VERSION 5.8 ;
BUSBITCHARS "[]" ;
DIVIDERCHAR "/" ;
UNITS
    DATABASE MICRONS 1000 ;
END UNITS

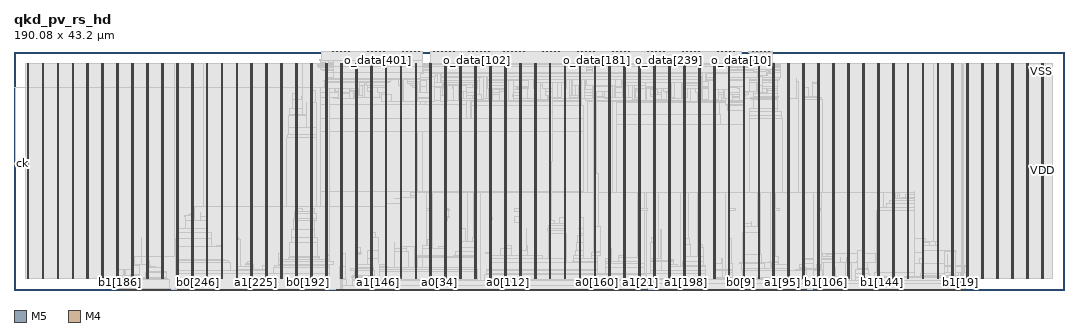
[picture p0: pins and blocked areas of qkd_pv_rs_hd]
MACRO qkd_pv_rs_hd
  FOREIGN qkd_pv_rs_hd 0 0 ;
  CLASS BLOCK ;
  SIZE 190.08 BY 43.2 ;
  PIN a0[0]
    DIRECTION INPUT ;
    USE SIGNAL ;
    PORT
      LAYER M5 ;
        RECT  58.32 0 58.344 0.084 ;
    END
  END a0[0]
  PIN a0[100]
    DIRECTION INPUT ;
    USE SIGNAL ;
    PORT
      LAYER M5 ;
        RECT  87.696 0 87.72 0.084 ;
    END
  END a0[100]
  PIN a0[101]
    DIRECTION INPUT ;
    USE SIGNAL ;
    PORT
      LAYER M5 ;
        RECT  87.84 0 87.864 0.084 ;
    END
  END a0[101]
  PIN a0[102]
    DIRECTION INPUT ;
    USE SIGNAL ;
    PORT
      LAYER M5 ;
        RECT  87.984 0 88.008 0.084 ;
    END
  END a0[102]
  PIN a0[103]
    DIRECTION INPUT ;
    USE SIGNAL ;
    PORT
      LAYER M5 ;
        RECT  88.128 0 88.152 0.084 ;
    END
  END a0[103]
  PIN a0[104]
    DIRECTION INPUT ;
    USE SIGNAL ;
    PORT
      LAYER M5 ;
        RECT  88.272 0 88.296 0.084 ;
    END
  END a0[104]
  PIN a0[105]
    DIRECTION INPUT ;
    USE SIGNAL ;
    PORT
      LAYER M5 ;
        RECT  88.416 0 88.44 0.084 ;
    END
  END a0[105]
  PIN a0[106]
    DIRECTION INPUT ;
    USE SIGNAL ;
    PORT
      LAYER M5 ;
        RECT  88.56 0 88.584 0.084 ;
    END
  END a0[106]
  PIN a0[107]
    DIRECTION INPUT ;
    USE SIGNAL ;
    PORT
      LAYER M5 ;
        RECT  88.704 0 88.728 0.084 ;
    END
  END a0[107]
  PIN a0[108]
    DIRECTION INPUT ;
    USE SIGNAL ;
    PORT
      LAYER M5 ;
        RECT  88.848 0 88.872 0.084 ;
    END
  END a0[108]
  PIN a0[109]
    DIRECTION INPUT ;
    USE SIGNAL ;
    PORT
      LAYER M5 ;
        RECT  88.992 0 89.016 0.084 ;
    END
  END a0[109]
  PIN a0[10]
    DIRECTION INPUT ;
    USE SIGNAL ;
    PORT
      LAYER M5 ;
        RECT  59.76 0 59.784 0.084 ;
    END
  END a0[10]
  PIN a0[110]
    DIRECTION INPUT ;
    USE SIGNAL ;
    PORT
      LAYER M5 ;
        RECT  89.136 0 89.16 0.084 ;
    END
  END a0[110]
  PIN a0[111]
    DIRECTION INPUT ;
    USE SIGNAL ;
    PORT
      LAYER M5 ;
        RECT  89.28 0 89.304 0.084 ;
    END
  END a0[111]
  PIN a0[112]
    DIRECTION INPUT ;
    USE SIGNAL ;
    PORT
      LAYER M5 ;
        RECT  89.424 0 89.448 0.084 ;
    END
  END a0[112]
  PIN a0[113]
    DIRECTION INPUT ;
    USE SIGNAL ;
    PORT
      LAYER M5 ;
        RECT  89.568 0 89.592 0.084 ;
    END
  END a0[113]
  PIN a0[114]
    DIRECTION INPUT ;
    USE SIGNAL ;
    PORT
      LAYER M5 ;
        RECT  89.712 0 89.736 0.084 ;
    END
  END a0[114]
  PIN a0[115]
    DIRECTION INPUT ;
    USE SIGNAL ;
    PORT
      LAYER M5 ;
        RECT  89.856 0 89.88 0.084 ;
    END
  END a0[115]
  PIN a0[116]
    DIRECTION INPUT ;
    USE SIGNAL ;
    PORT
      LAYER M5 ;
        RECT  90 0 90.024 0.084 ;
    END
  END a0[116]
  PIN a0[117]
    DIRECTION INPUT ;
    USE SIGNAL ;
    PORT
      LAYER M5 ;
        RECT  90.144 0 90.168 0.084 ;
    END
  END a0[117]
  PIN a0[118]
    DIRECTION INPUT ;
    USE SIGNAL ;
    PORT
      LAYER M5 ;
        RECT  90.288 0 90.312 0.084 ;
    END
  END a0[118]
  PIN a0[119]
    DIRECTION INPUT ;
    USE SIGNAL ;
    PORT
      LAYER M5 ;
        RECT  90.432 0 90.456 0.084 ;
    END
  END a0[119]
  PIN a0[11]
    DIRECTION INPUT ;
    USE SIGNAL ;
    PORT
      LAYER M5 ;
        RECT  59.904 0 59.928 0.084 ;
    END
  END a0[11]
  PIN a0[120]
    DIRECTION INPUT ;
    USE SIGNAL ;
    PORT
      LAYER M5 ;
        RECT  90.576 0 90.6 0.084 ;
    END
  END a0[120]
  PIN a0[121]
    DIRECTION INPUT ;
    USE SIGNAL ;
    PORT
      LAYER M5 ;
        RECT  90.72 0 90.744 0.084 ;
    END
  END a0[121]
  PIN a0[122]
    DIRECTION INPUT ;
    USE SIGNAL ;
    PORT
      LAYER M5 ;
        RECT  90.864 0 90.888 0.084 ;
    END
  END a0[122]
  PIN a0[123]
    DIRECTION INPUT ;
    USE SIGNAL ;
    PORT
      LAYER M5 ;
        RECT  91.008 0 91.032 0.084 ;
    END
  END a0[123]
  PIN a0[124]
    DIRECTION INPUT ;
    USE SIGNAL ;
    PORT
      LAYER M5 ;
        RECT  91.152 0 91.176 0.084 ;
    END
  END a0[124]
  PIN a0[125]
    DIRECTION INPUT ;
    USE SIGNAL ;
    PORT
      LAYER M5 ;
        RECT  91.296 0 91.32 0.084 ;
    END
  END a0[125]
  PIN a0[126]
    DIRECTION INPUT ;
    USE SIGNAL ;
    PORT
      LAYER M5 ;
        RECT  91.44 0 91.464 0.084 ;
    END
  END a0[126]
  PIN a0[127]
    DIRECTION INPUT ;
    USE SIGNAL ;
    PORT
      LAYER M5 ;
        RECT  91.584 0 91.608 0.084 ;
    END
  END a0[127]
  PIN a0[128]
    DIRECTION INPUT ;
    USE SIGNAL ;
    PORT
      LAYER M5 ;
        RECT  91.728 0 91.752 0.084 ;
    END
  END a0[128]
  PIN a0[129]
    DIRECTION INPUT ;
    USE SIGNAL ;
    PORT
      LAYER M5 ;
        RECT  91.872 0 91.896 0.084 ;
    END
  END a0[129]
  PIN a0[12]
    DIRECTION INPUT ;
    USE SIGNAL ;
    PORT
      LAYER M5 ;
        RECT  60.048 0 60.072 0.084 ;
    END
  END a0[12]
  PIN a0[130]
    DIRECTION INPUT ;
    USE SIGNAL ;
    PORT
      LAYER M5 ;
        RECT  92.016 0 92.04 0.084 ;
    END
  END a0[130]
  PIN a0[131]
    DIRECTION INPUT ;
    USE SIGNAL ;
    PORT
      LAYER M5 ;
        RECT  92.16 0 92.184 0.084 ;
    END
  END a0[131]
  PIN a0[132]
    DIRECTION INPUT ;
    USE SIGNAL ;
    PORT
      LAYER M5 ;
        RECT  92.304 0 92.328 0.084 ;
    END
  END a0[132]
  PIN a0[133]
    DIRECTION INPUT ;
    USE SIGNAL ;
    PORT
      LAYER M5 ;
        RECT  92.448 0 92.472 0.084 ;
    END
  END a0[133]
  PIN a0[134]
    DIRECTION INPUT ;
    USE SIGNAL ;
    PORT
      LAYER M5 ;
        RECT  92.592 0 92.616 0.084 ;
    END
  END a0[134]
  PIN a0[135]
    DIRECTION INPUT ;
    USE SIGNAL ;
    PORT
      LAYER M5 ;
        RECT  92.736 0 92.76 0.084 ;
    END
  END a0[135]
  PIN a0[136]
    DIRECTION INPUT ;
    USE SIGNAL ;
    PORT
      LAYER M5 ;
        RECT  92.88 0 92.904 0.084 ;
    END
  END a0[136]
  PIN a0[137]
    DIRECTION INPUT ;
    USE SIGNAL ;
    PORT
      LAYER M5 ;
        RECT  93.024 0 93.048 0.084 ;
    END
  END a0[137]
  PIN a0[138]
    DIRECTION INPUT ;
    USE SIGNAL ;
    PORT
      LAYER M5 ;
        RECT  93.168 0 93.192 0.084 ;
    END
  END a0[138]
  PIN a0[139]
    DIRECTION INPUT ;
    USE SIGNAL ;
    PORT
      LAYER M5 ;
        RECT  93.312 0 93.336 0.084 ;
    END
  END a0[139]
  PIN a0[13]
    DIRECTION INPUT ;
    USE SIGNAL ;
    PORT
      LAYER M5 ;
        RECT  60.192 0 60.216 0.084 ;
    END
  END a0[13]
  PIN a0[140]
    DIRECTION INPUT ;
    USE SIGNAL ;
    PORT
      LAYER M5 ;
        RECT  93.456 0 93.48 0.084 ;
    END
  END a0[140]
  PIN a0[141]
    DIRECTION INPUT ;
    USE SIGNAL ;
    PORT
      LAYER M5 ;
        RECT  93.6 0 93.624 0.084 ;
    END
  END a0[141]
  PIN a0[142]
    DIRECTION INPUT ;
    USE SIGNAL ;
    PORT
      LAYER M5 ;
        RECT  93.744 0 93.768 0.084 ;
    END
  END a0[142]
  PIN a0[143]
    DIRECTION INPUT ;
    USE SIGNAL ;
    PORT
      LAYER M5 ;
        RECT  93.888 0 93.912 0.084 ;
    END
  END a0[143]
  PIN a0[144]
    DIRECTION INPUT ;
    USE SIGNAL ;
    PORT
      LAYER M5 ;
        RECT  94.032 0 94.056 0.084 ;
    END
  END a0[144]
  PIN a0[145]
    DIRECTION INPUT ;
    USE SIGNAL ;
    PORT
      LAYER M5 ;
        RECT  94.176 0 94.2 0.084 ;
    END
  END a0[145]
  PIN a0[146]
    DIRECTION INPUT ;
    USE SIGNAL ;
    PORT
      LAYER M5 ;
        RECT  94.32 0 94.344 0.084 ;
    END
  END a0[146]
  PIN a0[147]
    DIRECTION INPUT ;
    USE SIGNAL ;
    PORT
      LAYER M5 ;
        RECT  94.464 0 94.488 0.084 ;
    END
  END a0[147]
  PIN a0[148]
    DIRECTION INPUT ;
    USE SIGNAL ;
    PORT
      LAYER M5 ;
        RECT  94.608 0 94.632 0.084 ;
    END
  END a0[148]
  PIN a0[149]
    DIRECTION INPUT ;
    USE SIGNAL ;
    PORT
      LAYER M5 ;
        RECT  94.752 0 94.776 0.084 ;
    END
  END a0[149]
  PIN a0[14]
    DIRECTION INPUT ;
    USE SIGNAL ;
    PORT
      LAYER M5 ;
        RECT  60.336 0 60.36 0.084 ;
    END
  END a0[14]
  PIN a0[150]
    DIRECTION INPUT ;
    USE SIGNAL ;
    PORT
      LAYER M5 ;
        RECT  94.896 0 94.92 0.084 ;
    END
  END a0[150]
  PIN a0[151]
    DIRECTION INPUT ;
    USE SIGNAL ;
    PORT
      LAYER M5 ;
        RECT  95.04 0 95.064 0.084 ;
    END
  END a0[151]
  PIN a0[152]
    DIRECTION INPUT ;
    USE SIGNAL ;
    PORT
      LAYER M5 ;
        RECT  95.184 0 95.208 0.084 ;
    END
  END a0[152]
  PIN a0[153]
    DIRECTION INPUT ;
    USE SIGNAL ;
    PORT
      LAYER M5 ;
        RECT  95.328 0 95.352 0.084 ;
    END
  END a0[153]
  PIN a0[154]
    DIRECTION INPUT ;
    USE SIGNAL ;
    PORT
      LAYER M5 ;
        RECT  95.472 0 95.496 0.084 ;
    END
  END a0[154]
  PIN a0[155]
    DIRECTION INPUT ;
    USE SIGNAL ;
    PORT
      LAYER M5 ;
        RECT  95.616 0 95.64 0.084 ;
    END
  END a0[155]
  PIN a0[156]
    DIRECTION INPUT ;
    USE SIGNAL ;
    PORT
      LAYER M5 ;
        RECT  95.76 0 95.784 0.084 ;
    END
  END a0[156]
  PIN a0[157]
    DIRECTION INPUT ;
    USE SIGNAL ;
    PORT
      LAYER M5 ;
        RECT  95.904 0 95.928 0.084 ;
    END
  END a0[157]
  PIN a0[158]
    DIRECTION INPUT ;
    USE SIGNAL ;
    PORT
      LAYER M5 ;
        RECT  96.048 0 96.072 0.084 ;
    END
  END a0[158]
  PIN a0[159]
    DIRECTION INPUT ;
    USE SIGNAL ;
    PORT
      LAYER M5 ;
        RECT  96.192 0 96.216 0.084 ;
    END
  END a0[159]
  PIN a0[15]
    DIRECTION INPUT ;
    USE SIGNAL ;
    PORT
      LAYER M5 ;
        RECT  60.48 0 60.504 0.084 ;
    END
  END a0[15]
  PIN a0[160]
    DIRECTION INPUT ;
    USE SIGNAL ;
    PORT
      LAYER M5 ;
        RECT  105.552 0 105.576 0.084 ;
    END
  END a0[160]
  PIN a0[161]
    DIRECTION INPUT ;
    USE SIGNAL ;
    PORT
      LAYER M5 ;
        RECT  105.696 0 105.72 0.084 ;
    END
  END a0[161]
  PIN a0[162]
    DIRECTION INPUT ;
    USE SIGNAL ;
    PORT
      LAYER M5 ;
        RECT  105.84 0 105.864 0.084 ;
    END
  END a0[162]
  PIN a0[163]
    DIRECTION INPUT ;
    USE SIGNAL ;
    PORT
      LAYER M5 ;
        RECT  105.984 0 106.008 0.084 ;
    END
  END a0[163]
  PIN a0[164]
    DIRECTION INPUT ;
    USE SIGNAL ;
    PORT
      LAYER M5 ;
        RECT  106.128 0 106.152 0.084 ;
    END
  END a0[164]
  PIN a0[165]
    DIRECTION INPUT ;
    USE SIGNAL ;
    PORT
      LAYER M5 ;
        RECT  106.272 0 106.296 0.084 ;
    END
  END a0[165]
  PIN a0[166]
    DIRECTION INPUT ;
    USE SIGNAL ;
    PORT
      LAYER M5 ;
        RECT  106.416 0 106.44 0.084 ;
    END
  END a0[166]
  PIN a0[167]
    DIRECTION INPUT ;
    USE SIGNAL ;
    PORT
      LAYER M5 ;
        RECT  106.56 0 106.584 0.084 ;
    END
  END a0[167]
  PIN a0[168]
    DIRECTION INPUT ;
    USE SIGNAL ;
    PORT
      LAYER M5 ;
        RECT  106.704 0 106.728 0.084 ;
    END
  END a0[168]
  PIN a0[169]
    DIRECTION INPUT ;
    USE SIGNAL ;
    PORT
      LAYER M5 ;
        RECT  106.848 0 106.872 0.084 ;
    END
  END a0[169]
  PIN a0[16]
    DIRECTION INPUT ;
    USE SIGNAL ;
    PORT
      LAYER M5 ;
        RECT  60.624 0 60.648 0.084 ;
    END
  END a0[16]
  PIN a0[170]
    DIRECTION INPUT ;
    USE SIGNAL ;
    PORT
      LAYER M5 ;
        RECT  106.992 0 107.016 0.084 ;
    END
  END a0[170]
  PIN a0[171]
    DIRECTION INPUT ;
    USE SIGNAL ;
    PORT
      LAYER M5 ;
        RECT  107.136 0 107.16 0.084 ;
    END
  END a0[171]
  PIN a0[172]
    DIRECTION INPUT ;
    USE SIGNAL ;
    PORT
      LAYER M5 ;
        RECT  107.28 0 107.304 0.084 ;
    END
  END a0[172]
  PIN a0[173]
    DIRECTION INPUT ;
    USE SIGNAL ;
    PORT
      LAYER M5 ;
        RECT  107.424 0 107.448 0.084 ;
    END
  END a0[173]
  PIN a0[174]
    DIRECTION INPUT ;
    USE SIGNAL ;
    PORT
      LAYER M5 ;
        RECT  107.568 0 107.592 0.084 ;
    END
  END a0[174]
  PIN a0[175]
    DIRECTION INPUT ;
    USE SIGNAL ;
    PORT
      LAYER M5 ;
        RECT  107.712 0 107.736 0.084 ;
    END
  END a0[175]
  PIN a0[176]
    DIRECTION INPUT ;
    USE SIGNAL ;
    PORT
      LAYER M5 ;
        RECT  107.856 0 107.88 0.084 ;
    END
  END a0[176]
  PIN a0[177]
    DIRECTION INPUT ;
    USE SIGNAL ;
    PORT
      LAYER M5 ;
        RECT  108 0 108.024 0.084 ;
    END
  END a0[177]
  PIN a0[178]
    DIRECTION INPUT ;
    USE SIGNAL ;
    PORT
      LAYER M5 ;
        RECT  108.144 0 108.168 0.084 ;
    END
  END a0[178]
  PIN a0[179]
    DIRECTION INPUT ;
    USE SIGNAL ;
    PORT
      LAYER M5 ;
        RECT  108.288 0 108.312 0.084 ;
    END
  END a0[179]
  PIN a0[17]
    DIRECTION INPUT ;
    USE SIGNAL ;
    PORT
      LAYER M5 ;
        RECT  60.768 0 60.792 0.084 ;
    END
  END a0[17]
  PIN a0[180]
    DIRECTION INPUT ;
    USE SIGNAL ;
    PORT
      LAYER M5 ;
        RECT  108.432 0 108.456 0.084 ;
    END
  END a0[180]
  PIN a0[181]
    DIRECTION INPUT ;
    USE SIGNAL ;
    PORT
      LAYER M5 ;
        RECT  108.576 0 108.6 0.084 ;
    END
  END a0[181]
  PIN a0[182]
    DIRECTION INPUT ;
    USE SIGNAL ;
    PORT
      LAYER M5 ;
        RECT  108.72 0 108.744 0.084 ;
    END
  END a0[182]
  PIN a0[183]
    DIRECTION INPUT ;
    USE SIGNAL ;
    PORT
      LAYER M5 ;
        RECT  108.864 0 108.888 0.084 ;
    END
  END a0[183]
  PIN a0[184]
    DIRECTION INPUT ;
    USE SIGNAL ;
    PORT
      LAYER M5 ;
        RECT  109.008 0 109.032 0.084 ;
    END
  END a0[184]
  PIN a0[185]
    DIRECTION INPUT ;
    USE SIGNAL ;
    PORT
      LAYER M5 ;
        RECT  109.152 0 109.176 0.084 ;
    END
  END a0[185]
  PIN a0[186]
    DIRECTION INPUT ;
    USE SIGNAL ;
    PORT
      LAYER M5 ;
        RECT  109.296 0 109.32 0.084 ;
    END
  END a0[186]
  PIN a0[187]
    DIRECTION INPUT ;
    USE SIGNAL ;
    PORT
      LAYER M5 ;
        RECT  109.44 0 109.464 0.084 ;
    END
  END a0[187]
  PIN a0[188]
    DIRECTION INPUT ;
    USE SIGNAL ;
    PORT
      LAYER M5 ;
        RECT  109.584 0 109.608 0.084 ;
    END
  END a0[188]
  PIN a0[189]
    DIRECTION INPUT ;
    USE SIGNAL ;
    PORT
      LAYER M5 ;
        RECT  109.728 0 109.752 0.084 ;
    END
  END a0[189]
  PIN a0[18]
    DIRECTION INPUT ;
    USE SIGNAL ;
    PORT
      LAYER M5 ;
        RECT  60.912 0 60.936 0.084 ;
    END
  END a0[18]
  PIN a0[190]
    DIRECTION INPUT ;
    USE SIGNAL ;
    PORT
      LAYER M5 ;
        RECT  109.872 0 109.896 0.084 ;
    END
  END a0[190]
  PIN a0[191]
    DIRECTION INPUT ;
    USE SIGNAL ;
    PORT
      LAYER M5 ;
        RECT  110.016 0 110.04 0.084 ;
    END
  END a0[191]
  PIN a0[192]
    DIRECTION INPUT ;
    USE SIGNAL ;
    PORT
      LAYER M5 ;
        RECT  100.944 0 100.968 0.084 ;
    END
  END a0[192]
  PIN a0[193]
    DIRECTION INPUT ;
    USE SIGNAL ;
    PORT
      LAYER M5 ;
        RECT  101.088 0 101.112 0.084 ;
    END
  END a0[193]
  PIN a0[194]
    DIRECTION INPUT ;
    USE SIGNAL ;
    PORT
      LAYER M5 ;
        RECT  101.232 0 101.256 0.084 ;
    END
  END a0[194]
  PIN a0[195]
    DIRECTION INPUT ;
    USE SIGNAL ;
    PORT
      LAYER M5 ;
        RECT  101.376 0 101.4 0.084 ;
    END
  END a0[195]
  PIN a0[196]
    DIRECTION INPUT ;
    USE SIGNAL ;
    PORT
      LAYER M5 ;
        RECT  101.52 0 101.544 0.084 ;
    END
  END a0[196]
  PIN a0[197]
    DIRECTION INPUT ;
    USE SIGNAL ;
    PORT
      LAYER M5 ;
        RECT  101.664 0 101.688 0.084 ;
    END
  END a0[197]
  PIN a0[198]
    DIRECTION INPUT ;
    USE SIGNAL ;
    PORT
      LAYER M5 ;
        RECT  101.808 0 101.832 0.084 ;
    END
  END a0[198]
  PIN a0[199]
    DIRECTION INPUT ;
    USE SIGNAL ;
    PORT
      LAYER M5 ;
        RECT  101.952 0 101.976 0.084 ;
    END
  END a0[199]
  PIN a0[19]
    DIRECTION INPUT ;
    USE SIGNAL ;
    PORT
      LAYER M5 ;
        RECT  61.056 0 61.08 0.084 ;
    END
  END a0[19]
  PIN a0[1]
    DIRECTION INPUT ;
    USE SIGNAL ;
    PORT
      LAYER M5 ;
        RECT  58.464 0 58.488 0.084 ;
    END
  END a0[1]
  PIN a0[200]
    DIRECTION INPUT ;
    USE SIGNAL ;
    PORT
      LAYER M5 ;
        RECT  102.096 0 102.12 0.084 ;
    END
  END a0[200]
  PIN a0[201]
    DIRECTION INPUT ;
    USE SIGNAL ;
    PORT
      LAYER M5 ;
        RECT  102.24 0 102.264 0.084 ;
    END
  END a0[201]
  PIN a0[202]
    DIRECTION INPUT ;
    USE SIGNAL ;
    PORT
      LAYER M5 ;
        RECT  102.384 0 102.408 0.084 ;
    END
  END a0[202]
  PIN a0[203]
    DIRECTION INPUT ;
    USE SIGNAL ;
    PORT
      LAYER M5 ;
        RECT  102.528 0 102.552 0.084 ;
    END
  END a0[203]
  PIN a0[204]
    DIRECTION INPUT ;
    USE SIGNAL ;
    PORT
      LAYER M5 ;
        RECT  102.672 0 102.696 0.084 ;
    END
  END a0[204]
  PIN a0[205]
    DIRECTION INPUT ;
    USE SIGNAL ;
    PORT
      LAYER M5 ;
        RECT  102.816 0 102.84 0.084 ;
    END
  END a0[205]
  PIN a0[206]
    DIRECTION INPUT ;
    USE SIGNAL ;
    PORT
      LAYER M5 ;
        RECT  102.96 0 102.984 0.084 ;
    END
  END a0[206]
  PIN a0[207]
    DIRECTION INPUT ;
    USE SIGNAL ;
    PORT
      LAYER M5 ;
        RECT  103.104 0 103.128 0.084 ;
    END
  END a0[207]
  PIN a0[208]
    DIRECTION INPUT ;
    USE SIGNAL ;
    PORT
      LAYER M5 ;
        RECT  103.248 0 103.272 0.084 ;
    END
  END a0[208]
  PIN a0[209]
    DIRECTION INPUT ;
    USE SIGNAL ;
    PORT
      LAYER M5 ;
        RECT  103.392 0 103.416 0.084 ;
    END
  END a0[209]
  PIN a0[20]
    DIRECTION INPUT ;
    USE SIGNAL ;
    PORT
      LAYER M5 ;
        RECT  61.2 0 61.224 0.084 ;
    END
  END a0[20]
  PIN a0[210]
    DIRECTION INPUT ;
    USE SIGNAL ;
    PORT
      LAYER M5 ;
        RECT  103.536 0 103.56 0.084 ;
    END
  END a0[210]
  PIN a0[211]
    DIRECTION INPUT ;
    USE SIGNAL ;
    PORT
      LAYER M5 ;
        RECT  103.68 0 103.704 0.084 ;
    END
  END a0[211]
  PIN a0[212]
    DIRECTION INPUT ;
    USE SIGNAL ;
    PORT
      LAYER M5 ;
        RECT  103.824 0 103.848 0.084 ;
    END
  END a0[212]
  PIN a0[213]
    DIRECTION INPUT ;
    USE SIGNAL ;
    PORT
      LAYER M5 ;
        RECT  103.968 0 103.992 0.084 ;
    END
  END a0[213]
  PIN a0[214]
    DIRECTION INPUT ;
    USE SIGNAL ;
    PORT
      LAYER M5 ;
        RECT  104.112 0 104.136 0.084 ;
    END
  END a0[214]
  PIN a0[215]
    DIRECTION INPUT ;
    USE SIGNAL ;
    PORT
      LAYER M5 ;
        RECT  104.256 0 104.28 0.084 ;
    END
  END a0[215]
  PIN a0[216]
    DIRECTION INPUT ;
    USE SIGNAL ;
    PORT
      LAYER M5 ;
        RECT  104.4 0 104.424 0.084 ;
    END
  END a0[216]
  PIN a0[217]
    DIRECTION INPUT ;
    USE SIGNAL ;
    PORT
      LAYER M5 ;
        RECT  104.544 0 104.568 0.084 ;
    END
  END a0[217]
  PIN a0[218]
    DIRECTION INPUT ;
    USE SIGNAL ;
    PORT
      LAYER M5 ;
        RECT  104.688 0 104.712 0.084 ;
    END
  END a0[218]
  PIN a0[219]
    DIRECTION INPUT ;
    USE SIGNAL ;
    PORT
      LAYER M5 ;
        RECT  104.832 0 104.856 0.084 ;
    END
  END a0[219]
  PIN a0[21]
    DIRECTION INPUT ;
    USE SIGNAL ;
    PORT
      LAYER M5 ;
        RECT  61.344 0 61.368 0.084 ;
    END
  END a0[21]
  PIN a0[220]
    DIRECTION INPUT ;
    USE SIGNAL ;
    PORT
      LAYER M5 ;
        RECT  104.976 0 105 0.084 ;
    END
  END a0[220]
  PIN a0[221]
    DIRECTION INPUT ;
    USE SIGNAL ;
    PORT
      LAYER M5 ;
        RECT  105.12 0 105.144 0.084 ;
    END
  END a0[221]
  PIN a0[222]
    DIRECTION INPUT ;
    USE SIGNAL ;
    PORT
      LAYER M5 ;
        RECT  105.264 0 105.288 0.084 ;
    END
  END a0[222]
  PIN a0[223]
    DIRECTION INPUT ;
    USE SIGNAL ;
    PORT
      LAYER M5 ;
        RECT  105.408 0 105.432 0.084 ;
    END
  END a0[223]
  PIN a0[224]
    DIRECTION INPUT ;
    USE SIGNAL ;
    PORT
      LAYER M5 ;
        RECT  96.336 0 96.36 0.084 ;
    END
  END a0[224]
  PIN a0[225]
    DIRECTION INPUT ;
    USE SIGNAL ;
    PORT
      LAYER M5 ;
        RECT  96.48 0 96.504 0.084 ;
    END
  END a0[225]
  PIN a0[226]
    DIRECTION INPUT ;
    USE SIGNAL ;
    PORT
      LAYER M5 ;
        RECT  96.624 0 96.648 0.084 ;
    END
  END a0[226]
  PIN a0[227]
    DIRECTION INPUT ;
    USE SIGNAL ;
    PORT
      LAYER M5 ;
        RECT  96.768 0 96.792 0.084 ;
    END
  END a0[227]
  PIN a0[228]
    DIRECTION INPUT ;
    USE SIGNAL ;
    PORT
      LAYER M5 ;
        RECT  96.912 0 96.936 0.084 ;
    END
  END a0[228]
  PIN a0[229]
    DIRECTION INPUT ;
    USE SIGNAL ;
    PORT
      LAYER M5 ;
        RECT  97.056 0 97.08 0.084 ;
    END
  END a0[229]
  PIN a0[22]
    DIRECTION INPUT ;
    USE SIGNAL ;
    PORT
      LAYER M5 ;
        RECT  61.488 0 61.512 0.084 ;
    END
  END a0[22]
  PIN a0[230]
    DIRECTION INPUT ;
    USE SIGNAL ;
    PORT
      LAYER M5 ;
        RECT  97.2 0 97.224 0.084 ;
    END
  END a0[230]
  PIN a0[231]
    DIRECTION INPUT ;
    USE SIGNAL ;
    PORT
      LAYER M5 ;
        RECT  97.344 0 97.368 0.084 ;
    END
  END a0[231]
  PIN a0[232]
    DIRECTION INPUT ;
    USE SIGNAL ;
    PORT
      LAYER M5 ;
        RECT  97.488 0 97.512 0.084 ;
    END
  END a0[232]
  PIN a0[233]
    DIRECTION INPUT ;
    USE SIGNAL ;
    PORT
      LAYER M5 ;
        RECT  97.632 0 97.656 0.084 ;
    END
  END a0[233]
  PIN a0[234]
    DIRECTION INPUT ;
    USE SIGNAL ;
    PORT
      LAYER M5 ;
        RECT  97.776 0 97.8 0.084 ;
    END
  END a0[234]
  PIN a0[235]
    DIRECTION INPUT ;
    USE SIGNAL ;
    PORT
      LAYER M5 ;
        RECT  97.92 0 97.944 0.084 ;
    END
  END a0[235]
  PIN a0[236]
    DIRECTION INPUT ;
    USE SIGNAL ;
    PORT
      LAYER M5 ;
        RECT  98.064 0 98.088 0.084 ;
    END
  END a0[236]
  PIN a0[237]
    DIRECTION INPUT ;
    USE SIGNAL ;
    PORT
      LAYER M5 ;
        RECT  98.208 0 98.232 0.084 ;
    END
  END a0[237]
  PIN a0[238]
    DIRECTION INPUT ;
    USE SIGNAL ;
    PORT
      LAYER M5 ;
        RECT  98.352 0 98.376 0.084 ;
    END
  END a0[238]
  PIN a0[239]
    DIRECTION INPUT ;
    USE SIGNAL ;
    PORT
      LAYER M5 ;
        RECT  98.496 0 98.52 0.084 ;
    END
  END a0[239]
  PIN a0[23]
    DIRECTION INPUT ;
    USE SIGNAL ;
    PORT
      LAYER M5 ;
        RECT  61.632 0 61.656 0.084 ;
    END
  END a0[23]
  PIN a0[240]
    DIRECTION INPUT ;
    USE SIGNAL ;
    PORT
      LAYER M5 ;
        RECT  98.64 0 98.664 0.084 ;
    END
  END a0[240]
  PIN a0[241]
    DIRECTION INPUT ;
    USE SIGNAL ;
    PORT
      LAYER M5 ;
        RECT  98.784 0 98.808 0.084 ;
    END
  END a0[241]
  PIN a0[242]
    DIRECTION INPUT ;
    USE SIGNAL ;
    PORT
      LAYER M5 ;
        RECT  98.928 0 98.952 0.084 ;
    END
  END a0[242]
  PIN a0[243]
    DIRECTION INPUT ;
    USE SIGNAL ;
    PORT
      LAYER M5 ;
        RECT  99.072 0 99.096 0.084 ;
    END
  END a0[243]
  PIN a0[244]
    DIRECTION INPUT ;
    USE SIGNAL ;
    PORT
      LAYER M5 ;
        RECT  99.216 0 99.24 0.084 ;
    END
  END a0[244]
  PIN a0[245]
    DIRECTION INPUT ;
    USE SIGNAL ;
    PORT
      LAYER M5 ;
        RECT  99.36 0 99.384 0.084 ;
    END
  END a0[245]
  PIN a0[246]
    DIRECTION INPUT ;
    USE SIGNAL ;
    PORT
      LAYER M5 ;
        RECT  99.504 0 99.528 0.084 ;
    END
  END a0[246]
  PIN a0[247]
    DIRECTION INPUT ;
    USE SIGNAL ;
    PORT
      LAYER M5 ;
        RECT  99.648 0 99.672 0.084 ;
    END
  END a0[247]
  PIN a0[248]
    DIRECTION INPUT ;
    USE SIGNAL ;
    PORT
      LAYER M5 ;
        RECT  99.792 0 99.816 0.084 ;
    END
  END a0[248]
  PIN a0[249]
    DIRECTION INPUT ;
    USE SIGNAL ;
    PORT
      LAYER M5 ;
        RECT  99.936 0 99.96 0.084 ;
    END
  END a0[249]
  PIN a0[24]
    DIRECTION INPUT ;
    USE SIGNAL ;
    PORT
      LAYER M5 ;
        RECT  61.776 0 61.8 0.084 ;
    END
  END a0[24]
  PIN a0[250]
    DIRECTION INPUT ;
    USE SIGNAL ;
    PORT
      LAYER M5 ;
        RECT  100.08 0 100.104 0.084 ;
    END
  END a0[250]
  PIN a0[251]
    DIRECTION INPUT ;
    USE SIGNAL ;
    PORT
      LAYER M5 ;
        RECT  100.224 0 100.248 0.084 ;
    END
  END a0[251]
  PIN a0[252]
    DIRECTION INPUT ;
    USE SIGNAL ;
    PORT
      LAYER M5 ;
        RECT  100.368 0 100.392 0.084 ;
    END
  END a0[252]
  PIN a0[253]
    DIRECTION INPUT ;
    USE SIGNAL ;
    PORT
      LAYER M5 ;
        RECT  100.512 0 100.536 0.084 ;
    END
  END a0[253]
  PIN a0[254]
    DIRECTION INPUT ;
    USE SIGNAL ;
    PORT
      LAYER M5 ;
        RECT  100.656 0 100.68 0.084 ;
    END
  END a0[254]
  PIN a0[255]
    DIRECTION INPUT ;
    USE SIGNAL ;
    PORT
      LAYER M5 ;
        RECT  100.8 0 100.824 0.084 ;
    END
  END a0[255]
  PIN a0[256]
    DIRECTION INPUT ;
    USE SIGNAL ;
    PORT
      LAYER M5 ;
        RECT  110.16 0 110.184 0.084 ;
    END
  END a0[256]
  PIN a0[257]
    DIRECTION INPUT ;
    USE SIGNAL ;
    PORT
      LAYER M5 ;
        RECT  110.304 0 110.328 0.084 ;
    END
  END a0[257]
  PIN a0[25]
    DIRECTION INPUT ;
    USE SIGNAL ;
    PORT
      LAYER M5 ;
        RECT  61.92 0 61.944 0.084 ;
    END
  END a0[25]
  PIN a0[26]
    DIRECTION INPUT ;
    USE SIGNAL ;
    PORT
      LAYER M5 ;
        RECT  62.064 0 62.088 0.084 ;
    END
  END a0[26]
  PIN a0[27]
    DIRECTION INPUT ;
    USE SIGNAL ;
    PORT
      LAYER M5 ;
        RECT  62.208 0 62.232 0.084 ;
    END
  END a0[27]
  PIN a0[28]
    DIRECTION INPUT ;
    USE SIGNAL ;
    PORT
      LAYER M5 ;
        RECT  62.352 0 62.376 0.084 ;
    END
  END a0[28]
  PIN a0[29]
    DIRECTION INPUT ;
    USE SIGNAL ;
    PORT
      LAYER M5 ;
        RECT  62.496 0 62.52 0.084 ;
    END
  END a0[29]
  PIN a0[2]
    DIRECTION INPUT ;
    USE SIGNAL ;
    PORT
      LAYER M5 ;
        RECT  58.608 0 58.632 0.084 ;
    END
  END a0[2]
  PIN a0[30]
    DIRECTION INPUT ;
    USE SIGNAL ;
    PORT
      LAYER M5 ;
        RECT  62.64 0 62.664 0.084 ;
    END
  END a0[30]
  PIN a0[31]
    DIRECTION INPUT ;
    USE SIGNAL ;
    PORT
      LAYER M5 ;
        RECT  62.784 0 62.808 0.084 ;
    END
  END a0[31]
  PIN a0[32]
    DIRECTION INPUT ;
    USE SIGNAL ;
    PORT
      LAYER M5 ;
        RECT  76.752 0 76.776 0.084 ;
    END
  END a0[32]
  PIN a0[33]
    DIRECTION INPUT ;
    USE SIGNAL ;
    PORT
      LAYER M5 ;
        RECT  76.896 0 76.92 0.084 ;
    END
  END a0[33]
  PIN a0[34]
    DIRECTION INPUT ;
    USE SIGNAL ;
    PORT
      LAYER M5 ;
        RECT  77.04 0 77.064 0.084 ;
    END
  END a0[34]
  PIN a0[35]
    DIRECTION INPUT ;
    USE SIGNAL ;
    PORT
      LAYER M5 ;
        RECT  77.184 0 77.208 0.084 ;
    END
  END a0[35]
  PIN a0[36]
    DIRECTION INPUT ;
    USE SIGNAL ;
    PORT
      LAYER M5 ;
        RECT  77.328 0 77.352 0.084 ;
    END
  END a0[36]
  PIN a0[37]
    DIRECTION INPUT ;
    USE SIGNAL ;
    PORT
      LAYER M5 ;
        RECT  77.472 0 77.496 0.084 ;
    END
  END a0[37]
  PIN a0[38]
    DIRECTION INPUT ;
    USE SIGNAL ;
    PORT
      LAYER M5 ;
        RECT  77.616 0 77.64 0.084 ;
    END
  END a0[38]
  PIN a0[39]
    DIRECTION INPUT ;
    USE SIGNAL ;
    PORT
      LAYER M5 ;
        RECT  77.76 0 77.784 0.084 ;
    END
  END a0[39]
  PIN a0[3]
    DIRECTION INPUT ;
    USE SIGNAL ;
    PORT
      LAYER M5 ;
        RECT  58.752 0 58.776 0.084 ;
    END
  END a0[3]
  PIN a0[40]
    DIRECTION INPUT ;
    USE SIGNAL ;
    PORT
      LAYER M5 ;
        RECT  77.904 0 77.928 0.084 ;
    END
  END a0[40]
  PIN a0[41]
    DIRECTION INPUT ;
    USE SIGNAL ;
    PORT
      LAYER M5 ;
        RECT  78.048 0 78.072 0.084 ;
    END
  END a0[41]
  PIN a0[42]
    DIRECTION INPUT ;
    USE SIGNAL ;
    PORT
      LAYER M5 ;
        RECT  78.192 0 78.216 0.084 ;
    END
  END a0[42]
  PIN a0[43]
    DIRECTION INPUT ;
    USE SIGNAL ;
    PORT
      LAYER M5 ;
        RECT  78.336 0 78.36 0.084 ;
    END
  END a0[43]
  PIN a0[44]
    DIRECTION INPUT ;
    USE SIGNAL ;
    PORT
      LAYER M5 ;
        RECT  78.48 0 78.504 0.084 ;
    END
  END a0[44]
  PIN a0[45]
    DIRECTION INPUT ;
    USE SIGNAL ;
    PORT
      LAYER M5 ;
        RECT  78.624 0 78.648 0.084 ;
    END
  END a0[45]
  PIN a0[46]
    DIRECTION INPUT ;
    USE SIGNAL ;
    PORT
      LAYER M5 ;
        RECT  78.768 0 78.792 0.084 ;
    END
  END a0[46]
  PIN a0[47]
    DIRECTION INPUT ;
    USE SIGNAL ;
    PORT
      LAYER M5 ;
        RECT  78.912 0 78.936 0.084 ;
    END
  END a0[47]
  PIN a0[48]
    DIRECTION INPUT ;
    USE SIGNAL ;
    PORT
      LAYER M5 ;
        RECT  79.056 0 79.08 0.084 ;
    END
  END a0[48]
  PIN a0[49]
    DIRECTION INPUT ;
    USE SIGNAL ;
    PORT
      LAYER M5 ;
        RECT  79.2 0 79.224 0.084 ;
    END
  END a0[49]
  PIN a0[4]
    DIRECTION INPUT ;
    USE SIGNAL ;
    PORT
      LAYER M5 ;
        RECT  58.896 0 58.92 0.084 ;
    END
  END a0[4]
  PIN a0[50]
    DIRECTION INPUT ;
    USE SIGNAL ;
    PORT
      LAYER M5 ;
        RECT  79.344 0 79.368 0.084 ;
    END
  END a0[50]
  PIN a0[51]
    DIRECTION INPUT ;
    USE SIGNAL ;
    PORT
      LAYER M5 ;
        RECT  79.488 0 79.512 0.084 ;
    END
  END a0[51]
  PIN a0[52]
    DIRECTION INPUT ;
    USE SIGNAL ;
    PORT
      LAYER M5 ;
        RECT  79.632 0 79.656 0.084 ;
    END
  END a0[52]
  PIN a0[53]
    DIRECTION INPUT ;
    USE SIGNAL ;
    PORT
      LAYER M5 ;
        RECT  79.776 0 79.8 0.084 ;
    END
  END a0[53]
  PIN a0[54]
    DIRECTION INPUT ;
    USE SIGNAL ;
    PORT
      LAYER M5 ;
        RECT  79.92 0 79.944 0.084 ;
    END
  END a0[54]
  PIN a0[55]
    DIRECTION INPUT ;
    USE SIGNAL ;
    PORT
      LAYER M5 ;
        RECT  80.064 0 80.088 0.084 ;
    END
  END a0[55]
  PIN a0[56]
    DIRECTION INPUT ;
    USE SIGNAL ;
    PORT
      LAYER M5 ;
        RECT  80.208 0 80.232 0.084 ;
    END
  END a0[56]
  PIN a0[57]
    DIRECTION INPUT ;
    USE SIGNAL ;
    PORT
      LAYER M5 ;
        RECT  80.352 0 80.376 0.084 ;
    END
  END a0[57]
  PIN a0[58]
    DIRECTION INPUT ;
    USE SIGNAL ;
    PORT
      LAYER M5 ;
        RECT  80.496 0 80.52 0.084 ;
    END
  END a0[58]
  PIN a0[59]
    DIRECTION INPUT ;
    USE SIGNAL ;
    PORT
      LAYER M5 ;
        RECT  80.64 0 80.664 0.084 ;
    END
  END a0[59]
  PIN a0[5]
    DIRECTION INPUT ;
    USE SIGNAL ;
    PORT
      LAYER M5 ;
        RECT  59.04 0 59.064 0.084 ;
    END
  END a0[5]
  PIN a0[60]
    DIRECTION INPUT ;
    USE SIGNAL ;
    PORT
      LAYER M5 ;
        RECT  80.784 0 80.808 0.084 ;
    END
  END a0[60]
  PIN a0[61]
    DIRECTION INPUT ;
    USE SIGNAL ;
    PORT
      LAYER M5 ;
        RECT  80.928 0 80.952 0.084 ;
    END
  END a0[61]
  PIN a0[62]
    DIRECTION INPUT ;
    USE SIGNAL ;
    PORT
      LAYER M5 ;
        RECT  81.072 0 81.096 0.084 ;
    END
  END a0[62]
  PIN a0[63]
    DIRECTION INPUT ;
    USE SIGNAL ;
    PORT
      LAYER M5 ;
        RECT  81.216 0 81.24 0.084 ;
    END
  END a0[63]
  PIN a0[64]
    DIRECTION INPUT ;
    USE SIGNAL ;
    PORT
      LAYER M5 ;
        RECT  72.144 0 72.168 0.084 ;
    END
  END a0[64]
  PIN a0[65]
    DIRECTION INPUT ;
    USE SIGNAL ;
    PORT
      LAYER M5 ;
        RECT  72.288 0 72.312 0.084 ;
    END
  END a0[65]
  PIN a0[66]
    DIRECTION INPUT ;
    USE SIGNAL ;
    PORT
      LAYER M5 ;
        RECT  72.432 0 72.456 0.084 ;
    END
  END a0[66]
  PIN a0[67]
    DIRECTION INPUT ;
    USE SIGNAL ;
    PORT
      LAYER M5 ;
        RECT  72.576 0 72.6 0.084 ;
    END
  END a0[67]
  PIN a0[68]
    DIRECTION INPUT ;
    USE SIGNAL ;
    PORT
      LAYER M5 ;
        RECT  72.72 0 72.744 0.084 ;
    END
  END a0[68]
  PIN a0[69]
    DIRECTION INPUT ;
    USE SIGNAL ;
    PORT
      LAYER M5 ;
        RECT  72.864 0 72.888 0.084 ;
    END
  END a0[69]
  PIN a0[6]
    DIRECTION INPUT ;
    USE SIGNAL ;
    PORT
      LAYER M5 ;
        RECT  59.184 0 59.208 0.084 ;
    END
  END a0[6]
  PIN a0[70]
    DIRECTION INPUT ;
    USE SIGNAL ;
    PORT
      LAYER M5 ;
        RECT  73.008 0 73.032 0.084 ;
    END
  END a0[70]
  PIN a0[71]
    DIRECTION INPUT ;
    USE SIGNAL ;
    PORT
      LAYER M5 ;
        RECT  73.152 0 73.176 0.084 ;
    END
  END a0[71]
  PIN a0[72]
    DIRECTION INPUT ;
    USE SIGNAL ;
    PORT
      LAYER M5 ;
        RECT  73.296 0 73.32 0.084 ;
    END
  END a0[72]
  PIN a0[73]
    DIRECTION INPUT ;
    USE SIGNAL ;
    PORT
      LAYER M5 ;
        RECT  73.44 0 73.464 0.084 ;
    END
  END a0[73]
  PIN a0[74]
    DIRECTION INPUT ;
    USE SIGNAL ;
    PORT
      LAYER M5 ;
        RECT  73.584 0 73.608 0.084 ;
    END
  END a0[74]
  PIN a0[75]
    DIRECTION INPUT ;
    USE SIGNAL ;
    PORT
      LAYER M5 ;
        RECT  73.728 0 73.752 0.084 ;
    END
  END a0[75]
  PIN a0[76]
    DIRECTION INPUT ;
    USE SIGNAL ;
    PORT
      LAYER M5 ;
        RECT  73.872 0 73.896 0.084 ;
    END
  END a0[76]
  PIN a0[77]
    DIRECTION INPUT ;
    USE SIGNAL ;
    PORT
      LAYER M5 ;
        RECT  74.016 0 74.04 0.084 ;
    END
  END a0[77]
  PIN a0[78]
    DIRECTION INPUT ;
    USE SIGNAL ;
    PORT
      LAYER M5 ;
        RECT  74.16 0 74.184 0.084 ;
    END
  END a0[78]
  PIN a0[79]
    DIRECTION INPUT ;
    USE SIGNAL ;
    PORT
      LAYER M5 ;
        RECT  74.304 0 74.328 0.084 ;
    END
  END a0[79]
  PIN a0[7]
    DIRECTION INPUT ;
    USE SIGNAL ;
    PORT
      LAYER M5 ;
        RECT  59.328 0 59.352 0.084 ;
    END
  END a0[7]
  PIN a0[80]
    DIRECTION INPUT ;
    USE SIGNAL ;
    PORT
      LAYER M5 ;
        RECT  74.448 0 74.472 0.084 ;
    END
  END a0[80]
  PIN a0[81]
    DIRECTION INPUT ;
    USE SIGNAL ;
    PORT
      LAYER M5 ;
        RECT  74.592 0 74.616 0.084 ;
    END
  END a0[81]
  PIN a0[82]
    DIRECTION INPUT ;
    USE SIGNAL ;
    PORT
      LAYER M5 ;
        RECT  74.736 0 74.76 0.084 ;
    END
  END a0[82]
  PIN a0[83]
    DIRECTION INPUT ;
    USE SIGNAL ;
    PORT
      LAYER M5 ;
        RECT  74.88 0 74.904 0.084 ;
    END
  END a0[83]
  PIN a0[84]
    DIRECTION INPUT ;
    USE SIGNAL ;
    PORT
      LAYER M5 ;
        RECT  75.024 0 75.048 0.084 ;
    END
  END a0[84]
  PIN a0[85]
    DIRECTION INPUT ;
    USE SIGNAL ;
    PORT
      LAYER M5 ;
        RECT  75.168 0 75.192 0.084 ;
    END
  END a0[85]
  PIN a0[86]
    DIRECTION INPUT ;
    USE SIGNAL ;
    PORT
      LAYER M5 ;
        RECT  75.312 0 75.336 0.084 ;
    END
  END a0[86]
  PIN a0[87]
    DIRECTION INPUT ;
    USE SIGNAL ;
    PORT
      LAYER M5 ;
        RECT  75.456 0 75.48 0.084 ;
    END
  END a0[87]
  PIN a0[88]
    DIRECTION INPUT ;
    USE SIGNAL ;
    PORT
      LAYER M5 ;
        RECT  75.6 0 75.624 0.084 ;
    END
  END a0[88]
  PIN a0[89]
    DIRECTION INPUT ;
    USE SIGNAL ;
    PORT
      LAYER M5 ;
        RECT  75.744 0 75.768 0.084 ;
    END
  END a0[89]
  PIN a0[8]
    DIRECTION INPUT ;
    USE SIGNAL ;
    PORT
      LAYER M5 ;
        RECT  59.472 0 59.496 0.084 ;
    END
  END a0[8]
  PIN a0[90]
    DIRECTION INPUT ;
    USE SIGNAL ;
    PORT
      LAYER M5 ;
        RECT  75.888 0 75.912 0.084 ;
    END
  END a0[90]
  PIN a0[91]
    DIRECTION INPUT ;
    USE SIGNAL ;
    PORT
      LAYER M5 ;
        RECT  76.032 0 76.056 0.084 ;
    END
  END a0[91]
  PIN a0[92]
    DIRECTION INPUT ;
    USE SIGNAL ;
    PORT
      LAYER M5 ;
        RECT  76.176 0 76.2 0.084 ;
    END
  END a0[92]
  PIN a0[93]
    DIRECTION INPUT ;
    USE SIGNAL ;
    PORT
      LAYER M5 ;
        RECT  76.32 0 76.344 0.084 ;
    END
  END a0[93]
  PIN a0[94]
    DIRECTION INPUT ;
    USE SIGNAL ;
    PORT
      LAYER M5 ;
        RECT  76.464 0 76.488 0.084 ;
    END
  END a0[94]
  PIN a0[95]
    DIRECTION INPUT ;
    USE SIGNAL ;
    PORT
      LAYER M5 ;
        RECT  76.608 0 76.632 0.084 ;
    END
  END a0[95]
  PIN a0[96]
    DIRECTION INPUT ;
    USE SIGNAL ;
    PORT
      LAYER M5 ;
        RECT  87.12 0 87.144 0.084 ;
    END
  END a0[96]
  PIN a0[97]
    DIRECTION INPUT ;
    USE SIGNAL ;
    PORT
      LAYER M5 ;
        RECT  87.264 0 87.288 0.084 ;
    END
  END a0[97]
  PIN a0[98]
    DIRECTION INPUT ;
    USE SIGNAL ;
    PORT
      LAYER M5 ;
        RECT  87.408 0 87.432 0.084 ;
    END
  END a0[98]
  PIN a0[99]
    DIRECTION INPUT ;
    USE SIGNAL ;
    PORT
      LAYER M5 ;
        RECT  87.552 0 87.576 0.084 ;
    END
  END a0[99]
  PIN a0[9]
    DIRECTION INPUT ;
    USE SIGNAL ;
    PORT
      LAYER M5 ;
        RECT  59.616 0 59.64 0.084 ;
    END
  END a0[9]
  PIN a1[0]
    DIRECTION INPUT ;
    USE SIGNAL ;
    PORT
      LAYER M5 ;
        RECT  110.448 0 110.472 0.084 ;
    END
  END a1[0]
  PIN a1[100]
    DIRECTION INPUT ;
    USE SIGNAL ;
    PORT
      LAYER M5 ;
        RECT  139.824 0 139.848 0.084 ;
    END
  END a1[100]
  PIN a1[101]
    DIRECTION INPUT ;
    USE SIGNAL ;
    PORT
      LAYER M5 ;
        RECT  139.968 0 139.992 0.084 ;
    END
  END a1[101]
  PIN a1[102]
    DIRECTION INPUT ;
    USE SIGNAL ;
    PORT
      LAYER M5 ;
        RECT  140.112 0 140.136 0.084 ;
    END
  END a1[102]
  PIN a1[103]
    DIRECTION INPUT ;
    USE SIGNAL ;
    PORT
      LAYER M5 ;
        RECT  140.256 0 140.28 0.084 ;
    END
  END a1[103]
  PIN a1[104]
    DIRECTION INPUT ;
    USE SIGNAL ;
    PORT
      LAYER M5 ;
        RECT  140.4 0 140.424 0.084 ;
    END
  END a1[104]
  PIN a1[105]
    DIRECTION INPUT ;
    USE SIGNAL ;
    PORT
      LAYER M5 ;
        RECT  140.544 0 140.568 0.084 ;
    END
  END a1[105]
  PIN a1[106]
    DIRECTION INPUT ;
    USE SIGNAL ;
    PORT
      LAYER M5 ;
        RECT  140.688 0 140.712 0.084 ;
    END
  END a1[106]
  PIN a1[107]
    DIRECTION INPUT ;
    USE SIGNAL ;
    PORT
      LAYER M5 ;
        RECT  140.832 0 140.856 0.084 ;
    END
  END a1[107]
  PIN a1[108]
    DIRECTION INPUT ;
    USE SIGNAL ;
    PORT
      LAYER M5 ;
        RECT  140.976 0 141 0.084 ;
    END
  END a1[108]
  PIN a1[109]
    DIRECTION INPUT ;
    USE SIGNAL ;
    PORT
      LAYER M5 ;
        RECT  141.12 0 141.144 0.084 ;
    END
  END a1[109]
  PIN a1[10]
    DIRECTION INPUT ;
    USE SIGNAL ;
    PORT
      LAYER M5 ;
        RECT  111.888 0 111.912 0.084 ;
    END
  END a1[10]
  PIN a1[110]
    DIRECTION INPUT ;
    USE SIGNAL ;
    PORT
      LAYER M5 ;
        RECT  141.264 0 141.288 0.084 ;
    END
  END a1[110]
  PIN a1[111]
    DIRECTION INPUT ;
    USE SIGNAL ;
    PORT
      LAYER M5 ;
        RECT  141.408 0 141.432 0.084 ;
    END
  END a1[111]
  PIN a1[112]
    DIRECTION INPUT ;
    USE SIGNAL ;
    PORT
      LAYER M5 ;
        RECT  141.552 0 141.576 0.084 ;
    END
  END a1[112]
  PIN a1[113]
    DIRECTION INPUT ;
    USE SIGNAL ;
    PORT
      LAYER M5 ;
        RECT  141.696 0 141.72 0.084 ;
    END
  END a1[113]
  PIN a1[114]
    DIRECTION INPUT ;
    USE SIGNAL ;
    PORT
      LAYER M5 ;
        RECT  141.84 0 141.864 0.084 ;
    END
  END a1[114]
  PIN a1[115]
    DIRECTION INPUT ;
    USE SIGNAL ;
    PORT
      LAYER M5 ;
        RECT  141.984 0 142.008 0.084 ;
    END
  END a1[115]
  PIN a1[116]
    DIRECTION INPUT ;
    USE SIGNAL ;
    PORT
      LAYER M5 ;
        RECT  142.128 0 142.152 0.084 ;
    END
  END a1[116]
  PIN a1[117]
    DIRECTION INPUT ;
    USE SIGNAL ;
    PORT
      LAYER M5 ;
        RECT  142.272 0 142.296 0.084 ;
    END
  END a1[117]
  PIN a1[118]
    DIRECTION INPUT ;
    USE SIGNAL ;
    PORT
      LAYER M5 ;
        RECT  142.416 0 142.44 0.084 ;
    END
  END a1[118]
  PIN a1[119]
    DIRECTION INPUT ;
    USE SIGNAL ;
    PORT
      LAYER M5 ;
        RECT  142.56 0 142.584 0.084 ;
    END
  END a1[119]
  PIN a1[11]
    DIRECTION INPUT ;
    USE SIGNAL ;
    PORT
      LAYER M5 ;
        RECT  112.032 0 112.056 0.084 ;
    END
  END a1[11]
  PIN a1[120]
    DIRECTION INPUT ;
    USE SIGNAL ;
    PORT
      LAYER M5 ;
        RECT  142.704 0 142.728 0.084 ;
    END
  END a1[120]
  PIN a1[121]
    DIRECTION INPUT ;
    USE SIGNAL ;
    PORT
      LAYER M5 ;
        RECT  142.848 0 142.872 0.084 ;
    END
  END a1[121]
  PIN a1[122]
    DIRECTION INPUT ;
    USE SIGNAL ;
    PORT
      LAYER M5 ;
        RECT  142.992 0 143.016 0.084 ;
    END
  END a1[122]
  PIN a1[123]
    DIRECTION INPUT ;
    USE SIGNAL ;
    PORT
      LAYER M5 ;
        RECT  143.136 0 143.16 0.084 ;
    END
  END a1[123]
  PIN a1[124]
    DIRECTION INPUT ;
    USE SIGNAL ;
    PORT
      LAYER M5 ;
        RECT  143.28 0 143.304 0.084 ;
    END
  END a1[124]
  PIN a1[125]
    DIRECTION INPUT ;
    USE SIGNAL ;
    PORT
      LAYER M5 ;
        RECT  143.424 0 143.448 0.084 ;
    END
  END a1[125]
  PIN a1[126]
    DIRECTION INPUT ;
    USE SIGNAL ;
    PORT
      LAYER M5 ;
        RECT  62.928 0 62.952 0.084 ;
    END
  END a1[126]
  PIN a1[127]
    DIRECTION INPUT ;
    USE SIGNAL ;
    PORT
      LAYER M5 ;
        RECT  63.072 0 63.096 0.084 ;
    END
  END a1[127]
  PIN a1[128]
    DIRECTION INPUT ;
    USE SIGNAL ;
    PORT
      LAYER M5 ;
        RECT  63.216 0 63.24 0.084 ;
    END
  END a1[128]
  PIN a1[129]
    DIRECTION INPUT ;
    USE SIGNAL ;
    PORT
      LAYER M5 ;
        RECT  63.36 0 63.384 0.084 ;
    END
  END a1[129]
  PIN a1[12]
    DIRECTION INPUT ;
    USE SIGNAL ;
    PORT
      LAYER M5 ;
        RECT  112.176 0 112.2 0.084 ;
    END
  END a1[12]
  PIN a1[130]
    DIRECTION INPUT ;
    USE SIGNAL ;
    PORT
      LAYER M5 ;
        RECT  63.504 0 63.528 0.084 ;
    END
  END a1[130]
  PIN a1[131]
    DIRECTION INPUT ;
    USE SIGNAL ;
    PORT
      LAYER M5 ;
        RECT  63.648 0 63.672 0.084 ;
    END
  END a1[131]
  PIN a1[132]
    DIRECTION INPUT ;
    USE SIGNAL ;
    PORT
      LAYER M5 ;
        RECT  63.792 0 63.816 0.084 ;
    END
  END a1[132]
  PIN a1[133]
    DIRECTION INPUT ;
    USE SIGNAL ;
    PORT
      LAYER M5 ;
        RECT  63.936 0 63.96 0.084 ;
    END
  END a1[133]
  PIN a1[134]
    DIRECTION INPUT ;
    USE SIGNAL ;
    PORT
      LAYER M5 ;
        RECT  64.08 0 64.104 0.084 ;
    END
  END a1[134]
  PIN a1[135]
    DIRECTION INPUT ;
    USE SIGNAL ;
    PORT
      LAYER M5 ;
        RECT  64.224 0 64.248 0.084 ;
    END
  END a1[135]
  PIN a1[136]
    DIRECTION INPUT ;
    USE SIGNAL ;
    PORT
      LAYER M5 ;
        RECT  64.368 0 64.392 0.084 ;
    END
  END a1[136]
  PIN a1[137]
    DIRECTION INPUT ;
    USE SIGNAL ;
    PORT
      LAYER M5 ;
        RECT  64.512 0 64.536 0.084 ;
    END
  END a1[137]
  PIN a1[138]
    DIRECTION INPUT ;
    USE SIGNAL ;
    PORT
      LAYER M5 ;
        RECT  64.656 0 64.68 0.084 ;
    END
  END a1[138]
  PIN a1[139]
    DIRECTION INPUT ;
    USE SIGNAL ;
    PORT
      LAYER M5 ;
        RECT  64.8 0 64.824 0.084 ;
    END
  END a1[139]
  PIN a1[13]
    DIRECTION INPUT ;
    USE SIGNAL ;
    PORT
      LAYER M5 ;
        RECT  112.32 0 112.344 0.084 ;
    END
  END a1[13]
  PIN a1[140]
    DIRECTION INPUT ;
    USE SIGNAL ;
    PORT
      LAYER M5 ;
        RECT  64.944 0 64.968 0.084 ;
    END
  END a1[140]
  PIN a1[141]
    DIRECTION INPUT ;
    USE SIGNAL ;
    PORT
      LAYER M5 ;
        RECT  65.088 0 65.112 0.084 ;
    END
  END a1[141]
  PIN a1[142]
    DIRECTION INPUT ;
    USE SIGNAL ;
    PORT
      LAYER M5 ;
        RECT  65.232 0 65.256 0.084 ;
    END
  END a1[142]
  PIN a1[143]
    DIRECTION INPUT ;
    USE SIGNAL ;
    PORT
      LAYER M5 ;
        RECT  65.376 0 65.4 0.084 ;
    END
  END a1[143]
  PIN a1[144]
    DIRECTION INPUT ;
    USE SIGNAL ;
    PORT
      LAYER M5 ;
        RECT  65.52 0 65.544 0.084 ;
    END
  END a1[144]
  PIN a1[145]
    DIRECTION INPUT ;
    USE SIGNAL ;
    PORT
      LAYER M5 ;
        RECT  65.664 0 65.688 0.084 ;
    END
  END a1[145]
  PIN a1[146]
    DIRECTION INPUT ;
    USE SIGNAL ;
    PORT
      LAYER M5 ;
        RECT  65.808 0 65.832 0.084 ;
    END
  END a1[146]
  PIN a1[147]
    DIRECTION INPUT ;
    USE SIGNAL ;
    PORT
      LAYER M5 ;
        RECT  65.952 0 65.976 0.084 ;
    END
  END a1[147]
  PIN a1[148]
    DIRECTION INPUT ;
    USE SIGNAL ;
    PORT
      LAYER M5 ;
        RECT  66.096 0 66.12 0.084 ;
    END
  END a1[148]
  PIN a1[149]
    DIRECTION INPUT ;
    USE SIGNAL ;
    PORT
      LAYER M5 ;
        RECT  66.24 0 66.264 0.084 ;
    END
  END a1[149]
  PIN a1[14]
    DIRECTION INPUT ;
    USE SIGNAL ;
    PORT
      LAYER M5 ;
        RECT  112.464 0 112.488 0.084 ;
    END
  END a1[14]
  PIN a1[150]
    DIRECTION INPUT ;
    USE SIGNAL ;
    PORT
      LAYER M5 ;
        RECT  66.384 0 66.408 0.084 ;
    END
  END a1[150]
  PIN a1[151]
    DIRECTION INPUT ;
    USE SIGNAL ;
    PORT
      LAYER M5 ;
        RECT  66.528 0 66.552 0.084 ;
    END
  END a1[151]
  PIN a1[152]
    DIRECTION INPUT ;
    USE SIGNAL ;
    PORT
      LAYER M5 ;
        RECT  66.672 0 66.696 0.084 ;
    END
  END a1[152]
  PIN a1[153]
    DIRECTION INPUT ;
    USE SIGNAL ;
    PORT
      LAYER M5 ;
        RECT  66.816 0 66.84 0.084 ;
    END
  END a1[153]
  PIN a1[154]
    DIRECTION INPUT ;
    USE SIGNAL ;
    PORT
      LAYER M5 ;
        RECT  66.96 0 66.984 0.084 ;
    END
  END a1[154]
  PIN a1[155]
    DIRECTION INPUT ;
    USE SIGNAL ;
    PORT
      LAYER M5 ;
        RECT  67.104 0 67.128 0.084 ;
    END
  END a1[155]
  PIN a1[156]
    DIRECTION INPUT ;
    USE SIGNAL ;
    PORT
      LAYER M5 ;
        RECT  67.248 0 67.272 0.084 ;
    END
  END a1[156]
  PIN a1[157]
    DIRECTION INPUT ;
    USE SIGNAL ;
    PORT
      LAYER M5 ;
        RECT  67.392 0 67.416 0.084 ;
    END
  END a1[157]
  PIN a1[158]
    DIRECTION INPUT ;
    USE SIGNAL ;
    PORT
      LAYER M5 ;
        RECT  67.536 0 67.56 0.084 ;
    END
  END a1[158]
  PIN a1[159]
    DIRECTION INPUT ;
    USE SIGNAL ;
    PORT
      LAYER M5 ;
        RECT  67.68 0 67.704 0.084 ;
    END
  END a1[159]
  PIN a1[15]
    DIRECTION INPUT ;
    USE SIGNAL ;
    PORT
      LAYER M5 ;
        RECT  112.608 0 112.632 0.084 ;
    END
  END a1[15]
  PIN a1[160]
    DIRECTION INPUT ;
    USE SIGNAL ;
    PORT
      LAYER M5 ;
        RECT  67.824 0 67.848 0.084 ;
    END
  END a1[160]
  PIN a1[161]
    DIRECTION INPUT ;
    USE SIGNAL ;
    PORT
      LAYER M5 ;
        RECT  67.968 0 67.992 0.084 ;
    END
  END a1[161]
  PIN a1[162]
    DIRECTION INPUT ;
    USE SIGNAL ;
    PORT
      LAYER M5 ;
        RECT  68.112 0 68.136 0.084 ;
    END
  END a1[162]
  PIN a1[163]
    DIRECTION INPUT ;
    USE SIGNAL ;
    PORT
      LAYER M5 ;
        RECT  68.256 0 68.28 0.084 ;
    END
  END a1[163]
  PIN a1[164]
    DIRECTION INPUT ;
    USE SIGNAL ;
    PORT
      LAYER M5 ;
        RECT  68.4 0 68.424 0.084 ;
    END
  END a1[164]
  PIN a1[165]
    DIRECTION INPUT ;
    USE SIGNAL ;
    PORT
      LAYER M5 ;
        RECT  68.544 0 68.568 0.084 ;
    END
  END a1[165]
  PIN a1[166]
    DIRECTION INPUT ;
    USE SIGNAL ;
    PORT
      LAYER M5 ;
        RECT  68.688 0 68.712 0.084 ;
    END
  END a1[166]
  PIN a1[167]
    DIRECTION INPUT ;
    USE SIGNAL ;
    PORT
      LAYER M5 ;
        RECT  68.832 0 68.856 0.084 ;
    END
  END a1[167]
  PIN a1[168]
    DIRECTION INPUT ;
    USE SIGNAL ;
    PORT
      LAYER M5 ;
        RECT  68.976 0 69 0.084 ;
    END
  END a1[168]
  PIN a1[169]
    DIRECTION INPUT ;
    USE SIGNAL ;
    PORT
      LAYER M5 ;
        RECT  69.12 0 69.144 0.084 ;
    END
  END a1[169]
  PIN a1[16]
    DIRECTION INPUT ;
    USE SIGNAL ;
    PORT
      LAYER M5 ;
        RECT  112.752 0 112.776 0.084 ;
    END
  END a1[16]
  PIN a1[170]
    DIRECTION INPUT ;
    USE SIGNAL ;
    PORT
      LAYER M5 ;
        RECT  69.264 0 69.288 0.084 ;
    END
  END a1[170]
  PIN a1[171]
    DIRECTION INPUT ;
    USE SIGNAL ;
    PORT
      LAYER M5 ;
        RECT  69.408 0 69.432 0.084 ;
    END
  END a1[171]
  PIN a1[172]
    DIRECTION INPUT ;
    USE SIGNAL ;
    PORT
      LAYER M5 ;
        RECT  69.552 0 69.576 0.084 ;
    END
  END a1[172]
  PIN a1[173]
    DIRECTION INPUT ;
    USE SIGNAL ;
    PORT
      LAYER M5 ;
        RECT  69.696 0 69.72 0.084 ;
    END
  END a1[173]
  PIN a1[174]
    DIRECTION INPUT ;
    USE SIGNAL ;
    PORT
      LAYER M5 ;
        RECT  69.84 0 69.864 0.084 ;
    END
  END a1[174]
  PIN a1[175]
    DIRECTION INPUT ;
    USE SIGNAL ;
    PORT
      LAYER M5 ;
        RECT  69.984 0 70.008 0.084 ;
    END
  END a1[175]
  PIN a1[176]
    DIRECTION INPUT ;
    USE SIGNAL ;
    PORT
      LAYER M5 ;
        RECT  70.128 0 70.152 0.084 ;
    END
  END a1[176]
  PIN a1[177]
    DIRECTION INPUT ;
    USE SIGNAL ;
    PORT
      LAYER M5 ;
        RECT  70.272 0 70.296 0.084 ;
    END
  END a1[177]
  PIN a1[178]
    DIRECTION INPUT ;
    USE SIGNAL ;
    PORT
      LAYER M5 ;
        RECT  70.416 0 70.44 0.084 ;
    END
  END a1[178]
  PIN a1[179]
    DIRECTION INPUT ;
    USE SIGNAL ;
    PORT
      LAYER M5 ;
        RECT  70.56 0 70.584 0.084 ;
    END
  END a1[179]
  PIN a1[17]
    DIRECTION INPUT ;
    USE SIGNAL ;
    PORT
      LAYER M5 ;
        RECT  112.896 0 112.92 0.084 ;
    END
  END a1[17]
  PIN a1[180]
    DIRECTION INPUT ;
    USE SIGNAL ;
    PORT
      LAYER M5 ;
        RECT  70.704 0 70.728 0.084 ;
    END
  END a1[180]
  PIN a1[181]
    DIRECTION INPUT ;
    USE SIGNAL ;
    PORT
      LAYER M5 ;
        RECT  70.848 0 70.872 0.084 ;
    END
  END a1[181]
  PIN a1[182]
    DIRECTION INPUT ;
    USE SIGNAL ;
    PORT
      LAYER M5 ;
        RECT  70.992 0 71.016 0.084 ;
    END
  END a1[182]
  PIN a1[183]
    DIRECTION INPUT ;
    USE SIGNAL ;
    PORT
      LAYER M5 ;
        RECT  71.136 0 71.16 0.084 ;
    END
  END a1[183]
  PIN a1[184]
    DIRECTION INPUT ;
    USE SIGNAL ;
    PORT
      LAYER M5 ;
        RECT  71.28 0 71.304 0.084 ;
    END
  END a1[184]
  PIN a1[185]
    DIRECTION INPUT ;
    USE SIGNAL ;
    PORT
      LAYER M5 ;
        RECT  71.424 0 71.448 0.084 ;
    END
  END a1[185]
  PIN a1[186]
    DIRECTION INPUT ;
    USE SIGNAL ;
    PORT
      LAYER M5 ;
        RECT  71.568 0 71.592 0.084 ;
    END
  END a1[186]
  PIN a1[187]
    DIRECTION INPUT ;
    USE SIGNAL ;
    PORT
      LAYER M5 ;
        RECT  71.712 0 71.736 0.084 ;
    END
  END a1[187]
  PIN a1[188]
    DIRECTION INPUT ;
    USE SIGNAL ;
    PORT
      LAYER M5 ;
        RECT  71.856 0 71.88 0.084 ;
    END
  END a1[188]
  PIN a1[189]
    DIRECTION INPUT ;
    USE SIGNAL ;
    PORT
      LAYER M5 ;
        RECT  72 0 72.024 0.084 ;
    END
  END a1[189]
  PIN a1[18]
    DIRECTION INPUT ;
    USE SIGNAL ;
    PORT
      LAYER M5 ;
        RECT  113.04 0 113.064 0.084 ;
    END
  END a1[18]
  PIN a1[190]
    DIRECTION INPUT ;
    USE SIGNAL ;
    PORT
      LAYER M5 ;
        RECT  120.528 0 120.552 0.084 ;
    END
  END a1[190]
  PIN a1[191]
    DIRECTION INPUT ;
    USE SIGNAL ;
    PORT
      LAYER M5 ;
        RECT  120.672 0 120.696 0.084 ;
    END
  END a1[191]
  PIN a1[192]
    DIRECTION INPUT ;
    USE SIGNAL ;
    PORT
      LAYER M5 ;
        RECT  120.816 0 120.84 0.084 ;
    END
  END a1[192]
  PIN a1[193]
    DIRECTION INPUT ;
    USE SIGNAL ;
    PORT
      LAYER M5 ;
        RECT  120.96 0 120.984 0.084 ;
    END
  END a1[193]
  PIN a1[194]
    DIRECTION INPUT ;
    USE SIGNAL ;
    PORT
      LAYER M5 ;
        RECT  121.104 0 121.128 0.084 ;
    END
  END a1[194]
  PIN a1[195]
    DIRECTION INPUT ;
    USE SIGNAL ;
    PORT
      LAYER M5 ;
        RECT  121.248 0 121.272 0.084 ;
    END
  END a1[195]
  PIN a1[196]
    DIRECTION INPUT ;
    USE SIGNAL ;
    PORT
      LAYER M5 ;
        RECT  121.392 0 121.416 0.084 ;
    END
  END a1[196]
  PIN a1[197]
    DIRECTION INPUT ;
    USE SIGNAL ;
    PORT
      LAYER M5 ;
        RECT  121.536 0 121.56 0.084 ;
    END
  END a1[197]
  PIN a1[198]
    DIRECTION INPUT ;
    USE SIGNAL ;
    PORT
      LAYER M5 ;
        RECT  121.68 0 121.704 0.084 ;
    END
  END a1[198]
  PIN a1[199]
    DIRECTION INPUT ;
    USE SIGNAL ;
    PORT
      LAYER M5 ;
        RECT  121.824 0 121.848 0.084 ;
    END
  END a1[199]
  PIN a1[19]
    DIRECTION INPUT ;
    USE SIGNAL ;
    PORT
      LAYER M5 ;
        RECT  113.184 0 113.208 0.084 ;
    END
  END a1[19]
  PIN a1[1]
    DIRECTION INPUT ;
    USE SIGNAL ;
    PORT
      LAYER M5 ;
        RECT  110.592 0 110.616 0.084 ;
    END
  END a1[1]
  PIN a1[200]
    DIRECTION INPUT ;
    USE SIGNAL ;
    PORT
      LAYER M5 ;
        RECT  121.968 0 121.992 0.084 ;
    END
  END a1[200]
  PIN a1[201]
    DIRECTION INPUT ;
    USE SIGNAL ;
    PORT
      LAYER M5 ;
        RECT  122.112 0 122.136 0.084 ;
    END
  END a1[201]
  PIN a1[202]
    DIRECTION INPUT ;
    USE SIGNAL ;
    PORT
      LAYER M5 ;
        RECT  122.256 0 122.28 0.084 ;
    END
  END a1[202]
  PIN a1[203]
    DIRECTION INPUT ;
    USE SIGNAL ;
    PORT
      LAYER M5 ;
        RECT  122.4 0 122.424 0.084 ;
    END
  END a1[203]
  PIN a1[204]
    DIRECTION INPUT ;
    USE SIGNAL ;
    PORT
      LAYER M5 ;
        RECT  122.544 0 122.568 0.084 ;
    END
  END a1[204]
  PIN a1[205]
    DIRECTION INPUT ;
    USE SIGNAL ;
    PORT
      LAYER M5 ;
        RECT  122.688 0 122.712 0.084 ;
    END
  END a1[205]
  PIN a1[206]
    DIRECTION INPUT ;
    USE SIGNAL ;
    PORT
      LAYER M5 ;
        RECT  122.832 0 122.856 0.084 ;
    END
  END a1[206]
  PIN a1[207]
    DIRECTION INPUT ;
    USE SIGNAL ;
    PORT
      LAYER M5 ;
        RECT  122.976 0 123 0.084 ;
    END
  END a1[207]
  PIN a1[208]
    DIRECTION INPUT ;
    USE SIGNAL ;
    PORT
      LAYER M5 ;
        RECT  123.12 0 123.144 0.084 ;
    END
  END a1[208]
  PIN a1[209]
    DIRECTION INPUT ;
    USE SIGNAL ;
    PORT
      LAYER M5 ;
        RECT  123.264 0 123.288 0.084 ;
    END
  END a1[209]
  PIN a1[20]
    DIRECTION INPUT ;
    USE SIGNAL ;
    PORT
      LAYER M5 ;
        RECT  113.328 0 113.352 0.084 ;
    END
  END a1[20]
  PIN a1[210]
    DIRECTION INPUT ;
    USE SIGNAL ;
    PORT
      LAYER M5 ;
        RECT  123.408 0 123.432 0.084 ;
    END
  END a1[210]
  PIN a1[211]
    DIRECTION INPUT ;
    USE SIGNAL ;
    PORT
      LAYER M5 ;
        RECT  123.552 0 123.576 0.084 ;
    END
  END a1[211]
  PIN a1[212]
    DIRECTION INPUT ;
    USE SIGNAL ;
    PORT
      LAYER M5 ;
        RECT  123.696 0 123.72 0.084 ;
    END
  END a1[212]
  PIN a1[213]
    DIRECTION INPUT ;
    USE SIGNAL ;
    PORT
      LAYER M5 ;
        RECT  123.84 0 123.864 0.084 ;
    END
  END a1[213]
  PIN a1[214]
    DIRECTION INPUT ;
    USE SIGNAL ;
    PORT
      LAYER M5 ;
        RECT  123.984 0 124.008 0.084 ;
    END
  END a1[214]
  PIN a1[215]
    DIRECTION INPUT ;
    USE SIGNAL ;
    PORT
      LAYER M5 ;
        RECT  124.128 0 124.152 0.084 ;
    END
  END a1[215]
  PIN a1[216]
    DIRECTION INPUT ;
    USE SIGNAL ;
    PORT
      LAYER M5 ;
        RECT  124.272 0 124.296 0.084 ;
    END
  END a1[216]
  PIN a1[217]
    DIRECTION INPUT ;
    USE SIGNAL ;
    PORT
      LAYER M5 ;
        RECT  124.416 0 124.44 0.084 ;
    END
  END a1[217]
  PIN a1[218]
    DIRECTION INPUT ;
    USE SIGNAL ;
    PORT
      LAYER M5 ;
        RECT  124.56 0 124.584 0.084 ;
    END
  END a1[218]
  PIN a1[219]
    DIRECTION INPUT ;
    USE SIGNAL ;
    PORT
      LAYER M5 ;
        RECT  124.704 0 124.728 0.084 ;
    END
  END a1[219]
  PIN a1[21]
    DIRECTION INPUT ;
    USE SIGNAL ;
    PORT
      LAYER M5 ;
        RECT  113.472 0 113.496 0.084 ;
    END
  END a1[21]
  PIN a1[220]
    DIRECTION INPUT ;
    USE SIGNAL ;
    PORT
      LAYER M5 ;
        RECT  124.848 0 124.872 0.084 ;
    END
  END a1[220]
  PIN a1[221]
    DIRECTION INPUT ;
    USE SIGNAL ;
    PORT
      LAYER M5 ;
        RECT  124.992 0 125.016 0.084 ;
    END
  END a1[221]
  PIN a1[222]
    DIRECTION INPUT ;
    USE SIGNAL ;
    PORT
      LAYER M5 ;
        RECT  43.344 0 43.368 0.084 ;
    END
  END a1[222]
  PIN a1[223]
    DIRECTION INPUT ;
    USE SIGNAL ;
    PORT
      LAYER M5 ;
        RECT  43.488 0 43.512 0.084 ;
    END
  END a1[223]
  PIN a1[224]
    DIRECTION INPUT ;
    USE SIGNAL ;
    PORT
      LAYER M5 ;
        RECT  43.632 0 43.656 0.084 ;
    END
  END a1[224]
  PIN a1[225]
    DIRECTION INPUT ;
    USE SIGNAL ;
    PORT
      LAYER M5 ;
        RECT  43.776 0 43.8 0.084 ;
    END
  END a1[225]
  PIN a1[226]
    DIRECTION INPUT ;
    USE SIGNAL ;
    PORT
      LAYER M5 ;
        RECT  43.92 0 43.944 0.084 ;
    END
  END a1[226]
  PIN a1[227]
    DIRECTION INPUT ;
    USE SIGNAL ;
    PORT
      LAYER M5 ;
        RECT  44.064 0 44.088 0.084 ;
    END
  END a1[227]
  PIN a1[228]
    DIRECTION INPUT ;
    USE SIGNAL ;
    PORT
      LAYER M5 ;
        RECT  44.208 0 44.232 0.084 ;
    END
  END a1[228]
  PIN a1[229]
    DIRECTION INPUT ;
    USE SIGNAL ;
    PORT
      LAYER M5 ;
        RECT  44.352 0 44.376 0.084 ;
    END
  END a1[229]
  PIN a1[22]
    DIRECTION INPUT ;
    USE SIGNAL ;
    PORT
      LAYER M5 ;
        RECT  113.616 0 113.64 0.084 ;
    END
  END a1[22]
  PIN a1[230]
    DIRECTION INPUT ;
    USE SIGNAL ;
    PORT
      LAYER M5 ;
        RECT  44.496 0 44.52 0.084 ;
    END
  END a1[230]
  PIN a1[231]
    DIRECTION INPUT ;
    USE SIGNAL ;
    PORT
      LAYER M5 ;
        RECT  44.64 0 44.664 0.084 ;
    END
  END a1[231]
  PIN a1[232]
    DIRECTION INPUT ;
    USE SIGNAL ;
    PORT
      LAYER M5 ;
        RECT  44.784 0 44.808 0.084 ;
    END
  END a1[232]
  PIN a1[233]
    DIRECTION INPUT ;
    USE SIGNAL ;
    PORT
      LAYER M5 ;
        RECT  44.928 0 44.952 0.084 ;
    END
  END a1[233]
  PIN a1[234]
    DIRECTION INPUT ;
    USE SIGNAL ;
    PORT
      LAYER M5 ;
        RECT  45.072 0 45.096 0.084 ;
    END
  END a1[234]
  PIN a1[235]
    DIRECTION INPUT ;
    USE SIGNAL ;
    PORT
      LAYER M5 ;
        RECT  45.216 0 45.24 0.084 ;
    END
  END a1[235]
  PIN a1[236]
    DIRECTION INPUT ;
    USE SIGNAL ;
    PORT
      LAYER M5 ;
        RECT  45.36 0 45.384 0.084 ;
    END
  END a1[236]
  PIN a1[237]
    DIRECTION INPUT ;
    USE SIGNAL ;
    PORT
      LAYER M5 ;
        RECT  45.504 0 45.528 0.084 ;
    END
  END a1[237]
  PIN a1[238]
    DIRECTION INPUT ;
    USE SIGNAL ;
    PORT
      LAYER M5 ;
        RECT  45.648 0 45.672 0.084 ;
    END
  END a1[238]
  PIN a1[239]
    DIRECTION INPUT ;
    USE SIGNAL ;
    PORT
      LAYER M5 ;
        RECT  45.792 0 45.816 0.084 ;
    END
  END a1[239]
  PIN a1[23]
    DIRECTION INPUT ;
    USE SIGNAL ;
    PORT
      LAYER M5 ;
        RECT  113.76 0 113.784 0.084 ;
    END
  END a1[23]
  PIN a1[240]
    DIRECTION INPUT ;
    USE SIGNAL ;
    PORT
      LAYER M5 ;
        RECT  45.936 0 45.96 0.084 ;
    END
  END a1[240]
  PIN a1[241]
    DIRECTION INPUT ;
    USE SIGNAL ;
    PORT
      LAYER M5 ;
        RECT  46.08 0 46.104 0.084 ;
    END
  END a1[241]
  PIN a1[242]
    DIRECTION INPUT ;
    USE SIGNAL ;
    PORT
      LAYER M5 ;
        RECT  46.224 0 46.248 0.084 ;
    END
  END a1[242]
  PIN a1[243]
    DIRECTION INPUT ;
    USE SIGNAL ;
    PORT
      LAYER M5 ;
        RECT  46.368 0 46.392 0.084 ;
    END
  END a1[243]
  PIN a1[244]
    DIRECTION INPUT ;
    USE SIGNAL ;
    PORT
      LAYER M5 ;
        RECT  46.512 0 46.536 0.084 ;
    END
  END a1[244]
  PIN a1[245]
    DIRECTION INPUT ;
    USE SIGNAL ;
    PORT
      LAYER M5 ;
        RECT  46.656 0 46.68 0.084 ;
    END
  END a1[245]
  PIN a1[246]
    DIRECTION INPUT ;
    USE SIGNAL ;
    PORT
      LAYER M5 ;
        RECT  46.8 0 46.824 0.084 ;
    END
  END a1[246]
  PIN a1[247]
    DIRECTION INPUT ;
    USE SIGNAL ;
    PORT
      LAYER M5 ;
        RECT  46.944 0 46.968 0.084 ;
    END
  END a1[247]
  PIN a1[248]
    DIRECTION INPUT ;
    USE SIGNAL ;
    PORT
      LAYER M5 ;
        RECT  47.088 0 47.112 0.084 ;
    END
  END a1[248]
  PIN a1[249]
    DIRECTION INPUT ;
    USE SIGNAL ;
    PORT
      LAYER M5 ;
        RECT  47.232 0 47.256 0.084 ;
    END
  END a1[249]
  PIN a1[24]
    DIRECTION INPUT ;
    USE SIGNAL ;
    PORT
      LAYER M5 ;
        RECT  113.904 0 113.928 0.084 ;
    END
  END a1[24]
  PIN a1[250]
    DIRECTION INPUT ;
    USE SIGNAL ;
    PORT
      LAYER M5 ;
        RECT  47.376 0 47.4 0.084 ;
    END
  END a1[250]
  PIN a1[251]
    DIRECTION INPUT ;
    USE SIGNAL ;
    PORT
      LAYER M5 ;
        RECT  47.52 0 47.544 0.084 ;
    END
  END a1[251]
  PIN a1[252]
    DIRECTION INPUT ;
    USE SIGNAL ;
    PORT
      LAYER M5 ;
        RECT  47.664 0 47.688 0.084 ;
    END
  END a1[252]
  PIN a1[253]
    DIRECTION INPUT ;
    USE SIGNAL ;
    PORT
      LAYER M5 ;
        RECT  47.808 0 47.832 0.084 ;
    END
  END a1[253]
  PIN a1[254]
    DIRECTION INPUT ;
    USE SIGNAL ;
    PORT
      LAYER M5 ;
        RECT  129.744 0 129.768 0.084 ;
    END
  END a1[254]
  PIN a1[255]
    DIRECTION INPUT ;
    USE SIGNAL ;
    PORT
      LAYER M5 ;
        RECT  129.888 0 129.912 0.084 ;
    END
  END a1[255]
  PIN a1[256]
    DIRECTION INPUT ;
    USE SIGNAL ;
    PORT
      LAYER M5 ;
        RECT  130.032 0 130.056 0.084 ;
    END
  END a1[256]
  PIN a1[257]
    DIRECTION INPUT ;
    USE SIGNAL ;
    PORT
      LAYER M5 ;
        RECT  130.176 0 130.2 0.084 ;
    END
  END a1[257]
  PIN a1[25]
    DIRECTION INPUT ;
    USE SIGNAL ;
    PORT
      LAYER M5 ;
        RECT  114.048 0 114.072 0.084 ;
    END
  END a1[25]
  PIN a1[26]
    DIRECTION INPUT ;
    USE SIGNAL ;
    PORT
      LAYER M5 ;
        RECT  114.192 0 114.216 0.084 ;
    END
  END a1[26]
  PIN a1[27]
    DIRECTION INPUT ;
    USE SIGNAL ;
    PORT
      LAYER M5 ;
        RECT  114.336 0 114.36 0.084 ;
    END
  END a1[27]
  PIN a1[28]
    DIRECTION INPUT ;
    USE SIGNAL ;
    PORT
      LAYER M5 ;
        RECT  114.48 0 114.504 0.084 ;
    END
  END a1[28]
  PIN a1[29]
    DIRECTION INPUT ;
    USE SIGNAL ;
    PORT
      LAYER M5 ;
        RECT  114.624 0 114.648 0.084 ;
    END
  END a1[29]
  PIN a1[2]
    DIRECTION INPUT ;
    USE SIGNAL ;
    PORT
      LAYER M5 ;
        RECT  110.736 0 110.76 0.084 ;
    END
  END a1[2]
  PIN a1[30]
    DIRECTION INPUT ;
    USE SIGNAL ;
    PORT
      LAYER M5 ;
        RECT  81.36 0 81.384 0.084 ;
    END
  END a1[30]
  PIN a1[31]
    DIRECTION INPUT ;
    USE SIGNAL ;
    PORT
      LAYER M5 ;
        RECT  81.504 0 81.528 0.084 ;
    END
  END a1[31]
  PIN a1[32]
    DIRECTION INPUT ;
    USE SIGNAL ;
    PORT
      LAYER M5 ;
        RECT  81.648 0 81.672 0.084 ;
    END
  END a1[32]
  PIN a1[33]
    DIRECTION INPUT ;
    USE SIGNAL ;
    PORT
      LAYER M5 ;
        RECT  81.792 0 81.816 0.084 ;
    END
  END a1[33]
  PIN a1[34]
    DIRECTION INPUT ;
    USE SIGNAL ;
    PORT
      LAYER M5 ;
        RECT  81.936 0 81.96 0.084 ;
    END
  END a1[34]
  PIN a1[35]
    DIRECTION INPUT ;
    USE SIGNAL ;
    PORT
      LAYER M5 ;
        RECT  82.08 0 82.104 0.084 ;
    END
  END a1[35]
  PIN a1[36]
    DIRECTION INPUT ;
    USE SIGNAL ;
    PORT
      LAYER M5 ;
        RECT  82.224 0 82.248 0.084 ;
    END
  END a1[36]
  PIN a1[37]
    DIRECTION INPUT ;
    USE SIGNAL ;
    PORT
      LAYER M5 ;
        RECT  82.368 0 82.392 0.084 ;
    END
  END a1[37]
  PIN a1[38]
    DIRECTION INPUT ;
    USE SIGNAL ;
    PORT
      LAYER M5 ;
        RECT  82.512 0 82.536 0.084 ;
    END
  END a1[38]
  PIN a1[39]
    DIRECTION INPUT ;
    USE SIGNAL ;
    PORT
      LAYER M5 ;
        RECT  82.656 0 82.68 0.084 ;
    END
  END a1[39]
  PIN a1[3]
    DIRECTION INPUT ;
    USE SIGNAL ;
    PORT
      LAYER M5 ;
        RECT  110.88 0 110.904 0.084 ;
    END
  END a1[3]
  PIN a1[40]
    DIRECTION INPUT ;
    USE SIGNAL ;
    PORT
      LAYER M5 ;
        RECT  82.8 0 82.824 0.084 ;
    END
  END a1[40]
  PIN a1[41]
    DIRECTION INPUT ;
    USE SIGNAL ;
    PORT
      LAYER M5 ;
        RECT  82.944 0 82.968 0.084 ;
    END
  END a1[41]
  PIN a1[42]
    DIRECTION INPUT ;
    USE SIGNAL ;
    PORT
      LAYER M5 ;
        RECT  83.088 0 83.112 0.084 ;
    END
  END a1[42]
  PIN a1[43]
    DIRECTION INPUT ;
    USE SIGNAL ;
    PORT
      LAYER M5 ;
        RECT  83.232 0 83.256 0.084 ;
    END
  END a1[43]
  PIN a1[44]
    DIRECTION INPUT ;
    USE SIGNAL ;
    PORT
      LAYER M5 ;
        RECT  83.376 0 83.4 0.084 ;
    END
  END a1[44]
  PIN a1[45]
    DIRECTION INPUT ;
    USE SIGNAL ;
    PORT
      LAYER M5 ;
        RECT  83.52 0 83.544 0.084 ;
    END
  END a1[45]
  PIN a1[46]
    DIRECTION INPUT ;
    USE SIGNAL ;
    PORT
      LAYER M5 ;
        RECT  83.664 0 83.688 0.084 ;
    END
  END a1[46]
  PIN a1[47]
    DIRECTION INPUT ;
    USE SIGNAL ;
    PORT
      LAYER M5 ;
        RECT  83.808 0 83.832 0.084 ;
    END
  END a1[47]
  PIN a1[48]
    DIRECTION INPUT ;
    USE SIGNAL ;
    PORT
      LAYER M5 ;
        RECT  83.952 0 83.976 0.084 ;
    END
  END a1[48]
  PIN a1[49]
    DIRECTION INPUT ;
    USE SIGNAL ;
    PORT
      LAYER M5 ;
        RECT  84.096 0 84.12 0.084 ;
    END
  END a1[49]
  PIN a1[4]
    DIRECTION INPUT ;
    USE SIGNAL ;
    PORT
      LAYER M5 ;
        RECT  111.024 0 111.048 0.084 ;
    END
  END a1[4]
  PIN a1[50]
    DIRECTION INPUT ;
    USE SIGNAL ;
    PORT
      LAYER M5 ;
        RECT  84.24 0 84.264 0.084 ;
    END
  END a1[50]
  PIN a1[51]
    DIRECTION INPUT ;
    USE SIGNAL ;
    PORT
      LAYER M5 ;
        RECT  84.384 0 84.408 0.084 ;
    END
  END a1[51]
  PIN a1[52]
    DIRECTION INPUT ;
    USE SIGNAL ;
    PORT
      LAYER M5 ;
        RECT  84.528 0 84.552 0.084 ;
    END
  END a1[52]
  PIN a1[53]
    DIRECTION INPUT ;
    USE SIGNAL ;
    PORT
      LAYER M5 ;
        RECT  84.672 0 84.696 0.084 ;
    END
  END a1[53]
  PIN a1[54]
    DIRECTION INPUT ;
    USE SIGNAL ;
    PORT
      LAYER M5 ;
        RECT  84.816 0 84.84 0.084 ;
    END
  END a1[54]
  PIN a1[55]
    DIRECTION INPUT ;
    USE SIGNAL ;
    PORT
      LAYER M5 ;
        RECT  84.96 0 84.984 0.084 ;
    END
  END a1[55]
  PIN a1[56]
    DIRECTION INPUT ;
    USE SIGNAL ;
    PORT
      LAYER M5 ;
        RECT  85.104 0 85.128 0.084 ;
    END
  END a1[56]
  PIN a1[57]
    DIRECTION INPUT ;
    USE SIGNAL ;
    PORT
      LAYER M5 ;
        RECT  85.248 0 85.272 0.084 ;
    END
  END a1[57]
  PIN a1[58]
    DIRECTION INPUT ;
    USE SIGNAL ;
    PORT
      LAYER M5 ;
        RECT  85.392 0 85.416 0.084 ;
    END
  END a1[58]
  PIN a1[59]
    DIRECTION INPUT ;
    USE SIGNAL ;
    PORT
      LAYER M5 ;
        RECT  85.536 0 85.56 0.084 ;
    END
  END a1[59]
  PIN a1[5]
    DIRECTION INPUT ;
    USE SIGNAL ;
    PORT
      LAYER M5 ;
        RECT  111.168 0 111.192 0.084 ;
    END
  END a1[5]
  PIN a1[60]
    DIRECTION INPUT ;
    USE SIGNAL ;
    PORT
      LAYER M5 ;
        RECT  85.68 0 85.704 0.084 ;
    END
  END a1[60]
  PIN a1[61]
    DIRECTION INPUT ;
    USE SIGNAL ;
    PORT
      LAYER M5 ;
        RECT  85.824 0 85.848 0.084 ;
    END
  END a1[61]
  PIN a1[62]
    DIRECTION INPUT ;
    USE SIGNAL ;
    PORT
      LAYER M5 ;
        RECT  125.136 0 125.16 0.084 ;
    END
  END a1[62]
  PIN a1[63]
    DIRECTION INPUT ;
    USE SIGNAL ;
    PORT
      LAYER M5 ;
        RECT  125.28 0 125.304 0.084 ;
    END
  END a1[63]
  PIN a1[64]
    DIRECTION INPUT ;
    USE SIGNAL ;
    PORT
      LAYER M5 ;
        RECT  125.424 0 125.448 0.084 ;
    END
  END a1[64]
  PIN a1[65]
    DIRECTION INPUT ;
    USE SIGNAL ;
    PORT
      LAYER M5 ;
        RECT  125.568 0 125.592 0.084 ;
    END
  END a1[65]
  PIN a1[66]
    DIRECTION INPUT ;
    USE SIGNAL ;
    PORT
      LAYER M5 ;
        RECT  125.712 0 125.736 0.084 ;
    END
  END a1[66]
  PIN a1[67]
    DIRECTION INPUT ;
    USE SIGNAL ;
    PORT
      LAYER M5 ;
        RECT  125.856 0 125.88 0.084 ;
    END
  END a1[67]
  PIN a1[68]
    DIRECTION INPUT ;
    USE SIGNAL ;
    PORT
      LAYER M5 ;
        RECT  126 0 126.024 0.084 ;
    END
  END a1[68]
  PIN a1[69]
    DIRECTION INPUT ;
    USE SIGNAL ;
    PORT
      LAYER M5 ;
        RECT  126.144 0 126.168 0.084 ;
    END
  END a1[69]
  PIN a1[6]
    DIRECTION INPUT ;
    USE SIGNAL ;
    PORT
      LAYER M5 ;
        RECT  111.312 0 111.336 0.084 ;
    END
  END a1[6]
  PIN a1[70]
    DIRECTION INPUT ;
    USE SIGNAL ;
    PORT
      LAYER M5 ;
        RECT  126.288 0 126.312 0.084 ;
    END
  END a1[70]
  PIN a1[71]
    DIRECTION INPUT ;
    USE SIGNAL ;
    PORT
      LAYER M5 ;
        RECT  126.432 0 126.456 0.084 ;
    END
  END a1[71]
  PIN a1[72]
    DIRECTION INPUT ;
    USE SIGNAL ;
    PORT
      LAYER M5 ;
        RECT  126.576 0 126.6 0.084 ;
    END
  END a1[72]
  PIN a1[73]
    DIRECTION INPUT ;
    USE SIGNAL ;
    PORT
      LAYER M5 ;
        RECT  126.72 0 126.744 0.084 ;
    END
  END a1[73]
  PIN a1[74]
    DIRECTION INPUT ;
    USE SIGNAL ;
    PORT
      LAYER M5 ;
        RECT  126.864 0 126.888 0.084 ;
    END
  END a1[74]
  PIN a1[75]
    DIRECTION INPUT ;
    USE SIGNAL ;
    PORT
      LAYER M5 ;
        RECT  127.008 0 127.032 0.084 ;
    END
  END a1[75]
  PIN a1[76]
    DIRECTION INPUT ;
    USE SIGNAL ;
    PORT
      LAYER M5 ;
        RECT  127.152 0 127.176 0.084 ;
    END
  END a1[76]
  PIN a1[77]
    DIRECTION INPUT ;
    USE SIGNAL ;
    PORT
      LAYER M5 ;
        RECT  127.296 0 127.32 0.084 ;
    END
  END a1[77]
  PIN a1[78]
    DIRECTION INPUT ;
    USE SIGNAL ;
    PORT
      LAYER M5 ;
        RECT  127.44 0 127.464 0.084 ;
    END
  END a1[78]
  PIN a1[79]
    DIRECTION INPUT ;
    USE SIGNAL ;
    PORT
      LAYER M5 ;
        RECT  127.584 0 127.608 0.084 ;
    END
  END a1[79]
  PIN a1[7]
    DIRECTION INPUT ;
    USE SIGNAL ;
    PORT
      LAYER M5 ;
        RECT  111.456 0 111.48 0.084 ;
    END
  END a1[7]
  PIN a1[80]
    DIRECTION INPUT ;
    USE SIGNAL ;
    PORT
      LAYER M5 ;
        RECT  127.728 0 127.752 0.084 ;
    END
  END a1[80]
  PIN a1[81]
    DIRECTION INPUT ;
    USE SIGNAL ;
    PORT
      LAYER M5 ;
        RECT  127.872 0 127.896 0.084 ;
    END
  END a1[81]
  PIN a1[82]
    DIRECTION INPUT ;
    USE SIGNAL ;
    PORT
      LAYER M5 ;
        RECT  128.016 0 128.04 0.084 ;
    END
  END a1[82]
  PIN a1[83]
    DIRECTION INPUT ;
    USE SIGNAL ;
    PORT
      LAYER M5 ;
        RECT  128.16 0 128.184 0.084 ;
    END
  END a1[83]
  PIN a1[84]
    DIRECTION INPUT ;
    USE SIGNAL ;
    PORT
      LAYER M5 ;
        RECT  128.304 0 128.328 0.084 ;
    END
  END a1[84]
  PIN a1[85]
    DIRECTION INPUT ;
    USE SIGNAL ;
    PORT
      LAYER M5 ;
        RECT  128.448 0 128.472 0.084 ;
    END
  END a1[85]
  PIN a1[86]
    DIRECTION INPUT ;
    USE SIGNAL ;
    PORT
      LAYER M5 ;
        RECT  128.592 0 128.616 0.084 ;
    END
  END a1[86]
  PIN a1[87]
    DIRECTION INPUT ;
    USE SIGNAL ;
    PORT
      LAYER M5 ;
        RECT  128.736 0 128.76 0.084 ;
    END
  END a1[87]
  PIN a1[88]
    DIRECTION INPUT ;
    USE SIGNAL ;
    PORT
      LAYER M5 ;
        RECT  128.88 0 128.904 0.084 ;
    END
  END a1[88]
  PIN a1[89]
    DIRECTION INPUT ;
    USE SIGNAL ;
    PORT
      LAYER M5 ;
        RECT  129.024 0 129.048 0.084 ;
    END
  END a1[89]
  PIN a1[8]
    DIRECTION INPUT ;
    USE SIGNAL ;
    PORT
      LAYER M5 ;
        RECT  111.6 0 111.624 0.084 ;
    END
  END a1[8]
  PIN a1[90]
    DIRECTION INPUT ;
    USE SIGNAL ;
    PORT
      LAYER M5 ;
        RECT  129.168 0 129.192 0.084 ;
    END
  END a1[90]
  PIN a1[91]
    DIRECTION INPUT ;
    USE SIGNAL ;
    PORT
      LAYER M5 ;
        RECT  129.312 0 129.336 0.084 ;
    END
  END a1[91]
  PIN a1[92]
    DIRECTION INPUT ;
    USE SIGNAL ;
    PORT
      LAYER M5 ;
        RECT  129.456 0 129.48 0.084 ;
    END
  END a1[92]
  PIN a1[93]
    DIRECTION INPUT ;
    USE SIGNAL ;
    PORT
      LAYER M5 ;
        RECT  129.6 0 129.624 0.084 ;
    END
  END a1[93]
  PIN a1[94]
    DIRECTION INPUT ;
    USE SIGNAL ;
    PORT
      LAYER M5 ;
        RECT  138.96 0 138.984 0.084 ;
    END
  END a1[94]
  PIN a1[95]
    DIRECTION INPUT ;
    USE SIGNAL ;
    PORT
      LAYER M5 ;
        RECT  139.104 0 139.128 0.084 ;
    END
  END a1[95]
  PIN a1[96]
    DIRECTION INPUT ;
    USE SIGNAL ;
    PORT
      LAYER M5 ;
        RECT  139.248 0 139.272 0.084 ;
    END
  END a1[96]
  PIN a1[97]
    DIRECTION INPUT ;
    USE SIGNAL ;
    PORT
      LAYER M5 ;
        RECT  139.392 0 139.416 0.084 ;
    END
  END a1[97]
  PIN a1[98]
    DIRECTION INPUT ;
    USE SIGNAL ;
    PORT
      LAYER M5 ;
        RECT  139.536 0 139.56 0.084 ;
    END
  END a1[98]
  PIN a1[99]
    DIRECTION INPUT ;
    USE SIGNAL ;
    PORT
      LAYER M5 ;
        RECT  139.68 0 139.704 0.084 ;
    END
  END a1[99]
  PIN a1[9]
    DIRECTION INPUT ;
    USE SIGNAL ;
    PORT
      LAYER M5 ;
        RECT  111.744 0 111.768 0.084 ;
    END
  END a1[9]
  PIN b0[0]
    DIRECTION INPUT ;
    USE SIGNAL ;
    PORT
      LAYER M5 ;
        RECT  130.32 0 130.344 0.084 ;
    END
  END b0[0]
  PIN b0[100]
    DIRECTION INPUT ;
    USE SIGNAL ;
    PORT
      LAYER M5 ;
        RECT  117.072 0 117.096 0.084 ;
    END
  END b0[100]
  PIN b0[101]
    DIRECTION INPUT ;
    USE SIGNAL ;
    PORT
      LAYER M5 ;
        RECT  117.216 0 117.24 0.084 ;
    END
  END b0[101]
  PIN b0[102]
    DIRECTION INPUT ;
    USE SIGNAL ;
    PORT
      LAYER M5 ;
        RECT  117.36 0 117.384 0.084 ;
    END
  END b0[102]
  PIN b0[103]
    DIRECTION INPUT ;
    USE SIGNAL ;
    PORT
      LAYER M5 ;
        RECT  117.504 0 117.528 0.084 ;
    END
  END b0[103]
  PIN b0[104]
    DIRECTION INPUT ;
    USE SIGNAL ;
    PORT
      LAYER M5 ;
        RECT  117.648 0 117.672 0.084 ;
    END
  END b0[104]
  PIN b0[105]
    DIRECTION INPUT ;
    USE SIGNAL ;
    PORT
      LAYER M5 ;
        RECT  117.792 0 117.816 0.084 ;
    END
  END b0[105]
  PIN b0[106]
    DIRECTION INPUT ;
    USE SIGNAL ;
    PORT
      LAYER M5 ;
        RECT  117.936 0 117.96 0.084 ;
    END
  END b0[106]
  PIN b0[107]
    DIRECTION INPUT ;
    USE SIGNAL ;
    PORT
      LAYER M5 ;
        RECT  118.08 0 118.104 0.084 ;
    END
  END b0[107]
  PIN b0[108]
    DIRECTION INPUT ;
    USE SIGNAL ;
    PORT
      LAYER M5 ;
        RECT  118.224 0 118.248 0.084 ;
    END
  END b0[108]
  PIN b0[109]
    DIRECTION INPUT ;
    USE SIGNAL ;
    PORT
      LAYER M5 ;
        RECT  118.368 0 118.392 0.084 ;
    END
  END b0[109]
  PIN b0[10]
    DIRECTION INPUT ;
    USE SIGNAL ;
    PORT
      LAYER M5 ;
        RECT  131.76 0 131.784 0.084 ;
    END
  END b0[10]
  PIN b0[110]
    DIRECTION INPUT ;
    USE SIGNAL ;
    PORT
      LAYER M5 ;
        RECT  118.512 0 118.536 0.084 ;
    END
  END b0[110]
  PIN b0[111]
    DIRECTION INPUT ;
    USE SIGNAL ;
    PORT
      LAYER M5 ;
        RECT  118.656 0 118.68 0.084 ;
    END
  END b0[111]
  PIN b0[112]
    DIRECTION INPUT ;
    USE SIGNAL ;
    PORT
      LAYER M5 ;
        RECT  118.8 0 118.824 0.084 ;
    END
  END b0[112]
  PIN b0[113]
    DIRECTION INPUT ;
    USE SIGNAL ;
    PORT
      LAYER M5 ;
        RECT  118.944 0 118.968 0.084 ;
    END
  END b0[113]
  PIN b0[114]
    DIRECTION INPUT ;
    USE SIGNAL ;
    PORT
      LAYER M5 ;
        RECT  119.088 0 119.112 0.084 ;
    END
  END b0[114]
  PIN b0[115]
    DIRECTION INPUT ;
    USE SIGNAL ;
    PORT
      LAYER M5 ;
        RECT  119.232 0 119.256 0.084 ;
    END
  END b0[115]
  PIN b0[116]
    DIRECTION INPUT ;
    USE SIGNAL ;
    PORT
      LAYER M5 ;
        RECT  119.376 0 119.4 0.084 ;
    END
  END b0[116]
  PIN b0[117]
    DIRECTION INPUT ;
    USE SIGNAL ;
    PORT
      LAYER M5 ;
        RECT  119.52 0 119.544 0.084 ;
    END
  END b0[117]
  PIN b0[118]
    DIRECTION INPUT ;
    USE SIGNAL ;
    PORT
      LAYER M5 ;
        RECT  119.664 0 119.688 0.084 ;
    END
  END b0[118]
  PIN b0[119]
    DIRECTION INPUT ;
    USE SIGNAL ;
    PORT
      LAYER M5 ;
        RECT  119.808 0 119.832 0.084 ;
    END
  END b0[119]
  PIN b0[11]
    DIRECTION INPUT ;
    USE SIGNAL ;
    PORT
      LAYER M5 ;
        RECT  131.904 0 131.928 0.084 ;
    END
  END b0[11]
  PIN b0[120]
    DIRECTION INPUT ;
    USE SIGNAL ;
    PORT
      LAYER M5 ;
        RECT  119.952 0 119.976 0.084 ;
    END
  END b0[120]
  PIN b0[121]
    DIRECTION INPUT ;
    USE SIGNAL ;
    PORT
      LAYER M5 ;
        RECT  120.096 0 120.12 0.084 ;
    END
  END b0[121]
  PIN b0[122]
    DIRECTION INPUT ;
    USE SIGNAL ;
    PORT
      LAYER M5 ;
        RECT  120.24 0 120.264 0.084 ;
    END
  END b0[122]
  PIN b0[123]
    DIRECTION INPUT ;
    USE SIGNAL ;
    PORT
      LAYER M5 ;
        RECT  120.384 0 120.408 0.084 ;
    END
  END b0[123]
  PIN b0[124]
    DIRECTION INPUT ;
    USE SIGNAL ;
    PORT
      LAYER M5 ;
        RECT  134.352 0 134.376 0.084 ;
    END
  END b0[124]
  PIN b0[125]
    DIRECTION INPUT ;
    USE SIGNAL ;
    PORT
      LAYER M5 ;
        RECT  134.496 0 134.52 0.084 ;
    END
  END b0[125]
  PIN b0[126]
    DIRECTION INPUT ;
    USE SIGNAL ;
    PORT
      LAYER M5 ;
        RECT  134.64 0 134.664 0.084 ;
    END
  END b0[126]
  PIN b0[127]
    DIRECTION INPUT ;
    USE SIGNAL ;
    PORT
      LAYER M5 ;
        RECT  134.784 0 134.808 0.084 ;
    END
  END b0[127]
  PIN b0[128]
    DIRECTION INPUT ;
    USE SIGNAL ;
    PORT
      LAYER M5 ;
        RECT  134.928 0 134.952 0.084 ;
    END
  END b0[128]
  PIN b0[129]
    DIRECTION INPUT ;
    USE SIGNAL ;
    PORT
      LAYER M5 ;
        RECT  135.072 0 135.096 0.084 ;
    END
  END b0[129]
  PIN b0[12]
    DIRECTION INPUT ;
    USE SIGNAL ;
    PORT
      LAYER M5 ;
        RECT  132.048 0 132.072 0.084 ;
    END
  END b0[12]
  PIN b0[130]
    DIRECTION INPUT ;
    USE SIGNAL ;
    PORT
      LAYER M5 ;
        RECT  135.216 0 135.24 0.084 ;
    END
  END b0[130]
  PIN b0[131]
    DIRECTION INPUT ;
    USE SIGNAL ;
    PORT
      LAYER M5 ;
        RECT  135.36 0 135.384 0.084 ;
    END
  END b0[131]
  PIN b0[132]
    DIRECTION INPUT ;
    USE SIGNAL ;
    PORT
      LAYER M5 ;
        RECT  135.504 0 135.528 0.084 ;
    END
  END b0[132]
  PIN b0[133]
    DIRECTION INPUT ;
    USE SIGNAL ;
    PORT
      LAYER M5 ;
        RECT  135.648 0 135.672 0.084 ;
    END
  END b0[133]
  PIN b0[134]
    DIRECTION INPUT ;
    USE SIGNAL ;
    PORT
      LAYER M5 ;
        RECT  135.792 0 135.816 0.084 ;
    END
  END b0[134]
  PIN b0[135]
    DIRECTION INPUT ;
    USE SIGNAL ;
    PORT
      LAYER M5 ;
        RECT  135.936 0 135.96 0.084 ;
    END
  END b0[135]
  PIN b0[136]
    DIRECTION INPUT ;
    USE SIGNAL ;
    PORT
      LAYER M5 ;
        RECT  136.08 0 136.104 0.084 ;
    END
  END b0[136]
  PIN b0[137]
    DIRECTION INPUT ;
    USE SIGNAL ;
    PORT
      LAYER M5 ;
        RECT  136.224 0 136.248 0.084 ;
    END
  END b0[137]
  PIN b0[138]
    DIRECTION INPUT ;
    USE SIGNAL ;
    PORT
      LAYER M5 ;
        RECT  136.368 0 136.392 0.084 ;
    END
  END b0[138]
  PIN b0[139]
    DIRECTION INPUT ;
    USE SIGNAL ;
    PORT
      LAYER M5 ;
        RECT  136.512 0 136.536 0.084 ;
    END
  END b0[139]
  PIN b0[13]
    DIRECTION INPUT ;
    USE SIGNAL ;
    PORT
      LAYER M5 ;
        RECT  132.192 0 132.216 0.084 ;
    END
  END b0[13]
  PIN b0[140]
    DIRECTION INPUT ;
    USE SIGNAL ;
    PORT
      LAYER M5 ;
        RECT  136.656 0 136.68 0.084 ;
    END
  END b0[140]
  PIN b0[141]
    DIRECTION INPUT ;
    USE SIGNAL ;
    PORT
      LAYER M5 ;
        RECT  136.8 0 136.824 0.084 ;
    END
  END b0[141]
  PIN b0[142]
    DIRECTION INPUT ;
    USE SIGNAL ;
    PORT
      LAYER M5 ;
        RECT  136.944 0 136.968 0.084 ;
    END
  END b0[142]
  PIN b0[143]
    DIRECTION INPUT ;
    USE SIGNAL ;
    PORT
      LAYER M5 ;
        RECT  137.088 0 137.112 0.084 ;
    END
  END b0[143]
  PIN b0[144]
    DIRECTION INPUT ;
    USE SIGNAL ;
    PORT
      LAYER M5 ;
        RECT  137.232 0 137.256 0.084 ;
    END
  END b0[144]
  PIN b0[145]
    DIRECTION INPUT ;
    USE SIGNAL ;
    PORT
      LAYER M5 ;
        RECT  137.376 0 137.4 0.084 ;
    END
  END b0[145]
  PIN b0[146]
    DIRECTION INPUT ;
    USE SIGNAL ;
    PORT
      LAYER M5 ;
        RECT  137.52 0 137.544 0.084 ;
    END
  END b0[146]
  PIN b0[147]
    DIRECTION INPUT ;
    USE SIGNAL ;
    PORT
      LAYER M5 ;
        RECT  137.664 0 137.688 0.084 ;
    END
  END b0[147]
  PIN b0[148]
    DIRECTION INPUT ;
    USE SIGNAL ;
    PORT
      LAYER M5 ;
        RECT  137.808 0 137.832 0.084 ;
    END
  END b0[148]
  PIN b0[149]
    DIRECTION INPUT ;
    USE SIGNAL ;
    PORT
      LAYER M5 ;
        RECT  137.952 0 137.976 0.084 ;
    END
  END b0[149]
  PIN b0[14]
    DIRECTION INPUT ;
    USE SIGNAL ;
    PORT
      LAYER M5 ;
        RECT  132.336 0 132.36 0.084 ;
    END
  END b0[14]
  PIN b0[150]
    DIRECTION INPUT ;
    USE SIGNAL ;
    PORT
      LAYER M5 ;
        RECT  138.096 0 138.12 0.084 ;
    END
  END b0[150]
  PIN b0[151]
    DIRECTION INPUT ;
    USE SIGNAL ;
    PORT
      LAYER M5 ;
        RECT  138.24 0 138.264 0.084 ;
    END
  END b0[151]
  PIN b0[152]
    DIRECTION INPUT ;
    USE SIGNAL ;
    PORT
      LAYER M5 ;
        RECT  138.384 0 138.408 0.084 ;
    END
  END b0[152]
  PIN b0[153]
    DIRECTION INPUT ;
    USE SIGNAL ;
    PORT
      LAYER M5 ;
        RECT  138.528 0 138.552 0.084 ;
    END
  END b0[153]
  PIN b0[154]
    DIRECTION INPUT ;
    USE SIGNAL ;
    PORT
      LAYER M5 ;
        RECT  138.672 0 138.696 0.084 ;
    END
  END b0[154]
  PIN b0[155]
    DIRECTION INPUT ;
    USE SIGNAL ;
    PORT
      LAYER M5 ;
        RECT  138.816 0 138.84 0.084 ;
    END
  END b0[155]
  PIN b0[156]
    DIRECTION INPUT ;
    USE SIGNAL ;
    PORT
      LAYER M5 ;
        RECT  47.952 0 47.976 0.084 ;
    END
  END b0[156]
  PIN b0[157]
    DIRECTION INPUT ;
    USE SIGNAL ;
    PORT
      LAYER M5 ;
        RECT  48.096 0 48.12 0.084 ;
    END
  END b0[157]
  PIN b0[158]
    DIRECTION INPUT ;
    USE SIGNAL ;
    PORT
      LAYER M5 ;
        RECT  48.24 0 48.264 0.084 ;
    END
  END b0[158]
  PIN b0[159]
    DIRECTION INPUT ;
    USE SIGNAL ;
    PORT
      LAYER M5 ;
        RECT  48.384 0 48.408 0.084 ;
    END
  END b0[159]
  PIN b0[15]
    DIRECTION INPUT ;
    USE SIGNAL ;
    PORT
      LAYER M5 ;
        RECT  132.48 0 132.504 0.084 ;
    END
  END b0[15]
  PIN b0[160]
    DIRECTION INPUT ;
    USE SIGNAL ;
    PORT
      LAYER M5 ;
        RECT  48.528 0 48.552 0.084 ;
    END
  END b0[160]
  PIN b0[161]
    DIRECTION INPUT ;
    USE SIGNAL ;
    PORT
      LAYER M5 ;
        RECT  48.672 0 48.696 0.084 ;
    END
  END b0[161]
  PIN b0[162]
    DIRECTION INPUT ;
    USE SIGNAL ;
    PORT
      LAYER M5 ;
        RECT  48.816 0 48.84 0.084 ;
    END
  END b0[162]
  PIN b0[163]
    DIRECTION INPUT ;
    USE SIGNAL ;
    PORT
      LAYER M5 ;
        RECT  48.96 0 48.984 0.084 ;
    END
  END b0[163]
  PIN b0[164]
    DIRECTION INPUT ;
    USE SIGNAL ;
    PORT
      LAYER M5 ;
        RECT  49.104 0 49.128 0.084 ;
    END
  END b0[164]
  PIN b0[165]
    DIRECTION INPUT ;
    USE SIGNAL ;
    PORT
      LAYER M5 ;
        RECT  49.248 0 49.272 0.084 ;
    END
  END b0[165]
  PIN b0[166]
    DIRECTION INPUT ;
    USE SIGNAL ;
    PORT
      LAYER M5 ;
        RECT  49.392 0 49.416 0.084 ;
    END
  END b0[166]
  PIN b0[167]
    DIRECTION INPUT ;
    USE SIGNAL ;
    PORT
      LAYER M5 ;
        RECT  49.536 0 49.56 0.084 ;
    END
  END b0[167]
  PIN b0[168]
    DIRECTION INPUT ;
    USE SIGNAL ;
    PORT
      LAYER M5 ;
        RECT  49.68 0 49.704 0.084 ;
    END
  END b0[168]
  PIN b0[169]
    DIRECTION INPUT ;
    USE SIGNAL ;
    PORT
      LAYER M5 ;
        RECT  49.824 0 49.848 0.084 ;
    END
  END b0[169]
  PIN b0[16]
    DIRECTION INPUT ;
    USE SIGNAL ;
    PORT
      LAYER M5 ;
        RECT  132.624 0 132.648 0.084 ;
    END
  END b0[16]
  PIN b0[170]
    DIRECTION INPUT ;
    USE SIGNAL ;
    PORT
      LAYER M5 ;
        RECT  49.968 0 49.992 0.084 ;
    END
  END b0[170]
  PIN b0[171]
    DIRECTION INPUT ;
    USE SIGNAL ;
    PORT
      LAYER M5 ;
        RECT  50.112 0 50.136 0.084 ;
    END
  END b0[171]
  PIN b0[172]
    DIRECTION INPUT ;
    USE SIGNAL ;
    PORT
      LAYER M5 ;
        RECT  50.256 0 50.28 0.084 ;
    END
  END b0[172]
  PIN b0[173]
    DIRECTION INPUT ;
    USE SIGNAL ;
    PORT
      LAYER M5 ;
        RECT  50.4 0 50.424 0.084 ;
    END
  END b0[173]
  PIN b0[174]
    DIRECTION INPUT ;
    USE SIGNAL ;
    PORT
      LAYER M5 ;
        RECT  50.544 0 50.568 0.084 ;
    END
  END b0[174]
  PIN b0[175]
    DIRECTION INPUT ;
    USE SIGNAL ;
    PORT
      LAYER M5 ;
        RECT  50.688 0 50.712 0.084 ;
    END
  END b0[175]
  PIN b0[176]
    DIRECTION INPUT ;
    USE SIGNAL ;
    PORT
      LAYER M5 ;
        RECT  50.832 0 50.856 0.084 ;
    END
  END b0[176]
  PIN b0[177]
    DIRECTION INPUT ;
    USE SIGNAL ;
    PORT
      LAYER M5 ;
        RECT  50.976 0 51 0.084 ;
    END
  END b0[177]
  PIN b0[178]
    DIRECTION INPUT ;
    USE SIGNAL ;
    PORT
      LAYER M5 ;
        RECT  51.12 0 51.144 0.084 ;
    END
  END b0[178]
  PIN b0[179]
    DIRECTION INPUT ;
    USE SIGNAL ;
    PORT
      LAYER M5 ;
        RECT  51.264 0 51.288 0.084 ;
    END
  END b0[179]
  PIN b0[17]
    DIRECTION INPUT ;
    USE SIGNAL ;
    PORT
      LAYER M5 ;
        RECT  132.768 0 132.792 0.084 ;
    END
  END b0[17]
  PIN b0[180]
    DIRECTION INPUT ;
    USE SIGNAL ;
    PORT
      LAYER M5 ;
        RECT  51.408 0 51.432 0.084 ;
    END
  END b0[180]
  PIN b0[181]
    DIRECTION INPUT ;
    USE SIGNAL ;
    PORT
      LAYER M5 ;
        RECT  51.552 0 51.576 0.084 ;
    END
  END b0[181]
  PIN b0[182]
    DIRECTION INPUT ;
    USE SIGNAL ;
    PORT
      LAYER M5 ;
        RECT  51.696 0 51.72 0.084 ;
    END
  END b0[182]
  PIN b0[183]
    DIRECTION INPUT ;
    USE SIGNAL ;
    PORT
      LAYER M5 ;
        RECT  51.84 0 51.864 0.084 ;
    END
  END b0[183]
  PIN b0[184]
    DIRECTION INPUT ;
    USE SIGNAL ;
    PORT
      LAYER M5 ;
        RECT  51.984 0 52.008 0.084 ;
    END
  END b0[184]
  PIN b0[185]
    DIRECTION INPUT ;
    USE SIGNAL ;
    PORT
      LAYER M5 ;
        RECT  52.128 0 52.152 0.084 ;
    END
  END b0[185]
  PIN b0[186]
    DIRECTION INPUT ;
    USE SIGNAL ;
    PORT
      LAYER M5 ;
        RECT  52.272 0 52.296 0.084 ;
    END
  END b0[186]
  PIN b0[187]
    DIRECTION INPUT ;
    USE SIGNAL ;
    PORT
      LAYER M5 ;
        RECT  52.416 0 52.44 0.084 ;
    END
  END b0[187]
  PIN b0[188]
    DIRECTION INPUT ;
    USE SIGNAL ;
    PORT
      LAYER M5 ;
        RECT  52.56 0 52.584 0.084 ;
    END
  END b0[188]
  PIN b0[189]
    DIRECTION INPUT ;
    USE SIGNAL ;
    PORT
      LAYER M5 ;
        RECT  52.704 0 52.728 0.084 ;
    END
  END b0[189]
  PIN b0[18]
    DIRECTION INPUT ;
    USE SIGNAL ;
    PORT
      LAYER M5 ;
        RECT  132.912 0 132.936 0.084 ;
    END
  END b0[18]
  PIN b0[190]
    DIRECTION INPUT ;
    USE SIGNAL ;
    PORT
      LAYER M5 ;
        RECT  52.848 0 52.872 0.084 ;
    END
  END b0[190]
  PIN b0[191]
    DIRECTION INPUT ;
    USE SIGNAL ;
    PORT
      LAYER M5 ;
        RECT  52.992 0 53.016 0.084 ;
    END
  END b0[191]
  PIN b0[192]
    DIRECTION INPUT ;
    USE SIGNAL ;
    PORT
      LAYER M5 ;
        RECT  53.136 0 53.16 0.084 ;
    END
  END b0[192]
  PIN b0[193]
    DIRECTION INPUT ;
    USE SIGNAL ;
    PORT
      LAYER M5 ;
        RECT  53.28 0 53.304 0.084 ;
    END
  END b0[193]
  PIN b0[194]
    DIRECTION INPUT ;
    USE SIGNAL ;
    PORT
      LAYER M5 ;
        RECT  53.424 0 53.448 0.084 ;
    END
  END b0[194]
  PIN b0[195]
    DIRECTION INPUT ;
    USE SIGNAL ;
    PORT
      LAYER M5 ;
        RECT  53.568 0 53.592 0.084 ;
    END
  END b0[195]
  PIN b0[196]
    DIRECTION INPUT ;
    USE SIGNAL ;
    PORT
      LAYER M5 ;
        RECT  53.712 0 53.736 0.084 ;
    END
  END b0[196]
  PIN b0[197]
    DIRECTION INPUT ;
    USE SIGNAL ;
    PORT
      LAYER M5 ;
        RECT  53.856 0 53.88 0.084 ;
    END
  END b0[197]
  PIN b0[198]
    DIRECTION INPUT ;
    USE SIGNAL ;
    PORT
      LAYER M5 ;
        RECT  54 0 54.024 0.084 ;
    END
  END b0[198]
  PIN b0[199]
    DIRECTION INPUT ;
    USE SIGNAL ;
    PORT
      LAYER M5 ;
        RECT  54.144 0 54.168 0.084 ;
    END
  END b0[199]
  PIN b0[19]
    DIRECTION INPUT ;
    USE SIGNAL ;
    PORT
      LAYER M5 ;
        RECT  133.056 0 133.08 0.084 ;
    END
  END b0[19]
  PIN b0[1]
    DIRECTION INPUT ;
    USE SIGNAL ;
    PORT
      LAYER M5 ;
        RECT  130.464 0 130.488 0.084 ;
    END
  END b0[1]
  PIN b0[200]
    DIRECTION INPUT ;
    USE SIGNAL ;
    PORT
      LAYER M5 ;
        RECT  54.288 0 54.312 0.084 ;
    END
  END b0[200]
  PIN b0[201]
    DIRECTION INPUT ;
    USE SIGNAL ;
    PORT
      LAYER M5 ;
        RECT  54.432 0 54.456 0.084 ;
    END
  END b0[201]
  PIN b0[202]
    DIRECTION INPUT ;
    USE SIGNAL ;
    PORT
      LAYER M5 ;
        RECT  54.576 0 54.6 0.084 ;
    END
  END b0[202]
  PIN b0[203]
    DIRECTION INPUT ;
    USE SIGNAL ;
    PORT
      LAYER M5 ;
        RECT  54.72 0 54.744 0.084 ;
    END
  END b0[203]
  PIN b0[204]
    DIRECTION INPUT ;
    USE SIGNAL ;
    PORT
      LAYER M5 ;
        RECT  54.864 0 54.888 0.084 ;
    END
  END b0[204]
  PIN b0[205]
    DIRECTION INPUT ;
    USE SIGNAL ;
    PORT
      LAYER M5 ;
        RECT  55.008 0 55.032 0.084 ;
    END
  END b0[205]
  PIN b0[206]
    DIRECTION INPUT ;
    USE SIGNAL ;
    PORT
      LAYER M5 ;
        RECT  55.152 0 55.176 0.084 ;
    END
  END b0[206]
  PIN b0[207]
    DIRECTION INPUT ;
    USE SIGNAL ;
    PORT
      LAYER M5 ;
        RECT  55.296 0 55.32 0.084 ;
    END
  END b0[207]
  PIN b0[208]
    DIRECTION INPUT ;
    USE SIGNAL ;
    PORT
      LAYER M5 ;
        RECT  55.44 0 55.464 0.084 ;
    END
  END b0[208]
  PIN b0[209]
    DIRECTION INPUT ;
    USE SIGNAL ;
    PORT
      LAYER M5 ;
        RECT  55.584 0 55.608 0.084 ;
    END
  END b0[209]
  PIN b0[20]
    DIRECTION INPUT ;
    USE SIGNAL ;
    PORT
      LAYER M5 ;
        RECT  133.2 0 133.224 0.084 ;
    END
  END b0[20]
  PIN b0[210]
    DIRECTION INPUT ;
    USE SIGNAL ;
    PORT
      LAYER M5 ;
        RECT  55.728 0 55.752 0.084 ;
    END
  END b0[210]
  PIN b0[211]
    DIRECTION INPUT ;
    USE SIGNAL ;
    PORT
      LAYER M5 ;
        RECT  55.872 0 55.896 0.084 ;
    END
  END b0[211]
  PIN b0[212]
    DIRECTION INPUT ;
    USE SIGNAL ;
    PORT
      LAYER M5 ;
        RECT  56.016 0 56.04 0.084 ;
    END
  END b0[212]
  PIN b0[213]
    DIRECTION INPUT ;
    USE SIGNAL ;
    PORT
      LAYER M5 ;
        RECT  56.16 0 56.184 0.084 ;
    END
  END b0[213]
  PIN b0[214]
    DIRECTION INPUT ;
    USE SIGNAL ;
    PORT
      LAYER M5 ;
        RECT  56.304 0 56.328 0.084 ;
    END
  END b0[214]
  PIN b0[215]
    DIRECTION INPUT ;
    USE SIGNAL ;
    PORT
      LAYER M5 ;
        RECT  56.448 0 56.472 0.084 ;
    END
  END b0[215]
  PIN b0[216]
    DIRECTION INPUT ;
    USE SIGNAL ;
    PORT
      LAYER M5 ;
        RECT  56.592 0 56.616 0.084 ;
    END
  END b0[216]
  PIN b0[217]
    DIRECTION INPUT ;
    USE SIGNAL ;
    PORT
      LAYER M5 ;
        RECT  56.736 0 56.76 0.084 ;
    END
  END b0[217]
  PIN b0[218]
    DIRECTION INPUT ;
    USE SIGNAL ;
    PORT
      LAYER M5 ;
        RECT  56.88 0 56.904 0.084 ;
    END
  END b0[218]
  PIN b0[219]
    DIRECTION INPUT ;
    USE SIGNAL ;
    PORT
      LAYER M5 ;
        RECT  57.024 0 57.048 0.084 ;
    END
  END b0[219]
  PIN b0[21]
    DIRECTION INPUT ;
    USE SIGNAL ;
    PORT
      LAYER M5 ;
        RECT  133.344 0 133.368 0.084 ;
    END
  END b0[21]
  PIN b0[220]
    DIRECTION INPUT ;
    USE SIGNAL ;
    PORT
      LAYER M5 ;
        RECT  29.52 0 29.544 0.084 ;
    END
  END b0[220]
  PIN b0[221]
    DIRECTION INPUT ;
    USE SIGNAL ;
    PORT
      LAYER M5 ;
        RECT  29.664 0 29.688 0.084 ;
    END
  END b0[221]
  PIN b0[222]
    DIRECTION INPUT ;
    USE SIGNAL ;
    PORT
      LAYER M5 ;
        RECT  29.808 0 29.832 0.084 ;
    END
  END b0[222]
  PIN b0[223]
    DIRECTION INPUT ;
    USE SIGNAL ;
    PORT
      LAYER M5 ;
        RECT  29.952 0 29.976 0.084 ;
    END
  END b0[223]
  PIN b0[224]
    DIRECTION INPUT ;
    USE SIGNAL ;
    PORT
      LAYER M5 ;
        RECT  30.096 0 30.12 0.084 ;
    END
  END b0[224]
  PIN b0[225]
    DIRECTION INPUT ;
    USE SIGNAL ;
    PORT
      LAYER M5 ;
        RECT  30.24 0 30.264 0.084 ;
    END
  END b0[225]
  PIN b0[226]
    DIRECTION INPUT ;
    USE SIGNAL ;
    PORT
      LAYER M5 ;
        RECT  30.384 0 30.408 0.084 ;
    END
  END b0[226]
  PIN b0[227]
    DIRECTION INPUT ;
    USE SIGNAL ;
    PORT
      LAYER M5 ;
        RECT  30.528 0 30.552 0.084 ;
    END
  END b0[227]
  PIN b0[228]
    DIRECTION INPUT ;
    USE SIGNAL ;
    PORT
      LAYER M5 ;
        RECT  30.672 0 30.696 0.084 ;
    END
  END b0[228]
  PIN b0[229]
    DIRECTION INPUT ;
    USE SIGNAL ;
    PORT
      LAYER M5 ;
        RECT  30.816 0 30.84 0.084 ;
    END
  END b0[229]
  PIN b0[22]
    DIRECTION INPUT ;
    USE SIGNAL ;
    PORT
      LAYER M5 ;
        RECT  133.488 0 133.512 0.084 ;
    END
  END b0[22]
  PIN b0[230]
    DIRECTION INPUT ;
    USE SIGNAL ;
    PORT
      LAYER M5 ;
        RECT  30.96 0 30.984 0.084 ;
    END
  END b0[230]
  PIN b0[231]
    DIRECTION INPUT ;
    USE SIGNAL ;
    PORT
      LAYER M5 ;
        RECT  31.104 0 31.128 0.084 ;
    END
  END b0[231]
  PIN b0[232]
    DIRECTION INPUT ;
    USE SIGNAL ;
    PORT
      LAYER M5 ;
        RECT  31.248 0 31.272 0.084 ;
    END
  END b0[232]
  PIN b0[233]
    DIRECTION INPUT ;
    USE SIGNAL ;
    PORT
      LAYER M5 ;
        RECT  31.392 0 31.416 0.084 ;
    END
  END b0[233]
  PIN b0[234]
    DIRECTION INPUT ;
    USE SIGNAL ;
    PORT
      LAYER M5 ;
        RECT  31.536 0 31.56 0.084 ;
    END
  END b0[234]
  PIN b0[235]
    DIRECTION INPUT ;
    USE SIGNAL ;
    PORT
      LAYER M5 ;
        RECT  31.68 0 31.704 0.084 ;
    END
  END b0[235]
  PIN b0[236]
    DIRECTION INPUT ;
    USE SIGNAL ;
    PORT
      LAYER M5 ;
        RECT  31.824 0 31.848 0.084 ;
    END
  END b0[236]
  PIN b0[237]
    DIRECTION INPUT ;
    USE SIGNAL ;
    PORT
      LAYER M5 ;
        RECT  31.968 0 31.992 0.084 ;
    END
  END b0[237]
  PIN b0[238]
    DIRECTION INPUT ;
    USE SIGNAL ;
    PORT
      LAYER M5 ;
        RECT  32.112 0 32.136 0.084 ;
    END
  END b0[238]
  PIN b0[239]
    DIRECTION INPUT ;
    USE SIGNAL ;
    PORT
      LAYER M5 ;
        RECT  32.256 0 32.28 0.084 ;
    END
  END b0[239]
  PIN b0[23]
    DIRECTION INPUT ;
    USE SIGNAL ;
    PORT
      LAYER M5 ;
        RECT  133.632 0 133.656 0.084 ;
    END
  END b0[23]
  PIN b0[240]
    DIRECTION INPUT ;
    USE SIGNAL ;
    PORT
      LAYER M5 ;
        RECT  32.4 0 32.424 0.084 ;
    END
  END b0[240]
  PIN b0[241]
    DIRECTION INPUT ;
    USE SIGNAL ;
    PORT
      LAYER M5 ;
        RECT  32.544 0 32.568 0.084 ;
    END
  END b0[241]
  PIN b0[242]
    DIRECTION INPUT ;
    USE SIGNAL ;
    PORT
      LAYER M5 ;
        RECT  32.688 0 32.712 0.084 ;
    END
  END b0[242]
  PIN b0[243]
    DIRECTION INPUT ;
    USE SIGNAL ;
    PORT
      LAYER M5 ;
        RECT  32.832 0 32.856 0.084 ;
    END
  END b0[243]
  PIN b0[244]
    DIRECTION INPUT ;
    USE SIGNAL ;
    PORT
      LAYER M5 ;
        RECT  32.976 0 33 0.084 ;
    END
  END b0[244]
  PIN b0[245]
    DIRECTION INPUT ;
    USE SIGNAL ;
    PORT
      LAYER M5 ;
        RECT  33.12 0 33.144 0.084 ;
    END
  END b0[245]
  PIN b0[246]
    DIRECTION INPUT ;
    USE SIGNAL ;
    PORT
      LAYER M5 ;
        RECT  33.264 0 33.288 0.084 ;
    END
  END b0[246]
  PIN b0[247]
    DIRECTION INPUT ;
    USE SIGNAL ;
    PORT
      LAYER M5 ;
        RECT  33.408 0 33.432 0.084 ;
    END
  END b0[247]
  PIN b0[248]
    DIRECTION INPUT ;
    USE SIGNAL ;
    PORT
      LAYER M5 ;
        RECT  33.552 0 33.576 0.084 ;
    END
  END b0[248]
  PIN b0[249]
    DIRECTION INPUT ;
    USE SIGNAL ;
    PORT
      LAYER M5 ;
        RECT  33.696 0 33.72 0.084 ;
    END
  END b0[249]
  PIN b0[24]
    DIRECTION INPUT ;
    USE SIGNAL ;
    PORT
      LAYER M5 ;
        RECT  133.776 0 133.8 0.084 ;
    END
  END b0[24]
  PIN b0[250]
    DIRECTION INPUT ;
    USE SIGNAL ;
    PORT
      LAYER M5 ;
        RECT  33.84 0 33.864 0.084 ;
    END
  END b0[250]
  PIN b0[251]
    DIRECTION INPUT ;
    USE SIGNAL ;
    PORT
      LAYER M5 ;
        RECT  33.984 0 34.008 0.084 ;
    END
  END b0[251]
  PIN b0[252]
    DIRECTION INPUT ;
    USE SIGNAL ;
    PORT
      LAYER M5 ;
        RECT  167.76 0 167.784 0.084 ;
    END
  END b0[252]
  PIN b0[253]
    DIRECTION INPUT ;
    USE SIGNAL ;
    PORT
      LAYER M5 ;
        RECT  167.904 0 167.928 0.084 ;
    END
  END b0[253]
  PIN b0[254]
    DIRECTION INPUT ;
    USE SIGNAL ;
    PORT
      LAYER M5 ;
        RECT  168.048 0 168.072 0.084 ;
    END
  END b0[254]
  PIN b0[255]
    DIRECTION INPUT ;
    USE SIGNAL ;
    PORT
      LAYER M5 ;
        RECT  168.192 0 168.216 0.084 ;
    END
  END b0[255]
  PIN b0[256]
    DIRECTION INPUT ;
    USE SIGNAL ;
    PORT
      LAYER M5 ;
        RECT  168.336 0 168.36 0.084 ;
    END
  END b0[256]
  PIN b0[257]
    DIRECTION INPUT ;
    USE SIGNAL ;
    PORT
      LAYER M5 ;
        RECT  168.48 0 168.504 0.084 ;
    END
  END b0[257]
  PIN b0[25]
    DIRECTION INPUT ;
    USE SIGNAL ;
    PORT
      LAYER M5 ;
        RECT  133.92 0 133.944 0.084 ;
    END
  END b0[25]
  PIN b0[26]
    DIRECTION INPUT ;
    USE SIGNAL ;
    PORT
      LAYER M5 ;
        RECT  134.064 0 134.088 0.084 ;
    END
  END b0[26]
  PIN b0[27]
    DIRECTION INPUT ;
    USE SIGNAL ;
    PORT
      LAYER M5 ;
        RECT  134.208 0 134.232 0.084 ;
    END
  END b0[27]
  PIN b0[28]
    DIRECTION INPUT ;
    USE SIGNAL ;
    PORT
      LAYER M5 ;
        RECT  34.128 0 34.152 0.084 ;
    END
  END b0[28]
  PIN b0[29]
    DIRECTION INPUT ;
    USE SIGNAL ;
    PORT
      LAYER M5 ;
        RECT  34.272 0 34.296 0.084 ;
    END
  END b0[29]
  PIN b0[2]
    DIRECTION INPUT ;
    USE SIGNAL ;
    PORT
      LAYER M5 ;
        RECT  130.608 0 130.632 0.084 ;
    END
  END b0[2]
  PIN b0[30]
    DIRECTION INPUT ;
    USE SIGNAL ;
    PORT
      LAYER M5 ;
        RECT  34.416 0 34.44 0.084 ;
    END
  END b0[30]
  PIN b0[31]
    DIRECTION INPUT ;
    USE SIGNAL ;
    PORT
      LAYER M5 ;
        RECT  34.56 0 34.584 0.084 ;
    END
  END b0[31]
  PIN b0[32]
    DIRECTION INPUT ;
    USE SIGNAL ;
    PORT
      LAYER M5 ;
        RECT  34.704 0 34.728 0.084 ;
    END
  END b0[32]
  PIN b0[33]
    DIRECTION INPUT ;
    USE SIGNAL ;
    PORT
      LAYER M5 ;
        RECT  34.848 0 34.872 0.084 ;
    END
  END b0[33]
  PIN b0[34]
    DIRECTION INPUT ;
    USE SIGNAL ;
    PORT
      LAYER M5 ;
        RECT  34.992 0 35.016 0.084 ;
    END
  END b0[34]
  PIN b0[35]
    DIRECTION INPUT ;
    USE SIGNAL ;
    PORT
      LAYER M5 ;
        RECT  35.136 0 35.16 0.084 ;
    END
  END b0[35]
  PIN b0[36]
    DIRECTION INPUT ;
    USE SIGNAL ;
    PORT
      LAYER M5 ;
        RECT  35.28 0 35.304 0.084 ;
    END
  END b0[36]
  PIN b0[37]
    DIRECTION INPUT ;
    USE SIGNAL ;
    PORT
      LAYER M5 ;
        RECT  35.424 0 35.448 0.084 ;
    END
  END b0[37]
  PIN b0[38]
    DIRECTION INPUT ;
    USE SIGNAL ;
    PORT
      LAYER M5 ;
        RECT  35.568 0 35.592 0.084 ;
    END
  END b0[38]
  PIN b0[39]
    DIRECTION INPUT ;
    USE SIGNAL ;
    PORT
      LAYER M5 ;
        RECT  35.712 0 35.736 0.084 ;
    END
  END b0[39]
  PIN b0[3]
    DIRECTION INPUT ;
    USE SIGNAL ;
    PORT
      LAYER M5 ;
        RECT  130.752 0 130.776 0.084 ;
    END
  END b0[3]
  PIN b0[40]
    DIRECTION INPUT ;
    USE SIGNAL ;
    PORT
      LAYER M5 ;
        RECT  35.856 0 35.88 0.084 ;
    END
  END b0[40]
  PIN b0[41]
    DIRECTION INPUT ;
    USE SIGNAL ;
    PORT
      LAYER M5 ;
        RECT  36 0 36.024 0.084 ;
    END
  END b0[41]
  PIN b0[42]
    DIRECTION INPUT ;
    USE SIGNAL ;
    PORT
      LAYER M5 ;
        RECT  36.144 0 36.168 0.084 ;
    END
  END b0[42]
  PIN b0[43]
    DIRECTION INPUT ;
    USE SIGNAL ;
    PORT
      LAYER M5 ;
        RECT  36.288 0 36.312 0.084 ;
    END
  END b0[43]
  PIN b0[44]
    DIRECTION INPUT ;
    USE SIGNAL ;
    PORT
      LAYER M5 ;
        RECT  36.432 0 36.456 0.084 ;
    END
  END b0[44]
  PIN b0[45]
    DIRECTION INPUT ;
    USE SIGNAL ;
    PORT
      LAYER M5 ;
        RECT  36.576 0 36.6 0.084 ;
    END
  END b0[45]
  PIN b0[46]
    DIRECTION INPUT ;
    USE SIGNAL ;
    PORT
      LAYER M5 ;
        RECT  36.72 0 36.744 0.084 ;
    END
  END b0[46]
  PIN b0[47]
    DIRECTION INPUT ;
    USE SIGNAL ;
    PORT
      LAYER M5 ;
        RECT  36.864 0 36.888 0.084 ;
    END
  END b0[47]
  PIN b0[48]
    DIRECTION INPUT ;
    USE SIGNAL ;
    PORT
      LAYER M5 ;
        RECT  37.008 0 37.032 0.084 ;
    END
  END b0[48]
  PIN b0[49]
    DIRECTION INPUT ;
    USE SIGNAL ;
    PORT
      LAYER M5 ;
        RECT  37.152 0 37.176 0.084 ;
    END
  END b0[49]
  PIN b0[4]
    DIRECTION INPUT ;
    USE SIGNAL ;
    PORT
      LAYER M5 ;
        RECT  130.896 0 130.92 0.084 ;
    END
  END b0[4]
  PIN b0[50]
    DIRECTION INPUT ;
    USE SIGNAL ;
    PORT
      LAYER M5 ;
        RECT  37.296 0 37.32 0.084 ;
    END
  END b0[50]
  PIN b0[51]
    DIRECTION INPUT ;
    USE SIGNAL ;
    PORT
      LAYER M5 ;
        RECT  37.44 0 37.464 0.084 ;
    END
  END b0[51]
  PIN b0[52]
    DIRECTION INPUT ;
    USE SIGNAL ;
    PORT
      LAYER M5 ;
        RECT  37.584 0 37.608 0.084 ;
    END
  END b0[52]
  PIN b0[53]
    DIRECTION INPUT ;
    USE SIGNAL ;
    PORT
      LAYER M5 ;
        RECT  37.728 0 37.752 0.084 ;
    END
  END b0[53]
  PIN b0[54]
    DIRECTION INPUT ;
    USE SIGNAL ;
    PORT
      LAYER M5 ;
        RECT  37.872 0 37.896 0.084 ;
    END
  END b0[54]
  PIN b0[55]
    DIRECTION INPUT ;
    USE SIGNAL ;
    PORT
      LAYER M5 ;
        RECT  38.016 0 38.04 0.084 ;
    END
  END b0[55]
  PIN b0[56]
    DIRECTION INPUT ;
    USE SIGNAL ;
    PORT
      LAYER M5 ;
        RECT  38.16 0 38.184 0.084 ;
    END
  END b0[56]
  PIN b0[57]
    DIRECTION INPUT ;
    USE SIGNAL ;
    PORT
      LAYER M5 ;
        RECT  38.304 0 38.328 0.084 ;
    END
  END b0[57]
  PIN b0[58]
    DIRECTION INPUT ;
    USE SIGNAL ;
    PORT
      LAYER M5 ;
        RECT  38.448 0 38.472 0.084 ;
    END
  END b0[58]
  PIN b0[59]
    DIRECTION INPUT ;
    USE SIGNAL ;
    PORT
      LAYER M5 ;
        RECT  38.592 0 38.616 0.084 ;
    END
  END b0[59]
  PIN b0[5]
    DIRECTION INPUT ;
    USE SIGNAL ;
    PORT
      LAYER M5 ;
        RECT  131.04 0 131.064 0.084 ;
    END
  END b0[5]
  PIN b0[60]
    DIRECTION INPUT ;
    USE SIGNAL ;
    PORT
      LAYER M5 ;
        RECT  38.736 0 38.76 0.084 ;
    END
  END b0[60]
  PIN b0[61]
    DIRECTION INPUT ;
    USE SIGNAL ;
    PORT
      LAYER M5 ;
        RECT  38.88 0 38.904 0.084 ;
    END
  END b0[61]
  PIN b0[62]
    DIRECTION INPUT ;
    USE SIGNAL ;
    PORT
      LAYER M5 ;
        RECT  39.024 0 39.048 0.084 ;
    END
  END b0[62]
  PIN b0[63]
    DIRECTION INPUT ;
    USE SIGNAL ;
    PORT
      LAYER M5 ;
        RECT  39.168 0 39.192 0.084 ;
    END
  END b0[63]
  PIN b0[64]
    DIRECTION INPUT ;
    USE SIGNAL ;
    PORT
      LAYER M5 ;
        RECT  39.312 0 39.336 0.084 ;
    END
  END b0[64]
  PIN b0[65]
    DIRECTION INPUT ;
    USE SIGNAL ;
    PORT
      LAYER M5 ;
        RECT  39.456 0 39.48 0.084 ;
    END
  END b0[65]
  PIN b0[66]
    DIRECTION INPUT ;
    USE SIGNAL ;
    PORT
      LAYER M5 ;
        RECT  39.6 0 39.624 0.084 ;
    END
  END b0[66]
  PIN b0[67]
    DIRECTION INPUT ;
    USE SIGNAL ;
    PORT
      LAYER M5 ;
        RECT  39.744 0 39.768 0.084 ;
    END
  END b0[67]
  PIN b0[68]
    DIRECTION INPUT ;
    USE SIGNAL ;
    PORT
      LAYER M5 ;
        RECT  39.888 0 39.912 0.084 ;
    END
  END b0[68]
  PIN b0[69]
    DIRECTION INPUT ;
    USE SIGNAL ;
    PORT
      LAYER M5 ;
        RECT  40.032 0 40.056 0.084 ;
    END
  END b0[69]
  PIN b0[6]
    DIRECTION INPUT ;
    USE SIGNAL ;
    PORT
      LAYER M5 ;
        RECT  131.184 0 131.208 0.084 ;
    END
  END b0[6]
  PIN b0[70]
    DIRECTION INPUT ;
    USE SIGNAL ;
    PORT
      LAYER M5 ;
        RECT  40.176 0 40.2 0.084 ;
    END
  END b0[70]
  PIN b0[71]
    DIRECTION INPUT ;
    USE SIGNAL ;
    PORT
      LAYER M5 ;
        RECT  40.32 0 40.344 0.084 ;
    END
  END b0[71]
  PIN b0[72]
    DIRECTION INPUT ;
    USE SIGNAL ;
    PORT
      LAYER M5 ;
        RECT  40.464 0 40.488 0.084 ;
    END
  END b0[72]
  PIN b0[73]
    DIRECTION INPUT ;
    USE SIGNAL ;
    PORT
      LAYER M5 ;
        RECT  40.608 0 40.632 0.084 ;
    END
  END b0[73]
  PIN b0[74]
    DIRECTION INPUT ;
    USE SIGNAL ;
    PORT
      LAYER M5 ;
        RECT  40.752 0 40.776 0.084 ;
    END
  END b0[74]
  PIN b0[75]
    DIRECTION INPUT ;
    USE SIGNAL ;
    PORT
      LAYER M5 ;
        RECT  40.896 0 40.92 0.084 ;
    END
  END b0[75]
  PIN b0[76]
    DIRECTION INPUT ;
    USE SIGNAL ;
    PORT
      LAYER M5 ;
        RECT  41.04 0 41.064 0.084 ;
    END
  END b0[76]
  PIN b0[77]
    DIRECTION INPUT ;
    USE SIGNAL ;
    PORT
      LAYER M5 ;
        RECT  41.184 0 41.208 0.084 ;
    END
  END b0[77]
  PIN b0[78]
    DIRECTION INPUT ;
    USE SIGNAL ;
    PORT
      LAYER M5 ;
        RECT  41.328 0 41.352 0.084 ;
    END
  END b0[78]
  PIN b0[79]
    DIRECTION INPUT ;
    USE SIGNAL ;
    PORT
      LAYER M5 ;
        RECT  41.472 0 41.496 0.084 ;
    END
  END b0[79]
  PIN b0[7]
    DIRECTION INPUT ;
    USE SIGNAL ;
    PORT
      LAYER M5 ;
        RECT  131.328 0 131.352 0.084 ;
    END
  END b0[7]
  PIN b0[80]
    DIRECTION INPUT ;
    USE SIGNAL ;
    PORT
      LAYER M5 ;
        RECT  41.616 0 41.64 0.084 ;
    END
  END b0[80]
  PIN b0[81]
    DIRECTION INPUT ;
    USE SIGNAL ;
    PORT
      LAYER M5 ;
        RECT  41.76 0 41.784 0.084 ;
    END
  END b0[81]
  PIN b0[82]
    DIRECTION INPUT ;
    USE SIGNAL ;
    PORT
      LAYER M5 ;
        RECT  41.904 0 41.928 0.084 ;
    END
  END b0[82]
  PIN b0[83]
    DIRECTION INPUT ;
    USE SIGNAL ;
    PORT
      LAYER M5 ;
        RECT  42.048 0 42.072 0.084 ;
    END
  END b0[83]
  PIN b0[84]
    DIRECTION INPUT ;
    USE SIGNAL ;
    PORT
      LAYER M5 ;
        RECT  42.192 0 42.216 0.084 ;
    END
  END b0[84]
  PIN b0[85]
    DIRECTION INPUT ;
    USE SIGNAL ;
    PORT
      LAYER M5 ;
        RECT  42.336 0 42.36 0.084 ;
    END
  END b0[85]
  PIN b0[86]
    DIRECTION INPUT ;
    USE SIGNAL ;
    PORT
      LAYER M5 ;
        RECT  42.48 0 42.504 0.084 ;
    END
  END b0[86]
  PIN b0[87]
    DIRECTION INPUT ;
    USE SIGNAL ;
    PORT
      LAYER M5 ;
        RECT  42.624 0 42.648 0.084 ;
    END
  END b0[87]
  PIN b0[88]
    DIRECTION INPUT ;
    USE SIGNAL ;
    PORT
      LAYER M5 ;
        RECT  42.768 0 42.792 0.084 ;
    END
  END b0[88]
  PIN b0[89]
    DIRECTION INPUT ;
    USE SIGNAL ;
    PORT
      LAYER M5 ;
        RECT  42.912 0 42.936 0.084 ;
    END
  END b0[89]
  PIN b0[8]
    DIRECTION INPUT ;
    USE SIGNAL ;
    PORT
      LAYER M5 ;
        RECT  131.472 0 131.496 0.084 ;
    END
  END b0[8]
  PIN b0[90]
    DIRECTION INPUT ;
    USE SIGNAL ;
    PORT
      LAYER M5 ;
        RECT  43.056 0 43.08 0.084 ;
    END
  END b0[90]
  PIN b0[91]
    DIRECTION INPUT ;
    USE SIGNAL ;
    PORT
      LAYER M5 ;
        RECT  43.2 0 43.224 0.084 ;
    END
  END b0[91]
  PIN b0[92]
    DIRECTION INPUT ;
    USE SIGNAL ;
    PORT
      LAYER M5 ;
        RECT  115.92 0 115.944 0.084 ;
    END
  END b0[92]
  PIN b0[93]
    DIRECTION INPUT ;
    USE SIGNAL ;
    PORT
      LAYER M5 ;
        RECT  116.064 0 116.088 0.084 ;
    END
  END b0[93]
  PIN b0[94]
    DIRECTION INPUT ;
    USE SIGNAL ;
    PORT
      LAYER M5 ;
        RECT  116.208 0 116.232 0.084 ;
    END
  END b0[94]
  PIN b0[95]
    DIRECTION INPUT ;
    USE SIGNAL ;
    PORT
      LAYER M5 ;
        RECT  116.352 0 116.376 0.084 ;
    END
  END b0[95]
  PIN b0[96]
    DIRECTION INPUT ;
    USE SIGNAL ;
    PORT
      LAYER M5 ;
        RECT  116.496 0 116.52 0.084 ;
    END
  END b0[96]
  PIN b0[97]
    DIRECTION INPUT ;
    USE SIGNAL ;
    PORT
      LAYER M5 ;
        RECT  116.64 0 116.664 0.084 ;
    END
  END b0[97]
  PIN b0[98]
    DIRECTION INPUT ;
    USE SIGNAL ;
    PORT
      LAYER M5 ;
        RECT  116.784 0 116.808 0.084 ;
    END
  END b0[98]
  PIN b0[99]
    DIRECTION INPUT ;
    USE SIGNAL ;
    PORT
      LAYER M5 ;
        RECT  116.928 0 116.952 0.084 ;
    END
  END b0[99]
  PIN b0[9]
    DIRECTION INPUT ;
    USE SIGNAL ;
    PORT
      LAYER M5 ;
        RECT  131.616 0 131.64 0.084 ;
    END
  END b0[9]
  PIN b1[0]
    DIRECTION INPUT ;
    USE SIGNAL ;
    PORT
      LAYER M5 ;
        RECT  168.624 0 168.648 0.084 ;
    END
  END b1[0]
  PIN b1[100]
    DIRECTION INPUT ;
    USE SIGNAL ;
    PORT
      LAYER M5 ;
        RECT  146.16 0 146.184 0.084 ;
    END
  END b1[100]
  PIN b1[101]
    DIRECTION INPUT ;
    USE SIGNAL ;
    PORT
      LAYER M5 ;
        RECT  146.304 0 146.328 0.084 ;
    END
  END b1[101]
  PIN b1[102]
    DIRECTION INPUT ;
    USE SIGNAL ;
    PORT
      LAYER M5 ;
        RECT  146.448 0 146.472 0.084 ;
    END
  END b1[102]
  PIN b1[103]
    DIRECTION INPUT ;
    USE SIGNAL ;
    PORT
      LAYER M5 ;
        RECT  146.592 0 146.616 0.084 ;
    END
  END b1[103]
  PIN b1[104]
    DIRECTION INPUT ;
    USE SIGNAL ;
    PORT
      LAYER M5 ;
        RECT  146.736 0 146.76 0.084 ;
    END
  END b1[104]
  PIN b1[105]
    DIRECTION INPUT ;
    USE SIGNAL ;
    PORT
      LAYER M5 ;
        RECT  146.88 0 146.904 0.084 ;
    END
  END b1[105]
  PIN b1[106]
    DIRECTION INPUT ;
    USE SIGNAL ;
    PORT
      LAYER M5 ;
        RECT  147.024 0 147.048 0.084 ;
    END
  END b1[106]
  PIN b1[107]
    DIRECTION INPUT ;
    USE SIGNAL ;
    PORT
      LAYER M5 ;
        RECT  147.168 0 147.192 0.084 ;
    END
  END b1[107]
  PIN b1[108]
    DIRECTION INPUT ;
    USE SIGNAL ;
    PORT
      LAYER M5 ;
        RECT  147.312 0 147.336 0.084 ;
    END
  END b1[108]
  PIN b1[109]
    DIRECTION INPUT ;
    USE SIGNAL ;
    PORT
      LAYER M5 ;
        RECT  147.456 0 147.48 0.084 ;
    END
  END b1[109]
  PIN b1[10]
    DIRECTION INPUT ;
    USE SIGNAL ;
    PORT
      LAYER M5 ;
        RECT  170.064 0 170.088 0.084 ;
    END
  END b1[10]
  PIN b1[110]
    DIRECTION INPUT ;
    USE SIGNAL ;
    PORT
      LAYER M5 ;
        RECT  147.6 0 147.624 0.084 ;
    END
  END b1[110]
  PIN b1[111]
    DIRECTION INPUT ;
    USE SIGNAL ;
    PORT
      LAYER M5 ;
        RECT  147.744 0 147.768 0.084 ;
    END
  END b1[111]
  PIN b1[112]
    DIRECTION INPUT ;
    USE SIGNAL ;
    PORT
      LAYER M5 ;
        RECT  147.888 0 147.912 0.084 ;
    END
  END b1[112]
  PIN b1[113]
    DIRECTION INPUT ;
    USE SIGNAL ;
    PORT
      LAYER M5 ;
        RECT  148.032 0 148.056 0.084 ;
    END
  END b1[113]
  PIN b1[114]
    DIRECTION INPUT ;
    USE SIGNAL ;
    PORT
      LAYER M5 ;
        RECT  148.176 0 148.2 0.084 ;
    END
  END b1[114]
  PIN b1[115]
    DIRECTION INPUT ;
    USE SIGNAL ;
    PORT
      LAYER M5 ;
        RECT  148.32 0 148.344 0.084 ;
    END
  END b1[115]
  PIN b1[116]
    DIRECTION INPUT ;
    USE SIGNAL ;
    PORT
      LAYER M5 ;
        RECT  148.464 0 148.488 0.084 ;
    END
  END b1[116]
  PIN b1[117]
    DIRECTION INPUT ;
    USE SIGNAL ;
    PORT
      LAYER M5 ;
        RECT  148.608 0 148.632 0.084 ;
    END
  END b1[117]
  PIN b1[118]
    DIRECTION INPUT ;
    USE SIGNAL ;
    PORT
      LAYER M5 ;
        RECT  148.752 0 148.776 0.084 ;
    END
  END b1[118]
  PIN b1[119]
    DIRECTION INPUT ;
    USE SIGNAL ;
    PORT
      LAYER M5 ;
        RECT  148.896 0 148.92 0.084 ;
    END
  END b1[119]
  PIN b1[11]
    DIRECTION INPUT ;
    USE SIGNAL ;
    PORT
      LAYER M5 ;
        RECT  170.208 0 170.232 0.084 ;
    END
  END b1[11]
  PIN b1[120]
    DIRECTION INPUT ;
    USE SIGNAL ;
    PORT
      LAYER M5 ;
        RECT  149.04 0 149.064 0.084 ;
    END
  END b1[120]
  PIN b1[121]
    DIRECTION INPUT ;
    USE SIGNAL ;
    PORT
      LAYER M5 ;
        RECT  149.184 0 149.208 0.084 ;
    END
  END b1[121]
  PIN b1[122]
    DIRECTION INPUT ;
    USE SIGNAL ;
    PORT
      LAYER M5 ;
        RECT  153.936 0 153.96 0.084 ;
    END
  END b1[122]
  PIN b1[123]
    DIRECTION INPUT ;
    USE SIGNAL ;
    PORT
      LAYER M5 ;
        RECT  154.08 0 154.104 0.084 ;
    END
  END b1[123]
  PIN b1[124]
    DIRECTION INPUT ;
    USE SIGNAL ;
    PORT
      LAYER M5 ;
        RECT  154.224 0 154.248 0.084 ;
    END
  END b1[124]
  PIN b1[125]
    DIRECTION INPUT ;
    USE SIGNAL ;
    PORT
      LAYER M5 ;
        RECT  154.368 0 154.392 0.084 ;
    END
  END b1[125]
  PIN b1[126]
    DIRECTION INPUT ;
    USE SIGNAL ;
    PORT
      LAYER M5 ;
        RECT  154.512 0 154.536 0.084 ;
    END
  END b1[126]
  PIN b1[127]
    DIRECTION INPUT ;
    USE SIGNAL ;
    PORT
      LAYER M5 ;
        RECT  154.656 0 154.68 0.084 ;
    END
  END b1[127]
  PIN b1[128]
    DIRECTION INPUT ;
    USE SIGNAL ;
    PORT
      LAYER M5 ;
        RECT  154.8 0 154.824 0.084 ;
    END
  END b1[128]
  PIN b1[129]
    DIRECTION INPUT ;
    USE SIGNAL ;
    PORT
      LAYER M5 ;
        RECT  154.944 0 154.968 0.084 ;
    END
  END b1[129]
  PIN b1[12]
    DIRECTION INPUT ;
    USE SIGNAL ;
    PORT
      LAYER M5 ;
        RECT  170.352 0 170.376 0.084 ;
    END
  END b1[12]
  PIN b1[130]
    DIRECTION INPUT ;
    USE SIGNAL ;
    PORT
      LAYER M5 ;
        RECT  155.088 0 155.112 0.084 ;
    END
  END b1[130]
  PIN b1[131]
    DIRECTION INPUT ;
    USE SIGNAL ;
    PORT
      LAYER M5 ;
        RECT  155.232 0 155.256 0.084 ;
    END
  END b1[131]
  PIN b1[132]
    DIRECTION INPUT ;
    USE SIGNAL ;
    PORT
      LAYER M5 ;
        RECT  155.376 0 155.4 0.084 ;
    END
  END b1[132]
  PIN b1[133]
    DIRECTION INPUT ;
    USE SIGNAL ;
    PORT
      LAYER M5 ;
        RECT  155.52 0 155.544 0.084 ;
    END
  END b1[133]
  PIN b1[134]
    DIRECTION INPUT ;
    USE SIGNAL ;
    PORT
      LAYER M5 ;
        RECT  155.664 0 155.688 0.084 ;
    END
  END b1[134]
  PIN b1[135]
    DIRECTION INPUT ;
    USE SIGNAL ;
    PORT
      LAYER M5 ;
        RECT  155.808 0 155.832 0.084 ;
    END
  END b1[135]
  PIN b1[136]
    DIRECTION INPUT ;
    USE SIGNAL ;
    PORT
      LAYER M5 ;
        RECT  155.952 0 155.976 0.084 ;
    END
  END b1[136]
  PIN b1[137]
    DIRECTION INPUT ;
    USE SIGNAL ;
    PORT
      LAYER M5 ;
        RECT  156.096 0 156.12 0.084 ;
    END
  END b1[137]
  PIN b1[138]
    DIRECTION INPUT ;
    USE SIGNAL ;
    PORT
      LAYER M5 ;
        RECT  156.24 0 156.264 0.084 ;
    END
  END b1[138]
  PIN b1[139]
    DIRECTION INPUT ;
    USE SIGNAL ;
    PORT
      LAYER M5 ;
        RECT  156.384 0 156.408 0.084 ;
    END
  END b1[139]
  PIN b1[13]
    DIRECTION INPUT ;
    USE SIGNAL ;
    PORT
      LAYER M5 ;
        RECT  170.496 0 170.52 0.084 ;
    END
  END b1[13]
  PIN b1[140]
    DIRECTION INPUT ;
    USE SIGNAL ;
    PORT
      LAYER M5 ;
        RECT  156.528 0 156.552 0.084 ;
    END
  END b1[140]
  PIN b1[141]
    DIRECTION INPUT ;
    USE SIGNAL ;
    PORT
      LAYER M5 ;
        RECT  156.672 0 156.696 0.084 ;
    END
  END b1[141]
  PIN b1[142]
    DIRECTION INPUT ;
    USE SIGNAL ;
    PORT
      LAYER M5 ;
        RECT  156.816 0 156.84 0.084 ;
    END
  END b1[142]
  PIN b1[143]
    DIRECTION INPUT ;
    USE SIGNAL ;
    PORT
      LAYER M5 ;
        RECT  156.96 0 156.984 0.084 ;
    END
  END b1[143]
  PIN b1[144]
    DIRECTION INPUT ;
    USE SIGNAL ;
    PORT
      LAYER M5 ;
        RECT  157.104 0 157.128 0.084 ;
    END
  END b1[144]
  PIN b1[145]
    DIRECTION INPUT ;
    USE SIGNAL ;
    PORT
      LAYER M5 ;
        RECT  157.248 0 157.272 0.084 ;
    END
  END b1[145]
  PIN b1[146]
    DIRECTION INPUT ;
    USE SIGNAL ;
    PORT
      LAYER M5 ;
        RECT  157.392 0 157.416 0.084 ;
    END
  END b1[146]
  PIN b1[147]
    DIRECTION INPUT ;
    USE SIGNAL ;
    PORT
      LAYER M5 ;
        RECT  157.536 0 157.56 0.084 ;
    END
  END b1[147]
  PIN b1[148]
    DIRECTION INPUT ;
    USE SIGNAL ;
    PORT
      LAYER M5 ;
        RECT  157.68 0 157.704 0.084 ;
    END
  END b1[148]
  PIN b1[149]
    DIRECTION INPUT ;
    USE SIGNAL ;
    PORT
      LAYER M5 ;
        RECT  157.824 0 157.848 0.084 ;
    END
  END b1[149]
  PIN b1[14]
    DIRECTION INPUT ;
    USE SIGNAL ;
    PORT
      LAYER M5 ;
        RECT  170.64 0 170.664 0.084 ;
    END
  END b1[14]
  PIN b1[150]
    DIRECTION INPUT ;
    USE SIGNAL ;
    PORT
      LAYER M5 ;
        RECT  157.968 0 157.992 0.084 ;
    END
  END b1[150]
  PIN b1[151]
    DIRECTION INPUT ;
    USE SIGNAL ;
    PORT
      LAYER M5 ;
        RECT  158.112 0 158.136 0.084 ;
    END
  END b1[151]
  PIN b1[152]
    DIRECTION INPUT ;
    USE SIGNAL ;
    PORT
      LAYER M5 ;
        RECT  158.256 0 158.28 0.084 ;
    END
  END b1[152]
  PIN b1[153]
    DIRECTION INPUT ;
    USE SIGNAL ;
    PORT
      LAYER M5 ;
        RECT  158.4 0 158.424 0.084 ;
    END
  END b1[153]
  PIN b1[154]
    DIRECTION INPUT ;
    USE SIGNAL ;
    PORT
      LAYER M5 ;
        RECT  158.544 0 158.568 0.084 ;
    END
  END b1[154]
  PIN b1[155]
    DIRECTION INPUT ;
    USE SIGNAL ;
    PORT
      LAYER M5 ;
        RECT  158.688 0 158.712 0.084 ;
    END
  END b1[155]
  PIN b1[156]
    DIRECTION INPUT ;
    USE SIGNAL ;
    PORT
      LAYER M5 ;
        RECT  158.832 0 158.856 0.084 ;
    END
  END b1[156]
  PIN b1[157]
    DIRECTION INPUT ;
    USE SIGNAL ;
    PORT
      LAYER M5 ;
        RECT  158.976 0 159 0.084 ;
    END
  END b1[157]
  PIN b1[158]
    DIRECTION INPUT ;
    USE SIGNAL ;
    PORT
      LAYER M5 ;
        RECT  159.12 0 159.144 0.084 ;
    END
  END b1[158]
  PIN b1[159]
    DIRECTION INPUT ;
    USE SIGNAL ;
    PORT
      LAYER M5 ;
        RECT  159.264 0 159.288 0.084 ;
    END
  END b1[159]
  PIN b1[15]
    DIRECTION INPUT ;
    USE SIGNAL ;
    PORT
      LAYER M5 ;
        RECT  170.784 0 170.808 0.084 ;
    END
  END b1[15]
  PIN b1[160]
    DIRECTION INPUT ;
    USE SIGNAL ;
    PORT
      LAYER M5 ;
        RECT  159.408 0 159.432 0.084 ;
    END
  END b1[160]
  PIN b1[161]
    DIRECTION INPUT ;
    USE SIGNAL ;
    PORT
      LAYER M5 ;
        RECT  159.552 0 159.576 0.084 ;
    END
  END b1[161]
  PIN b1[162]
    DIRECTION INPUT ;
    USE SIGNAL ;
    PORT
      LAYER M5 ;
        RECT  159.696 0 159.72 0.084 ;
    END
  END b1[162]
  PIN b1[163]
    DIRECTION INPUT ;
    USE SIGNAL ;
    PORT
      LAYER M5 ;
        RECT  159.84 0 159.864 0.084 ;
    END
  END b1[163]
  PIN b1[164]
    DIRECTION INPUT ;
    USE SIGNAL ;
    PORT
      LAYER M5 ;
        RECT  159.984 0 160.008 0.084 ;
    END
  END b1[164]
  PIN b1[165]
    DIRECTION INPUT ;
    USE SIGNAL ;
    PORT
      LAYER M5 ;
        RECT  160.128 0 160.152 0.084 ;
    END
  END b1[165]
  PIN b1[166]
    DIRECTION INPUT ;
    USE SIGNAL ;
    PORT
      LAYER M5 ;
        RECT  160.272 0 160.296 0.084 ;
    END
  END b1[166]
  PIN b1[167]
    DIRECTION INPUT ;
    USE SIGNAL ;
    PORT
      LAYER M5 ;
        RECT  160.416 0 160.44 0.084 ;
    END
  END b1[167]
  PIN b1[168]
    DIRECTION INPUT ;
    USE SIGNAL ;
    PORT
      LAYER M5 ;
        RECT  160.56 0 160.584 0.084 ;
    END
  END b1[168]
  PIN b1[169]
    DIRECTION INPUT ;
    USE SIGNAL ;
    PORT
      LAYER M5 ;
        RECT  160.704 0 160.728 0.084 ;
    END
  END b1[169]
  PIN b1[16]
    DIRECTION INPUT ;
    USE SIGNAL ;
    PORT
      LAYER M5 ;
        RECT  170.928 0 170.952 0.084 ;
    END
  END b1[16]
  PIN b1[170]
    DIRECTION INPUT ;
    USE SIGNAL ;
    PORT
      LAYER M5 ;
        RECT  160.848 0 160.872 0.084 ;
    END
  END b1[170]
  PIN b1[171]
    DIRECTION INPUT ;
    USE SIGNAL ;
    PORT
      LAYER M5 ;
        RECT  160.992 0 161.016 0.084 ;
    END
  END b1[171]
  PIN b1[172]
    DIRECTION INPUT ;
    USE SIGNAL ;
    PORT
      LAYER M5 ;
        RECT  161.136 0 161.16 0.084 ;
    END
  END b1[172]
  PIN b1[173]
    DIRECTION INPUT ;
    USE SIGNAL ;
    PORT
      LAYER M5 ;
        RECT  161.28 0 161.304 0.084 ;
    END
  END b1[173]
  PIN b1[174]
    DIRECTION INPUT ;
    USE SIGNAL ;
    PORT
      LAYER M5 ;
        RECT  161.424 0 161.448 0.084 ;
    END
  END b1[174]
  PIN b1[175]
    DIRECTION INPUT ;
    USE SIGNAL ;
    PORT
      LAYER M5 ;
        RECT  161.568 0 161.592 0.084 ;
    END
  END b1[175]
  PIN b1[176]
    DIRECTION INPUT ;
    USE SIGNAL ;
    PORT
      LAYER M5 ;
        RECT  161.712 0 161.736 0.084 ;
    END
  END b1[176]
  PIN b1[177]
    DIRECTION INPUT ;
    USE SIGNAL ;
    PORT
      LAYER M5 ;
        RECT  161.856 0 161.88 0.084 ;
    END
  END b1[177]
  PIN b1[178]
    DIRECTION INPUT ;
    USE SIGNAL ;
    PORT
      LAYER M5 ;
        RECT  162 0 162.024 0.084 ;
    END
  END b1[178]
  PIN b1[179]
    DIRECTION INPUT ;
    USE SIGNAL ;
    PORT
      LAYER M5 ;
        RECT  162.144 0 162.168 0.084 ;
    END
  END b1[179]
  PIN b1[17]
    DIRECTION INPUT ;
    USE SIGNAL ;
    PORT
      LAYER M5 ;
        RECT  171.072 0 171.096 0.084 ;
    END
  END b1[17]
  PIN b1[180]
    DIRECTION INPUT ;
    USE SIGNAL ;
    PORT
      LAYER M5 ;
        RECT  162.288 0 162.312 0.084 ;
    END
  END b1[180]
  PIN b1[181]
    DIRECTION INPUT ;
    USE SIGNAL ;
    PORT
      LAYER M5 ;
        RECT  162.432 0 162.456 0.084 ;
    END
  END b1[181]
  PIN b1[182]
    DIRECTION INPUT ;
    USE SIGNAL ;
    PORT
      LAYER M5 ;
        RECT  162.576 0 162.6 0.084 ;
    END
  END b1[182]
  PIN b1[183]
    DIRECTION INPUT ;
    USE SIGNAL ;
    PORT
      LAYER M5 ;
        RECT  162.72 0 162.744 0.084 ;
    END
  END b1[183]
  PIN b1[184]
    DIRECTION INPUT ;
    USE SIGNAL ;
    PORT
      LAYER M5 ;
        RECT  162.864 0 162.888 0.084 ;
    END
  END b1[184]
  PIN b1[185]
    DIRECTION INPUT ;
    USE SIGNAL ;
    PORT
      LAYER M5 ;
        RECT  163.008 0 163.032 0.084 ;
    END
  END b1[185]
  PIN b1[186]
    DIRECTION INPUT ;
    USE SIGNAL ;
    PORT
      LAYER M5 ;
        RECT  19.152 0 19.176 0.084 ;
    END
  END b1[186]
  PIN b1[187]
    DIRECTION INPUT ;
    USE SIGNAL ;
    PORT
      LAYER M5 ;
        RECT  19.296 0 19.32 0.084 ;
    END
  END b1[187]
  PIN b1[188]
    DIRECTION INPUT ;
    USE SIGNAL ;
    PORT
      LAYER M5 ;
        RECT  19.44 0 19.464 0.084 ;
    END
  END b1[188]
  PIN b1[189]
    DIRECTION INPUT ;
    USE SIGNAL ;
    PORT
      LAYER M5 ;
        RECT  19.584 0 19.608 0.084 ;
    END
  END b1[189]
  PIN b1[18]
    DIRECTION INPUT ;
    USE SIGNAL ;
    PORT
      LAYER M5 ;
        RECT  171.216 0 171.24 0.084 ;
    END
  END b1[18]
  PIN b1[190]
    DIRECTION INPUT ;
    USE SIGNAL ;
    PORT
      LAYER M5 ;
        RECT  19.728 0 19.752 0.084 ;
    END
  END b1[190]
  PIN b1[191]
    DIRECTION INPUT ;
    USE SIGNAL ;
    PORT
      LAYER M5 ;
        RECT  19.872 0 19.896 0.084 ;
    END
  END b1[191]
  PIN b1[192]
    DIRECTION INPUT ;
    USE SIGNAL ;
    PORT
      LAYER M5 ;
        RECT  20.016 0 20.04 0.084 ;
    END
  END b1[192]
  PIN b1[193]
    DIRECTION INPUT ;
    USE SIGNAL ;
    PORT
      LAYER M5 ;
        RECT  20.16 0 20.184 0.084 ;
    END
  END b1[193]
  PIN b1[194]
    DIRECTION INPUT ;
    USE SIGNAL ;
    PORT
      LAYER M5 ;
        RECT  20.304 0 20.328 0.084 ;
    END
  END b1[194]
  PIN b1[195]
    DIRECTION INPUT ;
    USE SIGNAL ;
    PORT
      LAYER M5 ;
        RECT  20.448 0 20.472 0.084 ;
    END
  END b1[195]
  PIN b1[196]
    DIRECTION INPUT ;
    USE SIGNAL ;
    PORT
      LAYER M5 ;
        RECT  20.592 0 20.616 0.084 ;
    END
  END b1[196]
  PIN b1[197]
    DIRECTION INPUT ;
    USE SIGNAL ;
    PORT
      LAYER M5 ;
        RECT  20.736 0 20.76 0.084 ;
    END
  END b1[197]
  PIN b1[198]
    DIRECTION INPUT ;
    USE SIGNAL ;
    PORT
      LAYER M5 ;
        RECT  20.88 0 20.904 0.084 ;
    END
  END b1[198]
  PIN b1[199]
    DIRECTION INPUT ;
    USE SIGNAL ;
    PORT
      LAYER M5 ;
        RECT  21.024 0 21.048 0.084 ;
    END
  END b1[199]
  PIN b1[19]
    DIRECTION INPUT ;
    USE SIGNAL ;
    PORT
      LAYER M5 ;
        RECT  171.36 0 171.384 0.084 ;
    END
  END b1[19]
  PIN b1[1]
    DIRECTION INPUT ;
    USE SIGNAL ;
    PORT
      LAYER M5 ;
        RECT  168.768 0 168.792 0.084 ;
    END
  END b1[1]
  PIN b1[200]
    DIRECTION INPUT ;
    USE SIGNAL ;
    PORT
      LAYER M5 ;
        RECT  21.168 0 21.192 0.084 ;
    END
  END b1[200]
  PIN b1[201]
    DIRECTION INPUT ;
    USE SIGNAL ;
    PORT
      LAYER M5 ;
        RECT  21.312 0 21.336 0.084 ;
    END
  END b1[201]
  PIN b1[202]
    DIRECTION INPUT ;
    USE SIGNAL ;
    PORT
      LAYER M5 ;
        RECT  21.456 0 21.48 0.084 ;
    END
  END b1[202]
  PIN b1[203]
    DIRECTION INPUT ;
    USE SIGNAL ;
    PORT
      LAYER M5 ;
        RECT  21.6 0 21.624 0.084 ;
    END
  END b1[203]
  PIN b1[204]
    DIRECTION INPUT ;
    USE SIGNAL ;
    PORT
      LAYER M5 ;
        RECT  21.744 0 21.768 0.084 ;
    END
  END b1[204]
  PIN b1[205]
    DIRECTION INPUT ;
    USE SIGNAL ;
    PORT
      LAYER M5 ;
        RECT  21.888 0 21.912 0.084 ;
    END
  END b1[205]
  PIN b1[206]
    DIRECTION INPUT ;
    USE SIGNAL ;
    PORT
      LAYER M5 ;
        RECT  22.032 0 22.056 0.084 ;
    END
  END b1[206]
  PIN b1[207]
    DIRECTION INPUT ;
    USE SIGNAL ;
    PORT
      LAYER M5 ;
        RECT  22.176 0 22.2 0.084 ;
    END
  END b1[207]
  PIN b1[208]
    DIRECTION INPUT ;
    USE SIGNAL ;
    PORT
      LAYER M5 ;
        RECT  22.32 0 22.344 0.084 ;
    END
  END b1[208]
  PIN b1[209]
    DIRECTION INPUT ;
    USE SIGNAL ;
    PORT
      LAYER M5 ;
        RECT  22.464 0 22.488 0.084 ;
    END
  END b1[209]
  PIN b1[20]
    DIRECTION INPUT ;
    USE SIGNAL ;
    PORT
      LAYER M5 ;
        RECT  171.504 0 171.528 0.084 ;
    END
  END b1[20]
  PIN b1[210]
    DIRECTION INPUT ;
    USE SIGNAL ;
    PORT
      LAYER M5 ;
        RECT  22.608 0 22.632 0.084 ;
    END
  END b1[210]
  PIN b1[211]
    DIRECTION INPUT ;
    USE SIGNAL ;
    PORT
      LAYER M5 ;
        RECT  22.752 0 22.776 0.084 ;
    END
  END b1[211]
  PIN b1[212]
    DIRECTION INPUT ;
    USE SIGNAL ;
    PORT
      LAYER M5 ;
        RECT  22.896 0 22.92 0.084 ;
    END
  END b1[212]
  PIN b1[213]
    DIRECTION INPUT ;
    USE SIGNAL ;
    PORT
      LAYER M5 ;
        RECT  23.04 0 23.064 0.084 ;
    END
  END b1[213]
  PIN b1[214]
    DIRECTION INPUT ;
    USE SIGNAL ;
    PORT
      LAYER M5 ;
        RECT  23.184 0 23.208 0.084 ;
    END
  END b1[214]
  PIN b1[215]
    DIRECTION INPUT ;
    USE SIGNAL ;
    PORT
      LAYER M5 ;
        RECT  23.328 0 23.352 0.084 ;
    END
  END b1[215]
  PIN b1[216]
    DIRECTION INPUT ;
    USE SIGNAL ;
    PORT
      LAYER M5 ;
        RECT  23.472 0 23.496 0.084 ;
    END
  END b1[216]
  PIN b1[217]
    DIRECTION INPUT ;
    USE SIGNAL ;
    PORT
      LAYER M5 ;
        RECT  23.616 0 23.64 0.084 ;
    END
  END b1[217]
  PIN b1[218]
    DIRECTION INPUT ;
    USE SIGNAL ;
    PORT
      LAYER M5 ;
        RECT  23.76 0 23.784 0.084 ;
    END
  END b1[218]
  PIN b1[219]
    DIRECTION INPUT ;
    USE SIGNAL ;
    PORT
      LAYER M5 ;
        RECT  23.904 0 23.928 0.084 ;
    END
  END b1[219]
  PIN b1[21]
    DIRECTION INPUT ;
    USE SIGNAL ;
    PORT
      LAYER M5 ;
        RECT  171.648 0 171.672 0.084 ;
    END
  END b1[21]
  PIN b1[220]
    DIRECTION INPUT ;
    USE SIGNAL ;
    PORT
      LAYER M5 ;
        RECT  24.048 0 24.072 0.084 ;
    END
  END b1[220]
  PIN b1[221]
    DIRECTION INPUT ;
    USE SIGNAL ;
    PORT
      LAYER M5 ;
        RECT  24.192 0 24.216 0.084 ;
    END
  END b1[221]
  PIN b1[222]
    DIRECTION INPUT ;
    USE SIGNAL ;
    PORT
      LAYER M5 ;
        RECT  24.336 0 24.36 0.084 ;
    END
  END b1[222]
  PIN b1[223]
    DIRECTION INPUT ;
    USE SIGNAL ;
    PORT
      LAYER M5 ;
        RECT  24.48 0 24.504 0.084 ;
    END
  END b1[223]
  PIN b1[224]
    DIRECTION INPUT ;
    USE SIGNAL ;
    PORT
      LAYER M5 ;
        RECT  24.624 0 24.648 0.084 ;
    END
  END b1[224]
  PIN b1[225]
    DIRECTION INPUT ;
    USE SIGNAL ;
    PORT
      LAYER M5 ;
        RECT  24.768 0 24.792 0.084 ;
    END
  END b1[225]
  PIN b1[226]
    DIRECTION INPUT ;
    USE SIGNAL ;
    PORT
      LAYER M5 ;
        RECT  24.912 0 24.936 0.084 ;
    END
  END b1[226]
  PIN b1[227]
    DIRECTION INPUT ;
    USE SIGNAL ;
    PORT
      LAYER M5 ;
        RECT  25.056 0 25.08 0.084 ;
    END
  END b1[227]
  PIN b1[228]
    DIRECTION INPUT ;
    USE SIGNAL ;
    PORT
      LAYER M5 ;
        RECT  25.2 0 25.224 0.084 ;
    END
  END b1[228]
  PIN b1[229]
    DIRECTION INPUT ;
    USE SIGNAL ;
    PORT
      LAYER M5 ;
        RECT  25.344 0 25.368 0.084 ;
    END
  END b1[229]
  PIN b1[22]
    DIRECTION INPUT ;
    USE SIGNAL ;
    PORT
      LAYER M5 ;
        RECT  171.792 0 171.816 0.084 ;
    END
  END b1[22]
  PIN b1[230]
    DIRECTION INPUT ;
    USE SIGNAL ;
    PORT
      LAYER M5 ;
        RECT  25.488 0 25.512 0.084 ;
    END
  END b1[230]
  PIN b1[231]
    DIRECTION INPUT ;
    USE SIGNAL ;
    PORT
      LAYER M5 ;
        RECT  25.632 0 25.656 0.084 ;
    END
  END b1[231]
  PIN b1[232]
    DIRECTION INPUT ;
    USE SIGNAL ;
    PORT
      LAYER M5 ;
        RECT  25.776 0 25.8 0.084 ;
    END
  END b1[232]
  PIN b1[233]
    DIRECTION INPUT ;
    USE SIGNAL ;
    PORT
      LAYER M5 ;
        RECT  25.92 0 25.944 0.084 ;
    END
  END b1[233]
  PIN b1[234]
    DIRECTION INPUT ;
    USE SIGNAL ;
    PORT
      LAYER M5 ;
        RECT  26.064 0 26.088 0.084 ;
    END
  END b1[234]
  PIN b1[235]
    DIRECTION INPUT ;
    USE SIGNAL ;
    PORT
      LAYER M5 ;
        RECT  26.208 0 26.232 0.084 ;
    END
  END b1[235]
  PIN b1[236]
    DIRECTION INPUT ;
    USE SIGNAL ;
    PORT
      LAYER M5 ;
        RECT  26.352 0 26.376 0.084 ;
    END
  END b1[236]
  PIN b1[237]
    DIRECTION INPUT ;
    USE SIGNAL ;
    PORT
      LAYER M5 ;
        RECT  26.496 0 26.52 0.084 ;
    END
  END b1[237]
  PIN b1[238]
    DIRECTION INPUT ;
    USE SIGNAL ;
    PORT
      LAYER M5 ;
        RECT  26.64 0 26.664 0.084 ;
    END
  END b1[238]
  PIN b1[239]
    DIRECTION INPUT ;
    USE SIGNAL ;
    PORT
      LAYER M5 ;
        RECT  26.784 0 26.808 0.084 ;
    END
  END b1[239]
  PIN b1[23]
    DIRECTION INPUT ;
    USE SIGNAL ;
    PORT
      LAYER M5 ;
        RECT  171.936 0 171.96 0.084 ;
    END
  END b1[23]
  PIN b1[240]
    DIRECTION INPUT ;
    USE SIGNAL ;
    PORT
      LAYER M5 ;
        RECT  26.928 0 26.952 0.084 ;
    END
  END b1[240]
  PIN b1[241]
    DIRECTION INPUT ;
    USE SIGNAL ;
    PORT
      LAYER M5 ;
        RECT  27.072 0 27.096 0.084 ;
    END
  END b1[241]
  PIN b1[242]
    DIRECTION INPUT ;
    USE SIGNAL ;
    PORT
      LAYER M5 ;
        RECT  27.216 0 27.24 0.084 ;
    END
  END b1[242]
  PIN b1[243]
    DIRECTION INPUT ;
    USE SIGNAL ;
    PORT
      LAYER M5 ;
        RECT  27.36 0 27.384 0.084 ;
    END
  END b1[243]
  PIN b1[244]
    DIRECTION INPUT ;
    USE SIGNAL ;
    PORT
      LAYER M5 ;
        RECT  27.504 0 27.528 0.084 ;
    END
  END b1[244]
  PIN b1[245]
    DIRECTION INPUT ;
    USE SIGNAL ;
    PORT
      LAYER M5 ;
        RECT  27.648 0 27.672 0.084 ;
    END
  END b1[245]
  PIN b1[246]
    DIRECTION INPUT ;
    USE SIGNAL ;
    PORT
      LAYER M5 ;
        RECT  27.792 0 27.816 0.084 ;
    END
  END b1[246]
  PIN b1[247]
    DIRECTION INPUT ;
    USE SIGNAL ;
    PORT
      LAYER M5 ;
        RECT  27.936 0 27.96 0.084 ;
    END
  END b1[247]
  PIN b1[248]
    DIRECTION INPUT ;
    USE SIGNAL ;
    PORT
      LAYER M5 ;
        RECT  28.08 0 28.104 0.084 ;
    END
  END b1[248]
  PIN b1[249]
    DIRECTION INPUT ;
    USE SIGNAL ;
    PORT
      LAYER M5 ;
        RECT  28.224 0 28.248 0.084 ;
    END
  END b1[249]
  PIN b1[24]
    DIRECTION INPUT ;
    USE SIGNAL ;
    PORT
      LAYER M5 ;
        RECT  172.08 0 172.104 0.084 ;
    END
  END b1[24]
  PIN b1[250]
    DIRECTION INPUT ;
    USE SIGNAL ;
    PORT
      LAYER M5 ;
        RECT  85.968 0 85.992 0.084 ;
    END
  END b1[250]
  PIN b1[251]
    DIRECTION INPUT ;
    USE SIGNAL ;
    PORT
      LAYER M5 ;
        RECT  86.112 0 86.136 0.084 ;
    END
  END b1[251]
  PIN b1[252]
    DIRECTION INPUT ;
    USE SIGNAL ;
    PORT
      LAYER M5 ;
        RECT  86.256 0 86.28 0.084 ;
    END
  END b1[252]
  PIN b1[253]
    DIRECTION INPUT ;
    USE SIGNAL ;
    PORT
      LAYER M5 ;
        RECT  86.4 0 86.424 0.084 ;
    END
  END b1[253]
  PIN b1[254]
    DIRECTION INPUT ;
    USE SIGNAL ;
    PORT
      LAYER M5 ;
        RECT  86.544 0 86.568 0.084 ;
    END
  END b1[254]
  PIN b1[255]
    DIRECTION INPUT ;
    USE SIGNAL ;
    PORT
      LAYER M5 ;
        RECT  86.688 0 86.712 0.084 ;
    END
  END b1[255]
  PIN b1[256]
    DIRECTION INPUT ;
    USE SIGNAL ;
    PORT
      LAYER M5 ;
        RECT  86.832 0 86.856 0.084 ;
    END
  END b1[256]
  PIN b1[257]
    DIRECTION INPUT ;
    USE SIGNAL ;
    PORT
      LAYER M5 ;
        RECT  86.976 0 87 0.084 ;
    END
  END b1[257]
  PIN b1[25]
    DIRECTION INPUT ;
    USE SIGNAL ;
    PORT
      LAYER M5 ;
        RECT  172.224 0 172.248 0.084 ;
    END
  END b1[25]
  PIN b1[26]
    DIRECTION INPUT ;
    USE SIGNAL ;
    PORT
      LAYER M5 ;
        RECT  163.152 0 163.176 0.084 ;
    END
  END b1[26]
  PIN b1[27]
    DIRECTION INPUT ;
    USE SIGNAL ;
    PORT
      LAYER M5 ;
        RECT  163.296 0 163.32 0.084 ;
    END
  END b1[27]
  PIN b1[28]
    DIRECTION INPUT ;
    USE SIGNAL ;
    PORT
      LAYER M5 ;
        RECT  163.44 0 163.464 0.084 ;
    END
  END b1[28]
  PIN b1[29]
    DIRECTION INPUT ;
    USE SIGNAL ;
    PORT
      LAYER M5 ;
        RECT  163.584 0 163.608 0.084 ;
    END
  END b1[29]
  PIN b1[2]
    DIRECTION INPUT ;
    USE SIGNAL ;
    PORT
      LAYER M5 ;
        RECT  168.912 0 168.936 0.084 ;
    END
  END b1[2]
  PIN b1[30]
    DIRECTION INPUT ;
    USE SIGNAL ;
    PORT
      LAYER M5 ;
        RECT  163.728 0 163.752 0.084 ;
    END
  END b1[30]
  PIN b1[31]
    DIRECTION INPUT ;
    USE SIGNAL ;
    PORT
      LAYER M5 ;
        RECT  163.872 0 163.896 0.084 ;
    END
  END b1[31]
  PIN b1[32]
    DIRECTION INPUT ;
    USE SIGNAL ;
    PORT
      LAYER M5 ;
        RECT  164.016 0 164.04 0.084 ;
    END
  END b1[32]
  PIN b1[33]
    DIRECTION INPUT ;
    USE SIGNAL ;
    PORT
      LAYER M5 ;
        RECT  164.16 0 164.184 0.084 ;
    END
  END b1[33]
  PIN b1[34]
    DIRECTION INPUT ;
    USE SIGNAL ;
    PORT
      LAYER M5 ;
        RECT  164.304 0 164.328 0.084 ;
    END
  END b1[34]
  PIN b1[35]
    DIRECTION INPUT ;
    USE SIGNAL ;
    PORT
      LAYER M5 ;
        RECT  164.448 0 164.472 0.084 ;
    END
  END b1[35]
  PIN b1[36]
    DIRECTION INPUT ;
    USE SIGNAL ;
    PORT
      LAYER M5 ;
        RECT  164.592 0 164.616 0.084 ;
    END
  END b1[36]
  PIN b1[37]
    DIRECTION INPUT ;
    USE SIGNAL ;
    PORT
      LAYER M5 ;
        RECT  164.736 0 164.76 0.084 ;
    END
  END b1[37]
  PIN b1[38]
    DIRECTION INPUT ;
    USE SIGNAL ;
    PORT
      LAYER M5 ;
        RECT  164.88 0 164.904 0.084 ;
    END
  END b1[38]
  PIN b1[39]
    DIRECTION INPUT ;
    USE SIGNAL ;
    PORT
      LAYER M5 ;
        RECT  165.024 0 165.048 0.084 ;
    END
  END b1[39]
  PIN b1[3]
    DIRECTION INPUT ;
    USE SIGNAL ;
    PORT
      LAYER M5 ;
        RECT  169.056 0 169.08 0.084 ;
    END
  END b1[3]
  PIN b1[40]
    DIRECTION INPUT ;
    USE SIGNAL ;
    PORT
      LAYER M5 ;
        RECT  165.168 0 165.192 0.084 ;
    END
  END b1[40]
  PIN b1[41]
    DIRECTION INPUT ;
    USE SIGNAL ;
    PORT
      LAYER M5 ;
        RECT  165.312 0 165.336 0.084 ;
    END
  END b1[41]
  PIN b1[42]
    DIRECTION INPUT ;
    USE SIGNAL ;
    PORT
      LAYER M5 ;
        RECT  165.456 0 165.48 0.084 ;
    END
  END b1[42]
  PIN b1[43]
    DIRECTION INPUT ;
    USE SIGNAL ;
    PORT
      LAYER M5 ;
        RECT  165.6 0 165.624 0.084 ;
    END
  END b1[43]
  PIN b1[44]
    DIRECTION INPUT ;
    USE SIGNAL ;
    PORT
      LAYER M5 ;
        RECT  165.744 0 165.768 0.084 ;
    END
  END b1[44]
  PIN b1[45]
    DIRECTION INPUT ;
    USE SIGNAL ;
    PORT
      LAYER M5 ;
        RECT  165.888 0 165.912 0.084 ;
    END
  END b1[45]
  PIN b1[46]
    DIRECTION INPUT ;
    USE SIGNAL ;
    PORT
      LAYER M5 ;
        RECT  166.032 0 166.056 0.084 ;
    END
  END b1[46]
  PIN b1[47]
    DIRECTION INPUT ;
    USE SIGNAL ;
    PORT
      LAYER M5 ;
        RECT  166.176 0 166.2 0.084 ;
    END
  END b1[47]
  PIN b1[48]
    DIRECTION INPUT ;
    USE SIGNAL ;
    PORT
      LAYER M5 ;
        RECT  166.32 0 166.344 0.084 ;
    END
  END b1[48]
  PIN b1[49]
    DIRECTION INPUT ;
    USE SIGNAL ;
    PORT
      LAYER M5 ;
        RECT  166.464 0 166.488 0.084 ;
    END
  END b1[49]
  PIN b1[4]
    DIRECTION INPUT ;
    USE SIGNAL ;
    PORT
      LAYER M5 ;
        RECT  169.2 0 169.224 0.084 ;
    END
  END b1[4]
  PIN b1[50]
    DIRECTION INPUT ;
    USE SIGNAL ;
    PORT
      LAYER M5 ;
        RECT  166.608 0 166.632 0.084 ;
    END
  END b1[50]
  PIN b1[51]
    DIRECTION INPUT ;
    USE SIGNAL ;
    PORT
      LAYER M5 ;
        RECT  166.752 0 166.776 0.084 ;
    END
  END b1[51]
  PIN b1[52]
    DIRECTION INPUT ;
    USE SIGNAL ;
    PORT
      LAYER M5 ;
        RECT  166.896 0 166.92 0.084 ;
    END
  END b1[52]
  PIN b1[53]
    DIRECTION INPUT ;
    USE SIGNAL ;
    PORT
      LAYER M5 ;
        RECT  167.04 0 167.064 0.084 ;
    END
  END b1[53]
  PIN b1[54]
    DIRECTION INPUT ;
    USE SIGNAL ;
    PORT
      LAYER M5 ;
        RECT  167.184 0 167.208 0.084 ;
    END
  END b1[54]
  PIN b1[55]
    DIRECTION INPUT ;
    USE SIGNAL ;
    PORT
      LAYER M5 ;
        RECT  167.328 0 167.352 0.084 ;
    END
  END b1[55]
  PIN b1[56]
    DIRECTION INPUT ;
    USE SIGNAL ;
    PORT
      LAYER M5 ;
        RECT  167.472 0 167.496 0.084 ;
    END
  END b1[56]
  PIN b1[57]
    DIRECTION INPUT ;
    USE SIGNAL ;
    PORT
      LAYER M5 ;
        RECT  167.616 0 167.64 0.084 ;
    END
  END b1[57]
  PIN b1[58]
    DIRECTION INPUT ;
    USE SIGNAL ;
    PORT
      LAYER M5 ;
        RECT  149.328 0 149.352 0.084 ;
    END
  END b1[58]
  PIN b1[59]
    DIRECTION INPUT ;
    USE SIGNAL ;
    PORT
      LAYER M5 ;
        RECT  149.472 0 149.496 0.084 ;
    END
  END b1[59]
  PIN b1[5]
    DIRECTION INPUT ;
    USE SIGNAL ;
    PORT
      LAYER M5 ;
        RECT  169.344 0 169.368 0.084 ;
    END
  END b1[5]
  PIN b1[60]
    DIRECTION INPUT ;
    USE SIGNAL ;
    PORT
      LAYER M5 ;
        RECT  149.616 0 149.64 0.084 ;
    END
  END b1[60]
  PIN b1[61]
    DIRECTION INPUT ;
    USE SIGNAL ;
    PORT
      LAYER M5 ;
        RECT  149.76 0 149.784 0.084 ;
    END
  END b1[61]
  PIN b1[62]
    DIRECTION INPUT ;
    USE SIGNAL ;
    PORT
      LAYER M5 ;
        RECT  149.904 0 149.928 0.084 ;
    END
  END b1[62]
  PIN b1[63]
    DIRECTION INPUT ;
    USE SIGNAL ;
    PORT
      LAYER M5 ;
        RECT  150.048 0 150.072 0.084 ;
    END
  END b1[63]
  PIN b1[64]
    DIRECTION INPUT ;
    USE SIGNAL ;
    PORT
      LAYER M5 ;
        RECT  150.192 0 150.216 0.084 ;
    END
  END b1[64]
  PIN b1[65]
    DIRECTION INPUT ;
    USE SIGNAL ;
    PORT
      LAYER M5 ;
        RECT  150.336 0 150.36 0.084 ;
    END
  END b1[65]
  PIN b1[66]
    DIRECTION INPUT ;
    USE SIGNAL ;
    PORT
      LAYER M5 ;
        RECT  150.48 0 150.504 0.084 ;
    END
  END b1[66]
  PIN b1[67]
    DIRECTION INPUT ;
    USE SIGNAL ;
    PORT
      LAYER M5 ;
        RECT  150.624 0 150.648 0.084 ;
    END
  END b1[67]
  PIN b1[68]
    DIRECTION INPUT ;
    USE SIGNAL ;
    PORT
      LAYER M5 ;
        RECT  150.768 0 150.792 0.084 ;
    END
  END b1[68]
  PIN b1[69]
    DIRECTION INPUT ;
    USE SIGNAL ;
    PORT
      LAYER M5 ;
        RECT  150.912 0 150.936 0.084 ;
    END
  END b1[69]
  PIN b1[6]
    DIRECTION INPUT ;
    USE SIGNAL ;
    PORT
      LAYER M5 ;
        RECT  169.488 0 169.512 0.084 ;
    END
  END b1[6]
  PIN b1[70]
    DIRECTION INPUT ;
    USE SIGNAL ;
    PORT
      LAYER M5 ;
        RECT  151.056 0 151.08 0.084 ;
    END
  END b1[70]
  PIN b1[71]
    DIRECTION INPUT ;
    USE SIGNAL ;
    PORT
      LAYER M5 ;
        RECT  151.2 0 151.224 0.084 ;
    END
  END b1[71]
  PIN b1[72]
    DIRECTION INPUT ;
    USE SIGNAL ;
    PORT
      LAYER M5 ;
        RECT  151.344 0 151.368 0.084 ;
    END
  END b1[72]
  PIN b1[73]
    DIRECTION INPUT ;
    USE SIGNAL ;
    PORT
      LAYER M5 ;
        RECT  151.488 0 151.512 0.084 ;
    END
  END b1[73]
  PIN b1[74]
    DIRECTION INPUT ;
    USE SIGNAL ;
    PORT
      LAYER M5 ;
        RECT  151.632 0 151.656 0.084 ;
    END
  END b1[74]
  PIN b1[75]
    DIRECTION INPUT ;
    USE SIGNAL ;
    PORT
      LAYER M5 ;
        RECT  151.776 0 151.8 0.084 ;
    END
  END b1[75]
  PIN b1[76]
    DIRECTION INPUT ;
    USE SIGNAL ;
    PORT
      LAYER M5 ;
        RECT  151.92 0 151.944 0.084 ;
    END
  END b1[76]
  PIN b1[77]
    DIRECTION INPUT ;
    USE SIGNAL ;
    PORT
      LAYER M5 ;
        RECT  152.064 0 152.088 0.084 ;
    END
  END b1[77]
  PIN b1[78]
    DIRECTION INPUT ;
    USE SIGNAL ;
    PORT
      LAYER M5 ;
        RECT  152.208 0 152.232 0.084 ;
    END
  END b1[78]
  PIN b1[79]
    DIRECTION INPUT ;
    USE SIGNAL ;
    PORT
      LAYER M5 ;
        RECT  152.352 0 152.376 0.084 ;
    END
  END b1[79]
  PIN b1[7]
    DIRECTION INPUT ;
    USE SIGNAL ;
    PORT
      LAYER M5 ;
        RECT  169.632 0 169.656 0.084 ;
    END
  END b1[7]
  PIN b1[80]
    DIRECTION INPUT ;
    USE SIGNAL ;
    PORT
      LAYER M5 ;
        RECT  152.496 0 152.52 0.084 ;
    END
  END b1[80]
  PIN b1[81]
    DIRECTION INPUT ;
    USE SIGNAL ;
    PORT
      LAYER M5 ;
        RECT  152.64 0 152.664 0.084 ;
    END
  END b1[81]
  PIN b1[82]
    DIRECTION INPUT ;
    USE SIGNAL ;
    PORT
      LAYER M5 ;
        RECT  152.784 0 152.808 0.084 ;
    END
  END b1[82]
  PIN b1[83]
    DIRECTION INPUT ;
    USE SIGNAL ;
    PORT
      LAYER M5 ;
        RECT  152.928 0 152.952 0.084 ;
    END
  END b1[83]
  PIN b1[84]
    DIRECTION INPUT ;
    USE SIGNAL ;
    PORT
      LAYER M5 ;
        RECT  153.072 0 153.096 0.084 ;
    END
  END b1[84]
  PIN b1[85]
    DIRECTION INPUT ;
    USE SIGNAL ;
    PORT
      LAYER M5 ;
        RECT  153.216 0 153.24 0.084 ;
    END
  END b1[85]
  PIN b1[86]
    DIRECTION INPUT ;
    USE SIGNAL ;
    PORT
      LAYER M5 ;
        RECT  153.36 0 153.384 0.084 ;
    END
  END b1[86]
  PIN b1[87]
    DIRECTION INPUT ;
    USE SIGNAL ;
    PORT
      LAYER M5 ;
        RECT  153.504 0 153.528 0.084 ;
    END
  END b1[87]
  PIN b1[88]
    DIRECTION INPUT ;
    USE SIGNAL ;
    PORT
      LAYER M5 ;
        RECT  153.648 0 153.672 0.084 ;
    END
  END b1[88]
  PIN b1[89]
    DIRECTION INPUT ;
    USE SIGNAL ;
    PORT
      LAYER M5 ;
        RECT  153.792 0 153.816 0.084 ;
    END
  END b1[89]
  PIN b1[8]
    DIRECTION INPUT ;
    USE SIGNAL ;
    PORT
      LAYER M5 ;
        RECT  169.776 0 169.8 0.084 ;
    END
  END b1[8]
  PIN b1[90]
    DIRECTION INPUT ;
    USE SIGNAL ;
    PORT
      LAYER M5 ;
        RECT  144.72 0 144.744 0.084 ;
    END
  END b1[90]
  PIN b1[91]
    DIRECTION INPUT ;
    USE SIGNAL ;
    PORT
      LAYER M5 ;
        RECT  144.864 0 144.888 0.084 ;
    END
  END b1[91]
  PIN b1[92]
    DIRECTION INPUT ;
    USE SIGNAL ;
    PORT
      LAYER M5 ;
        RECT  145.008 0 145.032 0.084 ;
    END
  END b1[92]
  PIN b1[93]
    DIRECTION INPUT ;
    USE SIGNAL ;
    PORT
      LAYER M5 ;
        RECT  145.152 0 145.176 0.084 ;
    END
  END b1[93]
  PIN b1[94]
    DIRECTION INPUT ;
    USE SIGNAL ;
    PORT
      LAYER M5 ;
        RECT  145.296 0 145.32 0.084 ;
    END
  END b1[94]
  PIN b1[95]
    DIRECTION INPUT ;
    USE SIGNAL ;
    PORT
      LAYER M5 ;
        RECT  145.44 0 145.464 0.084 ;
    END
  END b1[95]
  PIN b1[96]
    DIRECTION INPUT ;
    USE SIGNAL ;
    PORT
      LAYER M5 ;
        RECT  145.584 0 145.608 0.084 ;
    END
  END b1[96]
  PIN b1[97]
    DIRECTION INPUT ;
    USE SIGNAL ;
    PORT
      LAYER M5 ;
        RECT  145.728 0 145.752 0.084 ;
    END
  END b1[97]
  PIN b1[98]
    DIRECTION INPUT ;
    USE SIGNAL ;
    PORT
      LAYER M5 ;
        RECT  145.872 0 145.896 0.084 ;
    END
  END b1[98]
  PIN b1[99]
    DIRECTION INPUT ;
    USE SIGNAL ;
    PORT
      LAYER M5 ;
        RECT  146.016 0 146.04 0.084 ;
    END
  END b1[99]
  PIN b1[9]
    DIRECTION INPUT ;
    USE SIGNAL ;
    PORT
      LAYER M5 ;
        RECT  169.92 0 169.944 0.084 ;
    END
  END b1[9]
  PIN ck
    DIRECTION INPUT ;
    USE SIGNAL ;
    PORT
      LAYER M4 ;
        RECT  0 22.896 0.084 22.92 ;
    END
  END ck
  PIN ep[0]
    DIRECTION INPUT ;
    USE SIGNAL ;
    PORT
      LAYER M5 ;
        RECT  127.152 43.116 127.176 43.2 ;
    END
  END ep[0]
  PIN ep[10]
    DIRECTION INPUT ;
    USE SIGNAL ;
    PORT
      LAYER M5 ;
        RECT  128.592 43.116 128.616 43.2 ;
    END
  END ep[10]
  PIN ep[11]
    DIRECTION INPUT ;
    USE SIGNAL ;
    PORT
      LAYER M5 ;
        RECT  128.736 43.116 128.76 43.2 ;
    END
  END ep[11]
  PIN ep[12]
    DIRECTION INPUT ;
    USE SIGNAL ;
    PORT
      LAYER M5 ;
        RECT  128.88 43.116 128.904 43.2 ;
    END
  END ep[12]
  PIN ep[13]
    DIRECTION INPUT ;
    USE SIGNAL ;
    PORT
      LAYER M5 ;
        RECT  129.024 43.116 129.048 43.2 ;
    END
  END ep[13]
  PIN ep[14]
    DIRECTION INPUT ;
    USE SIGNAL ;
    PORT
      LAYER M5 ;
        RECT  129.168 43.116 129.192 43.2 ;
    END
  END ep[14]
  PIN ep[15]
    DIRECTION INPUT ;
    USE SIGNAL ;
    PORT
      LAYER M5 ;
        RECT  129.312 43.116 129.336 43.2 ;
    END
  END ep[15]
  PIN ep[1]
    DIRECTION INPUT ;
    USE SIGNAL ;
    PORT
      LAYER M5 ;
        RECT  127.296 43.116 127.32 43.2 ;
    END
  END ep[1]
  PIN ep[2]
    DIRECTION INPUT ;
    USE SIGNAL ;
    PORT
      LAYER M5 ;
        RECT  127.44 43.116 127.464 43.2 ;
    END
  END ep[2]
  PIN ep[3]
    DIRECTION INPUT ;
    USE SIGNAL ;
    PORT
      LAYER M5 ;
        RECT  127.584 43.116 127.608 43.2 ;
    END
  END ep[3]
  PIN ep[4]
    DIRECTION INPUT ;
    USE SIGNAL ;
    PORT
      LAYER M5 ;
        RECT  127.728 43.116 127.752 43.2 ;
    END
  END ep[4]
  PIN ep[5]
    DIRECTION INPUT ;
    USE SIGNAL ;
    PORT
      LAYER M5 ;
        RECT  127.872 43.116 127.896 43.2 ;
    END
  END ep[5]
  PIN ep[6]
    DIRECTION INPUT ;
    USE SIGNAL ;
    PORT
      LAYER M5 ;
        RECT  128.016 43.116 128.04 43.2 ;
    END
  END ep[6]
  PIN ep[7]
    DIRECTION INPUT ;
    USE SIGNAL ;
    PORT
      LAYER M5 ;
        RECT  128.16 43.116 128.184 43.2 ;
    END
  END ep[7]
  PIN ep[8]
    DIRECTION INPUT ;
    USE SIGNAL ;
    PORT
      LAYER M5 ;
        RECT  128.304 43.116 128.328 43.2 ;
    END
  END ep[8]
  PIN ep[9]
    DIRECTION INPUT ;
    USE SIGNAL ;
    PORT
      LAYER M5 ;
        RECT  128.448 43.116 128.472 43.2 ;
    END
  END ep[9]
  PIN o_beat[0]
    DIRECTION OUTPUT ;
    USE SIGNAL ;
    PORT
      LAYER M5 ;
        RECT  129.456 43.116 129.48 43.2 ;
    END
  END o_beat[0]
  PIN o_beat[1]
    DIRECTION OUTPUT ;
    USE SIGNAL ;
    PORT
      LAYER M5 ;
        RECT  129.6 43.116 129.624 43.2 ;
    END
  END o_beat[1]
  PIN o_beat[2]
    DIRECTION OUTPUT ;
    USE SIGNAL ;
    PORT
      LAYER M5 ;
        RECT  129.744 43.116 129.768 43.2 ;
    END
  END o_beat[2]
  PIN o_beat[3]
    DIRECTION OUTPUT ;
    USE SIGNAL ;
    PORT
      LAYER M5 ;
        RECT  129.888 43.116 129.912 43.2 ;
    END
  END o_beat[3]
  PIN o_beat[4]
    DIRECTION OUTPUT ;
    USE SIGNAL ;
    PORT
      LAYER M5 ;
        RECT  130.032 43.116 130.056 43.2 ;
    END
  END o_beat[4]
  PIN o_data[0]
    DIRECTION OUTPUT ;
    USE SIGNAL ;
    PORT
      LAYER M5 ;
        RECT  130.176 43.116 130.2 43.2 ;
    END
  END o_data[0]
  PIN o_data[100]
    DIRECTION OUTPUT ;
    USE SIGNAL ;
    PORT
      LAYER M5 ;
        RECT  83.52 43.116 83.544 43.2 ;
    END
  END o_data[100]
  PIN o_data[101]
    DIRECTION OUTPUT ;
    USE SIGNAL ;
    PORT
      LAYER M5 ;
        RECT  83.664 43.116 83.688 43.2 ;
    END
  END o_data[101]
  PIN o_data[102]
    DIRECTION OUTPUT ;
    USE SIGNAL ;
    PORT
      LAYER M5 ;
        RECT  83.808 43.116 83.832 43.2 ;
    END
  END o_data[102]
  PIN o_data[103]
    DIRECTION OUTPUT ;
    USE SIGNAL ;
    PORT
      LAYER M5 ;
        RECT  83.952 43.116 83.976 43.2 ;
    END
  END o_data[103]
  PIN o_data[104]
    DIRECTION OUTPUT ;
    USE SIGNAL ;
    PORT
      LAYER M5 ;
        RECT  84.096 43.116 84.12 43.2 ;
    END
  END o_data[104]
  PIN o_data[105]
    DIRECTION OUTPUT ;
    USE SIGNAL ;
    PORT
      LAYER M5 ;
        RECT  84.24 43.116 84.264 43.2 ;
    END
  END o_data[105]
  PIN o_data[106]
    DIRECTION OUTPUT ;
    USE SIGNAL ;
    PORT
      LAYER M5 ;
        RECT  84.384 43.116 84.408 43.2 ;
    END
  END o_data[106]
  PIN o_data[107]
    DIRECTION OUTPUT ;
    USE SIGNAL ;
    PORT
      LAYER M5 ;
        RECT  89.136 43.116 89.16 43.2 ;
    END
  END o_data[107]
  PIN o_data[108]
    DIRECTION OUTPUT ;
    USE SIGNAL ;
    PORT
      LAYER M5 ;
        RECT  89.28 43.116 89.304 43.2 ;
    END
  END o_data[108]
  PIN o_data[109]
    DIRECTION OUTPUT ;
    USE SIGNAL ;
    PORT
      LAYER M5 ;
        RECT  89.424 43.116 89.448 43.2 ;
    END
  END o_data[109]
  PIN o_data[10]
    DIRECTION OUTPUT ;
    USE SIGNAL ;
    PORT
      LAYER M5 ;
        RECT  131.616 43.116 131.64 43.2 ;
    END
  END o_data[10]
  PIN o_data[110]
    DIRECTION OUTPUT ;
    USE SIGNAL ;
    PORT
      LAYER M5 ;
        RECT  89.568 43.116 89.592 43.2 ;
    END
  END o_data[110]
  PIN o_data[111]
    DIRECTION OUTPUT ;
    USE SIGNAL ;
    PORT
      LAYER M5 ;
        RECT  89.712 43.116 89.736 43.2 ;
    END
  END o_data[111]
  PIN o_data[112]
    DIRECTION OUTPUT ;
    USE SIGNAL ;
    PORT
      LAYER M5 ;
        RECT  89.856 43.116 89.88 43.2 ;
    END
  END o_data[112]
  PIN o_data[113]
    DIRECTION OUTPUT ;
    USE SIGNAL ;
    PORT
      LAYER M5 ;
        RECT  90 43.116 90.024 43.2 ;
    END
  END o_data[113]
  PIN o_data[114]
    DIRECTION OUTPUT ;
    USE SIGNAL ;
    PORT
      LAYER M5 ;
        RECT  90.144 43.116 90.168 43.2 ;
    END
  END o_data[114]
  PIN o_data[115]
    DIRECTION OUTPUT ;
    USE SIGNAL ;
    PORT
      LAYER M5 ;
        RECT  90.288 43.116 90.312 43.2 ;
    END
  END o_data[115]
  PIN o_data[116]
    DIRECTION OUTPUT ;
    USE SIGNAL ;
    PORT
      LAYER M5 ;
        RECT  90.432 43.116 90.456 43.2 ;
    END
  END o_data[116]
  PIN o_data[117]
    DIRECTION OUTPUT ;
    USE SIGNAL ;
    PORT
      LAYER M5 ;
        RECT  90.576 43.116 90.6 43.2 ;
    END
  END o_data[117]
  PIN o_data[118]
    DIRECTION OUTPUT ;
    USE SIGNAL ;
    PORT
      LAYER M5 ;
        RECT  90.72 43.116 90.744 43.2 ;
    END
  END o_data[118]
  PIN o_data[119]
    DIRECTION OUTPUT ;
    USE SIGNAL ;
    PORT
      LAYER M5 ;
        RECT  90.864 43.116 90.888 43.2 ;
    END
  END o_data[119]
  PIN o_data[11]
    DIRECTION OUTPUT ;
    USE SIGNAL ;
    PORT
      LAYER M5 ;
        RECT  84.528 43.116 84.552 43.2 ;
    END
  END o_data[11]
  PIN o_data[120]
    DIRECTION OUTPUT ;
    USE SIGNAL ;
    PORT
      LAYER M5 ;
        RECT  91.008 43.116 91.032 43.2 ;
    END
  END o_data[120]
  PIN o_data[121]
    DIRECTION OUTPUT ;
    USE SIGNAL ;
    PORT
      LAYER M5 ;
        RECT  91.152 43.116 91.176 43.2 ;
    END
  END o_data[121]
  PIN o_data[122]
    DIRECTION OUTPUT ;
    USE SIGNAL ;
    PORT
      LAYER M5 ;
        RECT  91.296 43.116 91.32 43.2 ;
    END
  END o_data[122]
  PIN o_data[123]
    DIRECTION OUTPUT ;
    USE SIGNAL ;
    PORT
      LAYER M5 ;
        RECT  91.44 43.116 91.464 43.2 ;
    END
  END o_data[123]
  PIN o_data[124]
    DIRECTION OUTPUT ;
    USE SIGNAL ;
    PORT
      LAYER M5 ;
        RECT  91.584 43.116 91.608 43.2 ;
    END
  END o_data[124]
  PIN o_data[125]
    DIRECTION OUTPUT ;
    USE SIGNAL ;
    PORT
      LAYER M5 ;
        RECT  91.728 43.116 91.752 43.2 ;
    END
  END o_data[125]
  PIN o_data[126]
    DIRECTION OUTPUT ;
    USE SIGNAL ;
    PORT
      LAYER M5 ;
        RECT  91.872 43.116 91.896 43.2 ;
    END
  END o_data[126]
  PIN o_data[127]
    DIRECTION OUTPUT ;
    USE SIGNAL ;
    PORT
      LAYER M5 ;
        RECT  92.016 43.116 92.04 43.2 ;
    END
  END o_data[127]
  PIN o_data[128]
    DIRECTION OUTPUT ;
    USE SIGNAL ;
    PORT
      LAYER M5 ;
        RECT  92.16 43.116 92.184 43.2 ;
    END
  END o_data[128]
  PIN o_data[129]
    DIRECTION OUTPUT ;
    USE SIGNAL ;
    PORT
      LAYER M5 ;
        RECT  92.304 43.116 92.328 43.2 ;
    END
  END o_data[129]
  PIN o_data[12]
    DIRECTION OUTPUT ;
    USE SIGNAL ;
    PORT
      LAYER M5 ;
        RECT  84.672 43.116 84.696 43.2 ;
    END
  END o_data[12]
  PIN o_data[130]
    DIRECTION OUTPUT ;
    USE SIGNAL ;
    PORT
      LAYER M5 ;
        RECT  92.448 43.116 92.472 43.2 ;
    END
  END o_data[130]
  PIN o_data[131]
    DIRECTION OUTPUT ;
    USE SIGNAL ;
    PORT
      LAYER M5 ;
        RECT  92.592 43.116 92.616 43.2 ;
    END
  END o_data[131]
  PIN o_data[132]
    DIRECTION OUTPUT ;
    USE SIGNAL ;
    PORT
      LAYER M5 ;
        RECT  92.736 43.116 92.76 43.2 ;
    END
  END o_data[132]
  PIN o_data[133]
    DIRECTION OUTPUT ;
    USE SIGNAL ;
    PORT
      LAYER M5 ;
        RECT  92.88 43.116 92.904 43.2 ;
    END
  END o_data[133]
  PIN o_data[134]
    DIRECTION OUTPUT ;
    USE SIGNAL ;
    PORT
      LAYER M5 ;
        RECT  93.024 43.116 93.048 43.2 ;
    END
  END o_data[134]
  PIN o_data[135]
    DIRECTION OUTPUT ;
    USE SIGNAL ;
    PORT
      LAYER M5 ;
        RECT  93.168 43.116 93.192 43.2 ;
    END
  END o_data[135]
  PIN o_data[136]
    DIRECTION OUTPUT ;
    USE SIGNAL ;
    PORT
      LAYER M5 ;
        RECT  93.312 43.116 93.336 43.2 ;
    END
  END o_data[136]
  PIN o_data[137]
    DIRECTION OUTPUT ;
    USE SIGNAL ;
    PORT
      LAYER M5 ;
        RECT  93.456 43.116 93.48 43.2 ;
    END
  END o_data[137]
  PIN o_data[138]
    DIRECTION OUTPUT ;
    USE SIGNAL ;
    PORT
      LAYER M5 ;
        RECT  93.6 43.116 93.624 43.2 ;
    END
  END o_data[138]
  PIN o_data[139]
    DIRECTION OUTPUT ;
    USE SIGNAL ;
    PORT
      LAYER M5 ;
        RECT  93.744 43.116 93.768 43.2 ;
    END
  END o_data[139]
  PIN o_data[13]
    DIRECTION OUTPUT ;
    USE SIGNAL ;
    PORT
      LAYER M5 ;
        RECT  84.816 43.116 84.84 43.2 ;
    END
  END o_data[13]
  PIN o_data[140]
    DIRECTION OUTPUT ;
    USE SIGNAL ;
    PORT
      LAYER M5 ;
        RECT  93.888 43.116 93.912 43.2 ;
    END
  END o_data[140]
  PIN o_data[141]
    DIRECTION OUTPUT ;
    USE SIGNAL ;
    PORT
      LAYER M5 ;
        RECT  94.032 43.116 94.056 43.2 ;
    END
  END o_data[141]
  PIN o_data[142]
    DIRECTION OUTPUT ;
    USE SIGNAL ;
    PORT
      LAYER M5 ;
        RECT  94.176 43.116 94.2 43.2 ;
    END
  END o_data[142]
  PIN o_data[143]
    DIRECTION OUTPUT ;
    USE SIGNAL ;
    PORT
      LAYER M5 ;
        RECT  94.32 43.116 94.344 43.2 ;
    END
  END o_data[143]
  PIN o_data[144]
    DIRECTION OUTPUT ;
    USE SIGNAL ;
    PORT
      LAYER M5 ;
        RECT  94.464 43.116 94.488 43.2 ;
    END
  END o_data[144]
  PIN o_data[145]
    DIRECTION OUTPUT ;
    USE SIGNAL ;
    PORT
      LAYER M5 ;
        RECT  94.608 43.116 94.632 43.2 ;
    END
  END o_data[145]
  PIN o_data[146]
    DIRECTION OUTPUT ;
    USE SIGNAL ;
    PORT
      LAYER M5 ;
        RECT  94.752 43.116 94.776 43.2 ;
    END
  END o_data[146]
  PIN o_data[147]
    DIRECTION OUTPUT ;
    USE SIGNAL ;
    PORT
      LAYER M5 ;
        RECT  94.896 43.116 94.92 43.2 ;
    END
  END o_data[147]
  PIN o_data[148]
    DIRECTION OUTPUT ;
    USE SIGNAL ;
    PORT
      LAYER M5 ;
        RECT  95.04 43.116 95.064 43.2 ;
    END
  END o_data[148]
  PIN o_data[149]
    DIRECTION OUTPUT ;
    USE SIGNAL ;
    PORT
      LAYER M5 ;
        RECT  95.184 43.116 95.208 43.2 ;
    END
  END o_data[149]
  PIN o_data[14]
    DIRECTION OUTPUT ;
    USE SIGNAL ;
    PORT
      LAYER M5 ;
        RECT  84.96 43.116 84.984 43.2 ;
    END
  END o_data[14]
  PIN o_data[150]
    DIRECTION OUTPUT ;
    USE SIGNAL ;
    PORT
      LAYER M5 ;
        RECT  95.328 43.116 95.352 43.2 ;
    END
  END o_data[150]
  PIN o_data[151]
    DIRECTION OUTPUT ;
    USE SIGNAL ;
    PORT
      LAYER M5 ;
        RECT  95.472 43.116 95.496 43.2 ;
    END
  END o_data[151]
  PIN o_data[152]
    DIRECTION OUTPUT ;
    USE SIGNAL ;
    PORT
      LAYER M5 ;
        RECT  95.616 43.116 95.64 43.2 ;
    END
  END o_data[152]
  PIN o_data[153]
    DIRECTION OUTPUT ;
    USE SIGNAL ;
    PORT
      LAYER M5 ;
        RECT  95.76 43.116 95.784 43.2 ;
    END
  END o_data[153]
  PIN o_data[154]
    DIRECTION OUTPUT ;
    USE SIGNAL ;
    PORT
      LAYER M5 ;
        RECT  95.904 43.116 95.928 43.2 ;
    END
  END o_data[154]
  PIN o_data[155]
    DIRECTION OUTPUT ;
    USE SIGNAL ;
    PORT
      LAYER M5 ;
        RECT  96.048 43.116 96.072 43.2 ;
    END
  END o_data[155]
  PIN o_data[156]
    DIRECTION OUTPUT ;
    USE SIGNAL ;
    PORT
      LAYER M5 ;
        RECT  96.192 43.116 96.216 43.2 ;
    END
  END o_data[156]
  PIN o_data[157]
    DIRECTION OUTPUT ;
    USE SIGNAL ;
    PORT
      LAYER M5 ;
        RECT  96.336 43.116 96.36 43.2 ;
    END
  END o_data[157]
  PIN o_data[158]
    DIRECTION OUTPUT ;
    USE SIGNAL ;
    PORT
      LAYER M5 ;
        RECT  96.48 43.116 96.504 43.2 ;
    END
  END o_data[158]
  PIN o_data[159]
    DIRECTION OUTPUT ;
    USE SIGNAL ;
    PORT
      LAYER M5 ;
        RECT  96.624 43.116 96.648 43.2 ;
    END
  END o_data[159]
  PIN o_data[15]
    DIRECTION OUTPUT ;
    USE SIGNAL ;
    PORT
      LAYER M5 ;
        RECT  85.104 43.116 85.128 43.2 ;
    END
  END o_data[15]
  PIN o_data[160]
    DIRECTION OUTPUT ;
    USE SIGNAL ;
    PORT
      LAYER M5 ;
        RECT  96.768 43.116 96.792 43.2 ;
    END
  END o_data[160]
  PIN o_data[161]
    DIRECTION OUTPUT ;
    USE SIGNAL ;
    PORT
      LAYER M5 ;
        RECT  96.912 43.116 96.936 43.2 ;
    END
  END o_data[161]
  PIN o_data[162]
    DIRECTION OUTPUT ;
    USE SIGNAL ;
    PORT
      LAYER M5 ;
        RECT  97.056 43.116 97.08 43.2 ;
    END
  END o_data[162]
  PIN o_data[163]
    DIRECTION OUTPUT ;
    USE SIGNAL ;
    PORT
      LAYER M5 ;
        RECT  97.2 43.116 97.224 43.2 ;
    END
  END o_data[163]
  PIN o_data[164]
    DIRECTION OUTPUT ;
    USE SIGNAL ;
    PORT
      LAYER M5 ;
        RECT  97.344 43.116 97.368 43.2 ;
    END
  END o_data[164]
  PIN o_data[165]
    DIRECTION OUTPUT ;
    USE SIGNAL ;
    PORT
      LAYER M5 ;
        RECT  97.488 43.116 97.512 43.2 ;
    END
  END o_data[165]
  PIN o_data[166]
    DIRECTION OUTPUT ;
    USE SIGNAL ;
    PORT
      LAYER M5 ;
        RECT  97.632 43.116 97.656 43.2 ;
    END
  END o_data[166]
  PIN o_data[167]
    DIRECTION OUTPUT ;
    USE SIGNAL ;
    PORT
      LAYER M5 ;
        RECT  97.776 43.116 97.8 43.2 ;
    END
  END o_data[167]
  PIN o_data[168]
    DIRECTION OUTPUT ;
    USE SIGNAL ;
    PORT
      LAYER M5 ;
        RECT  97.92 43.116 97.944 43.2 ;
    END
  END o_data[168]
  PIN o_data[169]
    DIRECTION OUTPUT ;
    USE SIGNAL ;
    PORT
      LAYER M5 ;
        RECT  98.064 43.116 98.088 43.2 ;
    END
  END o_data[169]
  PIN o_data[16]
    DIRECTION OUTPUT ;
    USE SIGNAL ;
    PORT
      LAYER M5 ;
        RECT  85.248 43.116 85.272 43.2 ;
    END
  END o_data[16]
  PIN o_data[170]
    DIRECTION OUTPUT ;
    USE SIGNAL ;
    PORT
      LAYER M5 ;
        RECT  98.208 43.116 98.232 43.2 ;
    END
  END o_data[170]
  PIN o_data[171]
    DIRECTION OUTPUT ;
    USE SIGNAL ;
    PORT
      LAYER M5 ;
        RECT  104.112 43.116 104.136 43.2 ;
    END
  END o_data[171]
  PIN o_data[172]
    DIRECTION OUTPUT ;
    USE SIGNAL ;
    PORT
      LAYER M5 ;
        RECT  104.256 43.116 104.28 43.2 ;
    END
  END o_data[172]
  PIN o_data[173]
    DIRECTION OUTPUT ;
    USE SIGNAL ;
    PORT
      LAYER M5 ;
        RECT  104.4 43.116 104.424 43.2 ;
    END
  END o_data[173]
  PIN o_data[174]
    DIRECTION OUTPUT ;
    USE SIGNAL ;
    PORT
      LAYER M5 ;
        RECT  104.544 43.116 104.568 43.2 ;
    END
  END o_data[174]
  PIN o_data[175]
    DIRECTION OUTPUT ;
    USE SIGNAL ;
    PORT
      LAYER M5 ;
        RECT  104.688 43.116 104.712 43.2 ;
    END
  END o_data[175]
  PIN o_data[176]
    DIRECTION OUTPUT ;
    USE SIGNAL ;
    PORT
      LAYER M5 ;
        RECT  104.832 43.116 104.856 43.2 ;
    END
  END o_data[176]
  PIN o_data[177]
    DIRECTION OUTPUT ;
    USE SIGNAL ;
    PORT
      LAYER M5 ;
        RECT  104.976 43.116 105 43.2 ;
    END
  END o_data[177]
  PIN o_data[178]
    DIRECTION OUTPUT ;
    USE SIGNAL ;
    PORT
      LAYER M5 ;
        RECT  105.12 43.116 105.144 43.2 ;
    END
  END o_data[178]
  PIN o_data[179]
    DIRECTION OUTPUT ;
    USE SIGNAL ;
    PORT
      LAYER M5 ;
        RECT  105.264 43.116 105.288 43.2 ;
    END
  END o_data[179]
  PIN o_data[17]
    DIRECTION OUTPUT ;
    USE SIGNAL ;
    PORT
      LAYER M5 ;
        RECT  85.392 43.116 85.416 43.2 ;
    END
  END o_data[17]
  PIN o_data[180]
    DIRECTION OUTPUT ;
    USE SIGNAL ;
    PORT
      LAYER M5 ;
        RECT  105.408 43.116 105.432 43.2 ;
    END
  END o_data[180]
  PIN o_data[181]
    DIRECTION OUTPUT ;
    USE SIGNAL ;
    PORT
      LAYER M5 ;
        RECT  105.552 43.116 105.576 43.2 ;
    END
  END o_data[181]
  PIN o_data[182]
    DIRECTION OUTPUT ;
    USE SIGNAL ;
    PORT
      LAYER M5 ;
        RECT  105.696 43.116 105.72 43.2 ;
    END
  END o_data[182]
  PIN o_data[183]
    DIRECTION OUTPUT ;
    USE SIGNAL ;
    PORT
      LAYER M5 ;
        RECT  105.84 43.116 105.864 43.2 ;
    END
  END o_data[183]
  PIN o_data[184]
    DIRECTION OUTPUT ;
    USE SIGNAL ;
    PORT
      LAYER M5 ;
        RECT  105.984 43.116 106.008 43.2 ;
    END
  END o_data[184]
  PIN o_data[185]
    DIRECTION OUTPUT ;
    USE SIGNAL ;
    PORT
      LAYER M5 ;
        RECT  106.128 43.116 106.152 43.2 ;
    END
  END o_data[185]
  PIN o_data[186]
    DIRECTION OUTPUT ;
    USE SIGNAL ;
    PORT
      LAYER M5 ;
        RECT  106.272 43.116 106.296 43.2 ;
    END
  END o_data[186]
  PIN o_data[187]
    DIRECTION OUTPUT ;
    USE SIGNAL ;
    PORT
      LAYER M5 ;
        RECT  106.416 43.116 106.44 43.2 ;
    END
  END o_data[187]
  PIN o_data[188]
    DIRECTION OUTPUT ;
    USE SIGNAL ;
    PORT
      LAYER M5 ;
        RECT  106.56 43.116 106.584 43.2 ;
    END
  END o_data[188]
  PIN o_data[189]
    DIRECTION OUTPUT ;
    USE SIGNAL ;
    PORT
      LAYER M5 ;
        RECT  106.704 43.116 106.728 43.2 ;
    END
  END o_data[189]
  PIN o_data[18]
    DIRECTION OUTPUT ;
    USE SIGNAL ;
    PORT
      LAYER M5 ;
        RECT  85.536 43.116 85.56 43.2 ;
    END
  END o_data[18]
  PIN o_data[190]
    DIRECTION OUTPUT ;
    USE SIGNAL ;
    PORT
      LAYER M5 ;
        RECT  106.848 43.116 106.872 43.2 ;
    END
  END o_data[190]
  PIN o_data[191]
    DIRECTION OUTPUT ;
    USE SIGNAL ;
    PORT
      LAYER M5 ;
        RECT  106.992 43.116 107.016 43.2 ;
    END
  END o_data[191]
  PIN o_data[192]
    DIRECTION OUTPUT ;
    USE SIGNAL ;
    PORT
      LAYER M5 ;
        RECT  107.136 43.116 107.16 43.2 ;
    END
  END o_data[192]
  PIN o_data[193]
    DIRECTION OUTPUT ;
    USE SIGNAL ;
    PORT
      LAYER M5 ;
        RECT  107.28 43.116 107.304 43.2 ;
    END
  END o_data[193]
  PIN o_data[194]
    DIRECTION OUTPUT ;
    USE SIGNAL ;
    PORT
      LAYER M5 ;
        RECT  107.424 43.116 107.448 43.2 ;
    END
  END o_data[194]
  PIN o_data[195]
    DIRECTION OUTPUT ;
    USE SIGNAL ;
    PORT
      LAYER M5 ;
        RECT  107.568 43.116 107.592 43.2 ;
    END
  END o_data[195]
  PIN o_data[196]
    DIRECTION OUTPUT ;
    USE SIGNAL ;
    PORT
      LAYER M5 ;
        RECT  107.712 43.116 107.736 43.2 ;
    END
  END o_data[196]
  PIN o_data[197]
    DIRECTION OUTPUT ;
    USE SIGNAL ;
    PORT
      LAYER M5 ;
        RECT  107.856 43.116 107.88 43.2 ;
    END
  END o_data[197]
  PIN o_data[198]
    DIRECTION OUTPUT ;
    USE SIGNAL ;
    PORT
      LAYER M5 ;
        RECT  108 43.116 108.024 43.2 ;
    END
  END o_data[198]
  PIN o_data[199]
    DIRECTION OUTPUT ;
    USE SIGNAL ;
    PORT
      LAYER M5 ;
        RECT  108.144 43.116 108.168 43.2 ;
    END
  END o_data[199]
  PIN o_data[19]
    DIRECTION OUTPUT ;
    USE SIGNAL ;
    PORT
      LAYER M5 ;
        RECT  85.68 43.116 85.704 43.2 ;
    END
  END o_data[19]
  PIN o_data[1]
    DIRECTION OUTPUT ;
    USE SIGNAL ;
    PORT
      LAYER M5 ;
        RECT  130.32 43.116 130.344 43.2 ;
    END
  END o_data[1]
  PIN o_data[200]
    DIRECTION OUTPUT ;
    USE SIGNAL ;
    PORT
      LAYER M5 ;
        RECT  108.288 43.116 108.312 43.2 ;
    END
  END o_data[200]
  PIN o_data[201]
    DIRECTION OUTPUT ;
    USE SIGNAL ;
    PORT
      LAYER M5 ;
        RECT  108.432 43.116 108.456 43.2 ;
    END
  END o_data[201]
  PIN o_data[202]
    DIRECTION OUTPUT ;
    USE SIGNAL ;
    PORT
      LAYER M5 ;
        RECT  108.576 43.116 108.6 43.2 ;
    END
  END o_data[202]
  PIN o_data[203]
    DIRECTION OUTPUT ;
    USE SIGNAL ;
    PORT
      LAYER M5 ;
        RECT  98.352 43.116 98.376 43.2 ;
    END
  END o_data[203]
  PIN o_data[204]
    DIRECTION OUTPUT ;
    USE SIGNAL ;
    PORT
      LAYER M5 ;
        RECT  98.496 43.116 98.52 43.2 ;
    END
  END o_data[204]
  PIN o_data[205]
    DIRECTION OUTPUT ;
    USE SIGNAL ;
    PORT
      LAYER M5 ;
        RECT  98.64 43.116 98.664 43.2 ;
    END
  END o_data[205]
  PIN o_data[206]
    DIRECTION OUTPUT ;
    USE SIGNAL ;
    PORT
      LAYER M5 ;
        RECT  98.784 43.116 98.808 43.2 ;
    END
  END o_data[206]
  PIN o_data[207]
    DIRECTION OUTPUT ;
    USE SIGNAL ;
    PORT
      LAYER M5 ;
        RECT  98.928 43.116 98.952 43.2 ;
    END
  END o_data[207]
  PIN o_data[208]
    DIRECTION OUTPUT ;
    USE SIGNAL ;
    PORT
      LAYER M5 ;
        RECT  99.072 43.116 99.096 43.2 ;
    END
  END o_data[208]
  PIN o_data[209]
    DIRECTION OUTPUT ;
    USE SIGNAL ;
    PORT
      LAYER M5 ;
        RECT  99.216 43.116 99.24 43.2 ;
    END
  END o_data[209]
  PIN o_data[20]
    DIRECTION OUTPUT ;
    USE SIGNAL ;
    PORT
      LAYER M5 ;
        RECT  85.824 43.116 85.848 43.2 ;
    END
  END o_data[20]
  PIN o_data[210]
    DIRECTION OUTPUT ;
    USE SIGNAL ;
    PORT
      LAYER M5 ;
        RECT  99.36 43.116 99.384 43.2 ;
    END
  END o_data[210]
  PIN o_data[211]
    DIRECTION OUTPUT ;
    USE SIGNAL ;
    PORT
      LAYER M5 ;
        RECT  99.504 43.116 99.528 43.2 ;
    END
  END o_data[211]
  PIN o_data[212]
    DIRECTION OUTPUT ;
    USE SIGNAL ;
    PORT
      LAYER M5 ;
        RECT  99.648 43.116 99.672 43.2 ;
    END
  END o_data[212]
  PIN o_data[213]
    DIRECTION OUTPUT ;
    USE SIGNAL ;
    PORT
      LAYER M5 ;
        RECT  99.792 43.116 99.816 43.2 ;
    END
  END o_data[213]
  PIN o_data[214]
    DIRECTION OUTPUT ;
    USE SIGNAL ;
    PORT
      LAYER M5 ;
        RECT  99.936 43.116 99.96 43.2 ;
    END
  END o_data[214]
  PIN o_data[215]
    DIRECTION OUTPUT ;
    USE SIGNAL ;
    PORT
      LAYER M5 ;
        RECT  100.08 43.116 100.104 43.2 ;
    END
  END o_data[215]
  PIN o_data[216]
    DIRECTION OUTPUT ;
    USE SIGNAL ;
    PORT
      LAYER M5 ;
        RECT  100.224 43.116 100.248 43.2 ;
    END
  END o_data[216]
  PIN o_data[217]
    DIRECTION OUTPUT ;
    USE SIGNAL ;
    PORT
      LAYER M5 ;
        RECT  100.368 43.116 100.392 43.2 ;
    END
  END o_data[217]
  PIN o_data[218]
    DIRECTION OUTPUT ;
    USE SIGNAL ;
    PORT
      LAYER M5 ;
        RECT  100.512 43.116 100.536 43.2 ;
    END
  END o_data[218]
  PIN o_data[219]
    DIRECTION OUTPUT ;
    USE SIGNAL ;
    PORT
      LAYER M5 ;
        RECT  100.656 43.116 100.68 43.2 ;
    END
  END o_data[219]
  PIN o_data[21]
    DIRECTION OUTPUT ;
    USE SIGNAL ;
    PORT
      LAYER M5 ;
        RECT  85.968 43.116 85.992 43.2 ;
    END
  END o_data[21]
  PIN o_data[220]
    DIRECTION OUTPUT ;
    USE SIGNAL ;
    PORT
      LAYER M5 ;
        RECT  100.8 43.116 100.824 43.2 ;
    END
  END o_data[220]
  PIN o_data[221]
    DIRECTION OUTPUT ;
    USE SIGNAL ;
    PORT
      LAYER M5 ;
        RECT  100.944 43.116 100.968 43.2 ;
    END
  END o_data[221]
  PIN o_data[222]
    DIRECTION OUTPUT ;
    USE SIGNAL ;
    PORT
      LAYER M5 ;
        RECT  101.088 43.116 101.112 43.2 ;
    END
  END o_data[222]
  PIN o_data[223]
    DIRECTION OUTPUT ;
    USE SIGNAL ;
    PORT
      LAYER M5 ;
        RECT  101.232 43.116 101.256 43.2 ;
    END
  END o_data[223]
  PIN o_data[224]
    DIRECTION OUTPUT ;
    USE SIGNAL ;
    PORT
      LAYER M5 ;
        RECT  101.376 43.116 101.4 43.2 ;
    END
  END o_data[224]
  PIN o_data[225]
    DIRECTION OUTPUT ;
    USE SIGNAL ;
    PORT
      LAYER M5 ;
        RECT  101.52 43.116 101.544 43.2 ;
    END
  END o_data[225]
  PIN o_data[226]
    DIRECTION OUTPUT ;
    USE SIGNAL ;
    PORT
      LAYER M5 ;
        RECT  101.664 43.116 101.688 43.2 ;
    END
  END o_data[226]
  PIN o_data[227]
    DIRECTION OUTPUT ;
    USE SIGNAL ;
    PORT
      LAYER M5 ;
        RECT  101.808 43.116 101.832 43.2 ;
    END
  END o_data[227]
  PIN o_data[228]
    DIRECTION OUTPUT ;
    USE SIGNAL ;
    PORT
      LAYER M5 ;
        RECT  101.952 43.116 101.976 43.2 ;
    END
  END o_data[228]
  PIN o_data[229]
    DIRECTION OUTPUT ;
    USE SIGNAL ;
    PORT
      LAYER M5 ;
        RECT  102.096 43.116 102.12 43.2 ;
    END
  END o_data[229]
  PIN o_data[22]
    DIRECTION OUTPUT ;
    USE SIGNAL ;
    PORT
      LAYER M5 ;
        RECT  86.112 43.116 86.136 43.2 ;
    END
  END o_data[22]
  PIN o_data[230]
    DIRECTION OUTPUT ;
    USE SIGNAL ;
    PORT
      LAYER M5 ;
        RECT  102.24 43.116 102.264 43.2 ;
    END
  END o_data[230]
  PIN o_data[231]
    DIRECTION OUTPUT ;
    USE SIGNAL ;
    PORT
      LAYER M5 ;
        RECT  102.384 43.116 102.408 43.2 ;
    END
  END o_data[231]
  PIN o_data[232]
    DIRECTION OUTPUT ;
    USE SIGNAL ;
    PORT
      LAYER M5 ;
        RECT  102.528 43.116 102.552 43.2 ;
    END
  END o_data[232]
  PIN o_data[233]
    DIRECTION OUTPUT ;
    USE SIGNAL ;
    PORT
      LAYER M5 ;
        RECT  102.672 43.116 102.696 43.2 ;
    END
  END o_data[233]
  PIN o_data[234]
    DIRECTION OUTPUT ;
    USE SIGNAL ;
    PORT
      LAYER M5 ;
        RECT  102.816 43.116 102.84 43.2 ;
    END
  END o_data[234]
  PIN o_data[235]
    DIRECTION OUTPUT ;
    USE SIGNAL ;
    PORT
      LAYER M5 ;
        RECT  117.936 43.116 117.96 43.2 ;
    END
  END o_data[235]
  PIN o_data[236]
    DIRECTION OUTPUT ;
    USE SIGNAL ;
    PORT
      LAYER M5 ;
        RECT  118.08 43.116 118.104 43.2 ;
    END
  END o_data[236]
  PIN o_data[237]
    DIRECTION OUTPUT ;
    USE SIGNAL ;
    PORT
      LAYER M5 ;
        RECT  118.224 43.116 118.248 43.2 ;
    END
  END o_data[237]
  PIN o_data[238]
    DIRECTION OUTPUT ;
    USE SIGNAL ;
    PORT
      LAYER M5 ;
        RECT  118.368 43.116 118.392 43.2 ;
    END
  END o_data[238]
  PIN o_data[239]
    DIRECTION OUTPUT ;
    USE SIGNAL ;
    PORT
      LAYER M5 ;
        RECT  118.512 43.116 118.536 43.2 ;
    END
  END o_data[239]
  PIN o_data[23]
    DIRECTION OUTPUT ;
    USE SIGNAL ;
    PORT
      LAYER M5 ;
        RECT  86.256 43.116 86.28 43.2 ;
    END
  END o_data[23]
  PIN o_data[240]
    DIRECTION OUTPUT ;
    USE SIGNAL ;
    PORT
      LAYER M5 ;
        RECT  118.656 43.116 118.68 43.2 ;
    END
  END o_data[240]
  PIN o_data[241]
    DIRECTION OUTPUT ;
    USE SIGNAL ;
    PORT
      LAYER M5 ;
        RECT  118.8 43.116 118.824 43.2 ;
    END
  END o_data[241]
  PIN o_data[242]
    DIRECTION OUTPUT ;
    USE SIGNAL ;
    PORT
      LAYER M5 ;
        RECT  118.944 43.116 118.968 43.2 ;
    END
  END o_data[242]
  PIN o_data[243]
    DIRECTION OUTPUT ;
    USE SIGNAL ;
    PORT
      LAYER M5 ;
        RECT  119.088 43.116 119.112 43.2 ;
    END
  END o_data[243]
  PIN o_data[244]
    DIRECTION OUTPUT ;
    USE SIGNAL ;
    PORT
      LAYER M5 ;
        RECT  119.232 43.116 119.256 43.2 ;
    END
  END o_data[244]
  PIN o_data[245]
    DIRECTION OUTPUT ;
    USE SIGNAL ;
    PORT
      LAYER M5 ;
        RECT  119.376 43.116 119.4 43.2 ;
    END
  END o_data[245]
  PIN o_data[246]
    DIRECTION OUTPUT ;
    USE SIGNAL ;
    PORT
      LAYER M5 ;
        RECT  119.52 43.116 119.544 43.2 ;
    END
  END o_data[246]
  PIN o_data[247]
    DIRECTION OUTPUT ;
    USE SIGNAL ;
    PORT
      LAYER M5 ;
        RECT  119.664 43.116 119.688 43.2 ;
    END
  END o_data[247]
  PIN o_data[248]
    DIRECTION OUTPUT ;
    USE SIGNAL ;
    PORT
      LAYER M5 ;
        RECT  119.808 43.116 119.832 43.2 ;
    END
  END o_data[248]
  PIN o_data[249]
    DIRECTION OUTPUT ;
    USE SIGNAL ;
    PORT
      LAYER M5 ;
        RECT  119.952 43.116 119.976 43.2 ;
    END
  END o_data[249]
  PIN o_data[24]
    DIRECTION OUTPUT ;
    USE SIGNAL ;
    PORT
      LAYER M5 ;
        RECT  86.4 43.116 86.424 43.2 ;
    END
  END o_data[24]
  PIN o_data[250]
    DIRECTION OUTPUT ;
    USE SIGNAL ;
    PORT
      LAYER M5 ;
        RECT  120.096 43.116 120.12 43.2 ;
    END
  END o_data[250]
  PIN o_data[251]
    DIRECTION OUTPUT ;
    USE SIGNAL ;
    PORT
      LAYER M5 ;
        RECT  120.24 43.116 120.264 43.2 ;
    END
  END o_data[251]
  PIN o_data[252]
    DIRECTION OUTPUT ;
    USE SIGNAL ;
    PORT
      LAYER M5 ;
        RECT  120.384 43.116 120.408 43.2 ;
    END
  END o_data[252]
  PIN o_data[253]
    DIRECTION OUTPUT ;
    USE SIGNAL ;
    PORT
      LAYER M5 ;
        RECT  120.528 43.116 120.552 43.2 ;
    END
  END o_data[253]
  PIN o_data[254]
    DIRECTION OUTPUT ;
    USE SIGNAL ;
    PORT
      LAYER M5 ;
        RECT  120.672 43.116 120.696 43.2 ;
    END
  END o_data[254]
  PIN o_data[255]
    DIRECTION OUTPUT ;
    USE SIGNAL ;
    PORT
      LAYER M5 ;
        RECT  120.816 43.116 120.84 43.2 ;
    END
  END o_data[255]
  PIN o_data[256]
    DIRECTION OUTPUT ;
    USE SIGNAL ;
    PORT
      LAYER M5 ;
        RECT  120.96 43.116 120.984 43.2 ;
    END
  END o_data[256]
  PIN o_data[257]
    DIRECTION OUTPUT ;
    USE SIGNAL ;
    PORT
      LAYER M5 ;
        RECT  121.104 43.116 121.128 43.2 ;
    END
  END o_data[257]
  PIN o_data[258]
    DIRECTION OUTPUT ;
    USE SIGNAL ;
    PORT
      LAYER M5 ;
        RECT  121.248 43.116 121.272 43.2 ;
    END
  END o_data[258]
  PIN o_data[259]
    DIRECTION OUTPUT ;
    USE SIGNAL ;
    PORT
      LAYER M5 ;
        RECT  121.392 43.116 121.416 43.2 ;
    END
  END o_data[259]
  PIN o_data[25]
    DIRECTION OUTPUT ;
    USE SIGNAL ;
    PORT
      LAYER M5 ;
        RECT  86.544 43.116 86.568 43.2 ;
    END
  END o_data[25]
  PIN o_data[260]
    DIRECTION OUTPUT ;
    USE SIGNAL ;
    PORT
      LAYER M5 ;
        RECT  121.536 43.116 121.56 43.2 ;
    END
  END o_data[260]
  PIN o_data[261]
    DIRECTION OUTPUT ;
    USE SIGNAL ;
    PORT
      LAYER M5 ;
        RECT  121.68 43.116 121.704 43.2 ;
    END
  END o_data[261]
  PIN o_data[262]
    DIRECTION OUTPUT ;
    USE SIGNAL ;
    PORT
      LAYER M5 ;
        RECT  121.824 43.116 121.848 43.2 ;
    END
  END o_data[262]
  PIN o_data[263]
    DIRECTION OUTPUT ;
    USE SIGNAL ;
    PORT
      LAYER M5 ;
        RECT  121.968 43.116 121.992 43.2 ;
    END
  END o_data[263]
  PIN o_data[264]
    DIRECTION OUTPUT ;
    USE SIGNAL ;
    PORT
      LAYER M5 ;
        RECT  122.112 43.116 122.136 43.2 ;
    END
  END o_data[264]
  PIN o_data[265]
    DIRECTION OUTPUT ;
    USE SIGNAL ;
    PORT
      LAYER M5 ;
        RECT  122.256 43.116 122.28 43.2 ;
    END
  END o_data[265]
  PIN o_data[266]
    DIRECTION OUTPUT ;
    USE SIGNAL ;
    PORT
      LAYER M5 ;
        RECT  122.4 43.116 122.424 43.2 ;
    END
  END o_data[266]
  PIN o_data[267]
    DIRECTION OUTPUT ;
    USE SIGNAL ;
    PORT
      LAYER M5 ;
        RECT  122.544 43.116 122.568 43.2 ;
    END
  END o_data[267]
  PIN o_data[268]
    DIRECTION OUTPUT ;
    USE SIGNAL ;
    PORT
      LAYER M5 ;
        RECT  122.688 43.116 122.712 43.2 ;
    END
  END o_data[268]
  PIN o_data[269]
    DIRECTION OUTPUT ;
    USE SIGNAL ;
    PORT
      LAYER M5 ;
        RECT  122.832 43.116 122.856 43.2 ;
    END
  END o_data[269]
  PIN o_data[26]
    DIRECTION OUTPUT ;
    USE SIGNAL ;
    PORT
      LAYER M5 ;
        RECT  86.688 43.116 86.712 43.2 ;
    END
  END o_data[26]
  PIN o_data[270]
    DIRECTION OUTPUT ;
    USE SIGNAL ;
    PORT
      LAYER M5 ;
        RECT  122.976 43.116 123 43.2 ;
    END
  END o_data[270]
  PIN o_data[271]
    DIRECTION OUTPUT ;
    USE SIGNAL ;
    PORT
      LAYER M5 ;
        RECT  123.12 43.116 123.144 43.2 ;
    END
  END o_data[271]
  PIN o_data[272]
    DIRECTION OUTPUT ;
    USE SIGNAL ;
    PORT
      LAYER M5 ;
        RECT  123.264 43.116 123.288 43.2 ;
    END
  END o_data[272]
  PIN o_data[273]
    DIRECTION OUTPUT ;
    USE SIGNAL ;
    PORT
      LAYER M5 ;
        RECT  123.408 43.116 123.432 43.2 ;
    END
  END o_data[273]
  PIN o_data[274]
    DIRECTION OUTPUT ;
    USE SIGNAL ;
    PORT
      LAYER M5 ;
        RECT  123.552 43.116 123.576 43.2 ;
    END
  END o_data[274]
  PIN o_data[275]
    DIRECTION OUTPUT ;
    USE SIGNAL ;
    PORT
      LAYER M5 ;
        RECT  123.696 43.116 123.72 43.2 ;
    END
  END o_data[275]
  PIN o_data[276]
    DIRECTION OUTPUT ;
    USE SIGNAL ;
    PORT
      LAYER M5 ;
        RECT  123.84 43.116 123.864 43.2 ;
    END
  END o_data[276]
  PIN o_data[277]
    DIRECTION OUTPUT ;
    USE SIGNAL ;
    PORT
      LAYER M5 ;
        RECT  123.984 43.116 124.008 43.2 ;
    END
  END o_data[277]
  PIN o_data[278]
    DIRECTION OUTPUT ;
    USE SIGNAL ;
    PORT
      LAYER M5 ;
        RECT  124.128 43.116 124.152 43.2 ;
    END
  END o_data[278]
  PIN o_data[279]
    DIRECTION OUTPUT ;
    USE SIGNAL ;
    PORT
      LAYER M5 ;
        RECT  124.272 43.116 124.296 43.2 ;
    END
  END o_data[279]
  PIN o_data[27]
    DIRECTION OUTPUT ;
    USE SIGNAL ;
    PORT
      LAYER M5 ;
        RECT  86.832 43.116 86.856 43.2 ;
    END
  END o_data[27]
  PIN o_data[280]
    DIRECTION OUTPUT ;
    USE SIGNAL ;
    PORT
      LAYER M5 ;
        RECT  124.416 43.116 124.44 43.2 ;
    END
  END o_data[280]
  PIN o_data[281]
    DIRECTION OUTPUT ;
    USE SIGNAL ;
    PORT
      LAYER M5 ;
        RECT  124.56 43.116 124.584 43.2 ;
    END
  END o_data[281]
  PIN o_data[282]
    DIRECTION OUTPUT ;
    USE SIGNAL ;
    PORT
      LAYER M5 ;
        RECT  124.704 43.116 124.728 43.2 ;
    END
  END o_data[282]
  PIN o_data[283]
    DIRECTION OUTPUT ;
    USE SIGNAL ;
    PORT
      LAYER M5 ;
        RECT  124.848 43.116 124.872 43.2 ;
    END
  END o_data[283]
  PIN o_data[284]
    DIRECTION OUTPUT ;
    USE SIGNAL ;
    PORT
      LAYER M5 ;
        RECT  124.992 43.116 125.016 43.2 ;
    END
  END o_data[284]
  PIN o_data[285]
    DIRECTION OUTPUT ;
    USE SIGNAL ;
    PORT
      LAYER M5 ;
        RECT  125.136 43.116 125.16 43.2 ;
    END
  END o_data[285]
  PIN o_data[286]
    DIRECTION OUTPUT ;
    USE SIGNAL ;
    PORT
      LAYER M5 ;
        RECT  125.28 43.116 125.304 43.2 ;
    END
  END o_data[286]
  PIN o_data[287]
    DIRECTION OUTPUT ;
    USE SIGNAL ;
    PORT
      LAYER M5 ;
        RECT  125.424 43.116 125.448 43.2 ;
    END
  END o_data[287]
  PIN o_data[288]
    DIRECTION OUTPUT ;
    USE SIGNAL ;
    PORT
      LAYER M5 ;
        RECT  125.568 43.116 125.592 43.2 ;
    END
  END o_data[288]
  PIN o_data[289]
    DIRECTION OUTPUT ;
    USE SIGNAL ;
    PORT
      LAYER M5 ;
        RECT  125.712 43.116 125.736 43.2 ;
    END
  END o_data[289]
  PIN o_data[28]
    DIRECTION OUTPUT ;
    USE SIGNAL ;
    PORT
      LAYER M5 ;
        RECT  86.976 43.116 87 43.2 ;
    END
  END o_data[28]
  PIN o_data[290]
    DIRECTION OUTPUT ;
    USE SIGNAL ;
    PORT
      LAYER M5 ;
        RECT  125.856 43.116 125.88 43.2 ;
    END
  END o_data[290]
  PIN o_data[291]
    DIRECTION OUTPUT ;
    USE SIGNAL ;
    PORT
      LAYER M5 ;
        RECT  126 43.116 126.024 43.2 ;
    END
  END o_data[291]
  PIN o_data[292]
    DIRECTION OUTPUT ;
    USE SIGNAL ;
    PORT
      LAYER M5 ;
        RECT  126.144 43.116 126.168 43.2 ;
    END
  END o_data[292]
  PIN o_data[293]
    DIRECTION OUTPUT ;
    USE SIGNAL ;
    PORT
      LAYER M5 ;
        RECT  126.288 43.116 126.312 43.2 ;
    END
  END o_data[293]
  PIN o_data[294]
    DIRECTION OUTPUT ;
    USE SIGNAL ;
    PORT
      LAYER M5 ;
        RECT  126.432 43.116 126.456 43.2 ;
    END
  END o_data[294]
  PIN o_data[295]
    DIRECTION OUTPUT ;
    USE SIGNAL ;
    PORT
      LAYER M5 ;
        RECT  126.576 43.116 126.6 43.2 ;
    END
  END o_data[295]
  PIN o_data[296]
    DIRECTION OUTPUT ;
    USE SIGNAL ;
    PORT
      LAYER M5 ;
        RECT  126.72 43.116 126.744 43.2 ;
    END
  END o_data[296]
  PIN o_data[297]
    DIRECTION OUTPUT ;
    USE SIGNAL ;
    PORT
      LAYER M5 ;
        RECT  126.864 43.116 126.888 43.2 ;
    END
  END o_data[297]
  PIN o_data[298]
    DIRECTION OUTPUT ;
    USE SIGNAL ;
    PORT
      LAYER M5 ;
        RECT  127.008 43.116 127.032 43.2 ;
    END
  END o_data[298]
  PIN o_data[299]
    DIRECTION OUTPUT ;
    USE SIGNAL ;
    PORT
      LAYER M5 ;
        RECT  113.328 43.116 113.352 43.2 ;
    END
  END o_data[299]
  PIN o_data[29]
    DIRECTION OUTPUT ;
    USE SIGNAL ;
    PORT
      LAYER M5 ;
        RECT  87.12 43.116 87.144 43.2 ;
    END
  END o_data[29]
  PIN o_data[2]
    DIRECTION OUTPUT ;
    USE SIGNAL ;
    PORT
      LAYER M5 ;
        RECT  130.464 43.116 130.488 43.2 ;
    END
  END o_data[2]
  PIN o_data[300]
    DIRECTION OUTPUT ;
    USE SIGNAL ;
    PORT
      LAYER M5 ;
        RECT  113.472 43.116 113.496 43.2 ;
    END
  END o_data[300]
  PIN o_data[301]
    DIRECTION OUTPUT ;
    USE SIGNAL ;
    PORT
      LAYER M5 ;
        RECT  113.616 43.116 113.64 43.2 ;
    END
  END o_data[301]
  PIN o_data[302]
    DIRECTION OUTPUT ;
    USE SIGNAL ;
    PORT
      LAYER M5 ;
        RECT  113.76 43.116 113.784 43.2 ;
    END
  END o_data[302]
  PIN o_data[303]
    DIRECTION OUTPUT ;
    USE SIGNAL ;
    PORT
      LAYER M5 ;
        RECT  113.904 43.116 113.928 43.2 ;
    END
  END o_data[303]
  PIN o_data[304]
    DIRECTION OUTPUT ;
    USE SIGNAL ;
    PORT
      LAYER M5 ;
        RECT  114.048 43.116 114.072 43.2 ;
    END
  END o_data[304]
  PIN o_data[305]
    DIRECTION OUTPUT ;
    USE SIGNAL ;
    PORT
      LAYER M5 ;
        RECT  114.192 43.116 114.216 43.2 ;
    END
  END o_data[305]
  PIN o_data[306]
    DIRECTION OUTPUT ;
    USE SIGNAL ;
    PORT
      LAYER M5 ;
        RECT  114.336 43.116 114.36 43.2 ;
    END
  END o_data[306]
  PIN o_data[307]
    DIRECTION OUTPUT ;
    USE SIGNAL ;
    PORT
      LAYER M5 ;
        RECT  114.48 43.116 114.504 43.2 ;
    END
  END o_data[307]
  PIN o_data[308]
    DIRECTION OUTPUT ;
    USE SIGNAL ;
    PORT
      LAYER M5 ;
        RECT  114.624 43.116 114.648 43.2 ;
    END
  END o_data[308]
  PIN o_data[309]
    DIRECTION OUTPUT ;
    USE SIGNAL ;
    PORT
      LAYER M5 ;
        RECT  114.768 43.116 114.792 43.2 ;
    END
  END o_data[309]
  PIN o_data[30]
    DIRECTION OUTPUT ;
    USE SIGNAL ;
    PORT
      LAYER M5 ;
        RECT  87.264 43.116 87.288 43.2 ;
    END
  END o_data[30]
  PIN o_data[310]
    DIRECTION OUTPUT ;
    USE SIGNAL ;
    PORT
      LAYER M5 ;
        RECT  114.912 43.116 114.936 43.2 ;
    END
  END o_data[310]
  PIN o_data[311]
    DIRECTION OUTPUT ;
    USE SIGNAL ;
    PORT
      LAYER M5 ;
        RECT  115.056 43.116 115.08 43.2 ;
    END
  END o_data[311]
  PIN o_data[312]
    DIRECTION OUTPUT ;
    USE SIGNAL ;
    PORT
      LAYER M5 ;
        RECT  115.2 43.116 115.224 43.2 ;
    END
  END o_data[312]
  PIN o_data[313]
    DIRECTION OUTPUT ;
    USE SIGNAL ;
    PORT
      LAYER M5 ;
        RECT  115.344 43.116 115.368 43.2 ;
    END
  END o_data[313]
  PIN o_data[314]
    DIRECTION OUTPUT ;
    USE SIGNAL ;
    PORT
      LAYER M5 ;
        RECT  115.488 43.116 115.512 43.2 ;
    END
  END o_data[314]
  PIN o_data[315]
    DIRECTION OUTPUT ;
    USE SIGNAL ;
    PORT
      LAYER M5 ;
        RECT  115.632 43.116 115.656 43.2 ;
    END
  END o_data[315]
  PIN o_data[316]
    DIRECTION OUTPUT ;
    USE SIGNAL ;
    PORT
      LAYER M5 ;
        RECT  115.776 43.116 115.8 43.2 ;
    END
  END o_data[316]
  PIN o_data[317]
    DIRECTION OUTPUT ;
    USE SIGNAL ;
    PORT
      LAYER M5 ;
        RECT  115.92 43.116 115.944 43.2 ;
    END
  END o_data[317]
  PIN o_data[318]
    DIRECTION OUTPUT ;
    USE SIGNAL ;
    PORT
      LAYER M5 ;
        RECT  116.064 43.116 116.088 43.2 ;
    END
  END o_data[318]
  PIN o_data[319]
    DIRECTION OUTPUT ;
    USE SIGNAL ;
    PORT
      LAYER M5 ;
        RECT  116.208 43.116 116.232 43.2 ;
    END
  END o_data[319]
  PIN o_data[31]
    DIRECTION OUTPUT ;
    USE SIGNAL ;
    PORT
      LAYER M5 ;
        RECT  87.408 43.116 87.432 43.2 ;
    END
  END o_data[31]
  PIN o_data[320]
    DIRECTION OUTPUT ;
    USE SIGNAL ;
    PORT
      LAYER M5 ;
        RECT  116.352 43.116 116.376 43.2 ;
    END
  END o_data[320]
  PIN o_data[321]
    DIRECTION OUTPUT ;
    USE SIGNAL ;
    PORT
      LAYER M5 ;
        RECT  116.496 43.116 116.52 43.2 ;
    END
  END o_data[321]
  PIN o_data[322]
    DIRECTION OUTPUT ;
    USE SIGNAL ;
    PORT
      LAYER M5 ;
        RECT  116.64 43.116 116.664 43.2 ;
    END
  END o_data[322]
  PIN o_data[323]
    DIRECTION OUTPUT ;
    USE SIGNAL ;
    PORT
      LAYER M5 ;
        RECT  116.784 43.116 116.808 43.2 ;
    END
  END o_data[323]
  PIN o_data[324]
    DIRECTION OUTPUT ;
    USE SIGNAL ;
    PORT
      LAYER M5 ;
        RECT  116.928 43.116 116.952 43.2 ;
    END
  END o_data[324]
  PIN o_data[325]
    DIRECTION OUTPUT ;
    USE SIGNAL ;
    PORT
      LAYER M5 ;
        RECT  117.072 43.116 117.096 43.2 ;
    END
  END o_data[325]
  PIN o_data[326]
    DIRECTION OUTPUT ;
    USE SIGNAL ;
    PORT
      LAYER M5 ;
        RECT  117.216 43.116 117.24 43.2 ;
    END
  END o_data[326]
  PIN o_data[327]
    DIRECTION OUTPUT ;
    USE SIGNAL ;
    PORT
      LAYER M5 ;
        RECT  117.36 43.116 117.384 43.2 ;
    END
  END o_data[327]
  PIN o_data[328]
    DIRECTION OUTPUT ;
    USE SIGNAL ;
    PORT
      LAYER M5 ;
        RECT  117.504 43.116 117.528 43.2 ;
    END
  END o_data[328]
  PIN o_data[329]
    DIRECTION OUTPUT ;
    USE SIGNAL ;
    PORT
      LAYER M5 ;
        RECT  117.648 43.116 117.672 43.2 ;
    END
  END o_data[329]
  PIN o_data[32]
    DIRECTION OUTPUT ;
    USE SIGNAL ;
    PORT
      LAYER M5 ;
        RECT  87.552 43.116 87.576 43.2 ;
    END
  END o_data[32]
  PIN o_data[330]
    DIRECTION OUTPUT ;
    USE SIGNAL ;
    PORT
      LAYER M5 ;
        RECT  117.792 43.116 117.816 43.2 ;
    END
  END o_data[330]
  PIN o_data[331]
    DIRECTION OUTPUT ;
    USE SIGNAL ;
    PORT
      LAYER M5 ;
        RECT  108.72 43.116 108.744 43.2 ;
    END
  END o_data[331]
  PIN o_data[332]
    DIRECTION OUTPUT ;
    USE SIGNAL ;
    PORT
      LAYER M5 ;
        RECT  108.864 43.116 108.888 43.2 ;
    END
  END o_data[332]
  PIN o_data[333]
    DIRECTION OUTPUT ;
    USE SIGNAL ;
    PORT
      LAYER M5 ;
        RECT  109.008 43.116 109.032 43.2 ;
    END
  END o_data[333]
  PIN o_data[334]
    DIRECTION OUTPUT ;
    USE SIGNAL ;
    PORT
      LAYER M5 ;
        RECT  109.152 43.116 109.176 43.2 ;
    END
  END o_data[334]
  PIN o_data[335]
    DIRECTION OUTPUT ;
    USE SIGNAL ;
    PORT
      LAYER M5 ;
        RECT  109.296 43.116 109.32 43.2 ;
    END
  END o_data[335]
  PIN o_data[336]
    DIRECTION OUTPUT ;
    USE SIGNAL ;
    PORT
      LAYER M5 ;
        RECT  109.44 43.116 109.464 43.2 ;
    END
  END o_data[336]
  PIN o_data[337]
    DIRECTION OUTPUT ;
    USE SIGNAL ;
    PORT
      LAYER M5 ;
        RECT  109.584 43.116 109.608 43.2 ;
    END
  END o_data[337]
  PIN o_data[338]
    DIRECTION OUTPUT ;
    USE SIGNAL ;
    PORT
      LAYER M5 ;
        RECT  109.728 43.116 109.752 43.2 ;
    END
  END o_data[338]
  PIN o_data[339]
    DIRECTION OUTPUT ;
    USE SIGNAL ;
    PORT
      LAYER M5 ;
        RECT  109.872 43.116 109.896 43.2 ;
    END
  END o_data[339]
  PIN o_data[33]
    DIRECTION OUTPUT ;
    USE SIGNAL ;
    PORT
      LAYER M5 ;
        RECT  87.696 43.116 87.72 43.2 ;
    END
  END o_data[33]
  PIN o_data[340]
    DIRECTION OUTPUT ;
    USE SIGNAL ;
    PORT
      LAYER M5 ;
        RECT  110.016 43.116 110.04 43.2 ;
    END
  END o_data[340]
  PIN o_data[341]
    DIRECTION OUTPUT ;
    USE SIGNAL ;
    PORT
      LAYER M5 ;
        RECT  110.16 43.116 110.184 43.2 ;
    END
  END o_data[341]
  PIN o_data[342]
    DIRECTION OUTPUT ;
    USE SIGNAL ;
    PORT
      LAYER M5 ;
        RECT  110.304 43.116 110.328 43.2 ;
    END
  END o_data[342]
  PIN o_data[343]
    DIRECTION OUTPUT ;
    USE SIGNAL ;
    PORT
      LAYER M5 ;
        RECT  110.448 43.116 110.472 43.2 ;
    END
  END o_data[343]
  PIN o_data[344]
    DIRECTION OUTPUT ;
    USE SIGNAL ;
    PORT
      LAYER M5 ;
        RECT  110.592 43.116 110.616 43.2 ;
    END
  END o_data[344]
  PIN o_data[345]
    DIRECTION OUTPUT ;
    USE SIGNAL ;
    PORT
      LAYER M5 ;
        RECT  110.736 43.116 110.76 43.2 ;
    END
  END o_data[345]
  PIN o_data[346]
    DIRECTION OUTPUT ;
    USE SIGNAL ;
    PORT
      LAYER M5 ;
        RECT  110.88 43.116 110.904 43.2 ;
    END
  END o_data[346]
  PIN o_data[347]
    DIRECTION OUTPUT ;
    USE SIGNAL ;
    PORT
      LAYER M5 ;
        RECT  111.024 43.116 111.048 43.2 ;
    END
  END o_data[347]
  PIN o_data[348]
    DIRECTION OUTPUT ;
    USE SIGNAL ;
    PORT
      LAYER M5 ;
        RECT  111.168 43.116 111.192 43.2 ;
    END
  END o_data[348]
  PIN o_data[349]
    DIRECTION OUTPUT ;
    USE SIGNAL ;
    PORT
      LAYER M5 ;
        RECT  111.312 43.116 111.336 43.2 ;
    END
  END o_data[349]
  PIN o_data[34]
    DIRECTION OUTPUT ;
    USE SIGNAL ;
    PORT
      LAYER M5 ;
        RECT  87.84 43.116 87.864 43.2 ;
    END
  END o_data[34]
  PIN o_data[350]
    DIRECTION OUTPUT ;
    USE SIGNAL ;
    PORT
      LAYER M5 ;
        RECT  111.456 43.116 111.48 43.2 ;
    END
  END o_data[350]
  PIN o_data[351]
    DIRECTION OUTPUT ;
    USE SIGNAL ;
    PORT
      LAYER M5 ;
        RECT  111.6 43.116 111.624 43.2 ;
    END
  END o_data[351]
  PIN o_data[352]
    DIRECTION OUTPUT ;
    USE SIGNAL ;
    PORT
      LAYER M5 ;
        RECT  111.744 43.116 111.768 43.2 ;
    END
  END o_data[352]
  PIN o_data[353]
    DIRECTION OUTPUT ;
    USE SIGNAL ;
    PORT
      LAYER M5 ;
        RECT  111.888 43.116 111.912 43.2 ;
    END
  END o_data[353]
  PIN o_data[354]
    DIRECTION OUTPUT ;
    USE SIGNAL ;
    PORT
      LAYER M5 ;
        RECT  112.032 43.116 112.056 43.2 ;
    END
  END o_data[354]
  PIN o_data[355]
    DIRECTION OUTPUT ;
    USE SIGNAL ;
    PORT
      LAYER M5 ;
        RECT  112.176 43.116 112.2 43.2 ;
    END
  END o_data[355]
  PIN o_data[356]
    DIRECTION OUTPUT ;
    USE SIGNAL ;
    PORT
      LAYER M5 ;
        RECT  112.32 43.116 112.344 43.2 ;
    END
  END o_data[356]
  PIN o_data[357]
    DIRECTION OUTPUT ;
    USE SIGNAL ;
    PORT
      LAYER M5 ;
        RECT  112.464 43.116 112.488 43.2 ;
    END
  END o_data[357]
  PIN o_data[358]
    DIRECTION OUTPUT ;
    USE SIGNAL ;
    PORT
      LAYER M5 ;
        RECT  112.608 43.116 112.632 43.2 ;
    END
  END o_data[358]
  PIN o_data[359]
    DIRECTION OUTPUT ;
    USE SIGNAL ;
    PORT
      LAYER M5 ;
        RECT  112.752 43.116 112.776 43.2 ;
    END
  END o_data[359]
  PIN o_data[35]
    DIRECTION OUTPUT ;
    USE SIGNAL ;
    PORT
      LAYER M5 ;
        RECT  87.984 43.116 88.008 43.2 ;
    END
  END o_data[35]
  PIN o_data[360]
    DIRECTION OUTPUT ;
    USE SIGNAL ;
    PORT
      LAYER M5 ;
        RECT  112.896 43.116 112.92 43.2 ;
    END
  END o_data[360]
  PIN o_data[361]
    DIRECTION OUTPUT ;
    USE SIGNAL ;
    PORT
      LAYER M5 ;
        RECT  113.04 43.116 113.064 43.2 ;
    END
  END o_data[361]
  PIN o_data[362]
    DIRECTION OUTPUT ;
    USE SIGNAL ;
    PORT
      LAYER M5 ;
        RECT  113.184 43.116 113.208 43.2 ;
    END
  END o_data[362]
  PIN o_data[363]
    DIRECTION OUTPUT ;
    USE SIGNAL ;
    PORT
      LAYER M5 ;
        RECT  132.912 43.116 132.936 43.2 ;
    END
  END o_data[363]
  PIN o_data[364]
    DIRECTION OUTPUT ;
    USE SIGNAL ;
    PORT
      LAYER M5 ;
        RECT  133.056 43.116 133.08 43.2 ;
    END
  END o_data[364]
  PIN o_data[365]
    DIRECTION OUTPUT ;
    USE SIGNAL ;
    PORT
      LAYER M5 ;
        RECT  133.2 43.116 133.224 43.2 ;
    END
  END o_data[365]
  PIN o_data[366]
    DIRECTION OUTPUT ;
    USE SIGNAL ;
    PORT
      LAYER M5 ;
        RECT  133.344 43.116 133.368 43.2 ;
    END
  END o_data[366]
  PIN o_data[367]
    DIRECTION OUTPUT ;
    USE SIGNAL ;
    PORT
      LAYER M5 ;
        RECT  133.488 43.116 133.512 43.2 ;
    END
  END o_data[367]
  PIN o_data[368]
    DIRECTION OUTPUT ;
    USE SIGNAL ;
    PORT
      LAYER M5 ;
        RECT  133.632 43.116 133.656 43.2 ;
    END
  END o_data[368]
  PIN o_data[369]
    DIRECTION OUTPUT ;
    USE SIGNAL ;
    PORT
      LAYER M5 ;
        RECT  133.776 43.116 133.8 43.2 ;
    END
  END o_data[369]
  PIN o_data[36]
    DIRECTION OUTPUT ;
    USE SIGNAL ;
    PORT
      LAYER M5 ;
        RECT  88.128 43.116 88.152 43.2 ;
    END
  END o_data[36]
  PIN o_data[370]
    DIRECTION OUTPUT ;
    USE SIGNAL ;
    PORT
      LAYER M5 ;
        RECT  133.92 43.116 133.944 43.2 ;
    END
  END o_data[370]
  PIN o_data[371]
    DIRECTION OUTPUT ;
    USE SIGNAL ;
    PORT
      LAYER M5 ;
        RECT  134.064 43.116 134.088 43.2 ;
    END
  END o_data[371]
  PIN o_data[372]
    DIRECTION OUTPUT ;
    USE SIGNAL ;
    PORT
      LAYER M5 ;
        RECT  134.208 43.116 134.232 43.2 ;
    END
  END o_data[372]
  PIN o_data[373]
    DIRECTION OUTPUT ;
    USE SIGNAL ;
    PORT
      LAYER M5 ;
        RECT  134.352 43.116 134.376 43.2 ;
    END
  END o_data[373]
  PIN o_data[374]
    DIRECTION OUTPUT ;
    USE SIGNAL ;
    PORT
      LAYER M5 ;
        RECT  134.496 43.116 134.52 43.2 ;
    END
  END o_data[374]
  PIN o_data[375]
    DIRECTION OUTPUT ;
    USE SIGNAL ;
    PORT
      LAYER M5 ;
        RECT  134.64 43.116 134.664 43.2 ;
    END
  END o_data[375]
  PIN o_data[376]
    DIRECTION OUTPUT ;
    USE SIGNAL ;
    PORT
      LAYER M5 ;
        RECT  134.784 43.116 134.808 43.2 ;
    END
  END o_data[376]
  PIN o_data[377]
    DIRECTION OUTPUT ;
    USE SIGNAL ;
    PORT
      LAYER M5 ;
        RECT  134.928 43.116 134.952 43.2 ;
    END
  END o_data[377]
  PIN o_data[378]
    DIRECTION OUTPUT ;
    USE SIGNAL ;
    PORT
      LAYER M5 ;
        RECT  135.072 43.116 135.096 43.2 ;
    END
  END o_data[378]
  PIN o_data[379]
    DIRECTION OUTPUT ;
    USE SIGNAL ;
    PORT
      LAYER M5 ;
        RECT  135.216 43.116 135.24 43.2 ;
    END
  END o_data[379]
  PIN o_data[37]
    DIRECTION OUTPUT ;
    USE SIGNAL ;
    PORT
      LAYER M5 ;
        RECT  88.272 43.116 88.296 43.2 ;
    END
  END o_data[37]
  PIN o_data[380]
    DIRECTION OUTPUT ;
    USE SIGNAL ;
    PORT
      LAYER M5 ;
        RECT  135.36 43.116 135.384 43.2 ;
    END
  END o_data[380]
  PIN o_data[381]
    DIRECTION OUTPUT ;
    USE SIGNAL ;
    PORT
      LAYER M5 ;
        RECT  135.504 43.116 135.528 43.2 ;
    END
  END o_data[381]
  PIN o_data[382]
    DIRECTION OUTPUT ;
    USE SIGNAL ;
    PORT
      LAYER M5 ;
        RECT  135.648 43.116 135.672 43.2 ;
    END
  END o_data[382]
  PIN o_data[383]
    DIRECTION OUTPUT ;
    USE SIGNAL ;
    PORT
      LAYER M5 ;
        RECT  135.792 43.116 135.816 43.2 ;
    END
  END o_data[383]
  PIN o_data[384]
    DIRECTION OUTPUT ;
    USE SIGNAL ;
    PORT
      LAYER M5 ;
        RECT  135.936 43.116 135.96 43.2 ;
    END
  END o_data[384]
  PIN o_data[385]
    DIRECTION OUTPUT ;
    USE SIGNAL ;
    PORT
      LAYER M5 ;
        RECT  136.08 43.116 136.104 43.2 ;
    END
  END o_data[385]
  PIN o_data[386]
    DIRECTION OUTPUT ;
    USE SIGNAL ;
    PORT
      LAYER M5 ;
        RECT  136.224 43.116 136.248 43.2 ;
    END
  END o_data[386]
  PIN o_data[387]
    DIRECTION OUTPUT ;
    USE SIGNAL ;
    PORT
      LAYER M5 ;
        RECT  136.368 43.116 136.392 43.2 ;
    END
  END o_data[387]
  PIN o_data[388]
    DIRECTION OUTPUT ;
    USE SIGNAL ;
    PORT
      LAYER M5 ;
        RECT  136.512 43.116 136.536 43.2 ;
    END
  END o_data[388]
  PIN o_data[389]
    DIRECTION OUTPUT ;
    USE SIGNAL ;
    PORT
      LAYER M5 ;
        RECT  136.656 43.116 136.68 43.2 ;
    END
  END o_data[389]
  PIN o_data[38]
    DIRECTION OUTPUT ;
    USE SIGNAL ;
    PORT
      LAYER M5 ;
        RECT  88.416 43.116 88.44 43.2 ;
    END
  END o_data[38]
  PIN o_data[390]
    DIRECTION OUTPUT ;
    USE SIGNAL ;
    PORT
      LAYER M5 ;
        RECT  136.8 43.116 136.824 43.2 ;
    END
  END o_data[390]
  PIN o_data[391]
    DIRECTION OUTPUT ;
    USE SIGNAL ;
    PORT
      LAYER M5 ;
        RECT  136.944 43.116 136.968 43.2 ;
    END
  END o_data[391]
  PIN o_data[392]
    DIRECTION OUTPUT ;
    USE SIGNAL ;
    PORT
      LAYER M5 ;
        RECT  137.088 43.116 137.112 43.2 ;
    END
  END o_data[392]
  PIN o_data[393]
    DIRECTION OUTPUT ;
    USE SIGNAL ;
    PORT
      LAYER M5 ;
        RECT  137.232 43.116 137.256 43.2 ;
    END
  END o_data[393]
  PIN o_data[394]
    DIRECTION OUTPUT ;
    USE SIGNAL ;
    PORT
      LAYER M5 ;
        RECT  137.376 43.116 137.4 43.2 ;
    END
  END o_data[394]
  PIN o_data[395]
    DIRECTION OUTPUT ;
    USE SIGNAL ;
    PORT
      LAYER M5 ;
        RECT  64.944 43.116 64.968 43.2 ;
    END
  END o_data[395]
  PIN o_data[396]
    DIRECTION OUTPUT ;
    USE SIGNAL ;
    PORT
      LAYER M5 ;
        RECT  65.088 43.116 65.112 43.2 ;
    END
  END o_data[396]
  PIN o_data[397]
    DIRECTION OUTPUT ;
    USE SIGNAL ;
    PORT
      LAYER M5 ;
        RECT  65.232 43.116 65.256 43.2 ;
    END
  END o_data[397]
  PIN o_data[398]
    DIRECTION OUTPUT ;
    USE SIGNAL ;
    PORT
      LAYER M5 ;
        RECT  65.376 43.116 65.4 43.2 ;
    END
  END o_data[398]
  PIN o_data[399]
    DIRECTION OUTPUT ;
    USE SIGNAL ;
    PORT
      LAYER M5 ;
        RECT  65.52 43.116 65.544 43.2 ;
    END
  END o_data[399]
  PIN o_data[39]
    DIRECTION OUTPUT ;
    USE SIGNAL ;
    PORT
      LAYER M5 ;
        RECT  88.56 43.116 88.584 43.2 ;
    END
  END o_data[39]
  PIN o_data[3]
    DIRECTION OUTPUT ;
    USE SIGNAL ;
    PORT
      LAYER M5 ;
        RECT  130.608 43.116 130.632 43.2 ;
    END
  END o_data[3]
  PIN o_data[400]
    DIRECTION OUTPUT ;
    USE SIGNAL ;
    PORT
      LAYER M5 ;
        RECT  65.664 43.116 65.688 43.2 ;
    END
  END o_data[400]
  PIN o_data[401]
    DIRECTION OUTPUT ;
    USE SIGNAL ;
    PORT
      LAYER M5 ;
        RECT  65.808 43.116 65.832 43.2 ;
    END
  END o_data[401]
  PIN o_data[402]
    DIRECTION OUTPUT ;
    USE SIGNAL ;
    PORT
      LAYER M5 ;
        RECT  65.952 43.116 65.976 43.2 ;
    END
  END o_data[402]
  PIN o_data[403]
    DIRECTION OUTPUT ;
    USE SIGNAL ;
    PORT
      LAYER M5 ;
        RECT  66.096 43.116 66.12 43.2 ;
    END
  END o_data[403]
  PIN o_data[404]
    DIRECTION OUTPUT ;
    USE SIGNAL ;
    PORT
      LAYER M5 ;
        RECT  66.24 43.116 66.264 43.2 ;
    END
  END o_data[404]
  PIN o_data[405]
    DIRECTION OUTPUT ;
    USE SIGNAL ;
    PORT
      LAYER M5 ;
        RECT  66.384 43.116 66.408 43.2 ;
    END
  END o_data[405]
  PIN o_data[406]
    DIRECTION OUTPUT ;
    USE SIGNAL ;
    PORT
      LAYER M5 ;
        RECT  66.528 43.116 66.552 43.2 ;
    END
  END o_data[406]
  PIN o_data[407]
    DIRECTION OUTPUT ;
    USE SIGNAL ;
    PORT
      LAYER M5 ;
        RECT  66.672 43.116 66.696 43.2 ;
    END
  END o_data[407]
  PIN o_data[408]
    DIRECTION OUTPUT ;
    USE SIGNAL ;
    PORT
      LAYER M5 ;
        RECT  66.816 43.116 66.84 43.2 ;
    END
  END o_data[408]
  PIN o_data[409]
    DIRECTION OUTPUT ;
    USE SIGNAL ;
    PORT
      LAYER M5 ;
        RECT  66.96 43.116 66.984 43.2 ;
    END
  END o_data[409]
  PIN o_data[40]
    DIRECTION OUTPUT ;
    USE SIGNAL ;
    PORT
      LAYER M5 ;
        RECT  88.704 43.116 88.728 43.2 ;
    END
  END o_data[40]
  PIN o_data[410]
    DIRECTION OUTPUT ;
    USE SIGNAL ;
    PORT
      LAYER M5 ;
        RECT  67.104 43.116 67.128 43.2 ;
    END
  END o_data[410]
  PIN o_data[411]
    DIRECTION OUTPUT ;
    USE SIGNAL ;
    PORT
      LAYER M5 ;
        RECT  67.248 43.116 67.272 43.2 ;
    END
  END o_data[411]
  PIN o_data[412]
    DIRECTION OUTPUT ;
    USE SIGNAL ;
    PORT
      LAYER M5 ;
        RECT  67.392 43.116 67.416 43.2 ;
    END
  END o_data[412]
  PIN o_data[413]
    DIRECTION OUTPUT ;
    USE SIGNAL ;
    PORT
      LAYER M5 ;
        RECT  67.536 43.116 67.56 43.2 ;
    END
  END o_data[413]
  PIN o_data[414]
    DIRECTION OUTPUT ;
    USE SIGNAL ;
    PORT
      LAYER M5 ;
        RECT  67.68 43.116 67.704 43.2 ;
    END
  END o_data[414]
  PIN o_data[415]
    DIRECTION OUTPUT ;
    USE SIGNAL ;
    PORT
      LAYER M5 ;
        RECT  67.824 43.116 67.848 43.2 ;
    END
  END o_data[415]
  PIN o_data[416]
    DIRECTION OUTPUT ;
    USE SIGNAL ;
    PORT
      LAYER M5 ;
        RECT  67.968 43.116 67.992 43.2 ;
    END
  END o_data[416]
  PIN o_data[417]
    DIRECTION OUTPUT ;
    USE SIGNAL ;
    PORT
      LAYER M5 ;
        RECT  68.112 43.116 68.136 43.2 ;
    END
  END o_data[417]
  PIN o_data[418]
    DIRECTION OUTPUT ;
    USE SIGNAL ;
    PORT
      LAYER M5 ;
        RECT  68.256 43.116 68.28 43.2 ;
    END
  END o_data[418]
  PIN o_data[419]
    DIRECTION OUTPUT ;
    USE SIGNAL ;
    PORT
      LAYER M5 ;
        RECT  68.4 43.116 68.424 43.2 ;
    END
  END o_data[419]
  PIN o_data[41]
    DIRECTION OUTPUT ;
    USE SIGNAL ;
    PORT
      LAYER M5 ;
        RECT  88.848 43.116 88.872 43.2 ;
    END
  END o_data[41]
  PIN o_data[420]
    DIRECTION OUTPUT ;
    USE SIGNAL ;
    PORT
      LAYER M5 ;
        RECT  68.544 43.116 68.568 43.2 ;
    END
  END o_data[420]
  PIN o_data[421]
    DIRECTION OUTPUT ;
    USE SIGNAL ;
    PORT
      LAYER M5 ;
        RECT  68.688 43.116 68.712 43.2 ;
    END
  END o_data[421]
  PIN o_data[422]
    DIRECTION OUTPUT ;
    USE SIGNAL ;
    PORT
      LAYER M5 ;
        RECT  68.832 43.116 68.856 43.2 ;
    END
  END o_data[422]
  PIN o_data[423]
    DIRECTION OUTPUT ;
    USE SIGNAL ;
    PORT
      LAYER M5 ;
        RECT  68.976 43.116 69 43.2 ;
    END
  END o_data[423]
  PIN o_data[424]
    DIRECTION OUTPUT ;
    USE SIGNAL ;
    PORT
      LAYER M5 ;
        RECT  69.12 43.116 69.144 43.2 ;
    END
  END o_data[424]
  PIN o_data[425]
    DIRECTION OUTPUT ;
    USE SIGNAL ;
    PORT
      LAYER M5 ;
        RECT  69.264 43.116 69.288 43.2 ;
    END
  END o_data[425]
  PIN o_data[426]
    DIRECTION OUTPUT ;
    USE SIGNAL ;
    PORT
      LAYER M5 ;
        RECT  69.408 43.116 69.432 43.2 ;
    END
  END o_data[426]
  PIN o_data[427]
    DIRECTION OUTPUT ;
    USE SIGNAL ;
    PORT
      LAYER M5 ;
        RECT  55.728 43.116 55.752 43.2 ;
    END
  END o_data[427]
  PIN o_data[428]
    DIRECTION OUTPUT ;
    USE SIGNAL ;
    PORT
      LAYER M5 ;
        RECT  55.872 43.116 55.896 43.2 ;
    END
  END o_data[428]
  PIN o_data[429]
    DIRECTION OUTPUT ;
    USE SIGNAL ;
    PORT
      LAYER M5 ;
        RECT  56.016 43.116 56.04 43.2 ;
    END
  END o_data[429]
  PIN o_data[42]
    DIRECTION OUTPUT ;
    USE SIGNAL ;
    PORT
      LAYER M5 ;
        RECT  88.992 43.116 89.016 43.2 ;
    END
  END o_data[42]
  PIN o_data[430]
    DIRECTION OUTPUT ;
    USE SIGNAL ;
    PORT
      LAYER M5 ;
        RECT  56.16 43.116 56.184 43.2 ;
    END
  END o_data[430]
  PIN o_data[431]
    DIRECTION OUTPUT ;
    USE SIGNAL ;
    PORT
      LAYER M5 ;
        RECT  56.304 43.116 56.328 43.2 ;
    END
  END o_data[431]
  PIN o_data[432]
    DIRECTION OUTPUT ;
    USE SIGNAL ;
    PORT
      LAYER M5 ;
        RECT  56.448 43.116 56.472 43.2 ;
    END
  END o_data[432]
  PIN o_data[433]
    DIRECTION OUTPUT ;
    USE SIGNAL ;
    PORT
      LAYER M5 ;
        RECT  56.592 43.116 56.616 43.2 ;
    END
  END o_data[433]
  PIN o_data[434]
    DIRECTION OUTPUT ;
    USE SIGNAL ;
    PORT
      LAYER M5 ;
        RECT  56.736 43.116 56.76 43.2 ;
    END
  END o_data[434]
  PIN o_data[435]
    DIRECTION OUTPUT ;
    USE SIGNAL ;
    PORT
      LAYER M5 ;
        RECT  56.88 43.116 56.904 43.2 ;
    END
  END o_data[435]
  PIN o_data[436]
    DIRECTION OUTPUT ;
    USE SIGNAL ;
    PORT
      LAYER M5 ;
        RECT  57.024 43.116 57.048 43.2 ;
    END
  END o_data[436]
  PIN o_data[437]
    DIRECTION OUTPUT ;
    USE SIGNAL ;
    PORT
      LAYER M5 ;
        RECT  57.168 43.116 57.192 43.2 ;
    END
  END o_data[437]
  PIN o_data[438]
    DIRECTION OUTPUT ;
    USE SIGNAL ;
    PORT
      LAYER M5 ;
        RECT  57.312 43.116 57.336 43.2 ;
    END
  END o_data[438]
  PIN o_data[439]
    DIRECTION OUTPUT ;
    USE SIGNAL ;
    PORT
      LAYER M5 ;
        RECT  57.456 43.116 57.48 43.2 ;
    END
  END o_data[439]
  PIN o_data[43]
    DIRECTION OUTPUT ;
    USE SIGNAL ;
    PORT
      LAYER M5 ;
        RECT  75.312 43.116 75.336 43.2 ;
    END
  END o_data[43]
  PIN o_data[440]
    DIRECTION OUTPUT ;
    USE SIGNAL ;
    PORT
      LAYER M5 ;
        RECT  57.6 43.116 57.624 43.2 ;
    END
  END o_data[440]
  PIN o_data[441]
    DIRECTION OUTPUT ;
    USE SIGNAL ;
    PORT
      LAYER M5 ;
        RECT  57.744 43.116 57.768 43.2 ;
    END
  END o_data[441]
  PIN o_data[442]
    DIRECTION OUTPUT ;
    USE SIGNAL ;
    PORT
      LAYER M5 ;
        RECT  57.888 43.116 57.912 43.2 ;
    END
  END o_data[442]
  PIN o_data[443]
    DIRECTION OUTPUT ;
    USE SIGNAL ;
    PORT
      LAYER M5 ;
        RECT  58.032 43.116 58.056 43.2 ;
    END
  END o_data[443]
  PIN o_data[444]
    DIRECTION OUTPUT ;
    USE SIGNAL ;
    PORT
      LAYER M5 ;
        RECT  58.176 43.116 58.2 43.2 ;
    END
  END o_data[444]
  PIN o_data[445]
    DIRECTION OUTPUT ;
    USE SIGNAL ;
    PORT
      LAYER M5 ;
        RECT  58.32 43.116 58.344 43.2 ;
    END
  END o_data[445]
  PIN o_data[446]
    DIRECTION OUTPUT ;
    USE SIGNAL ;
    PORT
      LAYER M5 ;
        RECT  58.464 43.116 58.488 43.2 ;
    END
  END o_data[446]
  PIN o_data[447]
    DIRECTION OUTPUT ;
    USE SIGNAL ;
    PORT
      LAYER M5 ;
        RECT  58.608 43.116 58.632 43.2 ;
    END
  END o_data[447]
  PIN o_data[448]
    DIRECTION OUTPUT ;
    USE SIGNAL ;
    PORT
      LAYER M5 ;
        RECT  58.752 43.116 58.776 43.2 ;
    END
  END o_data[448]
  PIN o_data[449]
    DIRECTION OUTPUT ;
    USE SIGNAL ;
    PORT
      LAYER M5 ;
        RECT  58.896 43.116 58.92 43.2 ;
    END
  END o_data[449]
  PIN o_data[44]
    DIRECTION OUTPUT ;
    USE SIGNAL ;
    PORT
      LAYER M5 ;
        RECT  75.456 43.116 75.48 43.2 ;
    END
  END o_data[44]
  PIN o_data[450]
    DIRECTION OUTPUT ;
    USE SIGNAL ;
    PORT
      LAYER M5 ;
        RECT  59.04 43.116 59.064 43.2 ;
    END
  END o_data[450]
  PIN o_data[451]
    DIRECTION OUTPUT ;
    USE SIGNAL ;
    PORT
      LAYER M5 ;
        RECT  59.184 43.116 59.208 43.2 ;
    END
  END o_data[451]
  PIN o_data[452]
    DIRECTION OUTPUT ;
    USE SIGNAL ;
    PORT
      LAYER M5 ;
        RECT  59.328 43.116 59.352 43.2 ;
    END
  END o_data[452]
  PIN o_data[453]
    DIRECTION OUTPUT ;
    USE SIGNAL ;
    PORT
      LAYER M5 ;
        RECT  59.472 43.116 59.496 43.2 ;
    END
  END o_data[453]
  PIN o_data[454]
    DIRECTION OUTPUT ;
    USE SIGNAL ;
    PORT
      LAYER M5 ;
        RECT  59.616 43.116 59.64 43.2 ;
    END
  END o_data[454]
  PIN o_data[455]
    DIRECTION OUTPUT ;
    USE SIGNAL ;
    PORT
      LAYER M5 ;
        RECT  59.76 43.116 59.784 43.2 ;
    END
  END o_data[455]
  PIN o_data[456]
    DIRECTION OUTPUT ;
    USE SIGNAL ;
    PORT
      LAYER M5 ;
        RECT  59.904 43.116 59.928 43.2 ;
    END
  END o_data[456]
  PIN o_data[457]
    DIRECTION OUTPUT ;
    USE SIGNAL ;
    PORT
      LAYER M5 ;
        RECT  60.048 43.116 60.072 43.2 ;
    END
  END o_data[457]
  PIN o_data[458]
    DIRECTION OUTPUT ;
    USE SIGNAL ;
    PORT
      LAYER M5 ;
        RECT  60.192 43.116 60.216 43.2 ;
    END
  END o_data[458]
  PIN o_data[459]
    DIRECTION OUTPUT ;
    USE SIGNAL ;
    PORT
      LAYER M5 ;
        RECT  69.552 43.116 69.576 43.2 ;
    END
  END o_data[459]
  PIN o_data[45]
    DIRECTION OUTPUT ;
    USE SIGNAL ;
    PORT
      LAYER M5 ;
        RECT  75.6 43.116 75.624 43.2 ;
    END
  END o_data[45]
  PIN o_data[460]
    DIRECTION OUTPUT ;
    USE SIGNAL ;
    PORT
      LAYER M5 ;
        RECT  69.696 43.116 69.72 43.2 ;
    END
  END o_data[460]
  PIN o_data[461]
    DIRECTION OUTPUT ;
    USE SIGNAL ;
    PORT
      LAYER M5 ;
        RECT  69.84 43.116 69.864 43.2 ;
    END
  END o_data[461]
  PIN o_data[462]
    DIRECTION OUTPUT ;
    USE SIGNAL ;
    PORT
      LAYER M5 ;
        RECT  69.984 43.116 70.008 43.2 ;
    END
  END o_data[462]
  PIN o_data[463]
    DIRECTION OUTPUT ;
    USE SIGNAL ;
    PORT
      LAYER M5 ;
        RECT  70.128 43.116 70.152 43.2 ;
    END
  END o_data[463]
  PIN o_data[464]
    DIRECTION OUTPUT ;
    USE SIGNAL ;
    PORT
      LAYER M5 ;
        RECT  70.272 43.116 70.296 43.2 ;
    END
  END o_data[464]
  PIN o_data[465]
    DIRECTION OUTPUT ;
    USE SIGNAL ;
    PORT
      LAYER M5 ;
        RECT  70.416 43.116 70.44 43.2 ;
    END
  END o_data[465]
  PIN o_data[466]
    DIRECTION OUTPUT ;
    USE SIGNAL ;
    PORT
      LAYER M5 ;
        RECT  70.56 43.116 70.584 43.2 ;
    END
  END o_data[466]
  PIN o_data[467]
    DIRECTION OUTPUT ;
    USE SIGNAL ;
    PORT
      LAYER M5 ;
        RECT  70.704 43.116 70.728 43.2 ;
    END
  END o_data[467]
  PIN o_data[468]
    DIRECTION OUTPUT ;
    USE SIGNAL ;
    PORT
      LAYER M5 ;
        RECT  70.848 43.116 70.872 43.2 ;
    END
  END o_data[468]
  PIN o_data[469]
    DIRECTION OUTPUT ;
    USE SIGNAL ;
    PORT
      LAYER M5 ;
        RECT  70.992 43.116 71.016 43.2 ;
    END
  END o_data[469]
  PIN o_data[46]
    DIRECTION OUTPUT ;
    USE SIGNAL ;
    PORT
      LAYER M5 ;
        RECT  75.744 43.116 75.768 43.2 ;
    END
  END o_data[46]
  PIN o_data[470]
    DIRECTION OUTPUT ;
    USE SIGNAL ;
    PORT
      LAYER M5 ;
        RECT  71.136 43.116 71.16 43.2 ;
    END
  END o_data[470]
  PIN o_data[471]
    DIRECTION OUTPUT ;
    USE SIGNAL ;
    PORT
      LAYER M5 ;
        RECT  71.28 43.116 71.304 43.2 ;
    END
  END o_data[471]
  PIN o_data[472]
    DIRECTION OUTPUT ;
    USE SIGNAL ;
    PORT
      LAYER M5 ;
        RECT  71.424 43.116 71.448 43.2 ;
    END
  END o_data[472]
  PIN o_data[473]
    DIRECTION OUTPUT ;
    USE SIGNAL ;
    PORT
      LAYER M5 ;
        RECT  71.568 43.116 71.592 43.2 ;
    END
  END o_data[473]
  PIN o_data[474]
    DIRECTION OUTPUT ;
    USE SIGNAL ;
    PORT
      LAYER M5 ;
        RECT  71.712 43.116 71.736 43.2 ;
    END
  END o_data[474]
  PIN o_data[475]
    DIRECTION OUTPUT ;
    USE SIGNAL ;
    PORT
      LAYER M5 ;
        RECT  71.856 43.116 71.88 43.2 ;
    END
  END o_data[475]
  PIN o_data[476]
    DIRECTION OUTPUT ;
    USE SIGNAL ;
    PORT
      LAYER M5 ;
        RECT  72 43.116 72.024 43.2 ;
    END
  END o_data[476]
  PIN o_data[477]
    DIRECTION OUTPUT ;
    USE SIGNAL ;
    PORT
      LAYER M5 ;
        RECT  72.144 43.116 72.168 43.2 ;
    END
  END o_data[477]
  PIN o_data[478]
    DIRECTION OUTPUT ;
    USE SIGNAL ;
    PORT
      LAYER M5 ;
        RECT  72.288 43.116 72.312 43.2 ;
    END
  END o_data[478]
  PIN o_data[479]
    DIRECTION OUTPUT ;
    USE SIGNAL ;
    PORT
      LAYER M5 ;
        RECT  72.432 43.116 72.456 43.2 ;
    END
  END o_data[479]
  PIN o_data[47]
    DIRECTION OUTPUT ;
    USE SIGNAL ;
    PORT
      LAYER M5 ;
        RECT  75.888 43.116 75.912 43.2 ;
    END
  END o_data[47]
  PIN o_data[480]
    DIRECTION OUTPUT ;
    USE SIGNAL ;
    PORT
      LAYER M5 ;
        RECT  72.576 43.116 72.6 43.2 ;
    END
  END o_data[480]
  PIN o_data[481]
    DIRECTION OUTPUT ;
    USE SIGNAL ;
    PORT
      LAYER M5 ;
        RECT  72.72 43.116 72.744 43.2 ;
    END
  END o_data[481]
  PIN o_data[482]
    DIRECTION OUTPUT ;
    USE SIGNAL ;
    PORT
      LAYER M5 ;
        RECT  72.864 43.116 72.888 43.2 ;
    END
  END o_data[482]
  PIN o_data[483]
    DIRECTION OUTPUT ;
    USE SIGNAL ;
    PORT
      LAYER M5 ;
        RECT  73.008 43.116 73.032 43.2 ;
    END
  END o_data[483]
  PIN o_data[484]
    DIRECTION OUTPUT ;
    USE SIGNAL ;
    PORT
      LAYER M5 ;
        RECT  73.152 43.116 73.176 43.2 ;
    END
  END o_data[484]
  PIN o_data[485]
    DIRECTION OUTPUT ;
    USE SIGNAL ;
    PORT
      LAYER M5 ;
        RECT  73.296 43.116 73.32 43.2 ;
    END
  END o_data[485]
  PIN o_data[486]
    DIRECTION OUTPUT ;
    USE SIGNAL ;
    PORT
      LAYER M5 ;
        RECT  73.44 43.116 73.464 43.2 ;
    END
  END o_data[486]
  PIN o_data[487]
    DIRECTION OUTPUT ;
    USE SIGNAL ;
    PORT
      LAYER M5 ;
        RECT  73.584 43.116 73.608 43.2 ;
    END
  END o_data[487]
  PIN o_data[488]
    DIRECTION OUTPUT ;
    USE SIGNAL ;
    PORT
      LAYER M5 ;
        RECT  73.728 43.116 73.752 43.2 ;
    END
  END o_data[488]
  PIN o_data[489]
    DIRECTION OUTPUT ;
    USE SIGNAL ;
    PORT
      LAYER M5 ;
        RECT  73.872 43.116 73.896 43.2 ;
    END
  END o_data[489]
  PIN o_data[48]
    DIRECTION OUTPUT ;
    USE SIGNAL ;
    PORT
      LAYER M5 ;
        RECT  76.032 43.116 76.056 43.2 ;
    END
  END o_data[48]
  PIN o_data[490]
    DIRECTION OUTPUT ;
    USE SIGNAL ;
    PORT
      LAYER M5 ;
        RECT  74.016 43.116 74.04 43.2 ;
    END
  END o_data[490]
  PIN o_data[491]
    DIRECTION OUTPUT ;
    USE SIGNAL ;
    PORT
      LAYER M5 ;
        RECT  60.336 43.116 60.36 43.2 ;
    END
  END o_data[491]
  PIN o_data[492]
    DIRECTION OUTPUT ;
    USE SIGNAL ;
    PORT
      LAYER M5 ;
        RECT  60.48 43.116 60.504 43.2 ;
    END
  END o_data[492]
  PIN o_data[493]
    DIRECTION OUTPUT ;
    USE SIGNAL ;
    PORT
      LAYER M5 ;
        RECT  60.624 43.116 60.648 43.2 ;
    END
  END o_data[493]
  PIN o_data[494]
    DIRECTION OUTPUT ;
    USE SIGNAL ;
    PORT
      LAYER M5 ;
        RECT  60.768 43.116 60.792 43.2 ;
    END
  END o_data[494]
  PIN o_data[495]
    DIRECTION OUTPUT ;
    USE SIGNAL ;
    PORT
      LAYER M5 ;
        RECT  60.912 43.116 60.936 43.2 ;
    END
  END o_data[495]
  PIN o_data[496]
    DIRECTION OUTPUT ;
    USE SIGNAL ;
    PORT
      LAYER M5 ;
        RECT  61.056 43.116 61.08 43.2 ;
    END
  END o_data[496]
  PIN o_data[497]
    DIRECTION OUTPUT ;
    USE SIGNAL ;
    PORT
      LAYER M5 ;
        RECT  61.2 43.116 61.224 43.2 ;
    END
  END o_data[497]
  PIN o_data[498]
    DIRECTION OUTPUT ;
    USE SIGNAL ;
    PORT
      LAYER M5 ;
        RECT  61.344 43.116 61.368 43.2 ;
    END
  END o_data[498]
  PIN o_data[499]
    DIRECTION OUTPUT ;
    USE SIGNAL ;
    PORT
      LAYER M5 ;
        RECT  61.488 43.116 61.512 43.2 ;
    END
  END o_data[499]
  PIN o_data[49]
    DIRECTION OUTPUT ;
    USE SIGNAL ;
    PORT
      LAYER M5 ;
        RECT  76.176 43.116 76.2 43.2 ;
    END
  END o_data[49]
  PIN o_data[4]
    DIRECTION OUTPUT ;
    USE SIGNAL ;
    PORT
      LAYER M5 ;
        RECT  130.752 43.116 130.776 43.2 ;
    END
  END o_data[4]
  PIN o_data[500]
    DIRECTION OUTPUT ;
    USE SIGNAL ;
    PORT
      LAYER M5 ;
        RECT  61.632 43.116 61.656 43.2 ;
    END
  END o_data[500]
  PIN o_data[501]
    DIRECTION OUTPUT ;
    USE SIGNAL ;
    PORT
      LAYER M5 ;
        RECT  61.776 43.116 61.8 43.2 ;
    END
  END o_data[501]
  PIN o_data[502]
    DIRECTION OUTPUT ;
    USE SIGNAL ;
    PORT
      LAYER M5 ;
        RECT  61.92 43.116 61.944 43.2 ;
    END
  END o_data[502]
  PIN o_data[503]
    DIRECTION OUTPUT ;
    USE SIGNAL ;
    PORT
      LAYER M5 ;
        RECT  62.064 43.116 62.088 43.2 ;
    END
  END o_data[503]
  PIN o_data[504]
    DIRECTION OUTPUT ;
    USE SIGNAL ;
    PORT
      LAYER M5 ;
        RECT  62.208 43.116 62.232 43.2 ;
    END
  END o_data[504]
  PIN o_data[505]
    DIRECTION OUTPUT ;
    USE SIGNAL ;
    PORT
      LAYER M5 ;
        RECT  62.352 43.116 62.376 43.2 ;
    END
  END o_data[505]
  PIN o_data[506]
    DIRECTION OUTPUT ;
    USE SIGNAL ;
    PORT
      LAYER M5 ;
        RECT  62.496 43.116 62.52 43.2 ;
    END
  END o_data[506]
  PIN o_data[507]
    DIRECTION OUTPUT ;
    USE SIGNAL ;
    PORT
      LAYER M5 ;
        RECT  62.64 43.116 62.664 43.2 ;
    END
  END o_data[507]
  PIN o_data[508]
    DIRECTION OUTPUT ;
    USE SIGNAL ;
    PORT
      LAYER M5 ;
        RECT  62.784 43.116 62.808 43.2 ;
    END
  END o_data[508]
  PIN o_data[509]
    DIRECTION OUTPUT ;
    USE SIGNAL ;
    PORT
      LAYER M5 ;
        RECT  62.928 43.116 62.952 43.2 ;
    END
  END o_data[509]
  PIN o_data[50]
    DIRECTION OUTPUT ;
    USE SIGNAL ;
    PORT
      LAYER M5 ;
        RECT  76.32 43.116 76.344 43.2 ;
    END
  END o_data[50]
  PIN o_data[510]
    DIRECTION OUTPUT ;
    USE SIGNAL ;
    PORT
      LAYER M5 ;
        RECT  63.072 43.116 63.096 43.2 ;
    END
  END o_data[510]
  PIN o_data[511]
    DIRECTION OUTPUT ;
    USE SIGNAL ;
    PORT
      LAYER M5 ;
        RECT  63.216 43.116 63.24 43.2 ;
    END
  END o_data[511]
  PIN o_data[51]
    DIRECTION OUTPUT ;
    USE SIGNAL ;
    PORT
      LAYER M5 ;
        RECT  76.464 43.116 76.488 43.2 ;
    END
  END o_data[51]
  PIN o_data[52]
    DIRECTION OUTPUT ;
    USE SIGNAL ;
    PORT
      LAYER M5 ;
        RECT  76.608 43.116 76.632 43.2 ;
    END
  END o_data[52]
  PIN o_data[53]
    DIRECTION OUTPUT ;
    USE SIGNAL ;
    PORT
      LAYER M5 ;
        RECT  76.752 43.116 76.776 43.2 ;
    END
  END o_data[53]
  PIN o_data[54]
    DIRECTION OUTPUT ;
    USE SIGNAL ;
    PORT
      LAYER M5 ;
        RECT  76.896 43.116 76.92 43.2 ;
    END
  END o_data[54]
  PIN o_data[55]
    DIRECTION OUTPUT ;
    USE SIGNAL ;
    PORT
      LAYER M5 ;
        RECT  77.04 43.116 77.064 43.2 ;
    END
  END o_data[55]
  PIN o_data[56]
    DIRECTION OUTPUT ;
    USE SIGNAL ;
    PORT
      LAYER M5 ;
        RECT  77.184 43.116 77.208 43.2 ;
    END
  END o_data[56]
  PIN o_data[57]
    DIRECTION OUTPUT ;
    USE SIGNAL ;
    PORT
      LAYER M5 ;
        RECT  77.328 43.116 77.352 43.2 ;
    END
  END o_data[57]
  PIN o_data[58]
    DIRECTION OUTPUT ;
    USE SIGNAL ;
    PORT
      LAYER M5 ;
        RECT  77.472 43.116 77.496 43.2 ;
    END
  END o_data[58]
  PIN o_data[59]
    DIRECTION OUTPUT ;
    USE SIGNAL ;
    PORT
      LAYER M5 ;
        RECT  77.616 43.116 77.64 43.2 ;
    END
  END o_data[59]
  PIN o_data[5]
    DIRECTION OUTPUT ;
    USE SIGNAL ;
    PORT
      LAYER M5 ;
        RECT  130.896 43.116 130.92 43.2 ;
    END
  END o_data[5]
  PIN o_data[60]
    DIRECTION OUTPUT ;
    USE SIGNAL ;
    PORT
      LAYER M5 ;
        RECT  77.76 43.116 77.784 43.2 ;
    END
  END o_data[60]
  PIN o_data[61]
    DIRECTION OUTPUT ;
    USE SIGNAL ;
    PORT
      LAYER M5 ;
        RECT  77.904 43.116 77.928 43.2 ;
    END
  END o_data[61]
  PIN o_data[62]
    DIRECTION OUTPUT ;
    USE SIGNAL ;
    PORT
      LAYER M5 ;
        RECT  78.048 43.116 78.072 43.2 ;
    END
  END o_data[62]
  PIN o_data[63]
    DIRECTION OUTPUT ;
    USE SIGNAL ;
    PORT
      LAYER M5 ;
        RECT  78.192 43.116 78.216 43.2 ;
    END
  END o_data[63]
  PIN o_data[64]
    DIRECTION OUTPUT ;
    USE SIGNAL ;
    PORT
      LAYER M5 ;
        RECT  78.336 43.116 78.36 43.2 ;
    END
  END o_data[64]
  PIN o_data[65]
    DIRECTION OUTPUT ;
    USE SIGNAL ;
    PORT
      LAYER M5 ;
        RECT  78.48 43.116 78.504 43.2 ;
    END
  END o_data[65]
  PIN o_data[66]
    DIRECTION OUTPUT ;
    USE SIGNAL ;
    PORT
      LAYER M5 ;
        RECT  78.624 43.116 78.648 43.2 ;
    END
  END o_data[66]
  PIN o_data[67]
    DIRECTION OUTPUT ;
    USE SIGNAL ;
    PORT
      LAYER M5 ;
        RECT  78.768 43.116 78.792 43.2 ;
    END
  END o_data[67]
  PIN o_data[68]
    DIRECTION OUTPUT ;
    USE SIGNAL ;
    PORT
      LAYER M5 ;
        RECT  78.912 43.116 78.936 43.2 ;
    END
  END o_data[68]
  PIN o_data[69]
    DIRECTION OUTPUT ;
    USE SIGNAL ;
    PORT
      LAYER M5 ;
        RECT  79.056 43.116 79.08 43.2 ;
    END
  END o_data[69]
  PIN o_data[6]
    DIRECTION OUTPUT ;
    USE SIGNAL ;
    PORT
      LAYER M5 ;
        RECT  131.04 43.116 131.064 43.2 ;
    END
  END o_data[6]
  PIN o_data[70]
    DIRECTION OUTPUT ;
    USE SIGNAL ;
    PORT
      LAYER M5 ;
        RECT  79.2 43.116 79.224 43.2 ;
    END
  END o_data[70]
  PIN o_data[71]
    DIRECTION OUTPUT ;
    USE SIGNAL ;
    PORT
      LAYER M5 ;
        RECT  79.344 43.116 79.368 43.2 ;
    END
  END o_data[71]
  PIN o_data[72]
    DIRECTION OUTPUT ;
    USE SIGNAL ;
    PORT
      LAYER M5 ;
        RECT  79.488 43.116 79.512 43.2 ;
    END
  END o_data[72]
  PIN o_data[73]
    DIRECTION OUTPUT ;
    USE SIGNAL ;
    PORT
      LAYER M5 ;
        RECT  79.632 43.116 79.656 43.2 ;
    END
  END o_data[73]
  PIN o_data[74]
    DIRECTION OUTPUT ;
    USE SIGNAL ;
    PORT
      LAYER M5 ;
        RECT  79.776 43.116 79.8 43.2 ;
    END
  END o_data[74]
  PIN o_data[75]
    DIRECTION OUTPUT ;
    USE SIGNAL ;
    PORT
      LAYER M5 ;
        RECT  79.92 43.116 79.944 43.2 ;
    END
  END o_data[75]
  PIN o_data[76]
    DIRECTION OUTPUT ;
    USE SIGNAL ;
    PORT
      LAYER M5 ;
        RECT  80.064 43.116 80.088 43.2 ;
    END
  END o_data[76]
  PIN o_data[77]
    DIRECTION OUTPUT ;
    USE SIGNAL ;
    PORT
      LAYER M5 ;
        RECT  80.208 43.116 80.232 43.2 ;
    END
  END o_data[77]
  PIN o_data[78]
    DIRECTION OUTPUT ;
    USE SIGNAL ;
    PORT
      LAYER M5 ;
        RECT  80.352 43.116 80.376 43.2 ;
    END
  END o_data[78]
  PIN o_data[79]
    DIRECTION OUTPUT ;
    USE SIGNAL ;
    PORT
      LAYER M5 ;
        RECT  80.496 43.116 80.52 43.2 ;
    END
  END o_data[79]
  PIN o_data[7]
    DIRECTION OUTPUT ;
    USE SIGNAL ;
    PORT
      LAYER M5 ;
        RECT  131.184 43.116 131.208 43.2 ;
    END
  END o_data[7]
  PIN o_data[80]
    DIRECTION OUTPUT ;
    USE SIGNAL ;
    PORT
      LAYER M5 ;
        RECT  80.64 43.116 80.664 43.2 ;
    END
  END o_data[80]
  PIN o_data[81]
    DIRECTION OUTPUT ;
    USE SIGNAL ;
    PORT
      LAYER M5 ;
        RECT  80.784 43.116 80.808 43.2 ;
    END
  END o_data[81]
  PIN o_data[82]
    DIRECTION OUTPUT ;
    USE SIGNAL ;
    PORT
      LAYER M5 ;
        RECT  80.928 43.116 80.952 43.2 ;
    END
  END o_data[82]
  PIN o_data[83]
    DIRECTION OUTPUT ;
    USE SIGNAL ;
    PORT
      LAYER M5 ;
        RECT  81.072 43.116 81.096 43.2 ;
    END
  END o_data[83]
  PIN o_data[84]
    DIRECTION OUTPUT ;
    USE SIGNAL ;
    PORT
      LAYER M5 ;
        RECT  81.216 43.116 81.24 43.2 ;
    END
  END o_data[84]
  PIN o_data[85]
    DIRECTION OUTPUT ;
    USE SIGNAL ;
    PORT
      LAYER M5 ;
        RECT  81.36 43.116 81.384 43.2 ;
    END
  END o_data[85]
  PIN o_data[86]
    DIRECTION OUTPUT ;
    USE SIGNAL ;
    PORT
      LAYER M5 ;
        RECT  81.504 43.116 81.528 43.2 ;
    END
  END o_data[86]
  PIN o_data[87]
    DIRECTION OUTPUT ;
    USE SIGNAL ;
    PORT
      LAYER M5 ;
        RECT  81.648 43.116 81.672 43.2 ;
    END
  END o_data[87]
  PIN o_data[88]
    DIRECTION OUTPUT ;
    USE SIGNAL ;
    PORT
      LAYER M5 ;
        RECT  81.792 43.116 81.816 43.2 ;
    END
  END o_data[88]
  PIN o_data[89]
    DIRECTION OUTPUT ;
    USE SIGNAL ;
    PORT
      LAYER M5 ;
        RECT  81.936 43.116 81.96 43.2 ;
    END
  END o_data[89]
  PIN o_data[8]
    DIRECTION OUTPUT ;
    USE SIGNAL ;
    PORT
      LAYER M5 ;
        RECT  131.328 43.116 131.352 43.2 ;
    END
  END o_data[8]
  PIN o_data[90]
    DIRECTION OUTPUT ;
    USE SIGNAL ;
    PORT
      LAYER M5 ;
        RECT  82.08 43.116 82.104 43.2 ;
    END
  END o_data[90]
  PIN o_data[91]
    DIRECTION OUTPUT ;
    USE SIGNAL ;
    PORT
      LAYER M5 ;
        RECT  82.224 43.116 82.248 43.2 ;
    END
  END o_data[91]
  PIN o_data[92]
    DIRECTION OUTPUT ;
    USE SIGNAL ;
    PORT
      LAYER M5 ;
        RECT  82.368 43.116 82.392 43.2 ;
    END
  END o_data[92]
  PIN o_data[93]
    DIRECTION OUTPUT ;
    USE SIGNAL ;
    PORT
      LAYER M5 ;
        RECT  82.512 43.116 82.536 43.2 ;
    END
  END o_data[93]
  PIN o_data[94]
    DIRECTION OUTPUT ;
    USE SIGNAL ;
    PORT
      LAYER M5 ;
        RECT  82.656 43.116 82.68 43.2 ;
    END
  END o_data[94]
  PIN o_data[95]
    DIRECTION OUTPUT ;
    USE SIGNAL ;
    PORT
      LAYER M5 ;
        RECT  82.8 43.116 82.824 43.2 ;
    END
  END o_data[95]
  PIN o_data[96]
    DIRECTION OUTPUT ;
    USE SIGNAL ;
    PORT
      LAYER M5 ;
        RECT  82.944 43.116 82.968 43.2 ;
    END
  END o_data[96]
  PIN o_data[97]
    DIRECTION OUTPUT ;
    USE SIGNAL ;
    PORT
      LAYER M5 ;
        RECT  83.088 43.116 83.112 43.2 ;
    END
  END o_data[97]
  PIN o_data[98]
    DIRECTION OUTPUT ;
    USE SIGNAL ;
    PORT
      LAYER M5 ;
        RECT  83.232 43.116 83.256 43.2 ;
    END
  END o_data[98]
  PIN o_data[99]
    DIRECTION OUTPUT ;
    USE SIGNAL ;
    PORT
      LAYER M5 ;
        RECT  83.376 43.116 83.4 43.2 ;
    END
  END o_data[99]
  PIN o_data[9]
    DIRECTION OUTPUT ;
    USE SIGNAL ;
    PORT
      LAYER M5 ;
        RECT  131.472 43.116 131.496 43.2 ;
    END
  END o_data[9]
  PIN o_epoch[0]
    DIRECTION OUTPUT ;
    USE SIGNAL ;
    PORT
      LAYER M5 ;
        RECT  63.36 43.116 63.384 43.2 ;
    END
  END o_epoch[0]
  PIN o_epoch[10]
    DIRECTION OUTPUT ;
    USE SIGNAL ;
    PORT
      LAYER M5 ;
        RECT  64.8 43.116 64.824 43.2 ;
    END
  END o_epoch[10]
  PIN o_epoch[11]
    DIRECTION OUTPUT ;
    USE SIGNAL ;
    PORT
      LAYER M5 ;
        RECT  103.248 43.116 103.272 43.2 ;
    END
  END o_epoch[11]
  PIN o_epoch[12]
    DIRECTION OUTPUT ;
    USE SIGNAL ;
    PORT
      LAYER M5 ;
        RECT  103.392 43.116 103.416 43.2 ;
    END
  END o_epoch[12]
  PIN o_epoch[13]
    DIRECTION OUTPUT ;
    USE SIGNAL ;
    PORT
      LAYER M5 ;
        RECT  103.536 43.116 103.56 43.2 ;
    END
  END o_epoch[13]
  PIN o_epoch[14]
    DIRECTION OUTPUT ;
    USE SIGNAL ;
    PORT
      LAYER M5 ;
        RECT  103.68 43.116 103.704 43.2 ;
    END
  END o_epoch[14]
  PIN o_epoch[15]
    DIRECTION OUTPUT ;
    USE SIGNAL ;
    PORT
      LAYER M5 ;
        RECT  103.824 43.116 103.848 43.2 ;
    END
  END o_epoch[15]
  PIN o_epoch[1]
    DIRECTION OUTPUT ;
    USE SIGNAL ;
    PORT
      LAYER M5 ;
        RECT  63.504 43.116 63.528 43.2 ;
    END
  END o_epoch[1]
  PIN o_epoch[2]
    DIRECTION OUTPUT ;
    USE SIGNAL ;
    PORT
      LAYER M5 ;
        RECT  63.648 43.116 63.672 43.2 ;
    END
  END o_epoch[2]
  PIN o_epoch[3]
    DIRECTION OUTPUT ;
    USE SIGNAL ;
    PORT
      LAYER M5 ;
        RECT  63.792 43.116 63.816 43.2 ;
    END
  END o_epoch[3]
  PIN o_epoch[4]
    DIRECTION OUTPUT ;
    USE SIGNAL ;
    PORT
      LAYER M5 ;
        RECT  63.936 43.116 63.96 43.2 ;
    END
  END o_epoch[4]
  PIN o_epoch[5]
    DIRECTION OUTPUT ;
    USE SIGNAL ;
    PORT
      LAYER M5 ;
        RECT  64.08 43.116 64.104 43.2 ;
    END
  END o_epoch[5]
  PIN o_epoch[6]
    DIRECTION OUTPUT ;
    USE SIGNAL ;
    PORT
      LAYER M5 ;
        RECT  64.224 43.116 64.248 43.2 ;
    END
  END o_epoch[6]
  PIN o_epoch[7]
    DIRECTION OUTPUT ;
    USE SIGNAL ;
    PORT
      LAYER M5 ;
        RECT  64.368 43.116 64.392 43.2 ;
    END
  END o_epoch[7]
  PIN o_epoch[8]
    DIRECTION OUTPUT ;
    USE SIGNAL ;
    PORT
      LAYER M5 ;
        RECT  64.512 43.116 64.536 43.2 ;
    END
  END o_epoch[8]
  PIN o_epoch[9]
    DIRECTION OUTPUT ;
    USE SIGNAL ;
    PORT
      LAYER M5 ;
        RECT  64.656 43.116 64.68 43.2 ;
    END
  END o_epoch[9]
  PIN o_valid
    DIRECTION OUTPUT ;
    USE SIGNAL ;
    PORT
      LAYER M5 ;
        RECT  103.968 43.116 103.992 43.2 ;
    END
  END o_valid
  PIN VDD
    DIRECTION INOUT ;
    USE POWER ;
    PORT
      LAYER M5 ;
        RECT  186.192 2.151 186.312 41.049 ;
        RECT  183.492 2.151 183.612 41.049 ;
        RECT  180.792 2.151 180.912 41.049 ;
        RECT  178.092 2.151 178.212 41.049 ;
        RECT  175.392 2.151 175.512 41.049 ;
        RECT  172.692 2.151 172.812 41.049 ;
        RECT  169.992 2.151 170.112 41.049 ;
        RECT  167.292 2.151 167.412 41.049 ;
        RECT  164.592 2.151 164.712 41.049 ;
        RECT  161.892 2.151 162.012 41.049 ;
        RECT  159.192 2.151 159.312 41.049 ;
        RECT  156.492 2.151 156.612 41.049 ;
        RECT  153.792 2.151 153.912 41.049 ;
        RECT  151.092 2.151 151.212 41.049 ;
        RECT  148.392 2.151 148.512 41.049 ;
        RECT  145.692 2.151 145.812 41.049 ;
        RECT  142.992 2.151 143.112 41.049 ;
        RECT  140.292 2.151 140.412 41.049 ;
        RECT  137.592 2.151 137.712 41.049 ;
        RECT  134.892 2.151 135.012 41.049 ;
        RECT  132.192 2.151 132.312 41.049 ;
        RECT  129.492 2.151 129.612 41.049 ;
        RECT  126.792 2.151 126.912 41.049 ;
        RECT  124.092 2.151 124.212 41.049 ;
        RECT  121.392 2.151 121.512 41.049 ;
        RECT  118.692 2.151 118.812 41.049 ;
        RECT  115.992 2.151 116.112 41.049 ;
        RECT  113.292 2.151 113.412 41.049 ;
        RECT  110.592 2.151 110.712 41.049 ;
        RECT  107.892 2.151 108.012 41.049 ;
        RECT  105.192 2.151 105.312 41.049 ;
        RECT  102.492 2.151 102.612 41.049 ;
        RECT  99.792 2.151 99.912 41.049 ;
        RECT  97.092 2.151 97.212 41.049 ;
        RECT  94.392 2.151 94.512 41.049 ;
        RECT  91.692 2.151 91.812 41.049 ;
        RECT  88.992 2.151 89.112 41.049 ;
        RECT  86.292 2.151 86.412 41.049 ;
        RECT  83.592 2.151 83.712 41.049 ;
        RECT  80.892 2.151 81.012 41.049 ;
        RECT  78.192 2.151 78.312 41.049 ;
        RECT  75.492 2.151 75.612 41.049 ;
        RECT  72.792 2.151 72.912 41.049 ;
        RECT  70.092 2.151 70.212 41.049 ;
        RECT  67.392 2.151 67.512 41.049 ;
        RECT  64.692 2.151 64.812 41.049 ;
        RECT  61.992 2.151 62.112 41.049 ;
        RECT  59.292 2.151 59.412 41.049 ;
        RECT  56.592 2.151 56.712 41.049 ;
        RECT  53.892 2.151 54.012 41.049 ;
        RECT  51.192 2.151 51.312 41.049 ;
        RECT  48.492 2.151 48.612 41.049 ;
        RECT  45.792 2.151 45.912 41.049 ;
        RECT  43.092 2.151 43.212 41.049 ;
        RECT  40.392 2.151 40.512 41.049 ;
        RECT  37.692 2.151 37.812 41.049 ;
        RECT  34.992 2.151 35.112 41.049 ;
        RECT  32.292 2.151 32.412 41.049 ;
        RECT  29.592 2.151 29.712 41.049 ;
        RECT  26.892 2.151 27.012 41.049 ;
        RECT  24.192 2.151 24.312 41.049 ;
        RECT  21.492 2.151 21.612 41.049 ;
        RECT  18.792 2.151 18.912 41.049 ;
        RECT  16.092 2.151 16.212 41.049 ;
        RECT  13.392 2.151 13.512 41.049 ;
        RECT  10.692 2.151 10.812 41.049 ;
        RECT  7.992 2.151 8.112 41.049 ;
        RECT  5.292 2.151 5.412 41.049 ;
        RECT  2.592 2.151 2.712 41.049 ;
    END
  END VDD
  PIN VSS
    DIRECTION INOUT ;
    USE GROUND ;
    PORT
      LAYER M5 ;
        RECT  186 2.137 186.12 41.063 ;
        RECT  183.3 2.137 183.42 41.063 ;
        RECT  180.6 2.137 180.72 41.063 ;
        RECT  177.9 2.137 178.02 41.063 ;
        RECT  175.2 2.137 175.32 41.063 ;
        RECT  172.5 2.137 172.62 41.063 ;
        RECT  169.8 2.137 169.92 41.063 ;
        RECT  167.1 2.137 167.22 41.063 ;
        RECT  164.4 2.137 164.52 41.063 ;
        RECT  161.7 2.137 161.82 41.063 ;
        RECT  159 2.137 159.12 41.063 ;
        RECT  156.3 2.137 156.42 41.063 ;
        RECT  153.6 2.137 153.72 41.063 ;
        RECT  150.9 2.137 151.02 41.063 ;
        RECT  148.2 2.137 148.32 41.063 ;
        RECT  145.5 2.137 145.62 41.063 ;
        RECT  142.8 2.137 142.92 41.063 ;
        RECT  140.1 2.137 140.22 41.063 ;
        RECT  137.4 2.137 137.52 41.063 ;
        RECT  134.7 2.137 134.82 41.063 ;
        RECT  132 2.137 132.12 41.063 ;
        RECT  129.3 2.137 129.42 41.063 ;
        RECT  126.6 2.137 126.72 41.063 ;
        RECT  123.9 2.137 124.02 41.063 ;
        RECT  121.2 2.137 121.32 41.063 ;
        RECT  118.5 2.137 118.62 41.063 ;
        RECT  115.8 2.137 115.92 41.063 ;
        RECT  113.1 2.137 113.22 41.063 ;
        RECT  110.4 2.137 110.52 41.063 ;
        RECT  107.7 2.137 107.82 41.063 ;
        RECT  105 2.137 105.12 41.063 ;
        RECT  102.3 2.137 102.42 41.063 ;
        RECT  99.6 2.137 99.72 41.063 ;
        RECT  96.9 2.137 97.02 41.063 ;
        RECT  94.2 2.137 94.32 41.063 ;
        RECT  91.5 2.137 91.62 41.063 ;
        RECT  88.8 2.137 88.92 41.063 ;
        RECT  86.1 2.137 86.22 41.063 ;
        RECT  83.4 2.137 83.52 41.063 ;
        RECT  80.7 2.137 80.82 41.063 ;
        RECT  78 2.137 78.12 41.063 ;
        RECT  75.3 2.137 75.42 41.063 ;
        RECT  72.6 2.137 72.72 41.063 ;
        RECT  69.9 2.137 70.02 41.063 ;
        RECT  67.2 2.137 67.32 41.063 ;
        RECT  64.5 2.137 64.62 41.063 ;
        RECT  61.8 2.137 61.92 41.063 ;
        RECT  59.1 2.137 59.22 41.063 ;
        RECT  56.4 2.137 56.52 41.063 ;
        RECT  53.7 2.137 53.82 41.063 ;
        RECT  51 2.137 51.12 41.063 ;
        RECT  48.3 2.137 48.42 41.063 ;
        RECT  45.6 2.137 45.72 41.063 ;
        RECT  42.9 2.137 43.02 41.063 ;
        RECT  40.2 2.137 40.32 41.063 ;
        RECT  37.5 2.137 37.62 41.063 ;
        RECT  34.8 2.137 34.92 41.063 ;
        RECT  32.1 2.137 32.22 41.063 ;
        RECT  29.4 2.137 29.52 41.063 ;
        RECT  26.7 2.137 26.82 41.063 ;
        RECT  24 2.137 24.12 41.063 ;
        RECT  21.3 2.137 21.42 41.063 ;
        RECT  18.6 2.137 18.72 41.063 ;
        RECT  15.9 2.137 16.02 41.063 ;
        RECT  13.2 2.137 13.32 41.063 ;
        RECT  10.5 2.137 10.62 41.063 ;
        RECT  7.8 2.137 7.92 41.063 ;
        RECT  5.1 2.137 5.22 41.063 ;
        RECT  2.4 2.137 2.52 41.063 ;
    END
  END VSS
  OBS
    LAYER RVTN ;
     RECT  2.16 2.16 187.92 2.295 ;
     RECT  2.16 2.565 187.92 2.835 ;
     RECT  2.16 3.105 187.92 3.375 ;
     RECT  2.16 3.645 187.92 3.915 ;
     RECT  2.16 4.185 187.92 4.455 ;
     RECT  2.16 4.725 187.92 4.995 ;
     RECT  2.16 5.265 187.92 5.535 ;
     RECT  2.16 5.805 187.92 6.075 ;
     RECT  2.16 6.345 187.92 6.615 ;
     RECT  2.16 6.885 187.92 7.155 ;
     RECT  2.16 7.425 187.92 7.695 ;
     RECT  2.16 7.965 187.92 8.235 ;
     RECT  2.16 8.505 187.92 8.775 ;
     RECT  2.16 9.045 187.92 9.315 ;
     RECT  2.16 9.585 187.92 9.855 ;
     RECT  2.16 10.125 187.92 10.395 ;
     RECT  2.16 10.665 187.92 10.935 ;
     RECT  2.16 11.205 187.92 11.475 ;
     RECT  2.16 11.745 187.92 12.015 ;
     RECT  2.16 12.285 187.92 12.555 ;
     RECT  2.16 12.825 187.92 13.095 ;
     RECT  2.16 13.365 187.92 13.635 ;
     RECT  2.16 13.905 187.92 14.175 ;
     RECT  2.16 14.445 187.92 14.715 ;
     RECT  2.16 14.985 187.92 15.255 ;
     RECT  2.16 15.525 187.92 15.795 ;
     RECT  2.16 16.065 187.92 16.335 ;
     RECT  2.16 16.605 187.92 16.875 ;
     RECT  2.16 17.145 187.92 17.415 ;
     RECT  2.16 17.685 187.92 17.955 ;
     RECT  2.16 18.225 187.92 18.495 ;
     RECT  2.16 18.765 187.92 19.035 ;
     RECT  2.16 19.305 187.92 19.575 ;
     RECT  2.16 19.845 187.92 20.115 ;
     RECT  2.16 20.385 187.92 20.655 ;
     RECT  2.16 20.925 187.92 21.195 ;
     RECT  2.16 21.465 187.92 21.735 ;
     RECT  2.16 22.005 187.92 22.275 ;
     RECT  2.16 22.545 187.92 22.815 ;
     RECT  2.16 23.085 187.92 23.355 ;
     RECT  2.16 23.625 187.92 23.895 ;
     RECT  2.16 24.165 187.92 24.435 ;
     RECT  2.16 24.705 187.92 24.975 ;
     RECT  2.16 25.245 187.92 25.515 ;
     RECT  2.16 25.785 187.92 26.055 ;
     RECT  2.16 26.325 187.92 26.595 ;
     RECT  2.16 26.865 187.92 27.135 ;
     RECT  2.16 27.405 187.92 27.675 ;
     RECT  2.16 27.945 187.92 28.215 ;
     RECT  2.16 28.485 187.92 28.755 ;
     RECT  2.16 29.025 187.92 29.295 ;
     RECT  2.16 29.565 187.92 29.835 ;
     RECT  2.16 30.105 187.92 30.375 ;
     RECT  2.16 30.645 187.92 30.915 ;
     RECT  2.16 31.185 187.92 31.455 ;
     RECT  2.16 31.725 187.92 31.995 ;
     RECT  2.16 32.265 187.92 32.535 ;
     RECT  2.16 32.805 187.92 33.075 ;
     RECT  2.16 33.345 187.92 33.615 ;
     RECT  2.16 33.885 187.92 34.155 ;
     RECT  2.16 34.425 187.92 34.695 ;
     RECT  2.16 34.965 187.92 35.235 ;
     RECT  2.16 35.505 187.92 35.775 ;
     RECT  2.16 36.045 187.92 36.315 ;
     RECT  2.16 36.585 187.92 36.855 ;
     RECT  2.16 37.125 187.92 37.395 ;
     RECT  2.16 37.665 187.92 37.935 ;
     RECT  2.16 38.205 187.92 38.475 ;
     RECT  2.16 38.745 187.92 39.015 ;
     RECT  2.16 39.285 187.92 39.555 ;
     RECT  2.16 39.825 187.92 40.095 ;
     RECT  2.16 40.365 187.92 40.635 ;
     RECT  2.16 40.905 187.92 41.04 ;
    LAYER RVTP ;
     RECT  2.16 2.295 187.92 2.565 ;
     RECT  2.16 2.835 187.92 3.105 ;
     RECT  2.16 3.375 187.92 3.645 ;
     RECT  2.16 3.915 187.92 4.185 ;
     RECT  2.16 4.455 187.92 4.725 ;
     RECT  2.16 4.995 187.92 5.265 ;
     RECT  2.16 5.535 187.92 5.805 ;
     RECT  2.16 6.075 187.92 6.345 ;
     RECT  2.16 6.615 187.92 6.885 ;
     RECT  2.16 7.155 187.92 7.425 ;
     RECT  2.16 7.695 187.92 7.965 ;
     RECT  2.16 8.235 187.92 8.505 ;
     RECT  2.16 8.775 187.92 9.045 ;
     RECT  2.16 9.315 187.92 9.585 ;
     RECT  2.16 9.855 187.92 10.125 ;
     RECT  2.16 10.395 187.92 10.665 ;
     RECT  2.16 10.935 187.92 11.205 ;
     RECT  2.16 11.475 187.92 11.745 ;
     RECT  2.16 12.015 187.92 12.285 ;
     RECT  2.16 12.555 187.92 12.825 ;
     RECT  2.16 13.095 187.92 13.365 ;
     RECT  2.16 13.635 187.92 13.905 ;
     RECT  2.16 14.175 187.92 14.445 ;
     RECT  2.16 14.715 187.92 14.985 ;
     RECT  2.16 15.255 187.92 15.525 ;
     RECT  2.16 15.795 187.92 16.065 ;
     RECT  2.16 16.335 187.92 16.605 ;
     RECT  2.16 16.875 187.92 17.145 ;
     RECT  2.16 17.415 187.92 17.685 ;
     RECT  2.16 17.955 187.92 18.225 ;
     RECT  2.16 18.495 187.92 18.765 ;
     RECT  2.16 19.035 187.92 19.305 ;
     RECT  2.16 19.575 187.92 19.845 ;
     RECT  2.16 20.115 187.92 20.385 ;
     RECT  2.16 20.655 187.92 20.925 ;
     RECT  2.16 21.195 187.92 21.465 ;
     RECT  2.16 21.735 187.92 22.005 ;
     RECT  2.16 22.275 187.92 22.545 ;
     RECT  2.16 22.815 187.92 23.085 ;
     RECT  2.16 23.355 187.92 23.625 ;
     RECT  2.16 23.895 187.92 24.165 ;
     RECT  2.16 24.435 187.92 24.705 ;
     RECT  2.16 24.975 187.92 25.245 ;
     RECT  2.16 25.515 187.92 25.785 ;
     RECT  2.16 26.055 187.92 26.325 ;
     RECT  2.16 26.595 187.92 26.865 ;
     RECT  2.16 27.135 187.92 27.405 ;
     RECT  2.16 27.675 187.92 27.945 ;
     RECT  2.16 28.215 187.92 28.485 ;
     RECT  2.16 28.755 187.92 29.025 ;
     RECT  2.16 29.295 187.92 29.565 ;
     RECT  2.16 29.835 187.92 30.105 ;
     RECT  2.16 30.375 187.92 30.645 ;
     RECT  2.16 30.915 187.92 31.185 ;
     RECT  2.16 31.455 187.92 31.725 ;
     RECT  2.16 31.995 187.92 32.265 ;
     RECT  2.16 32.535 187.92 32.805 ;
     RECT  2.16 33.075 187.92 33.345 ;
     RECT  2.16 33.615 187.92 33.885 ;
     RECT  2.16 34.155 187.92 34.425 ;
     RECT  2.16 34.695 187.92 34.965 ;
     RECT  2.16 35.235 187.92 35.505 ;
     RECT  2.16 35.775 187.92 36.045 ;
     RECT  2.16 36.315 187.92 36.585 ;
     RECT  2.16 36.855 187.92 37.125 ;
     RECT  2.16 37.395 187.92 37.665 ;
     RECT  2.16 37.935 187.92 38.205 ;
     RECT  2.16 38.475 187.92 38.745 ;
     RECT  2.16 39.015 187.92 39.285 ;
     RECT  2.16 39.555 187.92 39.825 ;
     RECT  2.16 40.095 187.92 40.365 ;
     RECT  2.16 40.635 187.92 40.905 ;
    LAYER M1 ;
     RECT  2.16 2.151 187.92 41.049 ;
    LAYER M2 ;
     RECT  25.519 0.036 26.239 0.054 ;
     RECT  26.239 0.036 26.779 0.504 ;
     RECT  2.16 2.151 29.083 41.049 ;
     RECT  26.779 0.036 30.803 0.549 ;
     RECT  30.803 0.036 32.827 0.504 ;
     RECT  32.827 0.036 34.303 0.549 ;
     RECT  29.083 1.494 34.303 41.049 ;
     RECT  34.303 0.036 52.223 41.049 ;
     RECT  52.223 0.414 57.371 41.049 ;
     RECT  57.371 0.846 62.743 41.049 ;
     RECT  62.743 0.414 62.879 41.049 ;
     RECT  62.879 0.882 64.687 41.049 ;
     RECT  64.687 0.846 70.159 41.049 ;
     RECT  70.159 0.378 70.439 41.049 ;
     RECT  70.439 0.846 82.687 41.049 ;
     RECT  82.687 0.801 91.759 41.049 ;
     RECT  91.759 0.108 92.039 41.049 ;
     RECT  92.039 0.801 97.123 41.049 ;
     RECT  97.123 0.144 97.475 41.049 ;
     RECT  97.475 0.801 106.375 41.049 ;
     RECT  106.375 0.486 110.875 41.049 ;
     RECT  110.875 0.144 121.891 41.049 ;
     RECT  121.891 0.072 126.751 41.049 ;
     RECT  126.751 0.036 136.139 41.049 ;
     RECT  136.139 0.036 151.655 0.126 ;
     RECT  151.655 0.036 151.799 0.09 ;
     RECT  151.799 0.036 163.471 0.054 ;
     RECT  163.471 0.036 163.787 0.126 ;
     RECT  136.139 0.882 166.487 41.049 ;
     RECT  163.787 0.036 169.727 0.054 ;
     RECT  166.487 0.918 171.527 41.049 ;
     RECT  171.527 0.99 171.671 41.049 ;
     RECT  171.671 1.422 171.815 41.049 ;
     RECT  171.815 2.151 187.92 41.049 ;
    LAYER M3 ;
     RECT  26.82 0.043 26.838 0.091 ;
     RECT  29.952 0.043 29.97 0.091 ;
     RECT  30.852 0.043 30.87 0.091 ;
     RECT  32.22 0.043 32.238 0.091 ;
     RECT  34.776 0.043 34.794 0.091 ;
     RECT  43.344 0.043 43.47 0.091 ;
     RECT  46.08 0.043 46.782 0.091 ;
     RECT  49.32 0.043 49.59 0.091 ;
     RECT  72.396 0.043 72.414 0.091 ;
     RECT  114.588 0.043 114.606 0.091 ;
     RECT  121.896 0.067 121.914 0.091 ;
     RECT  126.756 0.031 126.774 0.091 ;
     RECT  137.88 0.043 137.898 0.091 ;
     RECT  144.72 0.043 144.738 0.091 ;
     RECT  146.484 0.043 146.502 0.091 ;
     RECT  148.14 0.043 148.158 0.091 ;
     RECT  151.776 0.067 151.794 0.091 ;
     RECT  157.212 0.043 157.23 0.091 ;
     RECT  169.704 0.031 169.722 0.091 ;
     RECT  32.22 0.091 32.31 0.103 ;
     RECT  120.672 0.091 122.13 0.103 ;
     RECT  169.704 0.091 170.406 0.125 ;
     RECT  91.764 0.091 92.034 0.131 ;
     RECT  163.476 0.091 163.782 0.131 ;
     RECT  42.768 0.091 43.47 0.133 ;
     RECT  26.82 0.091 26.982 0.139 ;
     RECT  38.196 0.043 38.646 0.139 ;
     RECT  97.452 0.133 97.47 0.139 ;
     RECT  102.744 0.091 103.302 0.139 ;
     RECT  110.808 0.091 110.826 0.139 ;
     RECT  147.744 0.091 148.158 0.139 ;
     RECT  154.512 0.043 154.53 0.139 ;
     RECT  30.78 0.091 30.87 0.173 ;
     RECT  32.22 0.103 32.778 0.173 ;
     RECT  42.696 0.133 43.47 0.173 ;
     RECT  84.42 0.043 84.438 0.173 ;
     RECT  147.672 0.139 148.158 0.173 ;
     RECT  97.128 0.139 97.47 0.176 ;
     RECT  134.064 0.139 134.658 0.176 ;
     RECT  25.524 0.031 25.542 0.187 ;
     RECT  26.784 0.139 26.982 0.187 ;
     RECT  62.964 0.091 64.71 0.187 ;
     RECT  70.704 0.091 70.83 0.187 ;
     RECT  74.7 0.091 74.718 0.187 ;
     RECT  106.236 0.091 106.686 0.187 ;
     RECT  58.356 0.091 59.922 0.221 ;
     RECT  62.172 0.091 62.19 0.221 ;
     RECT  70.416 0.187 70.83 0.221 ;
     RECT  114.192 0.091 114.714 0.221 ;
     RECT  118.476 0.091 118.638 0.221 ;
     RECT  147.672 0.173 148.014 0.221 ;
     RECT  150.48 0.091 150.498 0.221 ;
     RECT  156.852 0.091 157.23 0.221 ;
     RECT  25.524 0.187 26.982 0.235 ;
     RECT  29.628 0.091 29.97 0.235 ;
     RECT  54.792 0.091 54.81 0.235 ;
     RECT  94.716 0.187 94.734 0.235 ;
     RECT  108.396 0.091 108.738 0.235 ;
     RECT  109.908 0.187 109.926 0.235 ;
     RECT  167.796 0.091 168.966 0.235 ;
     RECT  29.628 0.235 30.042 0.256 ;
     RECT  30.78 0.173 30.798 0.256 ;
     RECT  46.08 0.091 47.178 0.269 ;
     RECT  48.708 0.091 49.59 0.269 ;
     RECT  110.808 0.139 110.898 0.283 ;
     RECT  142.632 0.187 142.65 0.283 ;
     RECT  158.472 0.235 158.49 0.283 ;
     RECT  29.628 0.256 30.798 0.284 ;
     RECT  98.604 0.139 98.622 0.317 ;
     RECT  105.516 0.187 106.686 0.317 ;
     RECT  142.524 0.283 142.65 0.317 ;
     RECT  50.76 0.283 51.246 0.329 ;
     RECT  34.308 0.091 35.118 0.331 ;
     RECT  52.992 0.187 53.01 0.331 ;
     RECT  57.24 0.235 57.258 0.331 ;
     RECT  72.396 0.091 72.81 0.331 ;
     RECT  110.808 0.283 111.186 0.331 ;
     RECT  117.396 0.091 117.414 0.331 ;
     RECT  151.632 0.091 152.766 0.331 ;
     RECT  25.524 0.235 27.054 0.365 ;
     RECT  158.472 0.283 158.562 0.365 ;
     RECT  70.416 0.221 70.722 0.373 ;
     RECT  30.024 0.284 30.798 0.374 ;
     RECT  57.168 0.331 57.258 0.379 ;
     RECT  62.928 0.187 64.71 0.379 ;
     RECT  72.396 0.331 73.134 0.379 ;
     RECT  114.192 0.221 114.606 0.379 ;
     RECT  154.476 0.139 154.53 0.379 ;
     RECT  57.06 0.379 57.258 0.409 ;
     RECT  30.204 0.374 30.798 0.413 ;
     RECT  70.164 0.373 70.722 0.413 ;
     RECT  74.664 0.187 74.718 0.413 ;
     RECT  158.544 0.365 158.562 0.413 ;
     RECT  67.356 0.091 67.482 0.427 ;
     RECT  94.644 0.235 94.734 0.427 ;
     RECT  108.396 0.235 109.926 0.427 ;
     RECT  110.808 0.331 111.294 0.427 ;
     RECT  165.924 0.139 166.626 0.427 ;
     RECT  167.544 0.235 168.966 0.427 ;
     RECT  29.016 0.379 29.214 0.437 ;
     RECT  42.768 0.173 43.47 0.437 ;
     RECT  32.76 0.173 32.778 0.445 ;
     RECT  57.06 0.409 57.366 0.445 ;
     RECT  29.088 0.437 29.214 0.461 ;
     RECT  54.432 0.235 54.81 0.461 ;
     RECT  70.704 0.413 70.722 0.461 ;
     RECT  142.524 0.317 142.542 0.461 ;
     RECT  149.436 0.283 149.454 0.461 ;
     RECT  39.6 0.235 39.618 0.475 ;
     RECT  56.88 0.445 57.366 0.475 ;
     RECT  58.356 0.221 59.814 0.475 ;
     RECT  69.516 0.427 69.534 0.475 ;
     RECT  79.056 0.283 79.074 0.475 ;
     RECT  112.896 0.043 112.914 0.475 ;
     RECT  137.88 0.091 138.006 0.475 ;
     RECT  146.484 0.091 146.79 0.475 ;
     RECT  48.708 0.269 49.338 0.481 ;
     RECT  26.244 0.365 26.802 0.509 ;
     RECT  42.768 0.437 42.822 0.509 ;
     RECT  74.7 0.413 74.718 0.509 ;
     RECT  154.476 0.379 154.638 0.509 ;
     RECT  46.692 0.269 47.178 0.523 ;
     RECT  102.348 0.139 103.302 0.523 ;
     RECT  104.868 0.379 104.886 0.523 ;
     RECT  108.396 0.427 111.294 0.523 ;
     RECT  124.272 0.091 125.154 0.523 ;
     RECT  126.54 0.091 126.774 0.523 ;
     RECT  129.744 0.091 129.906 0.523 ;
     RECT  155.88 0.475 155.898 0.523 ;
     RECT  164.988 0.427 168.966 0.523 ;
     RECT  26.784 0.509 26.802 0.554 ;
     RECT  30.78 0.413 30.798 0.554 ;
     RECT  32.76 0.445 32.85 0.554 ;
     RECT  67.356 0.427 67.59 0.557 ;
     RECT  94.644 0.427 94.77 0.557 ;
     RECT  115.812 0.427 115.83 0.557 ;
     RECT  164.88 0.523 168.966 0.557 ;
     RECT  123.552 0.523 125.154 0.571 ;
     RECT  125.928 0.523 126.774 0.571 ;
     RECT  138.78 0.283 138.798 0.571 ;
     RECT  143.604 0.379 143.622 0.571 ;
     RECT  144.72 0.091 145.026 0.571 ;
     RECT  155.88 0.523 155.97 0.571 ;
     RECT  156.852 0.221 157.014 0.571 ;
     RECT  164.88 0.557 165.186 0.571 ;
     RECT  56.88 0.475 59.814 0.619 ;
     RECT  60.624 0.427 60.642 0.667 ;
     RECT  112.896 0.475 113.058 0.667 ;
     RECT  45.036 0.427 45.054 0.715 ;
     RECT  67.356 0.557 67.374 0.715 ;
     RECT  112.824 0.667 113.058 0.715 ;
     RECT  114.012 0.379 114.606 0.715 ;
     RECT  108.36 0.523 111.294 0.751 ;
     RECT  45.036 0.715 45.63 0.763 ;
     RECT  46.692 0.523 47.718 0.763 ;
     RECT  48.564 0.481 49.338 0.763 ;
     RECT  68.328 0.523 68.346 0.763 ;
     RECT  69.444 0.475 69.534 0.763 ;
     RECT  107.46 0.187 107.478 0.763 ;
     RECT  108.36 0.751 111.762 0.763 ;
     RECT  143.604 0.571 145.026 0.763 ;
     RECT  145.944 0.475 146.79 0.763 ;
     RECT  132.768 0.139 132.786 0.779 ;
     RECT  82.08 0.139 82.098 0.796 ;
     RECT  44.46 0.763 45.63 0.811 ;
     RECT  82.08 0.796 82.71 0.811 ;
     RECT  120.672 0.103 122.778 0.824 ;
     RECT  134.64 0.176 134.658 0.841 ;
     RECT  36.18 0.715 36.198 0.859 ;
     RECT  82.08 0.811 83.25 0.859 ;
     RECT  120.78 0.824 122.778 0.859 ;
     RECT  123.552 0.571 126.774 0.859 ;
     RECT  62.46 0.379 64.71 0.869 ;
     RECT  134.64 0.841 134.874 0.877 ;
     RECT  36.18 0.859 36.522 0.907 ;
     RECT  56.268 0.619 59.814 0.907 ;
     RECT  108.288 0.763 111.762 0.907 ;
     RECT  117.216 0.331 117.414 0.907 ;
     RECT  56.16 0.907 59.814 0.941 ;
     RECT  128.88 0.091 128.898 0.949 ;
     RECT  38.196 0.139 38.754 0.955 ;
     RECT  54.792 0.461 54.81 0.955 ;
     RECT  77.436 0.379 77.454 0.955 ;
     RECT  137.772 0.475 138.006 0.955 ;
     RECT  138.78 0.571 139.518 0.955 ;
     RECT  118.224 0.571 118.242 0.985 ;
     RECT  129.744 0.523 130.122 0.985 ;
     RECT  131.076 0.139 131.094 0.985 ;
     RECT  102.132 0.523 103.302 1.003 ;
     RECT  128.628 0.949 128.898 1.021 ;
     RECT  165.924 0.557 168.966 1.049 ;
     RECT  34.308 0.331 35.37 1.051 ;
     RECT  104.724 0.523 104.886 1.051 ;
     RECT  106.02 0.317 106.47 1.051 ;
     RECT  107.208 0.763 107.478 1.051 ;
     RECT  136.872 0.235 136.89 1.051 ;
     RECT  80.388 0.235 80.406 1.099 ;
     RECT  87.12 0.571 87.138 1.099 ;
     RECT  100.98 0.523 100.998 1.099 ;
     RECT  104.364 1.051 104.886 1.099 ;
     RECT  136.872 1.051 136.962 1.099 ;
     RECT  137.772 0.955 139.518 1.099 ;
     RECT  143.604 0.763 146.79 1.099 ;
     RECT  171.504 0.091 171.81 1.099 ;
     RECT  33.624 1.051 35.37 1.147 ;
     RECT  36.18 0.907 37.098 1.147 ;
     RECT  46.692 0.763 49.338 1.147 ;
     RECT  68.328 0.763 69.534 1.147 ;
     RECT  75.744 0.091 75.762 1.147 ;
     RECT  80.028 1.099 80.406 1.147 ;
     RECT  81.288 0.235 81.306 1.147 ;
     RECT  82.08 0.859 83.574 1.147 ;
     RECT  87.948 0.571 87.966 1.147 ;
     RECT  95.616 0.523 95.634 1.147 ;
     RECT  104.292 1.099 104.886 1.147 ;
     RECT  106.02 1.051 107.478 1.147 ;
     RECT  108.288 0.907 111.978 1.147 ;
     RECT  112.824 0.715 114.606 1.147 ;
     RECT  120.78 0.859 126.774 1.147 ;
     RECT  133.128 0.859 133.362 1.147 ;
     RECT  134.64 0.877 134.946 1.147 ;
     RECT  143.604 1.099 146.826 1.147 ;
     RECT  147.672 0.221 147.762 1.147 ;
     RECT  153.972 0.571 153.99 1.147 ;
     RECT  155.88 0.571 157.014 1.147 ;
     RECT  43.884 0.811 45.63 1.175 ;
     RECT  120.78 1.147 127.098 1.175 ;
     RECT  54.792 0.955 54.846 1.195 ;
     RECT  60.624 0.667 61.002 1.243 ;
     RECT  104.292 1.147 111.978 1.243 ;
     RECT  112.824 1.147 114.678 1.243 ;
     RECT  32.76 0.554 32.778 1.291 ;
     RECT  33.624 1.147 37.098 1.291 ;
     RECT  51.156 0.329 51.174 1.291 ;
     RECT  52.2 0.031 52.218 1.291 ;
     RECT  54.18 1.195 54.846 1.336 ;
     RECT  141.912 1.099 141.93 1.339 ;
     RECT  120.78 1.175 122.022 1.364 ;
     RECT  42.804 0.509 42.822 1.387 ;
     RECT  54.18 1.336 55.35 1.387 ;
     RECT  82.08 1.147 84.078 1.387 ;
     RECT  84.924 1.339 84.942 1.387 ;
     RECT  129.744 0.985 131.094 1.435 ;
     RECT  171.36 1.099 171.81 1.445 ;
     RECT  129.744 1.435 131.634 1.453 ;
     RECT  136.116 0.526 136.134 1.453 ;
     RECT  32.76 1.291 37.098 1.483 ;
     RECT  85.932 0.571 85.95 1.483 ;
     RECT  86.688 1.099 87.138 1.483 ;
     RECT  153.936 1.147 153.99 1.483 ;
     RECT  56.16 0.941 59.778 1.489 ;
     RECT  119.916 0.949 119.934 1.489 ;
     RECT  29.088 0.461 29.106 1.517 ;
     RECT  118.224 0.985 118.566 1.525 ;
     RECT  119.304 1.489 119.934 1.525 ;
     RECT  67.248 0.715 67.374 1.531 ;
     RECT  116.064 0.907 117.414 1.531 ;
     RECT  136.872 1.099 139.518 1.531 ;
     RECT  168.624 1.049 168.966 1.553 ;
     RECT  38.196 0.955 38.79 1.579 ;
     RECT  82.08 1.387 84.942 1.579 ;
     RECT  54.18 1.387 55.386 1.606 ;
     RECT  56.124 1.489 59.778 1.606 ;
     RECT  41.076 0.235 41.094 1.627 ;
     RECT  78.48 0.475 79.074 1.627 ;
     RECT  52.992 0.331 53.442 1.651 ;
     RECT  54.18 1.606 59.778 1.651 ;
     RECT  104.292 1.243 114.678 1.651 ;
     RECT  115.596 1.531 117.414 1.651 ;
     RECT  118.224 1.525 119.934 1.651 ;
     RECT  141.336 1.339 141.93 1.651 ;
     RECT  143.604 1.147 147.762 1.651 ;
     RECT  39.6 0.475 40.122 1.675 ;
     RECT  41.04 1.627 41.094 1.675 ;
     RECT  68.328 1.147 70.074 1.675 ;
     RECT  70.992 1.483 71.01 1.675 ;
     RECT  87.948 1.147 88.038 1.675 ;
     RECT  88.884 1.483 88.902 1.675 ;
     RECT  100.728 1.099 100.998 1.675 ;
     RECT  102.024 1.003 103.302 1.675 ;
     RECT  104.292 1.651 119.934 1.675 ;
     RECT  135.936 1.453 136.134 1.675 ;
     RECT  136.872 1.531 139.698 1.675 ;
     RECT  151.488 0.331 152.766 1.675 ;
     RECT  160.128 0.523 160.146 1.675 ;
     RECT  163.656 0.131 163.674 1.675 ;
     RECT  90.36 0.859 90.378 1.687 ;
     RECT  82.08 1.579 85.05 1.708 ;
     RECT  23.112 0.091 23.13 1.723 ;
     RECT  32.76 1.483 37.134 1.723 ;
     RECT  37.872 1.579 38.79 1.723 ;
     RECT  42.768 1.387 42.822 1.723 ;
     RECT  51.156 1.291 52.218 1.723 ;
     RECT  62.46 0.869 64.134 1.723 ;
     RECT  65.664 0.571 65.682 1.723 ;
     RECT  66.6 1.531 67.374 1.723 ;
     RECT  68.328 1.675 71.01 1.723 ;
     RECT  72.396 0.379 73.422 1.723 ;
     RECT  77.004 0.955 77.454 1.723 ;
     RECT  78.336 1.627 79.074 1.723 ;
     RECT  80.028 1.147 81.306 1.723 ;
     RECT  85.932 1.483 87.138 1.723 ;
     RECT  87.948 1.675 88.902 1.723 ;
     RECT  90.36 1.687 90.63 1.723 ;
     RECT  94.644 0.557 94.662 1.723 ;
     RECT  95.616 1.147 95.742 1.723 ;
     RECT  97.704 0.523 97.722 1.723 ;
     RECT  100.332 1.675 100.998 1.723 ;
     RECT  102.024 1.675 119.934 1.723 ;
     RECT  122.76 1.175 127.098 1.723 ;
     RECT  128.052 1.021 128.898 1.723 ;
     RECT  129.744 1.453 132.282 1.723 ;
     RECT  133.128 1.147 134.946 1.723 ;
     RECT  135.936 1.675 139.698 1.723 ;
     RECT  141.336 1.651 142.434 1.723 ;
     RECT  143.244 1.651 147.762 1.723 ;
     RECT  148.788 0.571 148.806 1.723 ;
     RECT  149.616 0.763 149.634 1.723 ;
     RECT  153.9 1.483 153.99 1.723 ;
     RECT  154.944 1.147 157.014 1.723 ;
     RECT  163.656 1.675 163.854 1.723 ;
     RECT  164.7 0.571 165.186 1.723 ;
     RECT  50.976 1.723 52.218 1.759 ;
     RECT  52.992 1.651 59.778 1.759 ;
     RECT  62.46 1.723 71.01 1.759 ;
     RECT  122.76 1.723 132.282 1.759 ;
     RECT  133.128 1.723 149.634 1.759 ;
     RECT  23.076 1.723 23.13 1.771 ;
     RECT  43.956 1.175 45.63 1.771 ;
     RECT  46.584 1.147 49.338 1.771 ;
     RECT  32.76 1.723 38.862 1.795 ;
     RECT  39.6 1.675 41.094 1.795 ;
     RECT  42.66 1.723 42.822 1.795 ;
     RECT  78.336 1.723 81.306 1.795 ;
     RECT  97.596 1.723 99.09 1.795 ;
     RECT  60.624 1.243 61.254 1.819 ;
     RECT  62.46 1.759 71.19 1.819 ;
     RECT  50.976 1.759 59.778 1.831 ;
     RECT  60.624 1.819 71.19 1.831 ;
     RECT  72.108 1.723 74.718 1.831 ;
     RECT  93.384 1.723 96.498 1.831 ;
     RECT  97.272 1.795 99.09 1.831 ;
     RECT  150.732 0.523 150.75 1.831 ;
     RECT  151.488 1.675 153.054 1.831 ;
     RECT  75.744 1.147 75.942 1.867 ;
     RECT  76.932 1.723 77.454 1.867 ;
     RECT  122.76 1.759 149.634 1.867 ;
     RECT  150.732 1.831 153.054 1.867 ;
     RECT  158.724 0.523 158.742 1.915 ;
     RECT  43.956 1.771 49.338 1.921 ;
     RECT  43.776 1.921 49.338 1.957 ;
     RECT  50.832 1.831 59.778 1.957 ;
     RECT  60.624 1.831 74.718 1.957 ;
     RECT  75.744 1.867 77.454 1.957 ;
     RECT  78.336 1.795 81.342 1.957 ;
     RECT  82.08 1.708 85.086 1.957 ;
     RECT  85.932 1.723 92.61 1.957 ;
     RECT  93.384 1.831 99.09 1.957 ;
     RECT  50.832 1.957 74.718 1.993 ;
     RECT  122.76 1.867 153.054 1.997 ;
     RECT  30.78 1.675 30.798 2.011 ;
     RECT  43.776 1.957 49.986 2.011 ;
     RECT  50.832 1.993 74.862 2.011 ;
     RECT  160.992 1.627 161.01 2.011 ;
     RECT  153.9 1.723 157.014 2.021 ;
     RECT  75.744 1.957 99.09 2.029 ;
     RECT  99.936 1.723 119.934 2.029 ;
     RECT  158.472 1.915 158.742 2.045 ;
     RECT  32.76 1.795 41.094 2.059 ;
     RECT  42.12 1.795 42.822 2.059 ;
     RECT  32.76 2.059 42.822 2.093 ;
     RECT  153.9 2.021 154.962 2.093 ;
     RECT  75.744 2.029 119.934 2.101 ;
     RECT  120.78 1.364 121.986 2.101 ;
     RECT  122.76 1.997 149.922 2.101 ;
     RECT  43.776 2.011 74.862 2.107 ;
     RECT  75.636 2.101 149.922 2.107 ;
     RECT  33.66 2.093 42.822 2.129 ;
     RECT  32.76 2.093 32.778 2.143 ;
     RECT  41.652 2.129 42.822 2.143 ;
     RECT  150.732 1.997 153.054 2.143 ;
     RECT  153.9 2.093 154.746 2.143 ;
     RECT  158.544 2.045 158.742 2.143 ;
     RECT  160.992 2.011 161.082 2.143 ;
     RECT  41.652 2.143 43.005 2.255 ;
     RECT  21.315 2.143 21.405 2.299 ;
     RECT  41.868 2.255 43.005 2.347 ;
     RECT  43.776 2.107 149.922 2.347 ;
     RECT  33.66 2.129 40.662 2.363 ;
     RECT  2.415 2.143 2.505 2.413 ;
     RECT  5.115 2.143 5.205 2.413 ;
     RECT  7.815 2.143 7.905 2.413 ;
     RECT  10.515 2.143 10.605 2.413 ;
     RECT  13.215 2.143 13.305 2.413 ;
     RECT  15.915 2.143 16.005 2.413 ;
     RECT  18.615 2.143 18.705 2.413 ;
     RECT  24.015 2.143 24.105 2.413 ;
     RECT  26.715 2.143 26.805 2.413 ;
     RECT  29.415 2.011 29.61 2.413 ;
     RECT  158.544 2.143 159.105 2.413 ;
     RECT  159.876 1.675 160.146 2.413 ;
     RECT  160.992 2.143 161.805 2.413 ;
     RECT  172.515 2.143 172.605 2.413 ;
     RECT  175.215 2.143 175.305 2.413 ;
     RECT  177.915 2.143 178.005 2.413 ;
     RECT  180.615 2.143 180.705 2.413 ;
     RECT  183.315 2.143 183.405 2.413 ;
     RECT  186.015 2.143 186.105 2.413 ;
     RECT  26.715 2.413 26.997 2.443 ;
     RECT  29.415 2.413 29.697 2.443 ;
     RECT  41.868 2.347 149.922 2.477 ;
     RECT  37.368 2.363 40.662 2.525 ;
     RECT  22.932 1.771 23.13 2.539 ;
     RECT  26.715 2.443 27.09 2.539 ;
     RECT  30.78 2.011 30.834 2.539 ;
     RECT  26.64 2.539 27.09 2.561 ;
     RECT  41.868 2.477 148.878 2.561 ;
     RECT  33.66 2.363 36.522 2.621 ;
     RECT  111.672 2.561 148.878 2.633 ;
     RECT  21.315 2.299 21.654 2.669 ;
     RECT  22.824 2.539 23.13 2.669 ;
     RECT  26.64 2.561 26.997 2.669 ;
     RECT  30.6 2.539 30.942 2.669 ;
     RECT  34.452 2.621 36.522 2.669 ;
     RECT  111.672 2.633 148.842 2.795 ;
     RECT  41.868 2.561 110.934 2.813 ;
     RECT  26.676 2.669 26.997 2.861 ;
     RECT  158.544 2.413 160.146 2.861 ;
     RECT  160.992 2.413 161.997 2.875 ;
     RECT  150.732 2.143 154.746 2.903 ;
     RECT  29.415 2.443 29.79 2.923 ;
     RECT  43.92 2.813 110.934 2.939 ;
     RECT  32.115 2.143 32.778 3.019 ;
     RECT  160.992 2.875 162.486 3.019 ;
     RECT  163.656 1.723 165.186 3.019 ;
     RECT  33.66 2.621 33.678 3.029 ;
     RECT  37.515 2.525 40.662 3.029 ;
     RECT  171.36 1.445 171.378 3.029 ;
     RECT  31.824 3.019 32.778 3.065 ;
     RECT  160.992 3.019 165.186 3.101 ;
     RECT  163.008 3.101 165.186 3.115 ;
     RECT  165.924 1.049 167.562 3.115 ;
     RECT  163.008 3.115 167.562 3.137 ;
     RECT  37.515 3.029 40.59 3.149 ;
     RECT  43.92 2.939 109.602 3.209 ;
     RECT  169.776 0.125 170.406 3.209 ;
     RECT  37.515 3.149 38.034 3.259 ;
     RECT  24.015 2.413 24.297 3.271 ;
     RECT  30.744 2.669 30.906 3.299 ;
     RECT  22.932 2.669 23.13 3.335 ;
     RECT  29.415 2.923 29.898 3.335 ;
     RECT  169.815 3.209 170.406 3.335 ;
     RECT  23.904 3.271 24.297 3.341 ;
     RECT  30.78 3.299 30.906 3.341 ;
     RECT  46.62 3.209 109.602 3.341 ;
     RECT  30.78 3.341 30.798 3.371 ;
     RECT  110.34 2.939 110.934 3.403 ;
     RECT  111.672 2.795 148.77 3.403 ;
     RECT  163.008 3.137 163.026 3.407 ;
     RECT  37.404 3.259 38.034 3.479 ;
     RECT  43.92 3.209 45.897 3.581 ;
     RECT  37.404 3.479 37.962 3.595 ;
     RECT  37.224 3.595 37.962 3.629 ;
     RECT  37.224 3.629 37.89 3.641 ;
     RECT  46.656 3.341 109.602 3.641 ;
     RECT  152.46 2.903 154.746 3.641 ;
     RECT  38.808 3.149 40.59 3.677 ;
     RECT  46.692 3.641 109.602 3.685 ;
     RECT  110.34 3.403 148.77 3.685 ;
     RECT  150.732 2.903 151.686 3.713 ;
     RECT  39.708 3.677 40.59 3.725 ;
     RECT  149.616 2.477 149.922 3.811 ;
     RECT  41.868 2.813 43.197 3.847 ;
     RECT  150.732 3.713 151.578 3.875 ;
     RECT  163.836 3.137 167.562 3.875 ;
     RECT  150.732 3.875 151.506 3.911 ;
     RECT  165.888 3.875 165.942 3.947 ;
     RECT  38.808 3.677 38.898 3.979 ;
     RECT  166.752 3.875 167.562 3.983 ;
     RECT  154.728 3.641 154.746 4.019 ;
     RECT  41.868 3.847 43.398 4.109 ;
     RECT  37.515 3.641 37.89 4.157 ;
     RECT  166.752 3.983 167.397 4.157 ;
     RECT  149.58 3.811 149.922 4.217 ;
     RECT  44.136 3.581 45.897 4.253 ;
     RECT  46.692 3.685 148.806 4.261 ;
     RECT  149.58 4.217 149.634 4.261 ;
     RECT  23.076 3.335 23.13 4.363 ;
     RECT  152.46 3.641 153.897 4.363 ;
     RECT  160.992 3.101 161.997 4.363 ;
     RECT  41.868 4.109 43.362 4.445 ;
     RECT  42.84 4.445 43.362 4.451 ;
     RECT  22.824 4.363 23.13 4.493 ;
     RECT  30.888 4.363 30.906 4.493 ;
     RECT  38.772 3.979 38.898 4.493 ;
     RECT  46.692 4.261 149.634 4.523 ;
     RECT  41.868 4.445 42.102 4.541 ;
     RECT  111.672 4.523 149.634 4.559 ;
     RECT  149.58 4.559 149.634 4.649 ;
     RECT  46.692 4.523 110.934 4.685 ;
     RECT  46.692 4.685 110.826 4.721 ;
     RECT  111.672 4.559 148.626 4.721 ;
     RECT  47.916 4.721 110.826 4.757 ;
     RECT  111.672 4.721 148.518 4.757 ;
     RECT  44.136 4.253 44.154 4.793 ;
     RECT  46.944 4.721 47.178 4.793 ;
     RECT  160.992 4.363 162.486 4.829 ;
     RECT  46.944 4.793 47.106 4.955 ;
     RECT  152.46 4.363 154.494 4.973 ;
     RECT  42.915 4.451 43.362 4.991 ;
     RECT  46.944 4.955 47.034 4.991 ;
     RECT  47.016 4.991 47.034 5.027 ;
     RECT  152.46 4.973 153.897 5.099 ;
     RECT  47.916 4.757 54.918 5.189 ;
     RECT  48.168 5.189 54.918 5.309 ;
     RECT  48.315 5.309 54.918 5.357 ;
     RECT  41.868 4.541 41.886 5.369 ;
     RECT  48.315 5.357 54.81 5.369 ;
     RECT  38.772 5.275 38.79 5.405 ;
     RECT  39.708 3.725 40.497 5.495 ;
     RECT  48.315 5.369 54.774 5.531 ;
     RECT  111.672 4.757 148.497 5.567 ;
     RECT  45.036 4.253 45.897 5.597 ;
     RECT  134.28 5.567 148.497 5.639 ;
     RECT  55.872 4.757 110.826 5.755 ;
     RECT  111.672 5.567 133.218 5.755 ;
     RECT  163.836 3.875 165.006 5.765 ;
     RECT  152.928 5.099 153.897 5.837 ;
     RECT  55.872 5.755 133.218 5.845 ;
     RECT  150.732 3.911 151.197 5.873 ;
     RECT  149.616 4.649 149.634 5.909 ;
     RECT  134.532 5.639 148.497 6.035 ;
     RECT  134.532 6.035 146.358 6.071 ;
     RECT  49.356 5.531 54.774 6.151 ;
     RECT  55.548 5.845 133.218 6.151 ;
     RECT  49.356 6.151 133.218 6.269 ;
     RECT  48.315 5.531 48.597 6.283 ;
     RECT  49.356 6.269 54.774 6.283 ;
     RECT  23.076 4.493 23.13 6.341 ;
     RECT  55.548 6.269 133.218 6.341 ;
     RECT  147.132 6.035 148.497 6.341 ;
     RECT  168.948 1.553 168.966 6.413 ;
     RECT  147.636 6.341 148.497 6.575 ;
     RECT  56.304 6.341 133.218 6.647 ;
     RECT  48.315 6.283 54.774 6.653 ;
     RECT  56.304 6.647 119.502 6.653 ;
     RECT  56.304 6.653 111.546 6.683 ;
     RECT  112.536 6.653 119.502 6.683 ;
     RECT  109.548 6.683 111.546 6.749 ;
     RECT  109.764 6.749 111.546 6.809 ;
     RECT  112.536 6.683 119.322 6.845 ;
     RECT  134.64 6.071 146.358 6.859 ;
     RECT  153.615 5.837 153.897 6.859 ;
     RECT  160.992 4.829 161.997 6.859 ;
     RECT  134.64 6.859 146.61 6.989 ;
     RECT  153.615 6.859 154.602 6.989 ;
     RECT  160.992 6.859 162.594 6.989 ;
     RECT  120.528 6.647 133.218 7.123 ;
     RECT  109.98 6.809 111.546 7.133 ;
     RECT  153.615 6.989 154.494 7.181 ;
     RECT  160.992 6.989 162.486 7.181 ;
     RECT  34.452 2.669 36.198 7.223 ;
     RECT  134.64 6.989 146.574 7.229 ;
     RECT  165.924 3.947 165.942 7.493 ;
     RECT  120.528 7.123 133.902 7.529 ;
     RECT  56.304 6.683 108.414 7.591 ;
     RECT  38.772 7.483 38.79 7.661 ;
     RECT  160.992 7.181 161.997 8.033 ;
     RECT  56.304 7.591 108.81 8.041 ;
     RECT  55.548 6.341 55.566 8.251 ;
     RECT  56.304 8.041 108.846 8.251 ;
     RECT  55.548 8.251 108.846 8.465 ;
     RECT  161.064 8.033 161.997 8.537 ;
     RECT  49.356 6.653 54.774 8.683 ;
     RECT  55.548 8.465 108.198 8.683 ;
     RECT  134.64 7.229 146.358 8.683 ;
     RECT  153.615 7.181 153.897 8.683 ;
     RECT  161.715 8.537 161.997 8.683 ;
     RECT  112.536 6.845 117.774 8.807 ;
     RECT  112.572 8.807 117.774 9.085 ;
     RECT  118.515 6.845 119.322 9.085 ;
     RECT  134.64 8.683 146.502 9.211 ;
     RECT  153.615 8.683 154.494 9.211 ;
     RECT  30.78 9.211 30.798 9.341 ;
     RECT  134.64 9.211 146.574 9.341 ;
     RECT  153.615 9.211 154.566 9.341 ;
     RECT  161.715 8.683 162.486 9.341 ;
     RECT  164.415 5.765 165.006 9.341 ;
     RECT  158.724 2.861 160.146 9.347 ;
     RECT  109.98 7.133 111.474 9.391 ;
     RECT  112.572 9.085 119.322 9.533 ;
     RECT  23.076 6.341 23.094 9.545 ;
     RECT  36.18 7.223 36.198 9.689 ;
     RECT  49.356 8.683 108.198 9.821 ;
     RECT  109.98 9.391 111.834 10.021 ;
     RECT  112.572 9.533 119.178 10.021 ;
     RECT  37.515 4.157 37.797 10.027 ;
     RECT  45.615 5.597 45.897 10.027 ;
     RECT  37.515 10.027 37.89 10.157 ;
     RECT  38.772 9.211 38.79 10.157 ;
     RECT  45.615 10.027 45.99 10.157 ;
     RECT  46.764 9.211 46.782 10.157 ;
     RECT  55.548 9.821 108.198 10.589 ;
     RECT  120.528 7.529 132.426 10.741 ;
     RECT  134.64 9.341 146.358 10.843 ;
     RECT  153.615 9.341 153.897 10.843 ;
     RECT  134.64 10.843 146.502 10.973 ;
     RECT  153.615 10.843 154.494 10.973 ;
     RECT  155.88 2.021 157.014 11.003 ;
     RECT  109.98 10.021 119.178 11.137 ;
     RECT  49.356 9.821 54.774 11.179 ;
     RECT  55.548 10.589 107.997 11.179 ;
     RECT  109.548 11.137 119.178 11.309 ;
     RECT  49.356 11.179 107.997 11.371 ;
     RECT  34.452 7.223 35.097 11.435 ;
     RECT  120.204 10.741 132.426 11.911 ;
     RECT  133.2 7.529 133.902 11.911 ;
     RECT  155.88 11.003 156.87 12.119 ;
     RECT  111.42 11.309 119.178 12.289 ;
     RECT  120.204 11.911 133.902 12.289 ;
     RECT  134.64 10.973 146.358 12.289 ;
     RECT  37.515 10.157 37.797 12.523 ;
     RECT  45.615 10.157 45.897 12.523 ;
     RECT  37.515 12.523 37.89 12.653 ;
     RECT  45.615 12.523 45.99 12.653 ;
     RECT  111.42 12.289 146.358 12.659 ;
     RECT  109.548 11.309 110.697 12.865 ;
     RECT  49.356 11.371 108.27 13.037 ;
     RECT  160.128 9.347 160.146 13.469 ;
     RECT  38.772 12.523 38.79 13.661 ;
     RECT  46.764 12.523 46.782 13.661 ;
     RECT  49.356 13.037 54.774 13.867 ;
     RECT  55.548 13.037 108.27 13.867 ;
     RECT  133.2 12.659 146.358 13.973 ;
     RECT  140.115 13.973 146.358 14.347 ;
     RECT  153.615 10.973 153.897 14.347 ;
     RECT  153.615 14.347 153.99 14.443 ;
     RECT  140.115 14.347 146.61 14.477 ;
     RECT  140.115 14.477 146.502 14.549 ;
     RECT  142.815 14.549 146.502 14.669 ;
     RECT  153.615 14.443 154.098 14.669 ;
     RECT  49.356 13.867 108.27 14.717 ;
     RECT  49.356 14.717 103.05 14.813 ;
     RECT  158.724 9.347 159.297 14.945 ;
     RECT  32.115 3.065 32.778 14.981 ;
     RECT  155.88 12.119 156.597 15.449 ;
     RECT  109.008 12.865 110.697 16.027 ;
     RECT  111.42 12.659 132.426 16.027 ;
     RECT  142.815 14.669 146.358 16.027 ;
     RECT  153.615 14.669 153.897 16.027 ;
     RECT  142.815 16.027 146.61 16.157 ;
     RECT  153.615 16.027 154.602 16.157 ;
     RECT  142.815 16.157 146.502 16.301 ;
     RECT  153.615 16.157 154.494 16.301 ;
     RECT  109.008 16.027 132.426 16.835 ;
     RECT  55.548 14.813 103.05 17.741 ;
     RECT  49.356 14.813 54.774 27.671 ;
     RECT  49.464 27.671 54.774 28.211 ;
     RECT  55.548 17.741 73.134 28.759 ;
     RECT  73.944 17.741 103.05 28.759 ;
     RECT  49.68 28.211 54.774 29.363 ;
     RECT  109.008 16.835 132.297 29.939 ;
     RECT  55.548 28.759 103.05 31.109 ;
     RECT  133.2 13.973 139.158 31.109 ;
     RECT  49.68 29.363 52.974 31.649 ;
     RECT  133.2 31.109 138.906 31.649 ;
     RECT  49.824 31.649 52.974 31.685 ;
     RECT  109.008 29.939 127.962 31.685 ;
     RECT  133.2 31.649 138.87 32.225 ;
     RECT  52.92 31.685 52.974 32.261 ;
     RECT  129.315 29.939 132.297 32.431 ;
     RECT  49.824 31.685 52.146 32.801 ;
     RECT  133.2 32.225 138.222 32.837 ;
     RECT  82.8 31.109 103.05 33.341 ;
     RECT  129.168 32.431 132.297 33.421 ;
     RECT  129.024 33.421 132.297 33.619 ;
     RECT  55.548 31.109 81.954 33.647 ;
     RECT  128.952 33.619 132.297 33.655 ;
     RECT  53.715 29.363 54.774 33.917 ;
     RECT  109.008 31.685 127.782 33.925 ;
     RECT  128.88 33.655 132.297 33.925 ;
     RECT  52.92 32.261 52.938 33.953 ;
     RECT  82.8 33.341 102.726 34.195 ;
     RECT  103.824 14.717 108.27 34.195 ;
     RECT  109.008 33.925 132.297 34.195 ;
     RECT  74.448 33.647 81.954 34.231 ;
     RECT  82.692 34.195 102.726 34.231 ;
     RECT  103.824 34.195 132.297 34.321 ;
     RECT  142.815 16.301 146.358 34.457 ;
     RECT  133.884 32.837 138.222 34.465 ;
     RECT  50.436 32.801 52.146 34.529 ;
     RECT  74.448 34.231 102.726 34.591 ;
     RECT  140.115 14.549 142.038 34.619 ;
     RECT  133.452 34.465 138.222 34.699 ;
     RECT  133.308 34.699 138.222 34.763 ;
     RECT  74.412 34.591 102.726 34.771 ;
     RECT  103.5 34.321 132.297 34.771 ;
     RECT  133.884 34.763 138.222 34.771 ;
     RECT  142.815 34.457 146.142 34.799 ;
     RECT  55.548 33.647 73.638 34.861 ;
     RECT  74.412 34.771 132.297 34.861 ;
     RECT  55.548 34.861 132.297 34.889 ;
     RECT  52.128 34.529 52.146 35.033 ;
     RECT  133.884 34.771 138.438 35.033 ;
     RECT  109.116 34.889 132.297 35.041 ;
     RECT  142.815 34.799 145.797 35.069 ;
     RECT  109.116 35.041 132.39 35.311 ;
     RECT  50.436 34.529 51.354 35.537 ;
     RECT  133.884 35.033 138.258 35.581 ;
     RECT  55.548 34.889 108.342 35.815 ;
     RECT  109.116 35.311 133.002 35.815 ;
     RECT  133.812 35.581 138.258 36.121 ;
     RECT  53.715 33.917 54.558 36.149 ;
     RECT  133.812 36.121 138.294 36.419 ;
     RECT  55.548 35.815 133.002 36.617 ;
     RECT  142.815 35.069 143.766 36.689 ;
     RECT  56.124 36.617 133.002 36.859 ;
     RECT  133.812 36.419 138.258 36.859 ;
     RECT  51.015 35.537 51.354 37.229 ;
     RECT  144.504 35.069 145.797 37.391 ;
     RECT  144.612 37.391 145.797 37.499 ;
     RECT  144.612 37.499 144.63 37.697 ;
     RECT  141.588 34.619 142.038 37.769 ;
     RECT  56.124 36.859 138.258 37.963 ;
     RECT  55.98 37.963 138.258 38.003 ;
     RECT  56.376 38.003 138.258 38.011 ;
     RECT  56.376 38.011 138.438 38.101 ;
     RECT  141.588 37.769 141.606 38.309 ;
     RECT  56.376 38.101 138.51 38.551 ;
     RECT  56.376 38.551 138.69 39.451 ;
     RECT  56.304 39.451 138.69 39.721 ;
     RECT  55.908 39.721 138.69 39.793 ;
     RECT  55.872 39.793 138.69 39.865 ;
     RECT  55.872 39.865 138.798 39.901 ;
     RECT  55.476 39.901 138.798 40.261 ;
     RECT  55.08 40.261 138.798 40.441 ;
     RECT  54.864 40.441 138.798 40.559 ;
     RECT  2.415 2.413 2.697 40.787 ;
     RECT  5.115 2.413 5.397 40.787 ;
     RECT  7.815 2.413 8.097 40.787 ;
     RECT  10.515 2.413 10.797 40.787 ;
     RECT  13.215 2.413 13.497 40.787 ;
     RECT  15.915 2.413 16.197 40.787 ;
     RECT  18.615 2.413 18.897 40.787 ;
     RECT  21.315 2.669 21.597 40.787 ;
     RECT  24.015 3.341 24.297 40.787 ;
     RECT  26.715 2.861 26.997 40.787 ;
     RECT  29.415 3.335 29.697 40.787 ;
     RECT  32.115 14.981 32.397 40.787 ;
     RECT  34.815 11.435 35.097 40.787 ;
     RECT  37.515 12.653 37.797 40.787 ;
     RECT  40.215 5.495 40.497 40.787 ;
     RECT  42.915 4.991 43.197 40.787 ;
     RECT  45.615 12.653 45.897 40.787 ;
     RECT  48.315 6.653 48.597 40.787 ;
     RECT  51.015 37.229 51.297 40.787 ;
     RECT  53.715 36.149 53.997 40.787 ;
     RECT  140.115 34.619 140.397 40.787 ;
     RECT  142.815 36.689 143.097 40.787 ;
     RECT  145.515 37.499 145.797 40.787 ;
     RECT  148.215 6.575 148.497 40.787 ;
     RECT  150.915 5.873 151.197 40.787 ;
     RECT  153.615 16.301 153.897 40.787 ;
     RECT  156.315 15.449 156.597 40.787 ;
     RECT  159.015 14.945 159.297 40.787 ;
     RECT  161.715 9.341 161.997 40.787 ;
     RECT  164.415 9.341 164.697 40.787 ;
     RECT  167.115 4.157 167.397 40.787 ;
     RECT  169.815 3.335 170.097 40.787 ;
     RECT  172.515 2.413 172.797 40.787 ;
     RECT  175.215 2.413 175.497 40.787 ;
     RECT  177.915 2.413 178.197 40.787 ;
     RECT  180.615 2.413 180.897 40.787 ;
     RECT  183.315 2.413 183.597 40.787 ;
     RECT  186.015 2.413 186.297 40.787 ;
     RECT  55.008 40.559 138.762 40.829 ;
     RECT  55.224 40.829 59.205 40.865 ;
     RECT  99.54 40.829 100.566 40.877 ;
     RECT  101.484 40.829 105.534 40.877 ;
     RECT  68.976 40.829 81.306 40.901 ;
     RECT  82.224 40.829 84.546 40.901 ;
     RECT  91.008 40.829 94.662 40.901 ;
     RECT  101.484 40.877 103.05 40.901 ;
     RECT  106.632 40.829 108.234 40.901 ;
     RECT  109.044 40.829 111.474 40.901 ;
     RECT  112.752 40.829 114.822 40.901 ;
     RECT  117.396 40.829 124.902 40.901 ;
     RECT  125.748 40.829 137.862 40.925 ;
     RECT  59.94 40.829 60.066 40.937 ;
     RECT  65.484 40.829 67.305 40.937 ;
     RECT  69.804 40.901 81.306 40.937 ;
     RECT  85.392 40.829 87.93 40.937 ;
     RECT  125.748 40.925 137.505 40.937 ;
     RECT  96.912 40.829 97.434 40.973 ;
     RECT  99.54 40.877 99.954 40.973 ;
     RECT  114.516 40.901 114.606 40.973 ;
     RECT  117.396 40.901 122.022 40.973 ;
     RECT  59.94 40.937 59.958 41.009 ;
     RECT  65.484 40.937 66.438 41.009 ;
     RECT  69.804 40.937 74.034 41.009 ;
     RECT  75.06 40.937 79.506 41.009 ;
     RECT  80.715 40.937 81.306 41.009 ;
     RECT  82.224 40.901 84.186 41.009 ;
     RECT  88.776 40.829 90.018 41.009 ;
     RECT  91.008 40.901 91.605 41.009 ;
     RECT  92.916 40.901 94.662 41.009 ;
     RECT  98.388 40.829 98.622 41.009 ;
     RECT  101.484 40.901 102.618 41.009 ;
     RECT  103.86 40.877 105.534 41.009 ;
     RECT  106.92 40.901 108.234 41.009 ;
     RECT  109.044 40.901 111.114 41.009 ;
     RECT  117.684 40.973 122.022 41.009 ;
     RECT  122.796 40.901 124.902 41.009 ;
     RECT  131.436 40.937 137.505 41.009 ;
     RECT  62.64 40.829 63.126 41.021 ;
     RECT  68.976 40.901 68.994 41.021 ;
     RECT  72.108 41.009 72.774 41.021 ;
     RECT  74.016 41.009 74.034 41.021 ;
     RECT  75.204 41.009 78.822 41.021 ;
     RECT  93.312 41.009 94.662 41.021 ;
     RECT  106.92 41.009 106.938 41.021 ;
     RECT  109.512 41.009 110.754 41.021 ;
     RECT  112.752 40.901 113.778 41.021 ;
     RECT  115.704 40.829 116.55 41.021 ;
     RECT  117.828 41.009 122.022 41.021 ;
     RECT  122.904 41.009 124.902 41.021 ;
     RECT  125.748 40.937 130.158 41.021 ;
     RECT  131.436 41.009 132.105 41.021 ;
     RECT  2.415 40.787 2.505 41.057 ;
     RECT  5.115 40.787 5.205 41.057 ;
     RECT  7.815 40.787 7.905 41.057 ;
     RECT  10.515 40.787 10.605 41.057 ;
     RECT  13.215 40.787 13.305 41.057 ;
     RECT  15.915 40.787 16.005 41.057 ;
     RECT  18.615 40.787 18.705 41.057 ;
     RECT  21.315 40.787 21.405 41.057 ;
     RECT  24.015 40.787 24.105 41.057 ;
     RECT  26.715 40.787 26.805 41.057 ;
     RECT  29.415 40.787 29.505 41.057 ;
     RECT  32.115 40.787 32.205 41.057 ;
     RECT  34.815 40.787 34.905 41.057 ;
     RECT  37.515 40.787 37.605 41.057 ;
     RECT  40.215 40.787 40.305 41.057 ;
     RECT  42.915 40.787 43.005 41.057 ;
     RECT  45.615 40.787 45.705 41.057 ;
     RECT  48.315 40.787 48.405 41.057 ;
     RECT  51.015 40.787 51.105 41.057 ;
     RECT  53.715 40.787 53.805 41.057 ;
     RECT  55.404 40.865 59.205 41.057 ;
     RECT  61.776 40.829 61.905 41.057 ;
     RECT  67.215 40.937 67.305 41.057 ;
     RECT  69.915 41.009 70.578 41.057 ;
     RECT  72.615 41.021 72.774 41.057 ;
     RECT  78.015 41.021 78.822 41.057 ;
     RECT  80.715 41.009 80.805 41.057 ;
     RECT  88.815 41.009 90.018 41.057 ;
     RECT  91.296 41.009 91.605 41.057 ;
     RECT  94.215 41.021 94.662 41.057 ;
     RECT  96.915 40.973 97.434 41.057 ;
     RECT  99.615 40.973 99.954 41.057 ;
     RECT  102.204 41.009 102.405 41.057 ;
     RECT  107.715 41.009 107.805 41.057 ;
     RECT  113.115 41.021 113.778 41.057 ;
     RECT  117.828 41.021 119.934 41.057 ;
     RECT  121.104 41.021 121.305 41.057 ;
     RECT  132.015 41.021 132.105 41.057 ;
     RECT  135.864 41.009 137.505 41.057 ;
     RECT  140.115 40.787 140.205 41.057 ;
     RECT  142.815 40.787 142.905 41.057 ;
     RECT  145.515 40.787 145.605 41.057 ;
     RECT  148.215 40.787 148.305 41.057 ;
     RECT  150.915 40.787 151.005 41.057 ;
     RECT  153.615 40.787 153.705 41.057 ;
     RECT  156.315 40.787 156.405 41.057 ;
     RECT  159.015 40.787 159.105 41.057 ;
     RECT  161.715 40.787 161.805 41.057 ;
     RECT  164.415 40.787 164.505 41.057 ;
     RECT  167.115 40.787 167.205 41.057 ;
     RECT  169.815 40.787 169.905 41.057 ;
     RECT  172.515 40.787 172.605 41.057 ;
     RECT  175.215 40.787 175.305 41.057 ;
     RECT  177.915 40.787 178.005 41.057 ;
     RECT  180.615 40.787 180.705 41.057 ;
     RECT  183.315 40.787 183.405 41.057 ;
     RECT  186.015 40.787 186.105 41.057 ;
     RECT  65.484 41.009 66.294 41.069 ;
     RECT  75.204 41.021 77.022 41.069 ;
     RECT  78.372 41.057 78.822 41.165 ;
     RECT  85.392 40.937 87.138 41.165 ;
     RECT  89.172 41.057 90.018 41.165 ;
     RECT  94.608 41.057 94.662 41.165 ;
     RECT  99.936 41.057 99.954 41.165 ;
     RECT  103.86 41.009 105.354 41.165 ;
     RECT  110.196 41.021 110.754 41.165 ;
     RECT  113.256 41.057 113.778 41.165 ;
     RECT  115.776 41.021 116.55 41.165 ;
     RECT  123.48 41.021 124.758 41.165 ;
     RECT  133.02 41.009 135.09 41.165 ;
     RECT  55.404 41.057 59.094 41.213 ;
     RECT  61.776 41.057 61.794 41.213 ;
     RECT  64.332 40.829 64.674 41.213 ;
     RECT  72.756 41.057 72.774 41.213 ;
     RECT  75.204 41.069 76.986 41.213 ;
     RECT  83.304 41.009 84.114 41.213 ;
     RECT  97.344 41.057 97.434 41.213 ;
     RECT  103.86 41.165 105.174 41.213 ;
     RECT  115.776 41.165 115.794 41.213 ;
     RECT  129.276 41.021 130.158 41.213 ;
     RECT  135.864 41.057 137.394 41.213 ;
     RECT  91.296 41.057 91.314 41.261 ;
     RECT  126.396 41.021 127.422 41.261 ;
     RECT  70.308 41.057 70.578 41.597 ;
     RECT  78.804 41.165 78.822 41.597 ;
     RECT  89.568 41.165 90.018 41.597 ;
     RECT  93.312 41.021 93.33 41.597 ;
     RECT  97.344 41.213 97.362 41.597 ;
     RECT  103.86 41.213 104.526 41.597 ;
     RECT  117.828 41.057 118.098 41.597 ;
     RECT  121.104 41.057 121.122 41.597 ;
     RECT  123.48 41.165 123.894 41.597 ;
     RECT  133.02 41.165 134.262 41.597 ;
     RECT  135.864 41.213 136.818 41.597 ;
     RECT  55.404 41.213 58.482 41.645 ;
     RECT  75.672 41.213 76.986 41.645 ;
     RECT  102.204 41.057 102.222 41.645 ;
     RECT  123.876 41.597 123.894 41.645 ;
     RECT  127.368 41.261 127.422 41.645 ;
     RECT  129.744 41.213 130.158 41.645 ;
     RECT  136.008 41.597 136.818 41.645 ;
     RECT  55.44 41.645 58.482 41.741 ;
     RECT  95.832 40.829 95.85 41.885 ;
     RECT  55.908 41.741 58.482 42.173 ;
     RECT  66.276 41.069 66.294 42.173 ;
     RECT  76.968 41.645 76.986 42.173 ;
     RECT  82.224 41.009 82.242 42.173 ;
     RECT  85.392 41.165 85.986 42.173 ;
     RECT  87.912 40.937 87.93 42.173 ;
     RECT  98.388 41.009 98.406 42.173 ;
     RECT  110.196 41.165 110.214 42.173 ;
     RECT  116.532 41.165 116.55 42.173 ;
     RECT  118.08 41.597 118.098 42.173 ;
     RECT  118.908 41.057 119.934 42.173 ;
     RECT  124.74 41.165 124.758 42.173 ;
     RECT  129.744 41.645 130.086 42.173 ;
     RECT  136.008 41.645 136.674 42.173 ;
     RECT  55.908 42.173 57.762 42.221 ;
     RECT  83.556 41.213 84.114 42.221 ;
     RECT  85.932 42.173 85.986 42.221 ;
     RECT  104.508 41.597 104.526 42.221 ;
     RECT  113.256 41.165 113.706 42.221 ;
     RECT  55.908 42.221 56.142 42.269 ;
     RECT  85.932 42.221 85.95 42.797 ;
     RECT  94.644 41.165 94.662 42.893 ;
     RECT  83.7 42.221 84.114 43.037 ;
     RECT  56.124 42.269 56.142 43.085 ;
     RECT  57.312 42.221 57.762 43.085 ;
     RECT  64.332 41.213 64.35 43.085 ;
     RECT  65.484 41.069 65.502 43.085 ;
     RECT  67.68 42.811 67.698 43.085 ;
     RECT  70.308 41.597 70.326 43.085 ;
     RECT  75.672 41.645 75.69 43.085 ;
     RECT  83.7 43.037 84.042 43.085 ;
     RECT  87.12 41.165 87.138 43.085 ;
     RECT  89.568 41.597 89.586 43.085 ;
     RECT  113.688 42.221 113.706 43.085 ;
     RECT  114.516 40.973 114.534 43.085 ;
     RECT  118.908 42.173 118.926 43.085 ;
     RECT  126.396 41.261 126.414 43.085 ;
     RECT  127.404 41.645 127.422 43.085 ;
     RECT  128.52 41.021 128.538 43.085 ;
     RECT  133.092 41.597 134.262 43.085 ;
    LAYER M4 ;
     RECT  0.06 22.896 0.227 22.92 ;
     RECT  0.181 36.576 2.408 36.6 ;
     RECT  2.408 2.148 2.512 41.052 ;
     RECT  2.512 2.418 2.704 40.782 ;
     RECT  2.704 36.576 5.108 36.6 ;
     RECT  5.108 2.148 5.212 41.052 ;
     RECT  5.212 2.418 5.404 40.782 ;
     RECT  5.404 36.576 7.808 36.6 ;
     RECT  7.808 2.148 7.912 41.052 ;
     RECT  7.912 2.418 8.104 40.782 ;
     RECT  8.104 36.576 10.508 36.6 ;
     RECT  10.508 2.148 10.612 41.052 ;
     RECT  10.612 2.418 10.804 40.782 ;
     RECT  10.804 36.576 13.208 36.6 ;
     RECT  13.208 2.148 13.312 41.052 ;
     RECT  13.312 2.418 13.504 40.782 ;
     RECT  13.504 36.576 15.908 36.6 ;
     RECT  15.908 2.148 16.012 41.052 ;
     RECT  16.012 2.418 16.204 40.782 ;
     RECT  16.204 36.576 18.608 36.6 ;
     RECT  18.608 2.148 18.712 41.052 ;
     RECT  18.712 2.418 18.904 40.782 ;
     RECT  18.904 2.418 19.861 3.624 ;
     RECT  19.861 1.536 20.005 3.624 ;
     RECT  20.005 1.44 20.149 3.624 ;
     RECT  20.149 0.864 21.301 3.624 ;
     RECT  21.301 0.24 21.308 3.624 ;
     RECT  18.904 36.576 21.308 36.6 ;
     RECT  21.308 0.24 21.412 41.052 ;
     RECT  21.412 0.24 21.604 40.782 ;
     RECT  21.604 0.24 22.021 4.68 ;
     RECT  22.021 0.096 24.008 4.68 ;
     RECT  21.604 6 24.008 6.024 ;
     RECT  21.604 36.576 24.008 36.6 ;
     RECT  24.008 0.096 24.112 41.052 ;
     RECT  24.112 0.096 24.304 40.782 ;
     RECT  24.304 0.096 26.708 6.024 ;
     RECT  24.304 36.576 26.708 36.6 ;
     RECT  26.708 0.096 26.809 41.052 ;
     RECT  26.809 0.048 26.812 41.052 ;
     RECT  26.812 0.048 27.004 40.782 ;
     RECT  27.004 0.048 29.408 6.024 ;
     RECT  29.269 9.312 29.408 9.336 ;
     RECT  27.004 36.576 29.408 36.6 ;
     RECT  29.408 0.048 29.512 41.052 ;
     RECT  29.512 0.048 29.704 40.782 ;
     RECT  29.704 0.048 29.939 8.232 ;
     RECT  29.704 9.216 30.809 9.624 ;
     RECT  29.704 11.184 31.237 11.208 ;
     RECT  30.949 13.392 31.381 13.416 ;
     RECT  31.381 12.768 31.525 13.416 ;
     RECT  30.809 9.312 31.813 9.624 ;
     RECT  31.525 12.768 31.957 13.656 ;
     RECT  29.939 0.048 32.108 6.024 ;
     RECT  29.939 7.392 32.108 8.232 ;
     RECT  31.813 9.312 32.108 10.152 ;
     RECT  31.237 11.184 32.108 11.784 ;
     RECT  31.957 12.768 32.108 13.896 ;
     RECT  29.704 36.576 32.108 36.6 ;
     RECT  32.108 0.048 32.212 41.052 ;
     RECT  32.212 0.048 32.249 40.782 ;
     RECT  32.249 0.096 32.321 40.782 ;
     RECT  32.321 0.144 32.404 40.782 ;
     RECT  32.404 0.144 34.253 6.024 ;
     RECT  34.253 0.096 34.405 6.024 ;
     RECT  34.405 0.096 34.765 6.36 ;
     RECT  34.765 0.048 34.808 6.36 ;
     RECT  32.404 7.392 34.808 15.048 ;
     RECT  32.404 36.576 34.808 36.6 ;
     RECT  34.808 0.048 34.912 41.052 ;
     RECT  34.912 0.048 35.104 40.782 ;
     RECT  35.104 0.048 37.508 15.048 ;
     RECT  35.104 36.576 37.508 36.6 ;
     RECT  37.508 0.048 37.612 41.052 ;
     RECT  37.612 0.048 37.804 40.782 ;
     RECT  37.804 0.048 40.208 15.048 ;
     RECT  37.804 36.576 40.208 36.6 ;
     RECT  40.208 0.048 40.312 41.052 ;
     RECT  40.312 0.048 40.504 40.782 ;
     RECT  40.504 0.048 42.908 15.048 ;
     RECT  40.504 36.576 42.908 36.6 ;
     RECT  42.908 0.048 43.012 41.052 ;
     RECT  43.012 0.048 43.204 40.782 ;
     RECT  43.204 0.048 45.608 15.048 ;
     RECT  43.204 36.576 45.608 36.6 ;
     RECT  45.608 0.048 45.712 41.052 ;
     RECT  45.712 0.048 45.904 40.782 ;
     RECT  45.904 0.048 48.308 15.048 ;
     RECT  45.904 36.576 48.308 36.6 ;
     RECT  48.308 0.048 48.412 41.052 ;
     RECT  48.412 0.048 48.604 40.782 ;
     RECT  48.604 0.048 51.008 15.048 ;
     RECT  48.604 36.576 51.008 36.6 ;
     RECT  51.008 0.048 51.112 41.052 ;
     RECT  51.112 0.048 51.304 40.782 ;
     RECT  51.304 0.048 53.708 15.048 ;
     RECT  51.304 36.576 53.708 36.6 ;
     RECT  53.708 0.048 53.812 41.052 ;
     RECT  53.812 0.048 54.004 40.782 ;
     RECT  55.393 41.616 55.429 41.64 ;
     RECT  55.429 41.616 55.861 41.736 ;
     RECT  55.861 41.616 55.897 42.168 ;
     RECT  55.897 41.616 56.113 42.264 ;
     RECT  54.004 0.048 56.408 15.048 ;
     RECT  54.004 36.576 56.408 36.6 ;
     RECT  55.969 37.968 56.408 37.992 ;
     RECT  56.113 41.616 56.408 43.08 ;
     RECT  56.408 0.048 56.704 43.08 ;
     RECT  56.704 41.52 56.765 43.08 ;
     RECT  56.704 39.936 56.945 40.44 ;
     RECT  56.945 40.416 57.197 40.44 ;
     RECT  56.765 41.568 57.241 43.08 ;
     RECT  57.241 42.144 57.817 43.08 ;
     RECT  56.704 36.576 57.829 36.936 ;
     RECT  56.704 37.968 57.877 38.232 ;
     RECT  57.805 40.464 57.889 40.488 ;
     RECT  57.877 37.968 58.021 38.664 ;
     RECT  57.829 36.432 58.093 36.936 ;
     RECT  58.021 37.968 58.168 38.76 ;
     RECT  58.168 37.968 58.229 38.808 ;
     RECT  58.093 35.856 58.261 36.936 ;
     RECT  58.229 37.968 58.261 39.384 ;
     RECT  57.817 42.144 58.537 42.168 ;
     RECT  57.841 34.656 58.741 34.68 ;
     RECT  58.261 35.856 58.741 39.384 ;
     RECT  58.237 40.368 59.065 40.392 ;
     RECT  56.704 0.048 59.108 15.048 ;
     RECT  58.741 34.656 59.108 39.384 ;
     RECT  59.065 40.368 59.108 41.208 ;
     RECT  59.108 0.048 59.219 41.208 ;
     RECT  59.219 0.048 59.404 40.782 ;
     RECT  58.933 42.912 59.555 43.032 ;
     RECT  59.555 42.912 59.603 42.936 ;
     RECT  59.404 36.48 60.131 40.632 ;
     RECT  60.131 36.48 60.172 40.584 ;
     RECT  59.404 34.656 60.793 35.496 ;
     RECT  60.172 36.48 60.793 36.936 ;
     RECT  60.172 37.968 61.381 40.584 ;
     RECT  60.793 34.656 61.477 36.936 ;
     RECT  61.381 37.968 61.477 41.016 ;
     RECT  61.381 43.008 61.669 43.032 ;
     RECT  61.477 34.656 61.724 41.016 ;
     RECT  59.404 0.048 61.808 15.048 ;
     RECT  61.724 34.656 61.808 41.208 ;
     RECT  61.808 0.048 61.811 41.208 ;
     RECT  61.811 0.048 61.912 41.052 ;
     RECT  61.669 42.96 62.099 43.032 ;
     RECT  61.912 0.048 62.104 41.016 ;
     RECT  62.099 43.008 62.339 43.032 ;
     RECT  62.104 35.28 62.435 40.008 ;
     RECT  62.435 35.28 62.483 39.912 ;
     RECT  62.483 38.16 62.633 39.912 ;
     RECT  62.483 35.28 63.133 37.08 ;
     RECT  62.104 40.992 63.137 41.016 ;
     RECT  63.133 34.896 63.452 37.08 ;
     RECT  62.633 38.16 63.452 39.48 ;
     RECT  63.452 34.896 63.539 39.48 ;
     RECT  63.539 38.112 63.961 39.48 ;
     RECT  63.685 43.008 64.213 43.032 ;
     RECT  64.213 42.432 64.321 43.032 ;
     RECT  64.321 42.432 64.403 43.08 ;
     RECT  62.104 0.048 64.508 15.048 ;
     RECT  63.539 34.896 64.508 37.128 ;
     RECT  63.961 38.112 64.508 40.008 ;
     RECT  64.46 41.184 64.508 41.208 ;
     RECT  64.508 0.048 64.691 41.208 ;
     RECT  64.691 0.048 64.804 40.782 ;
     RECT  64.804 34.896 64.931 37.128 ;
     RECT  64.403 43.008 64.931 43.08 ;
     RECT  64.931 43.056 65.513 43.08 ;
     RECT  64.804 38.112 65.9 40.776 ;
     RECT  65.9 38.112 65.987 41.064 ;
     RECT  64.931 34.896 66.085 37.08 ;
     RECT  65.987 38.112 66.085 40.488 ;
     RECT  66.221 42.144 66.305 42.168 ;
     RECT  66.085 34.896 66.469 40.488 ;
     RECT  66.469 34.08 66.997 40.488 ;
     RECT  64.804 0.048 67.208 15.048 ;
     RECT  66.997 34.08 67.208 41.016 ;
     RECT  67.208 0.048 67.312 41.052 ;
     RECT  67.237 43.008 67.381 43.032 ;
     RECT  67.312 0.048 67.504 41.016 ;
     RECT  67.381 42.96 67.525 43.032 ;
     RECT  67.525 42.912 67.573 43.032 ;
     RECT  67.573 42.816 67.669 43.032 ;
     RECT  67.669 42.816 67.753 43.08 ;
     RECT  67.753 42.816 68.291 43.032 ;
     RECT  69.733 43.008 69.781 43.032 ;
     RECT  67.504 0.048 69.908 15.576 ;
     RECT  68.965 16.56 69.908 16.584 ;
     RECT  67.504 34.08 69.908 41.016 ;
     RECT  69.781 42.912 70.019 43.032 ;
     RECT  69.908 0.048 70.204 41.052 ;
     RECT  70.019 43.008 70.253 43.032 ;
     RECT  70.253 43.008 70.337 43.08 ;
     RECT  70.204 34.08 70.405 41.052 ;
     RECT  70.405 34.08 70.589 41.592 ;
     RECT  70.204 16.56 71.701 16.68 ;
     RECT  71.701 16.56 71.737 17.16 ;
     RECT  70.337 43.008 72.373 43.032 ;
     RECT  70.204 0.048 72.425 15.576 ;
     RECT  72.425 0.096 72.608 15.576 ;
     RECT  71.737 16.56 72.608 17.688 ;
     RECT  70.589 34.08 72.608 41.016 ;
     RECT  72.373 42.96 72.611 43.032 ;
     RECT  72.608 0.096 72.701 41.052 ;
     RECT  72.701 0.096 72.785 41.208 ;
     RECT  72.611 42.96 72.899 42.984 ;
     RECT  72.785 0.096 72.904 41.016 ;
     RECT  72.904 34.08 72.965 39.672 ;
     RECT  72.965 35.76 73.397 39.672 ;
     RECT  73.397 35.76 73.613 38.184 ;
     RECT  72.904 40.896 74.045 41.016 ;
     RECT  73.397 39.264 74.117 39.672 ;
     RECT  74.117 39.264 74.153 39.336 ;
     RECT  74.153 39.312 74.261 39.336 ;
     RECT  73.613 35.76 74.689 36.84 ;
     RECT  73.613 38.16 74.689 38.184 ;
     RECT  72.904 0.096 74.729 17.736 ;
     RECT  74.045 40.896 75.193 40.92 ;
     RECT  74.729 0.144 75.308 17.736 ;
     RECT  72.965 34.08 75.308 34.68 ;
     RECT  74.689 35.76 75.308 38.184 ;
     RECT  75.193 40.896 75.308 41.208 ;
     RECT  75.445 42.816 75.589 42.84 ;
     RECT  75.308 0.144 75.604 41.208 ;
     RECT  75.589 42.816 75.661 42.936 ;
     RECT  75.604 0.144 75.692 17.736 ;
     RECT  75.661 42.816 75.731 43.08 ;
     RECT  75.692 0.096 75.779 17.736 ;
     RECT  75.731 42.912 75.779 43.08 ;
     RECT  75.604 40.32 75.781 40.488 ;
     RECT  75.604 34.08 76.115 38.76 ;
     RECT  76.115 34.08 76.161 36.6 ;
     RECT  75.781 40.464 76.211 40.488 ;
     RECT  76.115 37.584 76.597 38.76 ;
     RECT  75.98 41.616 76.741 41.64 ;
     RECT  76.741 40.992 76.931 41.64 ;
     RECT  76.931 40.992 77.075 41.064 ;
     RECT  76.161 34.368 77.221 36.6 ;
     RECT  76.597 37.584 77.281 39.336 ;
     RECT  76.957 42.144 77.363 42.168 ;
     RECT  77.075 40.992 77.413 41.052 ;
     RECT  77.281 37.584 77.569 39.384 ;
     RECT  77.413 40.416 77.569 41.052 ;
     RECT  77.221 34.176 77.605 36.6 ;
     RECT  77.569 37.584 77.605 41.052 ;
     RECT  75.779 0.144 78.008 17.736 ;
     RECT  77.605 34.176 78.008 41.052 ;
     RECT  78.008 0.144 78.304 41.052 ;
     RECT  78.304 34.176 78.401 40.056 ;
     RECT  78.325 41.136 78.412 41.16 ;
     RECT  77.845 43.008 78.467 43.032 ;
     RECT  78.749 41.568 78.833 41.592 ;
     RECT  78.401 34.368 79.525 40.056 ;
     RECT  79.525 34.368 79.573 40.488 ;
     RECT  79.573 34.368 80.437 40.584 ;
     RECT  80.437 34.368 80.533 41.016 ;
     RECT  80.533 34.368 80.675 41.208 ;
     RECT  78.304 0.144 80.708 17.736 ;
     RECT  80.675 34.368 80.708 41.052 ;
     RECT  80.708 0.144 80.812 41.052 ;
     RECT  80.812 0.144 81.004 41.016 ;
     RECT  80.389 43.008 81.061 43.032 ;
     RECT  81.004 34.704 81.347 41.016 ;
     RECT  81.347 34.704 81.923 40.536 ;
     RECT  81.061 42.96 82.019 43.032 ;
     RECT  81.004 0.144 82.109 17.736 ;
     RECT  82.069 42.144 82.253 42.168 ;
     RECT  81.923 36.576 82.933 40.536 ;
     RECT  81.923 34.704 83.041 35.208 ;
     RECT  82.109 0.24 83.269 17.736 ;
     RECT  82.933 36.576 83.293 41.016 ;
     RECT  83.269 0.144 83.408 17.736 ;
     RECT  83.041 34.656 83.408 35.208 ;
     RECT  83.293 36.576 83.408 41.208 ;
     RECT  83.408 0.144 83.411 41.208 ;
     RECT  83.411 0.144 83.512 41.052 ;
     RECT  83.509 42.192 83.596 42.216 ;
     RECT  83.512 0.144 83.704 40.782 ;
     RECT  83.645 43.008 84.053 43.08 ;
     RECT  84.053 43.008 84.169 43.032 ;
     RECT  83.704 34.512 84.341 39.912 ;
     RECT  83.704 0.144 84.409 17.736 ;
     RECT  84.797 40.464 84.805 40.488 ;
     RECT  84.805 40.464 84.949 40.584 ;
     RECT  84.341 34.512 84.989 39.336 ;
     RECT  85.381 42.144 85.465 42.168 ;
     RECT  84.949 40.464 85.489 40.872 ;
     RECT  84.989 34.656 85.561 39.336 ;
     RECT  85.489 40.464 85.561 40.968 ;
     RECT  85.561 34.656 85.957 40.968 ;
     RECT  85.813 42.192 86.003 42.792 ;
     RECT  84.409 0.048 86.108 17.736 ;
     RECT  85.957 34.368 86.108 40.968 ;
     RECT  86.108 0.048 86.245 41.052 ;
     RECT  86.245 0.048 86.404 41.208 ;
     RECT  86.101 43.008 86.531 43.032 ;
     RECT  86.404 34.368 86.609 41.208 ;
     RECT  86.609 36.384 86.627 41.208 ;
     RECT  86.965 43.056 87.149 43.08 ;
     RECT  86.627 36.384 87.221 40.92 ;
     RECT  87.221 36.384 87.827 40.488 ;
     RECT  87.589 43.008 87.829 43.032 ;
     RECT  86.609 34.368 87.836 35.352 ;
     RECT  87.827 36.384 87.836 39.432 ;
     RECT  87.829 42.144 87.941 43.032 ;
     RECT  87.827 40.464 88.597 40.488 ;
     RECT  86.404 0.048 88.808 17.736 ;
     RECT  87.836 34.368 88.808 39.432 ;
     RECT  88.597 40.464 88.808 41.016 ;
     RECT  87.941 42.864 88.883 43.032 ;
     RECT  88.808 0.048 89.104 41.052 ;
     RECT  89.104 40.992 89.117 41.052 ;
     RECT  88.883 42.912 89.267 43.032 ;
     RECT  89.117 40.992 89.5 41.16 ;
     RECT  89.104 34.368 89.597 39.912 ;
     RECT  89.557 43.056 89.641 43.08 ;
     RECT  89.701 41.568 90.029 41.592 ;
     RECT  89.597 34.368 90.364 39.336 ;
     RECT  90.364 34.368 90.389 35.208 ;
     RECT  90.457 40.464 90.565 40.488 ;
     RECT  90.364 36.336 90.949 39.336 ;
     RECT  90.565 40.464 90.949 40.776 ;
     RECT  90.949 36.336 91.189 40.776 ;
     RECT  91.189 36.336 91.244 41.016 ;
     RECT  91.244 36.336 91.331 41.256 ;
     RECT  91.333 43.008 91.381 43.032 ;
     RECT  89.104 0.048 91.508 17.736 ;
     RECT  90.389 34.656 91.508 35.208 ;
     RECT  91.331 36.336 91.508 41.16 ;
     RECT  91.381 42.912 91.619 43.032 ;
     RECT  91.508 0.048 91.763 41.16 ;
     RECT  91.763 0.048 91.804 41.016 ;
     RECT  91.619 43.008 92.099 43.032 ;
     RECT  91.804 34.656 92.915 41.016 ;
     RECT  92.915 40.464 93.013 41.016 ;
     RECT  93.013 40.464 93.133 41.592 ;
     RECT  93.133 40.944 93.341 41.592 ;
     RECT  91.804 0.048 94.208 17.736 ;
     RECT  92.915 34.656 94.208 39.384 ;
     RECT  93.341 40.944 94.208 41.052 ;
     RECT  94.208 0.048 94.309 41.052 ;
     RECT  94.309 0.048 94.504 41.88 ;
     RECT  94.165 42.864 94.597 42.888 ;
     RECT  94.597 42.864 94.673 43.032 ;
     RECT  94.673 43.008 94.739 43.032 ;
     RECT  94.504 34.56 95.249 41.88 ;
     RECT  95.249 34.56 95.308 37.656 ;
     RECT  95.249 38.736 95.861 41.88 ;
     RECT  95.308 34.56 96.613 37.08 ;
     RECT  96.613 34.56 96.757 37.368 ;
     RECT  95.861 38.736 96.757 40.968 ;
     RECT  96.757 34.56 96.901 40.968 ;
     RECT  94.504 0.048 96.908 17.736 ;
     RECT  96.901 34.56 96.908 41.208 ;
     RECT  96.908 0.048 97.189 41.208 ;
     RECT  97.189 0.048 97.204 41.592 ;
     RECT  97.045 42.864 97.333 42.888 ;
     RECT  97.204 22.8 97.379 23.352 ;
     RECT  97.204 34.8 97.429 41.592 ;
     RECT  97.333 42.864 97.429 42.984 ;
     RECT  97.429 34.8 97.445 42.984 ;
     RECT  97.445 42.144 97.475 42.984 ;
     RECT  97.445 34.8 97.489 40.488 ;
     RECT  97.379 23.328 97.517 23.352 ;
     RECT  97.489 34.896 98.381 40.488 ;
     RECT  97.475 42.144 98.417 42.168 ;
     RECT  98.381 40.464 99.061 40.488 ;
     RECT  98.381 34.896 99.133 39.336 ;
     RECT  99.061 40.464 99.485 40.872 ;
     RECT  97.204 0.048 99.608 17.736 ;
     RECT  99.133 34.752 99.608 39.336 ;
     RECT  99.485 40.464 99.608 40.968 ;
     RECT  99.608 0.048 99.904 41.052 ;
     RECT  99.904 40.848 99.925 41.052 ;
     RECT  99.925 40.848 100.009 41.16 ;
     RECT  99.445 43.008 100.067 43.032 ;
     RECT  99.904 34.752 100.649 39.384 ;
     RECT  100.649 35.184 101.005 39.384 ;
     RECT  100.009 40.848 101.005 40.872 ;
     RECT  101.005 35.184 101.077 40.872 ;
     RECT  101.077 35.184 101.653 40.968 ;
     RECT  102.133 42.912 102.181 42.936 ;
     RECT  101.653 35.184 102.188 41.016 ;
     RECT  102.188 35.184 102.229 41.64 ;
     RECT  102.229 34.752 102.275 41.64 ;
     RECT  99.904 0.048 102.308 17.736 ;
     RECT  102.275 34.752 102.308 41.052 ;
     RECT  102.308 0.048 102.412 41.052 ;
     RECT  102.181 42.912 102.563 43.032 ;
     RECT  102.412 0.048 102.604 40.968 ;
     RECT  102.604 34.752 102.629 40.968 ;
     RECT  102.629 34.752 102.803 40.872 ;
     RECT  102.563 43.008 102.803 43.032 ;
     RECT  102.803 34.752 103.241 39.384 ;
     RECT  103.241 36.288 103.421 39.384 ;
     RECT  102.803 40.848 103.805 40.872 ;
     RECT  103.421 38.688 103.889 39.384 ;
     RECT  103.805 40.848 103.889 41.592 ;
     RECT  103.889 40.848 104.101 41.016 ;
     RECT  104.492 42.192 104.579 42.216 ;
     RECT  103.241 34.752 104.641 35.208 ;
     RECT  103.421 36.288 104.641 37.704 ;
     RECT  104.641 34.752 104.677 37.704 ;
     RECT  104.677 34.752 104.869 38.184 ;
     RECT  103.889 39.312 104.869 39.384 ;
     RECT  102.604 0.048 105.008 17.736 ;
     RECT  104.869 21.696 105.008 21.816 ;
     RECT  104.869 34.224 105.008 39.384 ;
     RECT  104.101 40.464 105.008 41.016 ;
     RECT  105.008 0.048 105.101 41.052 ;
     RECT  105.101 0.048 105.185 41.208 ;
     RECT  105.185 0.048 105.304 41.16 ;
     RECT  105.304 36.912 105.365 41.16 ;
     RECT  105.304 34.752 105.437 35.88 ;
     RECT  104.869 42.816 105.443 43.032 ;
     RECT  105.304 21.12 105.473 22.2 ;
     RECT  105.473 21.12 105.779 21.144 ;
     RECT  105.365 36.912 105.941 41.016 ;
     RECT  105.941 36.912 106.019 39.336 ;
     RECT  106.019 36.912 106.049 39.24 ;
     RECT  105.437 34.992 106.513 35.88 ;
     RECT  106.049 36.912 106.513 38.808 ;
     RECT  105.941 40.464 106.589 41.016 ;
     RECT  106.513 34.992 106.933 38.808 ;
     RECT  106.933 34.896 106.94 38.808 ;
     RECT  106.94 34.752 107.413 38.808 ;
     RECT  107.413 34.752 107.509 39.336 ;
     RECT  105.304 0.048 107.708 17.736 ;
     RECT  107.509 34.752 107.708 39.912 ;
     RECT  106.589 40.944 107.708 41.016 ;
     RECT  107.708 0.048 107.812 41.052 ;
     RECT  107.461 43.008 107.989 43.032 ;
     RECT  107.812 0.048 108.004 41.016 ;
     RECT  107.989 42.96 108.131 43.032 ;
     RECT  108.131 42.96 108.277 42.984 ;
     RECT  108.004 34.896 108.353 41.016 ;
     RECT  108.277 42.864 108.371 42.984 ;
     RECT  108.371 42.864 108.419 42.888 ;
     RECT  108.353 34.896 108.677 39.432 ;
     RECT  108.677 34.896 108.857 39.336 ;
     RECT  108.353 40.464 108.865 41.016 ;
     RECT  108.857 36.816 110.005 39.336 ;
     RECT  110.005 36.816 110.077 39.912 ;
     RECT  108.865 40.992 110.077 41.016 ;
     RECT  108.857 34.896 110.101 35.736 ;
     RECT  110.077 36.816 110.101 41.016 ;
     RECT  110.005 42.144 110.149 42.168 ;
     RECT  110.149 42.144 110.225 43.032 ;
     RECT  108.004 0.048 110.408 17.736 ;
     RECT  110.101 34.896 110.408 41.016 ;
     RECT  110.408 0.048 110.581 41.052 ;
     RECT  110.581 0.048 110.704 41.16 ;
     RECT  110.704 34.896 110.765 41.16 ;
     RECT  110.225 42.912 110.819 43.032 ;
     RECT  110.765 34.896 111.169 40.584 ;
     RECT  110.819 42.912 111.733 42.936 ;
     RECT  111.169 40.464 111.877 40.584 ;
     RECT  111.733 42.864 111.877 42.936 ;
     RECT  111.877 42.864 111.923 42.984 ;
     RECT  111.169 34.896 111.949 39.48 ;
     RECT  111.949 34.464 112.309 39.48 ;
     RECT  111.877 40.464 112.309 41.016 ;
     RECT  110.704 0.048 112.925 17.736 ;
     RECT  111.923 42.96 112.933 42.984 ;
     RECT  112.925 0.144 113.108 17.736 ;
     RECT  112.309 34.464 113.108 41.016 ;
     RECT  112.933 42.96 113.245 43.032 ;
     RECT  113.245 42.192 113.363 43.032 ;
     RECT  113.108 0.144 113.404 41.052 ;
     RECT  113.404 40.464 113.461 41.052 ;
     RECT  113.461 40.464 113.789 41.16 ;
     RECT  113.404 0.144 114.181 17.736 ;
     RECT  113.404 34.368 114.329 39.384 ;
     RECT  114.329 34.368 114.412 36.552 ;
     RECT  114.329 37.536 114.469 39.384 ;
     RECT  113.789 40.464 114.469 41.016 ;
     RECT  113.605 43.056 114.545 43.08 ;
     RECT  114.469 37.536 114.553 41.016 ;
     RECT  114.181 0.096 114.577 17.736 ;
     RECT  114.553 40.464 115.669 41.016 ;
     RECT  115.669 40.368 115.724 41.016 ;
     RECT  114.553 37.536 115.801 39.336 ;
     RECT  115.724 40.368 115.801 41.208 ;
     RECT  114.577 0.048 115.808 17.736 ;
     RECT  114.412 34.368 115.808 36.504 ;
     RECT  115.801 37.536 115.808 41.208 ;
     RECT  115.808 0.048 115.811 41.208 ;
     RECT  115.811 0.048 116.104 41.16 ;
     RECT  116.104 34.464 116.165 41.16 ;
     RECT  116.165 34.464 116.201 40.968 ;
     RECT  115.909 43.008 116.291 43.032 ;
     RECT  116.477 42.144 116.561 42.168 ;
     RECT  116.104 0.048 116.723 17.736 ;
     RECT  116.201 36.432 116.723 40.968 ;
     RECT  116.201 34.464 117.169 35.448 ;
     RECT  116.723 36.432 117.169 39.384 ;
     RECT  116.723 40.608 117.425 40.968 ;
     RECT  117.773 41.568 117.857 41.592 ;
     RECT  117.169 34.464 118.033 39.384 ;
     RECT  118.069 42.144 118.153 42.168 ;
     RECT  116.723 0.096 118.508 17.736 ;
     RECT  118.033 34.224 118.508 39.384 ;
     RECT  117.925 40.464 118.508 40.584 ;
     RECT  118.508 0.096 118.612 41.052 ;
     RECT  118.309 43.008 118.645 43.032 ;
     RECT  118.612 0.096 118.649 41.016 ;
     RECT  118.649 0.192 118.804 41.016 ;
     RECT  118.645 43.008 118.937 43.08 ;
     RECT  118.804 34.128 119.027 39.816 ;
     RECT  118.937 43.008 119.075 43.032 ;
     RECT  119.027 34.656 119.585 39.816 ;
     RECT  118.804 40.992 119.941 41.016 ;
     RECT  119.221 42.144 119.945 42.168 ;
     RECT  119.941 40.944 120.085 41.016 ;
     RECT  120.121 39.888 120.373 39.912 ;
     RECT  120.085 40.896 120.373 41.016 ;
     RECT  118.804 0.192 120.661 17.736 ;
     RECT  119.585 34.656 120.769 38.76 ;
     RECT  120.373 39.888 120.769 41.016 ;
     RECT  120.997 42.912 121.045 42.936 ;
     RECT  120.769 34.656 121.093 41.016 ;
     RECT  121.093 34.656 121.177 41.592 ;
     RECT  120.661 0.096 121.208 17.736 ;
     RECT  121.177 34.656 121.208 41.052 ;
     RECT  121.208 0.096 121.312 41.052 ;
     RECT  121.045 42.912 121.427 43.032 ;
     RECT  121.312 0.096 121.504 41.016 ;
     RECT  121.427 43.008 121.667 43.032 ;
     RECT  121.504 0.096 122.185 17.736 ;
     RECT  121.504 34.176 122.401 41.016 ;
     RECT  122.401 40.464 123.109 41.016 ;
     RECT  122.401 34.176 123.721 39.384 ;
     RECT  123.109 40.464 123.721 41.592 ;
     RECT  122.185 0.192 123.781 17.736 ;
     RECT  123.721 34.176 123.865 41.592 ;
     RECT  123.781 0.144 123.908 17.736 ;
     RECT  123.865 34.176 123.908 41.64 ;
     RECT  123.908 0.144 124.163 41.64 ;
     RECT  124.163 0.144 124.204 41.16 ;
     RECT  124.204 0.144 124.261 17.736 ;
     RECT  124.204 40.464 124.265 41.16 ;
     RECT  124.261 43.008 124.403 43.032 ;
     RECT  124.204 34.368 124.517 39.336 ;
     RECT  124.265 40.464 124.525 41.016 ;
     RECT  124.517 34.416 124.697 39.336 ;
     RECT  124.549 42.144 124.769 42.168 ;
     RECT  124.697 37.68 125.269 39.336 ;
     RECT  125.269 37.68 125.417 39.912 ;
     RECT  124.697 34.416 125.665 36.552 ;
     RECT  125.417 37.68 125.665 37.992 ;
     RECT  125.665 34.416 125.773 37.992 ;
     RECT  125.417 39.264 125.845 39.912 ;
     RECT  124.525 40.992 125.845 41.016 ;
     RECT  125.989 43.056 126.425 43.08 ;
     RECT  124.261 0.096 126.569 17.736 ;
     RECT  126.569 0.24 126.608 17.736 ;
     RECT  125.773 34.224 126.608 37.992 ;
     RECT  125.845 39.264 126.608 41.016 ;
     RECT  126.565 42.816 126.709 42.984 ;
     RECT  126.608 0.24 126.853 41.052 ;
     RECT  126.853 0.24 126.901 41.16 ;
     RECT  126.901 0.24 126.904 41.256 ;
     RECT  126.904 36.528 127.073 41.256 ;
     RECT  126.709 42.72 127.091 42.984 ;
     RECT  126.904 34.368 127.145 35.448 ;
     RECT  127.073 39.888 127.357 41.256 ;
     RECT  127.073 36.528 127.613 38.664 ;
     RECT  127.613 36.528 127.649 38.04 ;
     RECT  127.649 37.92 127.973 38.04 ;
     RECT  127.145 34.368 128.045 35.4 ;
     RECT  127.357 39.888 128.195 41.64 ;
     RECT  127.973 38.016 128.225 38.04 ;
     RECT  127.649 36.528 128.444 36.888 ;
     RECT  128.045 34.704 128.509 35.4 ;
     RECT  128.444 36.384 128.509 36.888 ;
     RECT  127.393 43.056 128.549 43.08 ;
     RECT  128.509 34.704 128.689 36.888 ;
     RECT  126.904 0.24 128.869 17.736 ;
     RECT  128.195 39.888 129.26 41.016 ;
     RECT  128.869 0.096 129.308 17.736 ;
     RECT  128.773 33.6 129.308 33.624 ;
     RECT  128.689 34.704 129.308 37.032 ;
     RECT  128.725 38.112 129.308 38.136 ;
     RECT  129.26 39.888 129.308 41.208 ;
     RECT  129.308 0.096 129.589 41.208 ;
     RECT  129.589 0.096 129.604 42.168 ;
     RECT  129.604 34.224 130.025 35.448 ;
     RECT  129.604 40.752 130.097 42.168 ;
     RECT  130.097 40.752 130.211 41.64 ;
     RECT  130.211 40.752 130.597 41.016 ;
     RECT  130.597 40.416 130.741 41.016 ;
     RECT  130.741 40.368 130.957 41.016 ;
     RECT  130.025 34.224 131.389 34.248 ;
     RECT  130.025 35.424 131.389 35.448 ;
     RECT  131.389 34.224 131.425 35.448 ;
     RECT  130.957 36.48 131.425 36.84 ;
     RECT  129.604 0.096 132.008 17.736 ;
     RECT  131.425 34.224 132.008 36.84 ;
     RECT  129.604 38.4 132.008 38.424 ;
     RECT  130.957 39.888 132.008 41.016 ;
     RECT  132.008 0.096 132.304 41.052 ;
     RECT  132.304 40.896 132.545 41.052 ;
     RECT  132.545 40.992 133.009 41.052 ;
     RECT  133.009 40.992 133.189 41.592 ;
     RECT  132.901 43.056 133.189 43.08 ;
     RECT  132.304 36 133.229 38.424 ;
     RECT  133.189 40.992 133.849 43.08 ;
     RECT  133.849 40.992 133.877 41.592 ;
     RECT  133.849 42.912 134.273 43.08 ;
     RECT  133.909 39.648 134.341 39.672 ;
     RECT  133.877 40.992 134.341 41.16 ;
     RECT  133.229 36 134.449 37.608 ;
     RECT  132.304 0.096 134.531 17.736 ;
     RECT  134.341 39.648 134.533 41.16 ;
     RECT  134.449 35.904 134.593 37.608 ;
     RECT  134.273 42.912 134.675 43.032 ;
     RECT  134.531 0.144 134.708 17.736 ;
     RECT  132.304 34.704 134.708 34.728 ;
     RECT  134.593 35.808 134.708 37.608 ;
     RECT  134.533 38.688 134.708 41.16 ;
     RECT  134.708 0.144 134.713 41.16 ;
     RECT  134.675 42.912 134.819 42.936 ;
     RECT  134.713 0.192 135.004 41.16 ;
     RECT  135.004 38.688 135.065 41.16 ;
     RECT  135.004 0.192 135.107 17.736 ;
     RECT  135.065 38.784 135.539 41.16 ;
     RECT  135.004 35.808 135.58 37.608 ;
     RECT  135.539 40.752 135.637 41.16 ;
     RECT  135.637 40.752 135.781 41.592 ;
     RECT  135.58 35.808 136.181 36.552 ;
     RECT  136.181 35.808 136.361 36.456 ;
     RECT  135.539 38.784 136.361 39.336 ;
     RECT  136.361 35.808 136.397 35.832 ;
     RECT  136.361 39.264 136.645 39.336 ;
     RECT  135.781 40.752 136.645 42.168 ;
     RECT  135.58 37.584 136.681 37.608 ;
     RECT  136.645 39.264 136.685 42.168 ;
     RECT  135.107 0.864 136.861 17.736 ;
     RECT  136.685 39.264 136.979 41.64 ;
     RECT  136.861 0.24 137.408 17.736 ;
     RECT  135.004 34.704 137.408 34.728 ;
     RECT  136.681 37.584 137.408 37.992 ;
     RECT  136.979 39.264 137.408 41.208 ;
     RECT  137.408 0.24 137.449 41.208 ;
     RECT  137.449 0.24 137.512 41.052 ;
     RECT  137.512 0.24 137.701 40.92 ;
     RECT  137.701 0.192 137.704 40.92 ;
     RECT  137.704 0.192 137.842 17.736 ;
     RECT  137.704 40.896 137.873 40.92 ;
     RECT  137.842 0.048 140.108 17.736 ;
     RECT  140.108 0.048 140.212 41.052 ;
     RECT  140.212 0.048 140.404 40.782 ;
     RECT  140.404 0.048 142.808 17.736 ;
     RECT  142.808 0.048 142.912 41.052 ;
     RECT  142.912 0.048 143.104 40.782 ;
     RECT  143.104 0.048 144.749 4.776 ;
     RECT  144.749 0.096 144.781 4.776 ;
     RECT  143.104 5.76 144.781 17.736 ;
     RECT  144.781 0.096 145.508 17.736 ;
     RECT  145.508 0.096 145.612 41.052 ;
     RECT  145.612 0.096 145.804 40.782 ;
     RECT  145.804 0.096 146.225 17.736 ;
     RECT  146.225 0.096 146.473 4.968 ;
     RECT  146.473 0.048 148.169 4.968 ;
     RECT  148.169 0.096 148.208 4.968 ;
     RECT  146.225 6.672 148.208 17.736 ;
     RECT  148.208 0.096 148.312 41.052 ;
     RECT  148.312 0.096 148.504 40.782 ;
     RECT  148.504 0.096 150.509 4.968 ;
     RECT  150.509 0.144 150.908 4.968 ;
     RECT  148.504 6.672 150.908 17.736 ;
     RECT  150.908 0.144 151.012 41.052 ;
     RECT  151.012 0.144 151.204 40.782 ;
     RECT  151.204 0.144 151.621 4.968 ;
     RECT  151.621 0.096 153.608 4.968 ;
     RECT  151.204 6.672 153.608 17.736 ;
     RECT  153.608 0.096 153.712 41.052 ;
     RECT  153.712 0.096 153.904 40.782 ;
     RECT  153.904 0.096 154.501 4.968 ;
     RECT  154.501 0.048 156.308 4.968 ;
     RECT  153.904 6.672 156.308 17.736 ;
     RECT  156.308 0.048 156.412 41.052 ;
     RECT  156.412 0.048 156.604 40.782 ;
     RECT  156.604 0.048 157.241 4.968 ;
     RECT  156.604 6.672 157.427 17.736 ;
     RECT  157.241 0.096 159.008 4.968 ;
     RECT  157.427 6.672 159.008 10.344 ;
     RECT  157.427 11.424 159.008 17.736 ;
     RECT  159.008 0.096 159.112 41.052 ;
     RECT  159.112 0.096 159.304 40.782 ;
     RECT  159.304 12 159.491 17.736 ;
     RECT  159.491 12.576 160.019 17.736 ;
     RECT  160.019 13.152 160.307 17.736 ;
     RECT  159.304 0.096 161.708 4.968 ;
     RECT  159.304 6.672 161.708 9.384 ;
     RECT  160.307 13.152 161.708 13.176 ;
     RECT  160.307 14.448 161.708 17.736 ;
     RECT  161.708 0.096 161.812 41.052 ;
     RECT  161.812 0.096 162.004 40.782 ;
     RECT  162.004 15.984 162.179 16.008 ;
     RECT  162.004 0.096 162.497 4.824 ;
     RECT  162.004 13.152 162.611 13.176 ;
     RECT  162.004 6.672 162.755 9.336 ;
     RECT  162.004 17.088 162.899 17.736 ;
     RECT  162.899 17.712 163.043 17.736 ;
     RECT  162.497 0.096 164.408 4.728 ;
     RECT  162.755 6.864 164.408 9.336 ;
     RECT  164.408 0.096 164.512 41.052 ;
     RECT  164.512 0.096 164.704 40.782 ;
     RECT  164.704 6.864 165.017 9.336 ;
     RECT  164.704 0.096 167.108 4.68 ;
     RECT  165.017 6.864 167.108 8.808 ;
     RECT  167.108 0.096 167.212 41.052 ;
     RECT  167.212 0.096 167.404 40.782 ;
     RECT  167.404 6.864 167.795 7.176 ;
     RECT  167.404 0.096 168.227 3.144 ;
     RECT  168.227 1.872 169.667 3.144 ;
     RECT  169.667 2.016 169.808 3.144 ;
     RECT  167.404 4.224 169.808 4.488 ;
     RECT  167.795 6.912 169.808 7.176 ;
     RECT  169.808 2.016 169.912 41.052 ;
     RECT  169.912 2.016 169.985 40.782 ;
     RECT  169.985 2.418 170.104 40.782 ;
     RECT  170.104 6.912 170.387 7.176 ;
     RECT  170.387 6.912 170.531 6.936 ;
     RECT  170.104 2.592 170.963 3.144 ;
     RECT  168.227 0.096 171.251 0.888 ;
     RECT  171.308 1.104 171.395 1.128 ;
     RECT  171.251 0.096 171.865 0.12 ;
     RECT  170.963 3.12 172.508 3.144 ;
     RECT  170.104 4.224 172.508 4.392 ;
     RECT  172.508 2.148 172.612 41.052 ;
     RECT  172.612 2.418 172.804 40.782 ;
     RECT  175.208 2.148 175.312 41.052 ;
     RECT  175.312 2.418 175.504 40.782 ;
     RECT  177.908 2.148 178.012 41.052 ;
     RECT  178.012 2.418 178.204 40.782 ;
     RECT  180.608 2.148 180.712 41.052 ;
     RECT  180.712 2.418 180.904 40.782 ;
     RECT  183.308 2.148 183.412 41.052 ;
     RECT  183.412 2.418 183.604 40.782 ;
     RECT  186.008 2.148 186.112 41.052 ;
     RECT  186.112 2.418 186.304 40.782 ;
    LAYER M5 ;
     RECT  29.52 0.016 57.048 0.085 ;
     RECT  115.92 0.016 143.448 0.085 ;
     RECT  58.32 0.016 114.648 0.131 ;
     RECT  19.152 0.016 28.248 0.275 ;
     RECT  59.472 0.131 114.648 0.899 ;
     RECT  115.824 0.085 143.448 1.139 ;
     RECT  144.72 0.016 172.248 1.139 ;
     RECT  61.2 0.899 114.648 1.667 ;
     RECT  144.72 1.139 170.952 1.763 ;
     RECT  59.472 0.899 60.216 1.811 ;
     RECT  85.104 1.667 114.648 1.811 ;
     RECT  147.6 1.763 151.224 1.811 ;
     RECT  19.152 0.275 28.104 1.859 ;
     RECT  116.064 1.139 143.448 1.859 ;
     RECT  61.2 1.667 83.976 1.907 ;
     RECT  148.2 1.811 151.224 1.907 ;
     RECT  19.152 1.859 27.96 1.955 ;
     RECT  19.152 1.955 27.816 2.003 ;
     RECT  150.9 1.907 151.224 2.003 ;
     RECT  59.472 1.811 59.928 2.005 ;
     RECT  19.152 2.003 27.672 2.137 ;
     RECT  116.064 1.859 125.16 2.137 ;
     RECT  171.936 1.139 172.248 2.137 ;
     RECT  126.6 1.859 143.448 2.147 ;
     RECT  2.4 2.137 2.52 2.151 ;
     RECT  5.1 2.137 5.22 2.151 ;
     RECT  7.8 2.137 7.92 2.151 ;
     RECT  10.5 2.137 10.62 2.151 ;
     RECT  13.2 2.137 13.32 2.151 ;
     RECT  15.9 2.137 16.02 2.151 ;
     RECT  171.936 2.137 172.62 2.151 ;
     RECT  175.2 2.137 175.32 2.151 ;
     RECT  177.9 2.137 178.02 2.151 ;
     RECT  180.6 2.137 180.72 2.151 ;
     RECT  183.3 2.137 183.42 2.151 ;
     RECT  186 2.137 186.12 2.151 ;
     RECT  152.352 1.763 170.952 2.291 ;
     RECT  61.2 1.907 65.256 2.293 ;
     RECT  18.6 2.137 27.672 2.339 ;
     RECT  126.6 2.147 130.056 2.339 ;
     RECT  131.184 2.147 143.448 2.339 ;
     RECT  148.2 1.907 149.928 2.387 ;
     RECT  149.904 2.387 149.928 2.435 ;
     RECT  61.008 2.293 65.256 2.531 ;
     RECT  155.808 2.291 170.952 2.531 ;
     RECT  18.6 2.339 22.776 2.579 ;
     RECT  164.016 2.531 170.952 2.579 ;
     RECT  61.2 2.531 65.256 2.627 ;
     RECT  169.344 2.579 170.952 2.627 ;
     RECT  21.168 2.579 22.776 2.819 ;
     RECT  85.104 1.811 114.504 2.819 ;
     RECT  169.344 2.627 170.52 2.867 ;
     RECT  85.536 2.819 114.504 2.915 ;
     RECT  164.016 2.579 168.36 2.915 ;
     RECT  106.992 2.915 114.504 2.917 ;
     RECT  115.8 2.137 125.16 2.917 ;
     RECT  29.28 0.085 57.048 3.059 ;
     RECT  106.992 2.917 125.16 3.059 ;
     RECT  152.352 2.291 154.824 3.059 ;
     RECT  23.76 2.339 27.672 3.107 ;
     RECT  155.808 2.531 163.032 3.155 ;
     RECT  171.936 2.151 172.812 3.155 ;
     RECT  129.3 2.339 130.056 3.203 ;
     RECT  24 3.107 27.672 3.395 ;
     RECT  66.24 1.907 83.976 3.395 ;
     RECT  29.28 3.059 45.912 3.443 ;
     RECT  61.68 2.627 65.256 3.443 ;
     RECT  85.536 2.915 105.72 3.443 ;
     RECT  131.904 2.339 143.448 3.443 ;
     RECT  144.72 1.763 146.328 3.443 ;
     RECT  131.904 3.443 140.412 3.493 ;
     RECT  126.6 2.339 128.328 3.541 ;
     RECT  129.3 3.203 130.008 3.541 ;
     RECT  115.2 3.059 125.16 3.587 ;
     RECT  61.68 3.443 65.112 3.589 ;
     RECT  18.6 2.579 19.752 3.635 ;
     RECT  40.2 3.443 45.912 3.635 ;
     RECT  85.536 3.443 105.576 3.635 ;
     RECT  141.552 3.443 143.448 3.635 ;
     RECT  152.352 3.059 154.68 3.683 ;
     RECT  142.272 3.635 143.448 3.685 ;
     RECT  144.72 3.443 145.944 3.685 ;
     RECT  66.24 3.395 83.832 3.731 ;
     RECT  126.6 3.541 130.008 3.779 ;
     RECT  60.96 3.589 65.112 3.875 ;
     RECT  131.76 3.493 140.412 3.875 ;
     RECT  142.272 3.685 145.944 3.923 ;
     RECT  152.64 3.683 154.68 3.923 ;
     RECT  144.768 3.923 145.944 3.971 ;
     RECT  61.8 3.875 65.112 4.019 ;
     RECT  66.24 3.731 83.712 4.019 ;
     RECT  106.992 3.059 114.072 4.019 ;
     RECT  142.272 3.923 143.448 4.019 ;
     RECT  148.2 2.387 148.776 4.019 ;
     RECT  145.296 3.971 145.944 4.067 ;
     RECT  72.432 4.019 83.712 4.115 ;
     RECT  24 3.395 27.012 4.163 ;
     RECT  46.944 3.059 57.048 4.163 ;
     RECT  24 4.163 25.656 4.259 ;
     RECT  40.2 3.635 43.32 4.259 ;
     RECT  58.992 2.005 59.928 4.259 ;
     RECT  66.24 4.019 67.608 4.259 ;
     RECT  118.5 3.587 125.16 4.259 ;
     RECT  172.08 3.155 172.812 4.259 ;
     RECT  21.3 2.819 22.776 4.403 ;
     RECT  172.224 4.259 172.812 4.403 ;
     RECT  24 4.259 24.792 4.451 ;
     RECT  45.024 3.635 45.912 4.451 ;
     RECT  121.104 4.259 125.16 4.451 ;
     RECT  47.184 4.163 57.048 4.499 ;
     RECT  21.3 4.403 22.488 4.547 ;
     RECT  118.5 4.259 120.12 4.547 ;
     RECT  137.088 3.875 140.412 4.547 ;
     RECT  145.344 4.067 145.944 4.547 ;
     RECT  66.24 4.259 67.512 4.595 ;
     RECT  72.432 4.115 73.032 4.595 ;
     RECT  139.68 4.547 140.412 4.595 ;
     RECT  142.272 4.019 143.112 4.595 ;
     RECT  47.952 4.499 57.048 4.597 ;
     RECT  21.3 4.547 22.344 4.691 ;
     RECT  41.904 4.259 43.32 4.691 ;
     RECT  61.8 4.019 64.92 4.691 ;
     RECT  145.344 4.547 145.812 4.691 ;
     RECT  164.256 2.915 168.36 4.739 ;
     RECT  41.904 4.691 43.212 4.787 ;
     RECT  107.136 4.019 114.072 4.787 ;
     RECT  126.6 3.779 128.184 4.787 ;
     RECT  131.76 3.875 135.816 4.789 ;
     RECT  129.3 3.779 130.008 4.883 ;
     RECT  131.28 4.789 135.816 4.933 ;
     RECT  137.088 4.547 138.408 4.933 ;
     RECT  29.28 3.443 39.192 4.979 ;
     RECT  131.28 4.933 138.408 4.979 ;
     RECT  86.1 3.635 105.576 5.027 ;
     RECT  131.904 4.979 138.408 5.027 ;
     RECT  47.952 4.597 57.768 5.123 ;
     RECT  136.752 5.027 138.408 5.123 ;
     RECT  115.2 3.587 117.144 5.125 ;
     RECT  118.5 4.547 119.4 5.125 ;
     RECT  101.088 5.027 105.576 5.171 ;
     RECT  107.136 4.787 113.412 5.171 ;
     RECT  121.104 4.451 124.872 5.171 ;
     RECT  42.336 4.787 43.212 5.219 ;
     RECT  24 4.451 24.504 5.267 ;
     RECT  115.2 5.125 119.4 5.363 ;
     RECT  29.28 4.979 38.76 5.411 ;
     RECT  29.28 5.411 38.184 5.507 ;
     RECT  47.952 5.123 57.096 5.555 ;
     RECT  49.68 5.555 57.096 5.603 ;
     RECT  118.5 5.363 119.4 5.603 ;
     RECT  63.936 4.691 64.92 5.653 ;
     RECT  66.048 4.981 66.072 5.653 ;
     RECT  115.2 5.363 117.144 5.699 ;
     RECT  86.1 5.027 100.008 5.747 ;
     RECT  101.232 5.171 105.576 5.747 ;
     RECT  107.136 5.171 108.216 5.747 ;
     RECT  128.16 4.787 128.184 5.747 ;
     RECT  109.44 5.171 113.412 5.795 ;
     RECT  72.6 4.595 73.032 5.845 ;
     RECT  74.016 4.115 83.712 5.845 ;
     RECT  49.68 5.603 55.32 5.891 ;
     RECT  21.3 4.691 21.768 6.035 ;
     RECT  137.4 5.123 138.408 6.035 ;
     RECT  49.824 5.891 55.32 6.083 ;
     RECT  72.6 5.845 83.712 6.131 ;
     RECT  121.2 5.171 124.872 6.131 ;
     RECT  79.488 6.131 83.712 6.179 ;
     RECT  104.544 5.747 105.576 6.229 ;
     RECT  72.6 6.131 78.312 6.275 ;
     RECT  86.1 5.747 95.64 6.275 ;
     RECT  56.4 5.603 57.096 6.277 ;
     RECT  88.128 6.275 95.64 6.323 ;
     RECT  101.232 5.747 103.128 6.323 ;
     RECT  109.44 5.795 110.712 6.323 ;
     RECT  56.4 6.277 57.144 6.419 ;
     RECT  131.904 5.027 135.24 6.419 ;
     RECT  61.8 4.691 62.232 6.469 ;
     RECT  47.952 5.555 48.612 6.611 ;
     RECT  59.1 4.259 59.928 6.659 ;
     RECT  61.8 6.469 62.76 6.661 ;
     RECT  86.1 6.275 86.412 6.661 ;
     RECT  61.8 6.661 62.856 6.851 ;
     RECT  85.344 6.661 86.412 6.851 ;
     RECT  104.544 6.229 106.248 6.851 ;
     RECT  79.92 6.179 83.712 6.899 ;
     RECT  104.832 6.851 106.248 6.899 ;
     RECT  110.304 6.323 110.712 6.899 ;
     RECT  68.832 4.019 71.448 6.947 ;
     RECT  169.8 2.867 170.52 6.947 ;
     RECT  80.448 6.899 83.712 6.995 ;
     RECT  91.5 6.323 92.904 7.091 ;
     RECT  101.664 6.323 103.128 7.139 ;
     RECT  164.4 4.739 168.36 7.139 ;
     RECT  169.8 6.947 170.376 7.187 ;
     RECT  63.936 5.653 66.072 7.235 ;
     RECT  152.64 3.923 153.912 7.235 ;
     RECT  68.832 6.947 71.064 7.475 ;
     RECT  107.7 5.747 108.216 7.475 ;
     RECT  88.128 6.323 90.024 7.523 ;
     RECT  74.016 6.275 78.312 7.571 ;
     RECT  80.592 6.995 83.712 7.667 ;
     RECT  61.8 6.851 62.808 7.763 ;
     RECT  123.9 6.131 124.872 7.763 ;
     RECT  86.1 6.851 86.412 7.813 ;
     RECT  76.896 7.571 78.312 7.859 ;
     RECT  29.28 5.507 37.812 7.955 ;
     RECT  86.1 7.813 86.52 7.955 ;
     RECT  69.9 7.475 71.064 7.957 ;
     RECT  72.6 6.275 72.912 7.957 ;
     RECT  36.72 7.955 37.812 8.003 ;
     RECT  74.016 7.571 75.72 8.003 ;
     RECT  77.856 7.859 78.312 8.003 ;
     RECT  88.8 7.523 90.024 8.003 ;
     RECT  164.4 7.139 167.412 8.051 ;
     RECT  92.832 7.091 92.904 8.099 ;
     RECT  123.9 7.763 124.584 8.243 ;
     RECT  121.2 6.131 122.424 8.291 ;
     RECT  49.824 6.083 55.032 8.579 ;
     RECT  68.832 7.475 68.856 8.579 ;
     RECT  101.808 7.139 103.128 8.579 ;
     RECT  115.2 5.699 116.112 8.579 ;
     RECT  164.4 8.051 165.768 8.579 ;
     RECT  164.4 8.579 165.624 8.771 ;
     RECT  166.752 8.051 167.412 8.819 ;
     RECT  80.7 7.667 83.712 8.867 ;
     RECT  40.2 4.259 40.92 9.107 ;
     RECT  74.88 8.003 75.72 9.155 ;
     RECT  75.024 9.155 75.612 9.203 ;
     RECT  29.28 7.955 35.736 9.347 ;
     RECT  121.2 8.291 122.28 9.347 ;
     RECT  129.3 4.883 129.912 9.395 ;
     RECT  64.5 7.235 66.072 9.539 ;
     RECT  83.088 8.867 83.712 9.539 ;
     RECT  40.2 9.107 40.632 9.587 ;
     RECT  50.256 8.579 55.032 9.587 ;
     RECT  115.344 8.579 116.112 9.587 ;
     RECT  121.2 9.347 121.608 9.587 ;
     RECT  101.952 8.579 103.128 9.827 ;
     RECT  102.192 9.827 103.128 9.875 ;
     RECT  102.3 9.875 103.128 10.259 ;
     RECT  96.72 5.747 100.008 10.307 ;
     RECT  29.4 9.347 35.736 10.355 ;
     RECT  64.5 9.539 65.4 10.451 ;
     RECT  131.904 6.419 135.012 10.451 ;
     RECT  96.72 10.307 99.912 10.837 ;
     RECT  50.256 9.587 54.456 10.979 ;
     RECT  117.12 5.699 117.144 11.027 ;
     RECT  92.832 8.099 92.856 11.075 ;
     RECT  102.3 10.259 103.08 11.077 ;
     RECT  96.624 10.837 99.912 11.171 ;
     RECT  29.4 10.355 35.112 11.219 ;
     RECT  80.7 8.867 81.816 11.219 ;
     RECT  102.144 11.077 103.08 11.219 ;
     RECT  132 10.451 135.012 11.507 ;
     RECT  104.88 6.899 106.248 11.555 ;
     RECT  96.72 11.171 99.912 11.603 ;
     RECT  132 11.507 133.512 11.987 ;
     RECT  96.9 11.603 99.912 12.083 ;
     RECT  91.5 7.091 91.812 12.277 ;
     RECT  133.488 11.987 133.512 12.371 ;
     RECT  78 8.003 78.312 12.517 ;
     RECT  30.96 11.219 35.112 12.563 ;
     RECT  96.9 12.083 97.8 12.563 ;
     RECT  50.544 10.979 54.456 12.565 ;
     RECT  86.1 7.955 86.412 12.757 ;
     RECT  50.544 12.565 54.744 12.899 ;
     RECT  86.1 12.757 86.664 13.091 ;
     RECT  98.784 12.083 99.912 13.139 ;
     RECT  102.3 11.219 103.08 13.139 ;
     RECT  78 12.517 78.408 13.141 ;
     RECT  90.624 12.277 91.812 13.283 ;
     RECT  33.696 12.563 35.112 13.331 ;
     RECT  78 13.141 78.792 13.331 ;
     RECT  30.96 12.563 32.712 13.427 ;
     RECT  31.536 13.427 32.712 13.667 ;
     RECT  31.968 13.667 32.712 13.907 ;
     RECT  50.688 12.899 54.744 13.907 ;
     RECT  33.696 13.331 33.72 13.955 ;
     RECT  50.688 13.907 54.456 14.195 ;
     RECT  50.688 14.195 52.152 14.243 ;
     RECT  91.5 13.283 91.812 14.293 ;
     RECT  121.2 9.587 121.512 14.341 ;
     RECT  156.192 3.155 163.032 14.387 ;
     RECT  75.3 9.203 75.612 14.389 ;
     RECT  78 13.331 78.696 14.389 ;
     RECT  113.1 5.795 113.412 14.437 ;
     RECT  129.3 9.395 129.612 14.437 ;
     RECT  137.4 6.035 137.712 14.437 ;
     RECT  145.5 4.691 145.812 14.437 ;
     RECT  121.2 14.341 121.608 14.483 ;
     RECT  78 14.389 78.792 14.531 ;
     RECT  113.1 14.437 114.6 14.675 ;
     RECT  129.3 14.437 130.584 14.675 ;
     RECT  137.4 14.437 138.552 14.675 ;
     RECT  145.5 14.437 145.992 14.675 ;
     RECT  51 14.243 52.152 14.723 ;
     RECT  53.7 14.195 54.456 14.723 ;
     RECT  90.624 14.293 91.812 14.723 ;
     RECT  74.688 14.389 75.612 14.771 ;
     RECT  78 14.531 78.696 14.771 ;
     RECT  156.3 14.387 163.032 14.963 ;
     RECT  32.1 13.907 32.712 15.059 ;
     RECT  157.968 14.963 163.032 15.587 ;
     RECT  158.544 15.587 163.032 16.115 ;
     RECT  114.528 16.021 114.552 16.307 ;
     RECT  159 16.115 163.032 16.595 ;
     RECT  69.9 7.957 72.912 16.691 ;
     RECT  160.704 16.595 163.032 16.691 ;
     RECT  71.712 16.691 72.912 17.171 ;
     RECT  161.472 16.691 163.032 17.219 ;
     RECT  161.7 17.219 163.032 17.699 ;
     RECT  163.008 17.699 163.032 17.747 ;
     RECT  104.88 11.555 105.768 21.155 ;
     RECT  104.88 21.155 105.312 22.165 ;
     RECT  96.9 12.563 97.368 23.317 ;
     RECT  129.3 14.675 129.612 33.589 ;
     RECT  67.2 4.595 67.512 34.069 ;
     RECT  75.3 14.771 75.612 34.069 ;
     RECT  118.5 5.603 118.812 34.117 ;
     RECT  66.48 34.069 67.512 34.165 ;
     RECT  78 14.771 78.312 34.165 ;
     RECT  104.88 22.165 105.432 34.259 ;
     RECT  86.1 13.091 86.412 34.357 ;
     RECT  83.4 9.539 83.712 34.501 ;
     RECT  126.6 4.787 126.912 34.501 ;
     RECT  118.5 34.117 119.016 34.645 ;
     RECT  121.2 14.483 121.512 34.645 ;
     RECT  128.784 33.589 129.612 34.739 ;
     RECT  85.968 34.357 86.412 34.741 ;
     RECT  107.7 7.475 108.012 34.741 ;
     RECT  121.104 34.645 121.512 34.787 ;
     RECT  121.2 34.787 121.512 34.789 ;
     RECT  96.9 23.317 97.464 34.835 ;
     RECT  118.5 34.645 119.496 34.835 ;
     RECT  106.992 34.741 108.012 34.885 ;
     RECT  113.1 14.675 113.412 34.933 ;
     RECT  115.8 9.587 116.112 34.933 ;
     RECT  115.68 34.933 116.112 35.029 ;
     RECT  77.232 34.165 78.312 35.123 ;
     RECT  96.9 34.835 97.212 35.173 ;
     RECT  66.48 34.165 68.376 35.315 ;
     RECT  115.2 35.029 116.112 35.317 ;
     RECT  83.4 34.501 84.552 35.363 ;
     RECT  90.288 34.981 90.312 35.459 ;
     RECT  66.48 35.315 67.512 35.701 ;
     RECT  118.5 34.835 119.016 35.747 ;
     RECT  118.5 35.747 118.812 35.749 ;
     RECT  123.9 8.243 124.212 35.797 ;
     RECT  96.192 35.173 97.212 35.845 ;
     RECT  105 34.259 105.432 35.845 ;
     RECT  106.944 34.885 108.012 35.845 ;
     RECT  112.56 34.933 113.412 35.845 ;
     RECT  117.936 35.749 118.812 35.845 ;
     RECT  61.8 7.763 62.112 35.893 ;
     RECT  80.7 11.219 81.012 35.893 ;
     RECT  88.8 8.003 89.112 35.893 ;
     RECT  64.5 10.451 64.812 35.989 ;
     RECT  60.864 35.893 62.112 36.085 ;
     RECT  115.2 35.317 116.472 36.227 ;
     RECT  112.512 35.845 113.412 36.325 ;
     RECT  85.92 34.741 86.412 36.373 ;
     RECT  87.888 35.893 89.112 36.373 ;
     RECT  126.6 34.501 127.608 36.373 ;
     RECT  129.3 34.739 129.612 36.373 ;
     RECT  56.4 6.419 57.096 36.421 ;
     RECT  83.4 35.363 83.712 36.421 ;
     RECT  94.2 6.323 94.512 36.421 ;
     RECT  56.4 36.421 57.864 36.469 ;
     RECT  59.1 6.659 59.412 36.469 ;
     RECT  60.864 36.085 62.232 36.469 ;
     RECT  78 35.123 78.312 36.469 ;
     RECT  79.536 35.845 79.56 36.469 ;
     RECT  85.92 36.373 89.112 36.469 ;
     RECT  91.5 14.723 91.812 36.469 ;
     RECT  93.072 36.421 93.096 36.469 ;
     RECT  96.192 35.845 97.56 36.469 ;
     RECT  99.6 13.139 99.912 36.469 ;
     RECT  115.8 36.227 116.472 36.469 ;
     RECT  117.552 35.845 118.812 36.469 ;
     RECT  121.2 34.789 121.896 36.469 ;
     RECT  123.456 35.797 124.212 36.469 ;
     RECT  110.4 6.899 110.712 36.517 ;
     RECT  112.32 36.325 113.412 36.517 ;
     RECT  0.192 22.885 0.216 36.611 ;
     RECT  63.984 35.989 64.812 36.661 ;
     RECT  65.856 35.701 67.512 36.661 ;
     RECT  72.6 17.171 72.912 36.661 ;
     RECT  91.5 36.469 93.096 36.661 ;
     RECT  75.3 34.069 76.104 36.755 ;
     RECT  105 35.845 108.012 36.853 ;
     RECT  91.152 36.661 93.096 36.901 ;
     RECT  101.04 35.845 101.064 36.949 ;
     RECT  102.3 13.139 102.612 36.949 ;
     RECT  105 36.853 108.312 36.997 ;
     RECT  112.32 36.517 114.36 36.997 ;
     RECT  121.2 36.469 124.344 36.997 ;
     RECT  72.096 36.661 72.912 37.045 ;
     RECT  80.7 35.893 81.912 37.045 ;
     RECT  85.728 36.469 89.112 37.045 ;
     RECT  110.112 36.517 110.712 37.045 ;
     RECT  111.696 36.997 114.36 37.045 ;
     RECT  121.2 36.997 124.488 37.045 ;
     RECT  134.7 11.507 135.012 37.045 ;
     RECT  63.984 36.661 67.512 37.093 ;
     RECT  69.9 16.691 70.212 37.093 ;
     RECT  77.712 36.469 78.408 37.093 ;
     RECT  79.44 36.469 79.56 37.093 ;
     RECT  80.544 37.045 81.912 37.093 ;
     RECT  77.712 37.093 81.912 37.189 ;
     RECT  83.4 36.421 83.88 37.189 ;
     RECT  71.808 37.045 72.912 37.381 ;
     RECT  121.104 37.045 124.488 37.429 ;
     RECT  99.6 36.469 100.008 37.477 ;
     RECT  110.112 37.045 114.36 37.525 ;
     RECT  115.8 36.469 118.812 37.525 ;
     RECT  77.712 37.189 83.88 37.573 ;
     RECT  85.68 37.045 89.112 37.573 ;
     RECT  110.112 37.525 118.812 37.573 ;
     RECT  120.96 37.429 124.488 37.573 ;
     RECT  137.4 14.675 137.712 37.573 ;
     RECT  56.4 36.469 62.616 37.621 ;
     RECT  63.792 37.093 67.512 37.621 ;
     RECT  77.424 37.573 83.976 37.621 ;
     RECT  94.08 36.421 94.512 37.621 ;
     RECT  95.616 36.469 97.56 37.621 ;
     RECT  99.12 37.477 100.008 37.621 ;
     RECT  56.4 37.621 68.04 37.669 ;
     RECT  71.184 37.381 72.912 37.669 ;
     RECT  137.28 37.573 137.712 37.907 ;
     RECT  85.68 37.573 89.208 37.957 ;
     RECT  90.432 36.901 93.096 37.957 ;
     RECT  77.328 37.621 83.976 38.005 ;
     RECT  56.4 37.669 68.136 38.197 ;
     RECT  69.6 37.093 70.212 38.197 ;
     RECT  71.184 37.669 73.512 38.197 ;
     RECT  85.68 37.957 93.096 38.197 ;
     RECT  94.08 37.621 100.008 38.197 ;
     RECT  101.04 36.949 102.612 38.197 ;
     RECT  103.584 36.997 108.84 38.197 ;
     RECT  110.112 37.573 124.488 38.197 ;
     RECT  56.4 38.197 73.512 38.243 ;
     RECT  77.328 38.005 84.264 38.485 ;
     RECT  77.328 38.485 84.552 38.629 ;
     RECT  85.68 38.197 124.488 38.629 ;
     RECT  134.7 37.045 135.528 38.677 ;
     RECT  75.3 36.755 75.612 38.725 ;
     RECT  134.544 38.677 135.528 38.821 ;
     RECT  75.3 38.725 76.344 39.253 ;
     RECT  77.328 38.629 124.728 39.253 ;
     RECT  126.6 36.373 129.612 39.253 ;
     RECT  57.84 38.243 73.512 39.301 ;
     RECT  75.3 39.253 124.728 39.301 ;
     RECT  125.712 39.253 129.612 39.301 ;
     RECT  75.3 39.301 129.612 39.395 ;
     RECT  134.544 38.821 136.248 39.637 ;
     RECT  132 11.987 132.312 39.877 ;
     RECT  133.92 39.637 136.248 39.877 ;
     RECT  137.4 37.907 137.712 39.877 ;
     RECT  131.04 39.877 132.312 40.357 ;
     RECT  56.4 38.243 56.712 40.405 ;
     RECT  57.84 39.301 74.04 40.405 ;
     RECT  130.752 40.357 132.312 40.405 ;
     RECT  75.3 39.395 103.704 40.453 ;
     RECT  104.688 39.395 129.612 40.453 ;
     RECT  56.4 40.405 74.04 40.499 ;
     RECT  75.3 40.453 129.612 40.741 ;
     RECT  130.608 40.405 132.312 40.741 ;
     RECT  133.92 39.877 137.712 40.981 ;
     RECT  2.4 2.151 2.712 41.049 ;
     RECT  5.1 2.151 5.412 41.049 ;
     RECT  7.8 2.151 8.112 41.049 ;
     RECT  10.5 2.151 10.812 41.049 ;
     RECT  13.2 2.151 13.512 41.049 ;
     RECT  15.9 2.151 16.212 41.049 ;
     RECT  18.6 3.635 18.912 41.049 ;
     RECT  21.3 6.035 21.612 41.049 ;
     RECT  24 5.267 24.312 41.049 ;
     RECT  26.7 4.163 27.012 41.049 ;
     RECT  29.4 11.219 29.712 41.049 ;
     RECT  32.1 15.059 32.412 41.049 ;
     RECT  34.8 13.331 35.112 41.049 ;
     RECT  37.5 8.003 37.812 41.049 ;
     RECT  40.2 9.587 40.512 41.049 ;
     RECT  42.9 5.219 43.212 41.049 ;
     RECT  45.6 4.451 45.912 41.049 ;
     RECT  48.3 6.611 48.612 41.049 ;
     RECT  51 14.723 51.312 41.049 ;
     RECT  53.7 14.723 54.012 41.049 ;
     RECT  133.344 40.981 137.712 41.049 ;
     RECT  140.1 4.595 140.412 41.049 ;
     RECT  142.8 4.595 143.112 41.049 ;
     RECT  145.5 14.675 145.812 41.049 ;
     RECT  148.2 4.019 148.512 41.049 ;
     RECT  150.9 2.003 151.212 41.049 ;
     RECT  153.6 7.235 153.912 41.049 ;
     RECT  156.3 14.963 156.612 41.049 ;
     RECT  159 16.595 159.312 41.049 ;
     RECT  161.7 17.699 162.012 41.049 ;
     RECT  164.4 8.771 164.712 41.049 ;
     RECT  167.1 8.819 167.412 41.049 ;
     RECT  169.8 7.187 170.112 41.049 ;
     RECT  172.5 4.403 172.812 41.049 ;
     RECT  175.2 2.151 175.512 41.049 ;
     RECT  177.9 2.151 178.212 41.049 ;
     RECT  180.6 2.151 180.912 41.049 ;
     RECT  183.3 2.151 183.612 41.049 ;
     RECT  186 2.151 186.312 41.049 ;
     RECT  2.4 41.049 2.52 41.063 ;
     RECT  5.1 41.049 5.22 41.063 ;
     RECT  7.8 41.049 7.92 41.063 ;
     RECT  10.5 41.049 10.62 41.063 ;
     RECT  13.2 41.049 13.32 41.063 ;
     RECT  15.9 41.049 16.02 41.063 ;
     RECT  18.6 41.049 18.72 41.063 ;
     RECT  21.3 41.049 21.42 41.063 ;
     RECT  24 41.049 24.12 41.063 ;
     RECT  26.7 41.049 26.82 41.063 ;
     RECT  29.4 41.049 29.52 41.063 ;
     RECT  32.1 41.049 32.22 41.063 ;
     RECT  34.8 41.049 34.92 41.063 ;
     RECT  37.5 41.049 37.62 41.063 ;
     RECT  40.2 41.049 40.32 41.063 ;
     RECT  42.9 41.049 43.02 41.063 ;
     RECT  45.6 41.049 45.72 41.063 ;
     RECT  48.3 41.049 48.42 41.063 ;
     RECT  51 41.049 51.12 41.063 ;
     RECT  53.7 41.049 53.82 41.063 ;
     RECT  75.3 40.741 132.312 41.063 ;
     RECT  133.344 41.049 137.52 41.063 ;
     RECT  140.1 41.049 140.22 41.063 ;
     RECT  142.8 41.049 142.92 41.063 ;
     RECT  145.5 41.049 145.62 41.063 ;
     RECT  148.2 41.049 148.32 41.063 ;
     RECT  150.9 41.049 151.02 41.063 ;
     RECT  153.6 41.049 153.72 41.063 ;
     RECT  156.3 41.049 156.42 41.063 ;
     RECT  159 41.049 159.12 41.063 ;
     RECT  161.7 41.049 161.82 41.063 ;
     RECT  164.4 41.049 164.52 41.063 ;
     RECT  167.1 41.049 167.22 41.063 ;
     RECT  169.8 41.049 169.92 41.063 ;
     RECT  172.5 41.049 172.62 41.063 ;
     RECT  175.2 41.049 175.32 41.063 ;
     RECT  177.9 41.049 178.02 41.063 ;
     RECT  180.6 41.049 180.72 41.063 ;
     RECT  183.3 41.049 183.42 41.063 ;
     RECT  186 41.049 186.12 41.063 ;
     RECT  56.4 40.499 56.904 41.557 ;
     RECT  57.888 40.499 74.04 41.557 ;
     RECT  133.344 41.063 137.4 41.557 ;
     RECT  56.4 41.557 74.04 41.605 ;
     RECT  133.056 41.557 137.4 43.045 ;
     RECT  55.728 41.605 74.04 43.152 ;
     RECT  75.312 41.063 131.64 43.152 ;
     RECT  132.912 43.045 137.4 43.152 ;
  END
END qkd_pv_rs_hd
END LIBRARY
